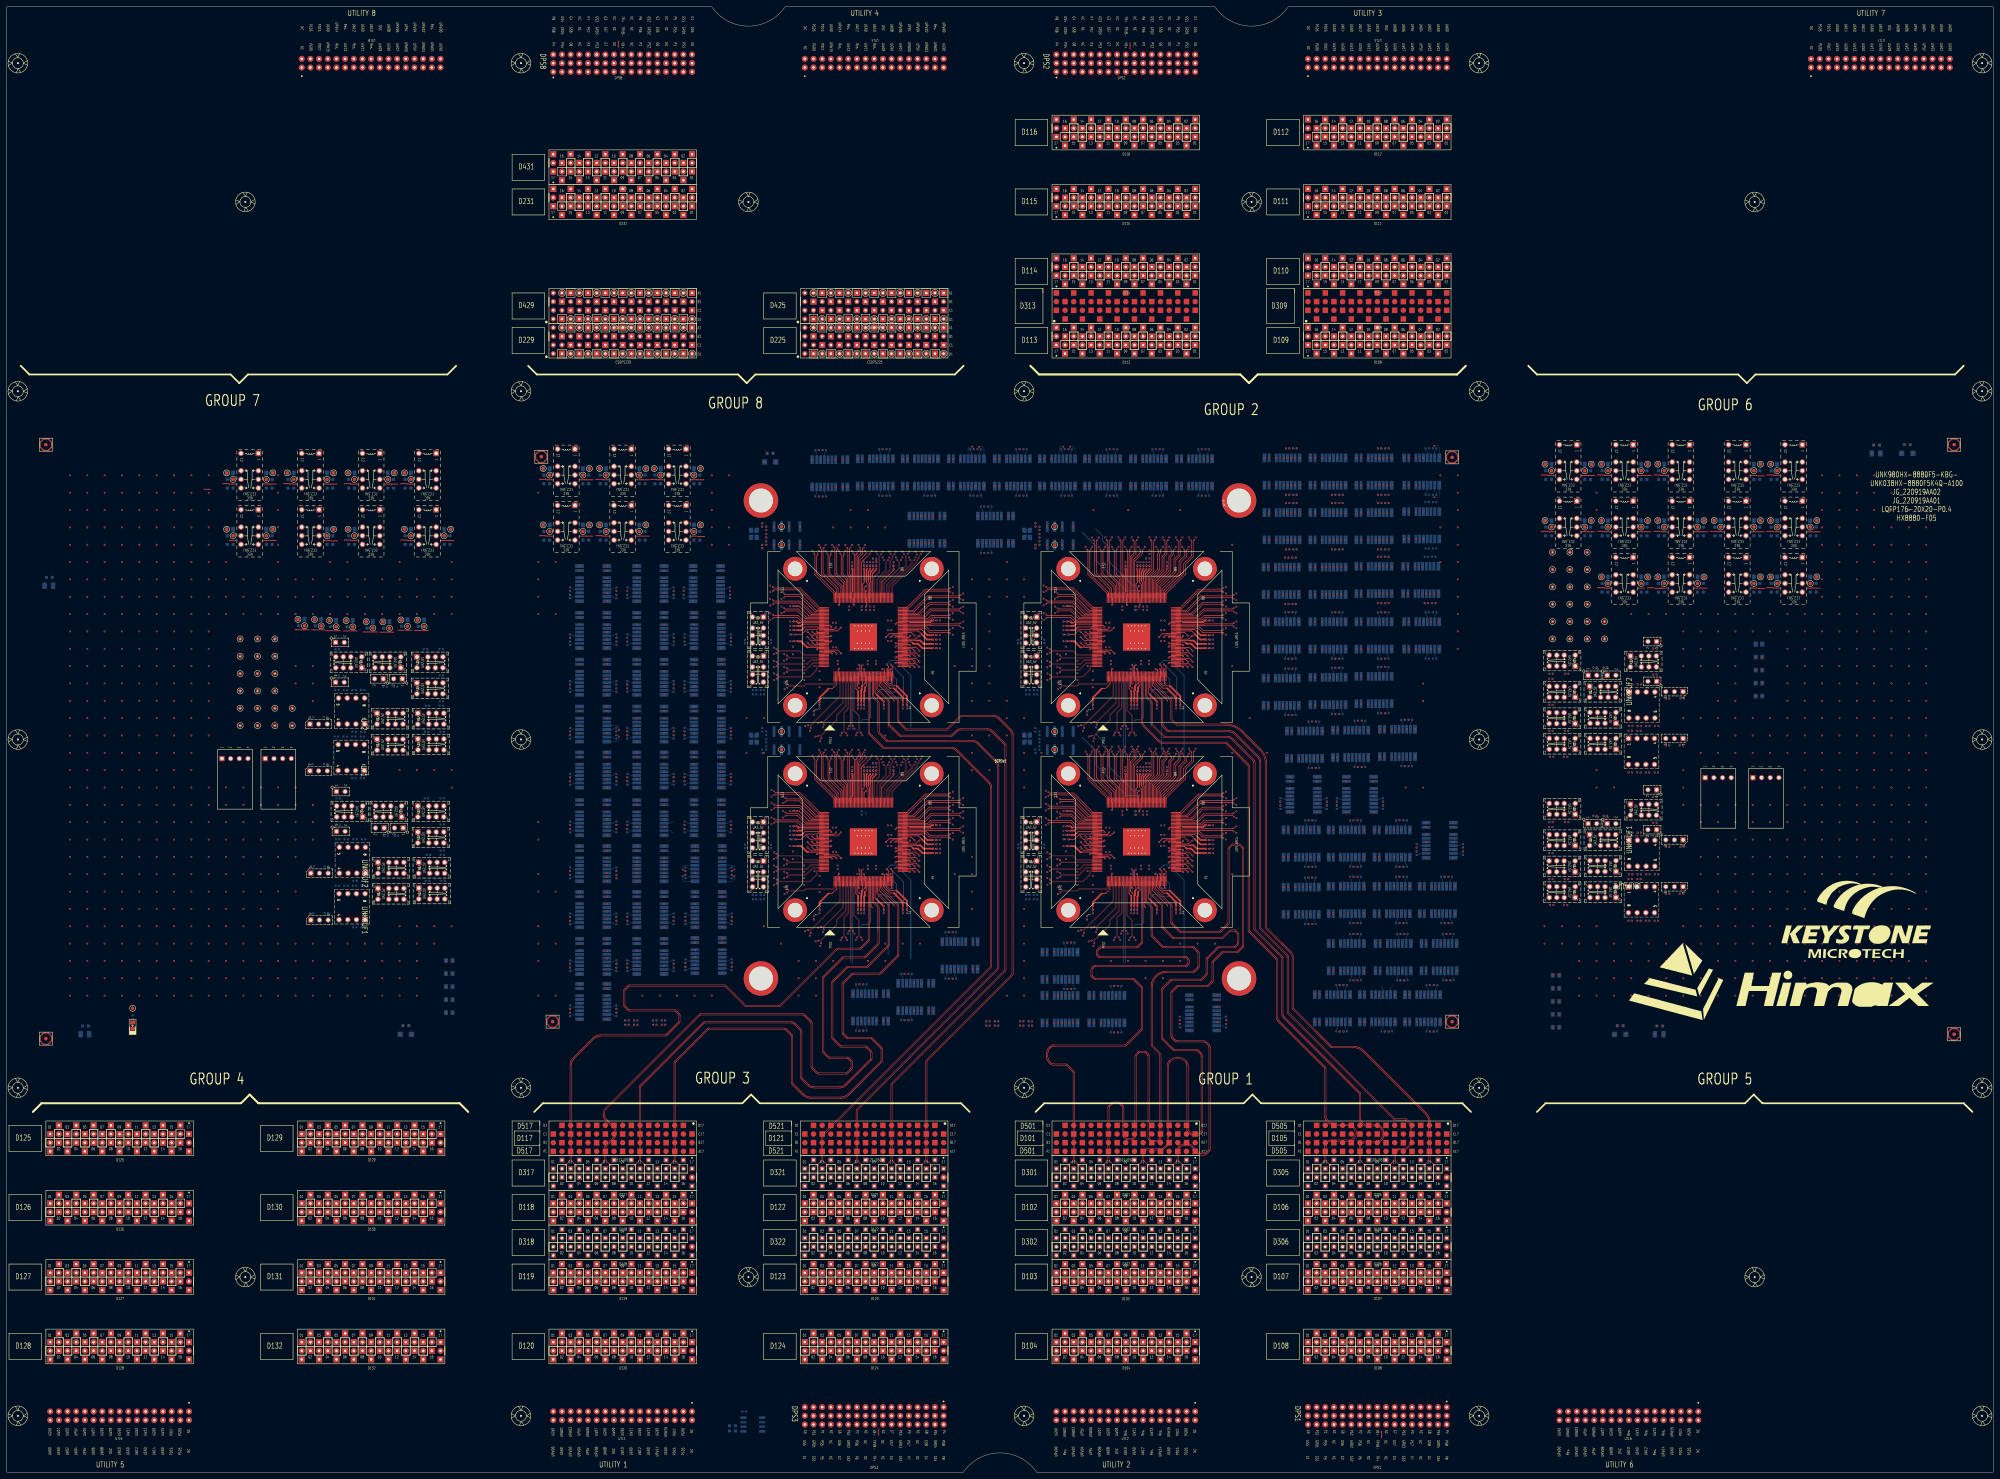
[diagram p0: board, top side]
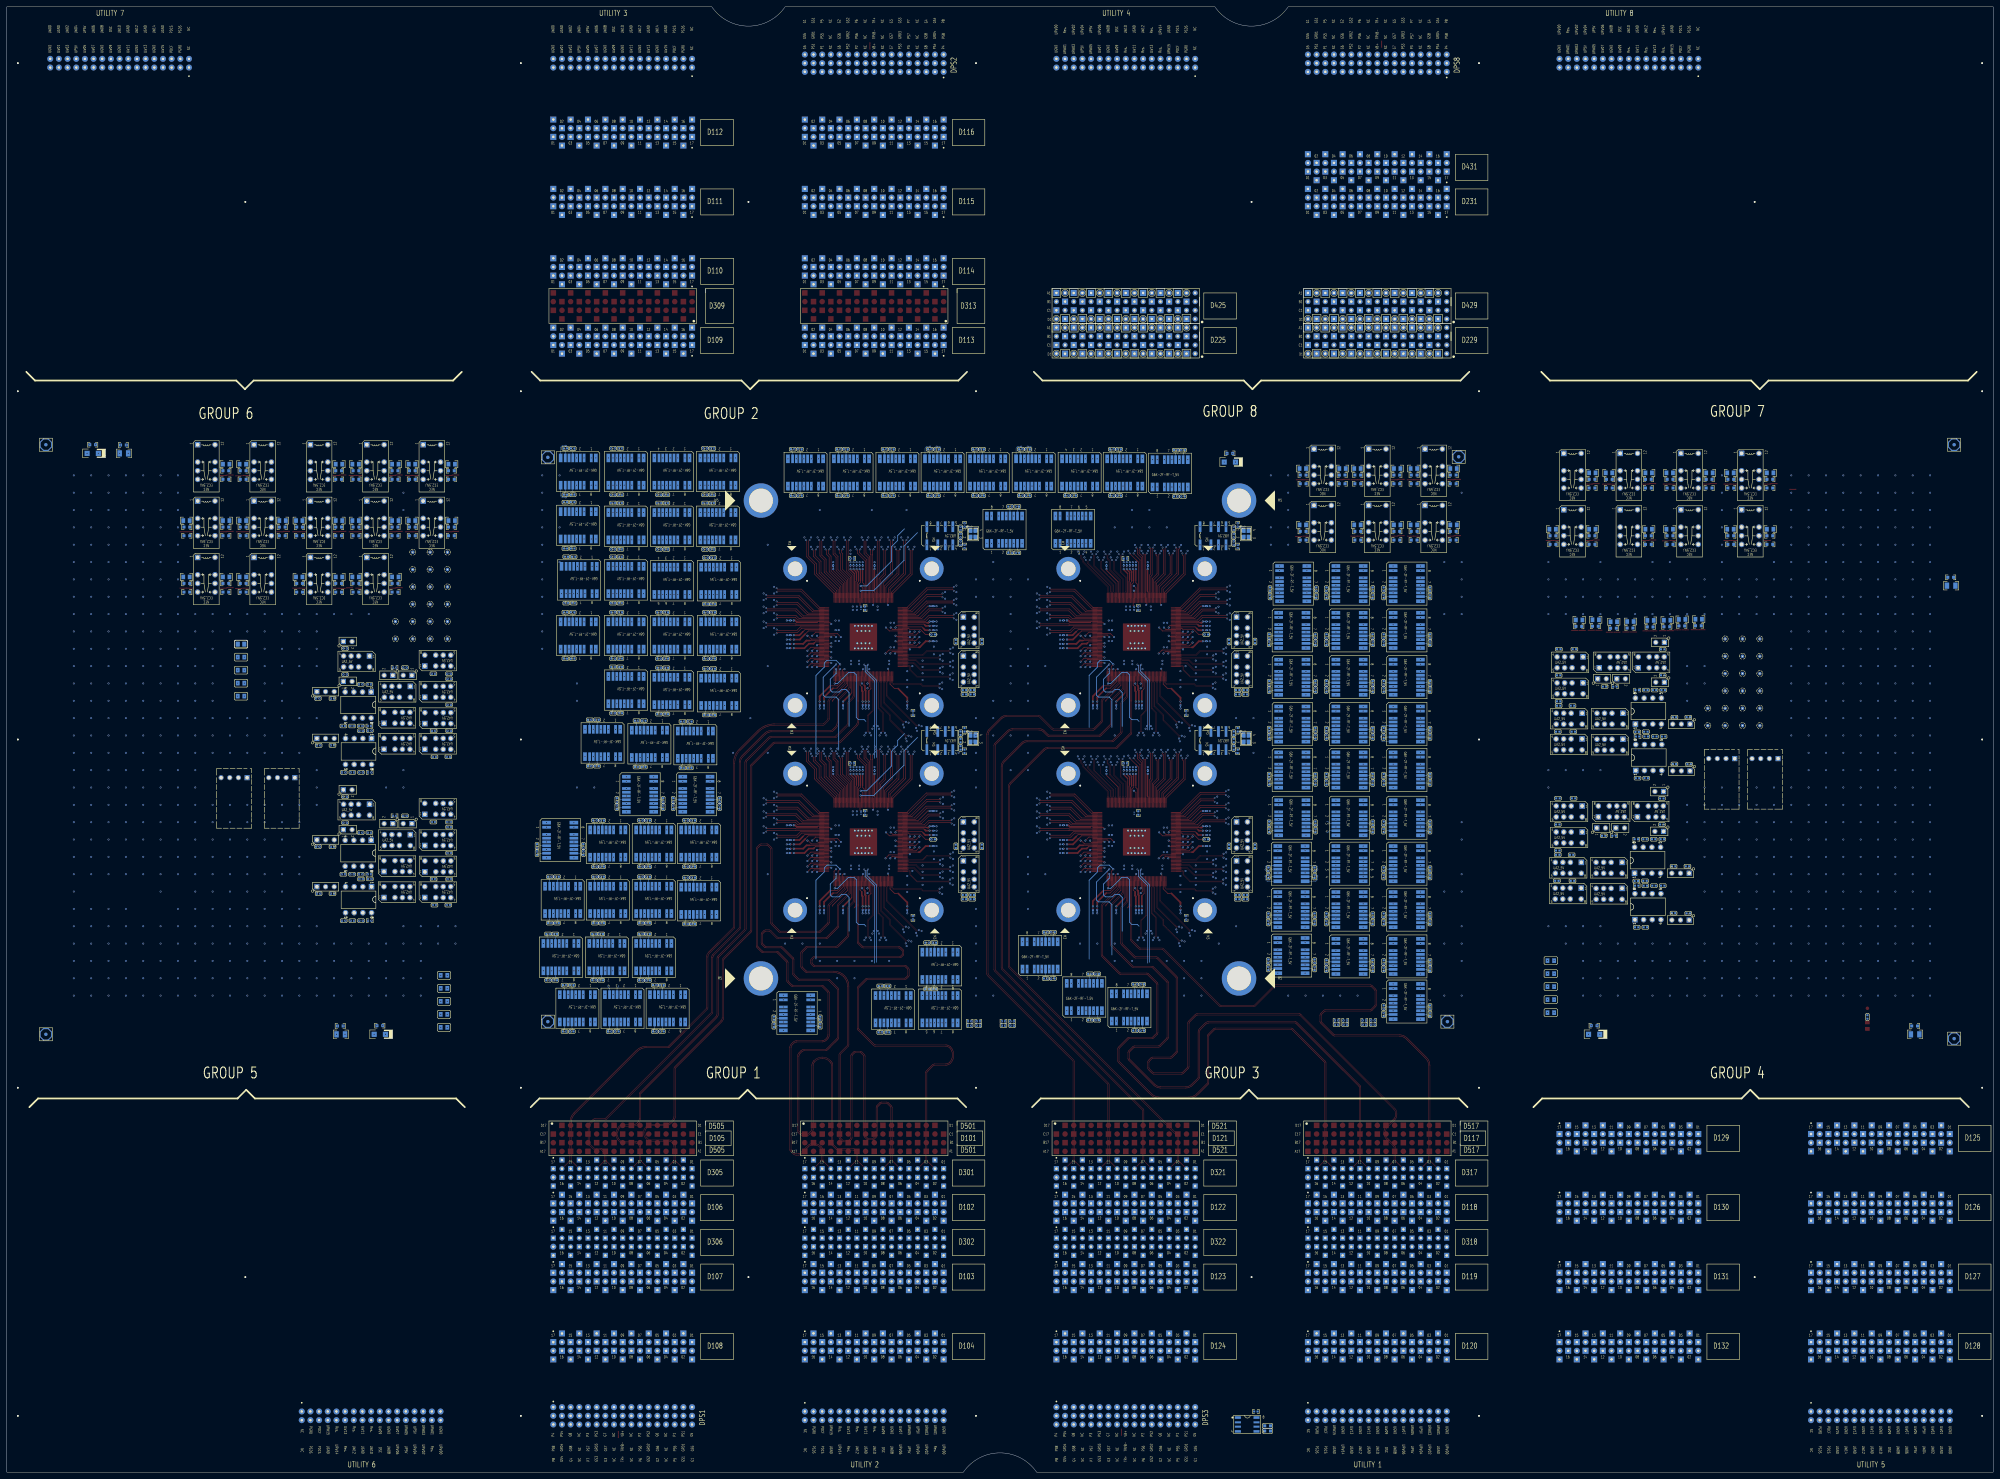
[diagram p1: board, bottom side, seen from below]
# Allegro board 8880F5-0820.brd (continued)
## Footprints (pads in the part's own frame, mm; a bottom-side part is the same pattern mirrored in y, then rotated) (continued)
R0402
  custom 0.15x0.15 smd: 1(-0.5,0) 2(0.5,0)
R0603
  rect 0.889x0.889 smd: 1(-0.85,0) 2(0.85,0)
RL_G6K2FRT_8P_5V_GR
  rect 0.813x2.54 smd: 1(-3.75,-4) 2(-0.55,-4) 3(1.65,-4) 4(3.85,-4) 5(3.85,4) 6(1.65,4) 7(-0.55,4) 8(-3.75,4) G2(-1.65,-4) G3(0.55,-4) G4(2.75,-4) G7(2.75,4) G8(0.55,4) G9(-1.65,4)
  rect 1.092x2.54 smd: G1(-5.1,-4) G5(5.2,-4) G6(5.2,4) G10(-5.1,4)
RL_NECEC2_10P_5V
  rect 1.626x1.626 hole 1.041: 1(6.35,2.54)
  round 1.626 hole 1.041: 3(1.27,2.54) 4(-1.27,2.54) 5(-3.81,2.54) 8(-3.81,-2.54) 9(-1.27,-2.54) 10(1.27,-2.54) 12(6.35,-2.54)
RL_NECUA2_5V_V3
  rect 1.626x1.626 hole 1.041: 1(3.6,1.6)
  round 1.626 hole 1.041: 2(0.4,1.6) 3(-1.8,1.6) 4(-4,1.6) 5(-4,-1.6) 6(-1.8,-1.6) 7(0.4,-1.6) 8(3.6,-1.6)
RL_NECUB2_5V
  rect 0.813x3.15 smd: 1(3.8,2.65) 2(0.6,2.65) 3(-1.6,2.65) 4(-3.8,2.65) 5(-3.8,-2.65) 6(-1.6,-2.65) 7(0.6,-2.65) 8(3.8,-2.65)
SK_LQFP176P_0P4MM_JG_HX8880
  round 0.508 hole 1.626 unplated: (-16.5,16.5) (-16.5,-16.5) (16.5,16.5) (16.5,-16.5)
  oval 3x0.28 smd: 1(-11.5,8.6) 2(-11.5,8.2) 3(-11.5,7.8) 4(-11.5,7.4) 5(-11.5,7) 6(-11.5,6.6) 7(-11.5,6.2) 8(-11.5,5.8) 9(-11.5,5.4) 10(-11.5,5) 11(-11.5,4.6) 12(-11.5,4.2) 13(-11.5,3.8) 14(-11.5,3.4) 15(-11.5,3) 16(-11.5,2.6) 17(-11.5,2.2) 18(-11.5,1.8) 19(-11.5,1.4) 20(-11.5,1) 21(-11.5,0.6) 22(-11.5,0.2) 23(-11.5,-0.2) 24(-11.5,-0.6) 25(-11.5,-1) 26(-11.5,-1.4) 27(-11.5,-1.8) 28(-11.5,-2.2) 29(-11.5,-2.6) 30(-11.5,-3) 31(-11.5,-3.4) 32(-11.5,-3.8) 33(-11.5,-4.2) 34(-11.5,-4.6) 35(-11.5,-5) 36(-11.5,-5.4) 37(-11.5,-5.8) 38(-11.5,-6.2) 39(-11.5,-6.6) 40(-11.5,-7) 41(-11.5,-7.4) 42(-11.5,-7.8) 43(-11.5,-8.2) 44(-11.5,-8.6) 89(11.5,-8.6) 90(11.5,-8.2) 91(11.5,-7.8) 92(11.5,-7.4) 93(11.5,-7) 94(11.5,-6.6) 95(11.5,-6.2) 96(11.5,-5.8) 97(11.5,-5.4) 98(11.5,-5) 99(11.5,-4.6) 100(11.5,-4.2) 101(11.5,-3.8) 102(11.5,-3.4) 103(11.5,-3) 104(11.5,-2.6) 105(11.5,-2.2) 106(11.5,-1.8) 107(11.5,-1.4) 108(11.5,-1) 109(11.5,-0.6) 110(11.5,-0.2) 111(11.5,0.2) 112(11.5,0.6) 113(11.5,1) 114(11.5,1.4) 115(11.5,1.8) 116(11.5,2.2) 117(11.5,2.6) 118(11.5,3) 119(11.5,3.4) 120(11.5,3.8) 121(11.5,4.2) 122(11.5,4.6) 123(11.5,5) 124(11.5,5.4) 125(11.5,5.8) 126(11.5,6.2) 127(11.5,6.6) 128(11.5,7) 129(11.5,7.4) 130(11.5,7.8) 131(11.5,8.2) 132(11.5,8.6)
  oval 0.28x3 smd: 45(-8.6,-11.5) 46(-8.2,-11.5) 47(-7.8,-11.5) 48(-7.4,-11.5) 49(-7,-11.5) 50(-6.6,-11.5) 51(-6.2,-11.5) 52(-5.8,-11.5) 53(-5.4,-11.5) 54(-5,-11.5) 55(-4.6,-11.5) 56(-4.2,-11.5) 57(-3.8,-11.5) 58(-3.4,-11.5) 59(-3,-11.5) 60(-2.6,-11.5) 61(-2.2,-11.5) 62(-1.8,-11.5) 63(-1.4,-11.5) 64(-1,-11.5) 65(-0.6,-11.5) 66(-0.2,-11.5) 67(0.2,-11.5) 68(0.6,-11.5) 69(1,-11.5) 70(1.4,-11.5) 71(1.8,-11.5) 72(2.2,-11.5) 73(2.6,-11.5) 74(3,-11.5) 75(3.4,-11.5) 76(3.8,-11.5) 77(4.2,-11.5) 78(4.6,-11.5) 79(5,-11.5) 80(5.4,-11.5) 81(5.8,-11.5) 82(6.2,-11.5) 83(6.6,-11.5) 84(7,-11.5) 85(7.4,-11.5) 86(7.8,-11.5) 87(8.2,-11.5) 88(8.6,-11.5) 133(8.6,11.5) 134(8.2,11.5) 135(7.8,11.5) 136(7.4,11.5) 137(7,11.5) 138(6.6,11.5) 139(6.2,11.5) 140(5.8,11.5) 141(5.4,11.5) 142(5,11.5) 143(4.6,11.5) 144(4.2,11.5) 145(3.8,11.5) 146(3.4,11.5) 147(3,11.5) 148(2.6,11.5) 149(2.2,11.5) 150(1.8,11.5) 151(1.4,11.5) 152(1,11.5) 153(0.6,11.5) 154(0.2,11.5) 155(-0.2,11.5) 156(-0.6,11.5) 157(-1,11.5) 158(-1.4,11.5) 159(-1.8,11.5) 160(-2.2,11.5) 161(-2.6,11.5) 162(-3,11.5) 163(-3.4,11.5) 164(-3.8,11.5) 165(-4.2,11.5) 166(-4.6,11.5) 167(-5,11.5) 168(-5.4,11.5) 169(-5.8,11.5) 170(-6.2,11.5) 171(-6.6,11.5) 172(-7,11.5) 173(-7.4,11.5) 174(-7.8,11.5) 175(-8.2,11.5) 176(-8.6,11.5)
  rect 8x8 smd: EP(0,0)
  round 0.61 hole 0.305: G1(-3.3,2.5) G2(-3.3,1.5) G3(-3.3,0.5) G4(-3.3,-0.5) G5(-3.3,-1.5) G6(-3.3,-2.5) G7(3.3,2.5) G8(3.3,1.5) G9(3.3,0.5) G10(3.3,-0.5) G11(3.3,-1.5) G12(3.3,-2.5) G13(-1.8,1.8) G14(-1.8,0.6) G15(-1.8,-0.6) G16(-1.8,-1.8) G17(1.8,1.8) G18(1.8,0.6) G19(1.8,-0.6) G20(1.8,-1.8)
  round 7 hole 4.293: NUT1(-20,20) NUT2(20,20) NUT3(-20,-20) NUT4(20,-20)
SO8_215X127MM
  rect 1.778x0.762 smd: 1(-2.731,2.032) 4(-2.731,-2.032) 5(2.731,-2.032) 8(2.731,2.032)
  rect 1.778x0.61 smd: 2(-2.731,0.635) 3(-2.731,-0.635) 6(2.731,-0.635) 7(2.731,0.635)
SOCKET_BASE_140X140_565100
  round 10.109 hole 7.01: NUT1(-70,70) NUT2(70,70) NUT3(70,-70) NUT4(-70,-70)
SOCKET_CODE
  round 0.051 smd: 1(0,0)
TP_040_T
  round 1.016 smd: 1(0,0)
TPL_040_014_TB
  round 1.016 hole 0.356: 1(0,0)
XTAL_2X2P5MM_4P
  rect 1.143x0.94 smd: 1(-0.825,-0.625) 2(0.825,-0.625) 3(0.825,0.625) 4(-0.825,0.625)
XTAL_3P2X2P5MM_4P_TXC_0201
  rect 1.4x1.2 smd: 1(-1.1,-0.85) 2(1.1,-0.85) 3(1.1,0.85) 4(-1.1,0.85)

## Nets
GND: BD29.1 BD30.1 BD31.1 BD32.1 BD33.1 BD34.1 BD35.1 BD36.1 BD37.1 BD38.1 BD39.1 BD40.1 BD41.1 BD42.1 BD43.1 BD44.1 C5.2 C6.2 C7.2 C8.2 C9.2 CA1.2 CA2.2 CA3.2 CA4.2 CA5.2 CA6.2 CA7.2 CA8.2 CA9.2 CA10.2 CA11.2 CA12.2 CA13.2 CA14.2 CA15.2 CA16.2 CA17.2 CA18.2 CA19.2 CA20.2 CA21.2 CA22.2 CA23.2 CA24.2 CA25.2 CA26.2 CA27.2 CA28.2 CA29.2 CA30.2 CA31.2 CA32.2 CA33.2 CA34.2 CA35.2 CA36.2 CA37.2 CA38.2 CA39.2 CA40.2 CC1.2 CC2.2 CC4.2 CC6.2 CC7.2 CC8.2 CC9.2 CC11.2 CC13.2 CC15.2 CC16.2 CC17.2 CC19.2 CC20.2 CC22.2 CC23.2 CC25.2 CC26.2 CC27.2 CC28.2 CC29.2 CC30.2 CC31.2 CC32.2 CC33.2 CC34.2 CC35.2 CC36.2 CC37.2 CC38.2 CC39.2 CC40.2 CC41.2 CC42.2 CD1.2 CD3.2 CD4.2 CD5.2 CD6.2 CD7.2 CD8.2 CD9.2 CD10.2 CD11.2 CD12.2 CD13.2 CD14.2 CD15.2 CD16.2 CD17.2 CD18.2 CD19.2 CD20.2 CD21.2 CD22.2 CD23.2 CD24.2 CD25.2 CSDPS225.B2 CSDPS225.B4 CSDPS225.B6 CSDPS225.B8 CSDPS225.B10 CSDPS225.B12 CSDPS225.B14 CSDPS225.B16 CSDPS225.C1 CSDPS225.C3 CSDPS225.C5 CSDPS225.C7 CSDPS225.C9 CSDPS225.C11 CSDPS225.C13 CSDPS225.C15 CSDPS229.B2 CSDPS229.B4 CSDPS229.B6 CSDPS229.B8 CSDPS229.B10 CSDPS229.B12 CSDPS229.B14 CSDPS229.B16 CSDPS229.C1 CSDPS229.C3 CSDPS229.C5 CSDPS229.C7 CSDPS229.C9 CSDPS229.C11 CSDPS229.C13 CSDPS229.C15 CSDPS425.B2 CSDPS425.B4 CSDPS425.B6 CSDPS425.B8 CSDPS425.B10 CSDPS425.B12 CSDPS425.B14 CSDPS425.B16 CSDPS425.C1 CSDPS425.C3 CSDPS425.C5 CSDPS425.C7 CSDPS425.C9 CSDPS425.C11 CSDPS425.C13 CSDPS425.C15 CSDPS429.B2 CSDPS429.B4 CSDPS429.B6 CSDPS429.B8 CSDPS429.B10 CSDPS429.B12 CSDPS429.B14 CSDPS429.B16 CSDPS429.C1 CSDPS429.C3 CSDPS429.C5 CSDPS429.C7 CSDPS429.C9 CSDPS429.C11 CSDPS429.C13 CSDPS429.C15 D102.A1 D102.A2 D102.A3 D102.A4 D102.A5 D102.A6 D102.A7 D102.A8 D102.A9 D102.A10 D102.A11 D102.A12 D102.A13 D102.A14 D102.A15 D102.A16 D102.B1 D102.B2 D102.B3 D102.B4 D102.B5 D102.B6 D102.B7 D102.B8 D102.B9 D102.B10 D102.B11 D102.B12 D102.B13 D102.B14 D102.B15 D102.B16 D103.A1 D103.A2 D103.A3 D103.A4 D103.A5 D103.A6 D103.A7 D103.A8 D103.A9 D103.A10 D103.A11 D103.A12 D103.A13 D103.A14 D103.A15 D103.A16 D103.B1 D103.B2 D103.B3 D103.B4 D103.B5 D103.B6 D103.B7 D103.B8 D103.B9 D103.B10 D103.B11 D103.B12 D103.B13 D103.B14 D103.B15 D103.B16 D104.A1 D104.A2 D104.A3 D104.A4 D104.A5 D104.A6 D104.A7 D104.A8 D104.A9 D104.A10 D104.A11 D104.A12 D104.A13 D104.A14 D104.A15 D104.A16 D104.B1 D104.B2 D104.B3 D104.B4 D104.B5 D104.B6 D104.B7 D104.B8 D104.B9 D104.B10 D104.B11 D104.B12 D104.B13 D104.B14 D104.B15 D104.B16 D106.A1 D106.A2 D106.A3 D106.A4 D106.A5 D106.A6 D106.A7 D106.A8 D106.A9 D106.A10 D106.A11 D106.A12 D106.A13 D106.A14 D106.A15 D106.A16 D106.B1 D106.B2 D106.B3 D106.B4 D106.B5 D106.B6 D106.B7 D106.B8 D106.B9 D106.B10 D106.B11 D106.B12 D106.B13 D106.B14 D106.B15 D106.B16 D107.A1 D107.A2 D107.A3 D107.A4 D107.A5 D107.A6 D107.A7 D107.A8 D107.A9 D107.A10 D107.A11 D107.A12 D107.A13 D107.A14 D107.A15 D107.A16 D107.B1 D107.B2 D107.B3 D107.B4 D107.B5 D107.B6 D107.B7 D107.B8 D107.B9 D107.B10 D107.B11 D107.B12 D107.B13 D107.B14 D107.B15 D107.B16 D108.A1 D108.A2 D108.A3 D108.A4 D108.A5 D108.A6 D108.A7 D108.A8 D108.A9 D108.A10 D108.A11 D108.A12 D108.A13 D108.A14 D108.A15 D108.A16 D108.B1 D108.B2 D108.B3 D108.B4 D108.B5 D108.B6 D108.B7 D108.B8 D108.B9 D108.B10 D108.B11 D108.B12 D108.B13 D108.B14 D108.B15 D108.B16 D109.A1 D109.A2 D109.A3 D109.A4 D109.A5 D109.A6 D109.A7 D109.A8 D109.A9 D109.A10 D109.A11 D109.A12 D109.A13 D109.A14 D109.A15 D109.A16 D109.B1 D109.B2 D109.B3 D109.B4 D109.B5 D109.B6 D109.B7 D109.B8 D109.B9 D109.B10 D109.B11 D109.B12 D109.B13 D109.B14 D109.B15 D109.B16 D110.A1 D110.A2 D110.A3 D110.A4 D110.A5 D110.A6 D110.A7 D110.A8 D110.A9 D110.A10 D110.A11 D110.A12 D110.A13 D110.A14 D110.A15 D110.A16 D110.B1 D110.B2 D110.B3 D110.B4 D110.B5 D110.B6 D110.B7 D110.B8 D110.B9 D110.B10 D110.B11 D110.B12 D110.B13 D110.B14 D110.B15 D110.B16 D111.A1 D111.A2 D111.A3 D111.A4 D111.A5 D111.A6 D111.A7 D111.A8 D111.A9 D111.A10 D111.A11 D111.A12 D111.A13 D111.A14 D111.A15 D111.A16 D111.B1 D111.B2 D111.B3 D111.B4 D111.B5 D111.B6 D111.B7 D111.B8 D111.B9 D111.B10 D111.B11 D111.B12 D111.B13 D111.B14 D111.B15 D111.B16 D112.A1 D112.A2 D112.A3 D112.A4 D112.A5 D112.A6 D112.A7 D112.A8 D112.A9 D112.A10 D112.A11 D112.A12 D112.A13 D112.A14 D112.A15 D112.A16 D112.B1 D112.B2 D112.B3 D112.B4 D112.B5 D112.B6 D112.B7 D112.B8 D112.B9 D112.B10 D112.B11 D112.B12 D112.B13 D112.B14 D112.B15 D112.B16 D113.A1 D113.A2 D113.A3 D113.A4 D113.A5 D113.A6 D113.A7 D113.A8 D113.A9 D113.A10 D113.A11 D113.A12 D113.A13 D113.A14 D113.A15 D113.A16 D113.B1 D113.B2 D113.B3 D113.B4 D113.B5 D113.B6 D113.B7 D113.B8 D113.B9 D113.B10 D113.B11 D113.B12 D113.B13 D113.B14 D113.B15 D113.B16 D114.A1 D114.A2 D114.A3 D114.A4 D114.A5 D114.A6 D114.A7 D114.A8 D114.A9 D114.A10 D114.A11 D114.A12 D114.A13 D114.A14 D114.A15 D114.A16 D114.B1 D114.B2 D114.B3 D114.B4 D114.B5 D114.B6 D114.B7 D114.B8 D114.B9 D114.B10 D114.B11 D114.B12 D114.B13 D114.B14 D114.B15 D114.B16 D115.A1 D115.A2 D115.A3 D115.A4 D115.A5 D115.A6 D115.A7 D115.A8 D115.A9 D115.A10 D115.A11 D115.A12 D115.A13 D115.A14 D115.A15 D115.A16 D115.B1 D115.B2 D115.B3 D115.B4 D115.B5 D115.B6 D115.B7 D115.B8 D115.B9 D115.B10 D115.B11 D115.B12 D115.B13 D115.B14 D115.B15 D115.B16 D116.A1 D116.A2 D116.A3 D116.A4 D116.A5 D116.A6 D116.A7 D116.A8 D116.A9 D116.A10 D116.A11 D116.A12 D116.A13 D116.A14 D116.A15 D116.A16 D116.B1 D116.B2 D116.B3 D116.B4 D116.B5 D116.B6 D116.B7 D116.B8 D116.B9 D116.B10 D116.B11 D116.B12 D116.B13 D116.B14 D116.B15 D116.B16 D118.A1 D118.A2 D118.A3 D118.A4 D118.A5 D118.A6 D118.A7 D118.A8 D118.A9 D118.A10 D118.A11 D118.A12 D118.A13 D118.A14 D118.A15 D118.A16 D118.B1 D118.B2 D118.B3 D118.B4 D118.B5 D118.B6 D118.B7 D118.B8 D118.B9 D118.B10 D118.B11 D118.B12 D118.B13 D118.B14 D118.B15 D118.B16 D119.A1 D119.A2 D119.A3 D119.A4 D119.A5 D119.A6 D119.A7 D119.A8 D119.A9 D119.A10 D119.A11 D119.A12 D119.A13 D119.A14 D119.A15 D119.A16 D119.B1 D119.B2 D119.B3 D119.B4 D119.B5 D119.B6 D119.B7 D119.B8 D119.B9 D119.B10 D119.B11 D119.B12 D119.B13 D119.B14 D119.B15 D119.B16 D120.A1 D120.A2 D120.A3 D120.A4 D120.A5 D120.A6 D120.A7 D120.A8 D120.A9 D120.A10 D120.A11 D120.A12 D120.A13 D120.A14 D120.A15 D120.A16 D120.B1 D120.B2 D120.B3 D120.B4 D120.B5 D120.B6 D120.B7 D120.B8 D120.B9 D120.B10 D120.B11 D120.B12 D120.B13 D120.B14 D120.B15 D120.B16 D122.A1 D122.A2 D122.A3 D122.A4 D122.A5 D122.A6 D122.A7 D122.A8 D122.A9 D122.A10 D122.A11 D122.A12 D122.A13 D122.A14 D122.A15 D122.A16 D122.B1 D122.B2 D122.B3 D122.B4 D122.B5 D122.B6 D122.B7 D122.B8 D122.B9 D122.B10 D122.B11 D122.B12 D122.B13 D122.B14 D122.B15 D122.B16 D123.A1 D123.A2 D123.A3 D123.A4 D123.A5 D123.A6 D123.A7 D123.A8 D123.A9 D123.A10 D123.A11 D123.A12 D123.A13 D123.A14 D123.A15 D123.A16 D123.B1 D123.B2 D123.B3 D123.B4 D123.B5 D123.B6 D123.B7 D123.B8 D123.B9 D123.B10 D123.B11 D123.B12 D123.B13 D123.B14 D123.B15 D123.B16 D124.A1 D124.A2 D124.A3 D124.A4 D124.A5 D124.A6 D124.A7 D124.A8 D124.A9 D124.A10 D124.A11 D124.A12 D124.A13 D124.A14 D124.A15 D124.A16 D124.B1 D124.B2 D124.B3 D124.B4 D124.B5 D124.B6 D124.B7 D124.B8 D124.B9 D124.B10 D124.B11 D124.B12 D124.B13 D124.B14 D124.B15 D124.B16 D125.A1 D125.A2 D125.A3 D125.A4 D125.A5 D125.A6 D125.A7 D125.A8 D125.A9 D125.A10 D125.A11 D125.A12 D125.A13 D125.A14 D125.A15 D125.A16 D125.B1 D125.B2 D125.B3 D125.B4 D125.B5 D125.B6 D125.B7 D125.B8 D125.B9 D125.B10 D125.B11 D125.B12 D125.B13 D125.B14 D125.B15 D125.B16 D126.A1 D126.A2 D126.A3 D126.A4 D126.A5 D126.A6 D126.A7 D126.A8 D126.A9 D126.A10 D126.A11 D126.A12 D126.A13 D126.A14 D126.A15 D126.A16 D126.B1 D126.B2 D126.B3 D126.B4 D126.B5 D126.B6 D126.B7 D126.B8 D126.B9 D126.B10 D126.B11 D126.B12 D126.B13 D126.B14 D126.B15 D126.B16 D127.A1 D127.A2 D127.A3 D127.A4 D127.A5 D127.A6 D127.A7 D127.A8 D127.A9 D127.A10 D127.A11 D127.A12 D127.A13 D127.A14 D127.A15 D127.A16 D127.B1 D127.B2 D127.B3 D127.B4 D127.B5 D127.B6 D127.B7 D127.B8 D127.B9 D127.B10 D127.B11 D127.B12 D127.B13 D127.B14 D127.B15 D127.B16 D128.A1 D128.A2 D128.A3 D128.A4 D128.A5 D128.A6 D128.A7 D128.A8 D128.A9 D128.A10 D128.A11 D128.A12 D128.A13 D128.A14 D128.A15 D128.A16 D128.B1 D128.B2 D128.B3 D128.B4 D128.B5 D128.B6 D128.B7 D128.B8 D128.B9 D128.B10 D128.B11 D128.B12 D128.B13 D128.B14 D128.B15 D128.B16 D129.A1 D129.A2 D129.A3 D129.A4 D129.A5 D129.A6 D129.A7 D129.A8 D129.A9 D129.A10 D129.A11 D129.A12 D129.A13 D129.A14 D129.A15 D129.A16 D129.B1 D129.B2 D129.B3 D129.B4 D129.B5 D129.B6 D129.B7 D129.B8 D129.B9 D129.B10 D129.B11 D129.B12 D129.B13 D129.B14 D129.B15 D129.B16 D130.A1 D130.A2 D130.A3 D130.A4 D130.A5 D130.A6 D130.A7 D130.A8 D130.A9 D130.A10 D130.A11 D130.A12 D130.A13 D130.A14 D130.A15 D130.A16 D130.B1 D130.B2 D130.B3 D130.B4 D130.B5 D130.B6 D130.B7 D130.B8 D130.B9 D130.B10 D130.B11 D130.B12 D130.B13 D130.B14 D130.B15 D130.B16 D131.A1 D131.A2 D131.A3 D131.A4 D131.A5 D131.A6 D131.A7 D131.A8 D131.A9 D131.A10 D131.A11 D131.A12 D131.A13 D131.A14 D131.A15 D131.A16 D131.B1 D131.B2 D131.B3 D131.B4 D131.B5 D131.B6 D131.B7 D131.B8 D131.B9 D131.B10 D131.B11 D131.B12 D131.B13 D131.B14 D131.B15 D131.B16 D132.A1 D132.A2 D132.A3 D132.A4 D132.A5 D132.A6 D132.A7 D132.A8 D132.A9 D132.A10 D132.A11 D132.A12 D132.A13 D132.A14 D132.A15 D132.A16 D132.B1 D132.B2 D132.B3 D132.B4 D132.B5 D132.B6 D132.B7 D132.B8 D132.B9 D132.B10 D132.B11 D132.B12 D132.B13 D132.B14 D132.B15 D132.B16 D231.A1 D231.A2 D231.A3 D231.A4 D231.A5 D231.A6 D231.A7 D231.A8 D231.A9 D231.A10 D231.A11 D231.A12 D231.A13 D231.A14 D231.A15 D231.A16 D231.A17 D231.B1 D231.B2 D231.B3 D231.B4 D231.B5 D231.B6 D231.B7 D231.B8 D231.B9 D231.B10 D231.B11 D231.B12 D231.B13 D231.B14 D231.B15 D231.B16 D231.B17 D301.A1 D301.A2 D301.A3 D301.A4 D301.A5 D301.A6 D301.A7 D301.A8 D301.A9 D301.A10 D301.A11 D301.A12 D301.A13 D301.A14 D301.A15 D301.A16 D301.B1 D301.B2 D301.B3 D301.B4 D301.B5 D301.B6 D301.B7 D301.B8 D301.B9 D301.B10 D301.B11 D301.B12 D301.B13 D301.B14 D301.B15 D301.B16 D302.A1 D302.A2 D302.A3 D302.A4 D302.A5 D302.A6 D302.A7 D302.A8 D302.A9 D302.A10 D302.A11 D302.A12 D302.A13 D302.A14 D302.A15 D302.A16 D302.B1 D302.B2 D302.B3 D302.B4 D302.B5 D302.B6 D302.B7 D302.B8 D302.B9 D302.B10 D302.B11 D302.B12 D302.B13 D302.B14 D302.B15 D302.B16 D305.A1 D305.A2 D305.A3 D305.A4 D305.A5 D305.A6 D305.A7 D305.A8 D305.A9 D305.A10 D305.A11 D305.A12 D305.A13 D305.A14 D305.A15 D305.A16 D305.B1 D305.B2 D305.B3 D305.B4 D305.B5 D305.B6 D305.B7 D305.B8 D305.B9 D305.B10 D305.B11 D305.B12 D305.B13 D305.B14 D305.B15 D305.B16 D306.A1 D306.A2 D306.A3 D306.A4 D306.A5 D306.A6 D306.A7 D306.A8 D306.A9 D306.A10 D306.A11 D306.A12 D306.A13 D306.A14 D306.A15 D306.A16 D306.B1 D306.B2 D306.B3 D306.B4 D306.B5 D306.B6 D306.B7 D306.B8 D306.B9 D306.B10 D306.B11 D306.B12 D306.B13 D306.B14 D306.B15 D306.B16 D317.A1 D317.A2 D317.A3 D317.A4 D317.A5 D317.A6 D317.A7 D317.A8 D317.A9 D317.A10 D317.A11 D317.A12 D317.A13 D317.A14 D317.A15 D317.A16 D317.B1 D317.B2 D317.B3 D317.B4 D317.B5 D317.B6 D317.B7 D317.B8 D317.B9 D317.B10 D317.B11 D317.B12 D317.B13 D317.B14 D317.B15 D317.B16 D318.A1 D318.A2 D318.A3 D318.A4 D318.A5 D318.A6 D318.A7 D318.A8 D318.A9 D318.A10 D318.A11 D318.A12 D318.A13 D318.A14 D318.A15 D318.A16 D318.B1 D318.B2 D318.B3 D318.B4 D318.B5 D318.B6 D318.B7 D318.B8 D318.B9 D318.B10 D318.B11 D318.B12 D318.B13 D318.B14 D318.B15 D318.B16 D321.A1 D321.A2 D321.A3 D321.A4 D321.A5 D321.A6 D321.A7 D321.A8 D321.A9 D321.A10 D321.A11 D321.A12 D321.A13 D321.A14 D321.A15 D321.A16 D321.B1 D321.B2 D321.B3 D321.B4 D321.B5 D321.B6 D321.B7 D321.B8 D321.B9 D321.B10 D321.B11 D321.B12 D321.B13 D321.B14 D321.B15 D321.B16 D322.A1 D322.A2 D322.A3 D322.A4 D322.A5 D322.A6 D322.A7 D322.A8 D322.A9 D322.A10 D322.A11 D322.A12 D322.A13 D322.A14 D322.A15 D322.A16 D322.B1 D322.B2 D322.B3 D322.B4 D322.B5 D322.B6 D322.B7 D322.B8 D322.B9 D322.B10 D322.B11 D322.B12 D322.B13 D322.B14 D322.B15 D322.B16 D431.A1 D431.A2 D431.A3 D431.A4 D431.A5 D431.A6 D431.A7 D431.A8 D431.A9 D431.A10 D431.A11 D431.A12 D431.A13 D431.A14 D431.A15 D431.A16 D431.A17 D431.B1 D431.B2 D431.B3 D431.B4 D431.B5 D431.B6 D431.B7 D431.B8 D431.B9 D431.B10 D431.B11 D431.B12 D431.B13 D431.B14 D431.B15 D431.B16 D431.B17 DPS1.A01 DPS1.A05 DPS1.A11 DPS1.A15 DPS1.C01 DPS1.C05 DPS1.C11 DPS1.C15 DPS2.A01 DPS2.A05 DPS2.A11 DPS2.A15 DPS2.C01 DPS2.C05 DPS2.C11 DPS2.C15 DPS3.A01 DPS3.A05 DPS3.A11 DPS3.A15 DPS3.C01 DPS3.C05 DPS3.C11 DPS3.C15 DPS8.A01 DPS8.A05 DPS8.A11 DPS8.A15 DPS8.C01 DPS8.C05 DPS8.C11 DPS8.C15 GND1.1(TP) GND2.1(TP) GND3.1(TP) GND4.1(TP) GND5.1(TP) GND6.1(TP) GND7.1(TP) GND8.1(TP) GND9.1(TP) GND10.1(TP) GND11.1(TP) GND12.1(TP) GND13.1(TP) GND14.1(TP) K1.G1 K1.G2 K1.G3 K1.G4 K1.G5 K1.G6 K1.G7 K1.G8 K1.G9 K1.G10 K2.G1 K2.G2 K2.G3 K2.G4 K2.G5 K2.G6 K2.G7 K2.G8 K2.G9 K2.G10 K3.G1 K3.G2 K3.G3 K3.G4 K3.G5 K3.G6 K3.G7 K3.G8 K3.G9 K3.G10 K4.G1 K4.G2 K4.G3 K4.G4 K4.G5 K4.G6 K4.G7 K4.G8 K4.G9 K4.G10 K5.G1 K5.G2 K5.G3 K5.G4 K5.G5 K5.G6 K5.G7 K5.G8 K5.G9 K5.G10 K6.G1 K6.G2 K6.G3 K6.G4 K6.G5 K6.G6 K6.G7 K6.G8 K6.G9 K6.G10 K7.G1 K7.G2 K7.G3 K7.G4 K7.G5 K7.G6 K7.G7 K7.G8 K7.G9 K7.G10 K8.G1 K8.G2 K8.G3 K8.G4 K8.G5 K8.G6 K8.G7 K8.G8 K8.G9 K8.G10 K11.G1 K11.G2 K11.G3 K11.G4 K11.G5 K11.G6 K11.G7 K11.G8 K11.G9 K11.G10 K16.G1 K16.G2 K16.G3 K16.G4 K16.G5 K16.G6 K16.G7 K16.G8 K16.G9 K16.G10 K17.G1 K17.G2 K17.G3 K17.G4 K17.G5 K17.G6 K17.G7 K17.G8 K17.G9 K17.G10 K21.G1 K21.G2 K21.G3 K21.G4 K21.G5 K21.G6 K21.G7 K21.G8 K21.G9 K21.G10 K22.G1 K22.G2 K22.G3 K22.G4 K22.G5 K22.G6 K22.G7 K22.G8 K22.G9 K22.G10 K23.G1 K23.G2 K23.G3 K23.G4 K23.G5 K23.G6 K23.G7 K23.G8 K23.G9 K23.G10 K24.G1 K24.G2 K24.G3 K24.G4 K24.G5 K24.G6 K24.G7 K24.G8 K24.G9 K24.G10 K25.G1 K25.G2 K25.G3 K25.G4 K25.G5 K25.G6 K25.G7 K25.G8 K25.G9 K25.G10 K26.G1 K26.G2 K26.G3 K26.G4 K26.G5 K26.G6 K26.G7 K26.G8 K26.G9 K26.G10 K27.G1 K27.G2 K27.G3 K27.G4 K27.G5 K27.G6 K27.G7 K27.G8 K27.G9 K27.G10 K29.G1 K29.G2 K29.G3 K29.G4 K29.G5 K29.G6 K29.G7 K29.G8 K29.G9 K29.G10 K30.G1 K30.G2 K30.G3 K30.G4 K30.G5 K30.G6 K30.G7 K30.G8 K30.G9 K30.G10 K43.G1 K43.G2 K43.G3 K43.G4 K43.G5 K43.G6 K43.G7 K43.G8 K43.G9 K43.G10 R2.1 R3.2 R86.2 R93.2 R117.2 R131.2 R132.2 S1_I2C.4 S2_I2C.4 S3_I2C.4 S4_I2C.4 SB1.1 SB2.1 SB3.1 SB8.1 SH2.1 SH4.1 SH6.1 SH8.1 SH9.1 SH11.1 SH13.1 SH15.1 SH17.1 SH19.1 SH21.1 SH24.1 SH26.1 SH28.1 SITE1.4(GND-1) SITE1.23(VSS-1) SITE1.28(AVSS-1) SITE1.34(AVSS-2) SITE1.38(GND-2) SITE1.62(VSS-2) SITE1.108(GND-3) SITE1.128(GND-4) SITE1.146(VSS11_C) SITE1.EP(EP(GND)) SITE1.G1 SITE1.G2 SITE1.G3 SITE1.G4 SITE1.G5 SITE1.G6 SITE1.G7 SITE1.G8 SITE1.G9 SITE1.G10 SITE1.G11 SITE1.G12 SITE1.G13 SITE1.G14 SITE1.G15 SITE1.G16 SITE1.G17 SITE1.G18 SITE1.G19 SITE1.G20 SITE2.4(GND-1) SITE2.23(VSS-1) SITE2.28(AVSS-1) SITE2.34(AVSS-2) SITE2.38(GND-2) SITE2.62(VSS-2) SITE2.108(GND-3) SITE2.128(GND-4) SITE2.146(VSS11_C) SITE2.EP(EP(GND)) SITE2.G1 SITE2.G2 SITE2.G3 SITE2.G4 SITE2.G5 SITE2.G6 SITE2.G7 SITE2.G8 SITE2.G9 SITE2.G10 SITE2.G11 SITE2.G12 SITE2.G13 SITE2.G14 SITE2.G15 SITE2.G16 SITE2.G17 SITE2.G18 SITE2.G19 SITE2.G20 SITE3.4(GND-1) SITE3.23(VSS-1) SITE3.28(AVSS-1) SITE3.34(AVSS-2) SITE3.38(GND-2) SITE3.62(VSS-2) SITE3.108(GND-3) SITE3.128(GND-4) SITE3.146(VSS11_C) SITE3.EP(EP(GND)) SITE3.G1 SITE3.G2 SITE3.G3 SITE3.G4 SITE3.G5 SITE3.G6 SITE3.G7 SITE3.G8 SITE3.G9 SITE3.G10 SITE3.G11 SITE3.G12 SITE3.G13 SITE3.G14 SITE3.G15 SITE3.G16 SITE3.G17 SITE3.G18 SITE3.G19 SITE3.G20 SITE4.4(GND-1) SITE4.23(VSS-1) SITE4.28(AVSS-1) SITE4.34(AVSS-2) SITE4.38(GND-2) SITE4.62(VSS-2) SITE4.108(GND-3) SITE4.128(GND-4) SITE4.146(VSS11_C) SITE4.EP(EP(GND)) SITE4.G1 SITE4.G2 SITE4.G3 SITE4.G4 SITE4.G5 SITE4.G6 SITE4.G7 SITE4.G8 SITE4.G9 SITE4.G10 SITE4.G11 SITE4.G12 SITE4.G13 SITE4.G14 SITE4.G15 SITE4.G16 SITE4.G17 SITE4.G18 SITE4.G19 SITE4.G20 U1.4(GND) U2.4(GND) UNK2C5.2 UNK2C6.2 UNK2C7.2 UNK2C8.2 UNK2C9.2 UNK2CA1.2 UNK2CA2.2 UNK2CA3.2 UNK2CA4.2 UNK2CA5.2 UNK2CA6.2 UNK2CA7.2 UNK2CA8.2 UNK2CA9.2 UNK2CA10.2 UNK2CA11.2 UNK2CA12.2 UNK2CA13.2 UNK2CA14.2 UNK2CA15.2 UNK2CA16.2 UNK2CA17.2 UNK2CA18.2 UNK2CA19.2 UNK2CA20.2 UNK2CA21.2 UNK2CA22.2 UNK2CA23.2 UNK2CA24.2 UNK2CA25.2 UNK2CA26.2 UNK2CA27.2 UNK2CA28.2 UNK2CA29.2 UNK2CA30.2 UNK2CA31.2 UNK2CA32.2 UNK2CA33.2 UNK2CA34.2 UNK2CA35.2 UNK2CA36.2 UNK2CA37.2 UNK2CA38.2 UNK2CA39.2 UNK2CA40.2 UNK2CC1.2 UNK2CC2.2 UNK2CC4.2 UNK2CC6.2 UNK2CC7.2 UNK2CC8.2 UNK2CC9.2 UNK2CC11.2 UNK2CC13.2 UNK2CC15.2 UNK2CC16.2 UNK2CC17.2 UNK2CC19.2 UNK2CC20.2 UNK2CC22.2 UNK2CC23.2 UNK2CC25.2 UNK2CC26.2 UNK2CC27.2 UNK2CC28.2 UNK2CC29.2 UNK2CC30.2 UNK2CC31.2 UNK2CC32.2 UNK2CC33.2 UNK2CC34.2 UNK2CC35.2 UNK2CC36.2 UNK2CC37.2 UNK2CC38.2 UNK2CC39.2 UNK2CC40.2 UNK2CC41.2 UNK2CC42.2 UNK2CD1.2 UNK2CD3.2 UNK2CD4.2 UNK2CD5.2 UNK2CD6.2 UNK2CD7.2 UNK2CD8.2 UNK2CD9.2 UNK2CD10.2 UNK2CD11.2 UNK2CD12.2 UNK2CD13.2 UNK2CD14.2 UNK2CD15.2 UNK2CD16.2 UNK2CD17.2 UNK2CD18.2 UNK2CD19.2 UNK2CD20.2 UNK2CD21.2 UNK2CD22.2 UNK2CD23.2 UNK2CD24.2 UNK2CD25.2 UNK2GND1.1 UNK2GND2.1 UNK2GND3.1 UNK2GND4.1 UNK2GND5.1 UNK2GND6.1 UNK2GND7.1 UNK2GND8.1 UNK2GND9.1 UNK2GND10.1 UNK2GND11.1 UNK2GND12.1 UNK2GND13.1 UNK2GND14.1 UNK2K1.G1 UNK2K1.G2 UNK2K1.G3 UNK2K1.G4 UNK2K1.G5 UNK2K1.G6 UNK2K1.G7 UNK2K1.G8 UNK2K1.G9 UNK2K1.G10 UNK2K2.G1 UNK2K2.G2 UNK2K2.G3 UNK2K2.G4 UNK2K2.G5 UNK2K2.G6 UNK2K2.G7 UNK2K2.G8 UNK2K2.G9 UNK2K2.G10 UNK2K3.G1 UNK2K3.G2 UNK2K3.G3 UNK2K3.G4 UNK2K3.G5 UNK2K3.G6 UNK2K3.G7 UNK2K3.G8 UNK2K3.G9 UNK2K3.G10 UNK2K4.G1 UNK2K4.G2 UNK2K4.G3 UNK2K4.G4 UNK2K4.G5 UNK2K4.G6 UNK2K4.G7 UNK2K4.G8 UNK2K4.G9 UNK2K4.G10 UNK2K5.G1 UNK2K5.G2 UNK2K5.G3 UNK2K5.G4 UNK2K5.G5 UNK2K5.G6 UNK2K5.G7 UNK2K5.G8 UNK2K5.G9 UNK2K5.G10 UNK2K6.G1 UNK2K6.G2 UNK2K6.G3 UNK2K6.G4 UNK2K6.G5 UNK2K6.G6 UNK2K6.G7 UNK2K6.G8 UNK2K6.G9 UNK2K6.G10 UNK2K7.G1 UNK2K7.G2 UNK2K7.G3 UNK2K7.G4 UNK2K7.G5 UNK2K7.G6 UNK2K7.G7 UNK2K7.G8 UNK2K7.G9 UNK2K7.G10 UNK2K8.G1 UNK2K8.G2 UNK2K8.G3 UNK2K8.G4 UNK2K8.G5 UNK2K8.G6 UNK2K8.G7 UNK2K8.G8 UNK2K8.G9 UNK2K8.G10 UNK2K11.G1 UNK2K11.G2 UNK2K11.G3 UNK2K11.G4 UNK2K11.G5 UNK2K11.G6 UNK2K11.G7 UNK2K11.G8 UNK2K11.G9 UNK2K11.G10 UNK2K16.G1 UNK2K16.G2 UNK2K16.G3 UNK2K16.G4 UNK2K16.G5 UNK2K16.G6 UNK2K16.G7 UNK2K16.G8 UNK2K16.G9 UNK2K16.G10 UNK2K17.G1 UNK2K17.G2 UNK2K17.G3 UNK2K17.G4 UNK2K17.G5 UNK2K17.G6 UNK2K17.G7 UNK2K17.G8 UNK2K17.G9 UNK2K17.G10 UNK2K21.G1 UNK2K21.G2 UNK2K21.G3 UNK2K21.G4 UNK2K21.G5 UNK2K21.G6 UNK2K21.G7 UNK2K21.G8 UNK2K21.G9 UNK2K21.G10 UNK2K22.G1 UNK2K22.G2 UNK2K22.G3 UNK2K22.G4 UNK2K22.G5 UNK2K22.G6 UNK2K22.G7 UNK2K22.G8 UNK2K22.G9 UNK2K22.G10 UNK2K23.G1 UNK2K23.G2 UNK2K23.G3 UNK2K23.G4 UNK2K23.G5 UNK2K23.G6 UNK2K23.G7 UNK2K23.G8 UNK2K23.G9 UNK2K23.G10 UNK2K24.G1 UNK2K24.G2 UNK2K24.G3 UNK2K24.G4 UNK2K24.G5 UNK2K24.G6 UNK2K24.G7 UNK2K24.G8 UNK2K24.G9 UNK2K24.G10 UNK2K25.G1 UNK2K25.G2 UNK2K25.G3 UNK2K25.G4 UNK2K25.G5 UNK2K25.G6 UNK2K25.G7 UNK2K25.G8 UNK2K25.G9 UNK2K25.G10 UNK2K26.G1 UNK2K26.G2 UNK2K26.G3 UNK2K26.G4 UNK2K26.G5 UNK2K26.G6 UNK2K26.G7 UNK2K26.G8 UNK2K26.G9 UNK2K26.G10 UNK2K27.G1 UNK2K27.G2 UNK2K27.G3 UNK2K27.G4 UNK2K27.G5 UNK2K27.G6 UNK2K27.G7 UNK2K27.G8 UNK2K27.G9 UNK2K27.G10 UNK2K29.G1 UNK2K29.G2 UNK2K29.G3 UNK2K29.G4 UNK2K29.G5 UNK2K29.G6 UNK2K29.G7 UNK2K29.G8 UNK2K29.G9 UNK2K29.G10 UNK2K30.G1 UNK2K30.G2 UNK2K30.G3 UNK2K30.G4 UNK2K30.G5 UNK2K30.G6 UNK2K30.G7 UNK2K30.G8 UNK2K30.G9 UNK2K30.G10 UNK2K43.G1 UNK2K43.G2 UNK2K43.G3 UNK2K43.G4 UNK2K43.G5 UNK2K43.G6 UNK2K43.G7 UNK2K43.G8 UNK2K43.G9 UNK2K43.G10 UNK2R2.1 UNK2R3.2 UNK2R86.2 UNK2R93.2 UNK2R117.2 UNK2R131.2 UNK2R132.2 UNK2SH2.1 UNK2SH4.1 UNK2SH6.1 UNK2SH8.1 UNK2SH9.1 UNK2SH11.1 UNK2SH13.1 UNK2SH15.1 UNK2SH17.1 UNK2SH19.1 UNK2SH21.1 UNK2SH24.1 UNK2SH26.1 UNK2SH28.1 UNK2U1.4 UNK2U2.4 UNK2Y1.2 UNK2Y1.4 UNK2Y2.2 UNK2Y2.4 UNK3C5.2 UNK3C6.2 UNK3C7.2 UNK3C8.2 UNK3C9.2 UNK3CA1.2 UNK3CA2.2 UNK3CA3.2 UNK3CA4.2 UNK3CA5.2 UNK3CA6.2 UNK3CA7.2 UNK3CA8.2 UNK3CA9.2 UNK3CA10.2 UNK3CA11.2 UNK3CA12.2 UNK3CA13.2 UNK3CA14.2 UNK3CA15.2 UNK3CA16.2 UNK3CA17.2 UNK3CA18.2 UNK3CA19.2 UNK3CA20.2 UNK3CA21.2 UNK3CA22.2 UNK3CA23.2 UNK3CA24.2 UNK3CA25.2 UNK3CA26.2 UNK3CA27.2 UNK3CA28.2 UNK3CA29.2 UNK3CA30.2 UNK3CA31.2 UNK3CA32.2 UNK3CA33.2 UNK3CA34.2 UNK3CA35.2 UNK3CA36.2 UNK3CA37.2 UNK3CA38.2 UNK3CA39.2 UNK3CA40.2 UNK3CC1.2 UNK3CC2.2 UNK3CC4.2 UNK3CC6.2 UNK3CC7.2 UNK3CC8.2 UNK3CC9.2 UNK3CC11.2 UNK3CC13.2 UNK3CC15.2 UNK3CC16.2 UNK3CC17.2 UNK3CC19.2 UNK3CC20.2 UNK3CC22.2 UNK3CC23.2 UNK3CC25.2 UNK3CC26.2 UNK3CC27.2 UNK3CC28.2 UNK3CC29.2 UNK3CC30.2 UNK3CC31.2 UNK3CC32.2 UNK3CC33.2 UNK3CC34.2 UNK3CC35.2 UNK3CC36.2 UNK3CC37.2 UNK3CC38.2 UNK3CC39.2 UNK3CC40.2 UNK3CC41.2 UNK3CC42.2 UNK3CD1.2 UNK3CD3.2 UNK3CD4.2 UNK3CD5.2 UNK3CD6.2 UNK3CD7.2 UNK3CD8.2 UNK3CD9.2 UNK3CD10.2 UNK3CD11.2 UNK3CD12.2 UNK3CD13.2 UNK3CD14.2 UNK3CD15.2 UNK3CD16.2 UNK3CD17.2 UNK3CD18.2 UNK3CD19.2 UNK3CD20.2 UNK3CD21.2 UNK3CD22.2 UNK3CD23.2 UNK3CD24.2 UNK3CD25.2 UNK3GND1.1 UNK3GND2.1 UNK3GND3.1 UNK3GND4.1 UNK3GND5.1 UNK3GND6.1 UNK3GND7.1 UNK3GND8.1 UNK3GND9.1 UNK3GND10.1 UNK3GND11.1 UNK3GND12.1 UNK3GND13.1 UNK3GND14.1 UNK3K1.G1 UNK3K1.G2 UNK3K1.G3 UNK3K1.G4 UNK3K1.G5 UNK3K1.G6 UNK3K1.G7 UNK3K1.G8 UNK3K1.G9 UNK3K1.G10 UNK3K2.G1 UNK3K2.G2 UNK3K2.G3 UNK3K2.G4 UNK3K2.G5 UNK3K2.G6 UNK3K2.G7 UNK3K2.G8 UNK3K2.G9 UNK3K2.G10 UNK3K3.G1 UNK3K3.G2 UNK3K3.G3 UNK3K3.G4 UNK3K3.G5 UNK3K3.G6 UNK3K3.G7 UNK3K3.G8 UNK3K3.G9 UNK3K3.G10 UNK3K4.G1 UNK3K4.G2 UNK3K4.G3 UNK3K4.G4 UNK3K4.G5 UNK3K4.G6 UNK3K4.G7 UNK3K4.G8 UNK3K4.G9 UNK3K4.G10 UNK3K5.G1 UNK3K5.G2 UNK3K5.G3 UNK3K5.G4 UNK3K5.G5 UNK3K5.G6 UNK3K5.G7 UNK3K5.G8 UNK3K5.G9 UNK3K5.G10 UNK3K6.G1 UNK3K6.G2 UNK3K6.G3 UNK3K6.G4 UNK3K6.G5 UNK3K6.G6 UNK3K6.G7 UNK3K6.G8 UNK3K6.G9 UNK3K6.G10 UNK3K7.G1 UNK3K7.G2 UNK3K7.G3 UNK3K7.G4 UNK3K7.G5 UNK3K7.G6 UNK3K7.G7 UNK3K7.G8 UNK3K7.G9 UNK3K7.G10 UNK3K8.G1 UNK3K8.G2 UNK3K8.G3 UNK3K8.G4 UNK3K8.G5 UNK3K8.G6 UNK3K8.G7 UNK3K8.G8 UNK3K8.G9 UNK3K8.G10 UNK3K11.G1 UNK3K11.G2 UNK3K11.G3 UNK3K11.G4 UNK3K11.G5 UNK3K11.G6 UNK3K11.G7 UNK3K11.G8 UNK3K11.G9 UNK3K11.G10 UNK3K16.G1 UNK3K16.G2 UNK3K16.G3 UNK3K16.G4 UNK3K16.G5 UNK3K16.G6 UNK3K16.G7 UNK3K16.G8 UNK3K16.G9 UNK3K16.G10 UNK3K17.G1 UNK3K17.G2 UNK3K17.G3 UNK3K17.G4 UNK3K17.G5 UNK3K17.G6 UNK3K17.G7 UNK3K17.G8 UNK3K17.G9 UNK3K17.G10 UNK3K21.G1 UNK3K21.G2 UNK3K21.G3 UNK3K21.G4 UNK3K21.G5 UNK3K21.G6 UNK3K21.G7 UNK3K21.G8 UNK3K21.G9 UNK3K21.G10 UNK3K22.G1 UNK3K22.G2 UNK3K22.G3 UNK3K22.G4 UNK3K22.G5 UNK3K22.G6 UNK3K22.G7 UNK3K22.G8 UNK3K22.G9 UNK3K22.G10 UNK3K23.G1 UNK3K23.G2 UNK3K23.G3 UNK3K23.G4 UNK3K23.G5 UNK3K23.G6 UNK3K23.G7 UNK3K23.G8 UNK3K23.G9 UNK3K23.G10 UNK3K24.G1 UNK3K24.G2 UNK3K24.G3 UNK3K24.G4 UNK3K24.G5 UNK3K24.G6 UNK3K24.G7 UNK3K24.G8 UNK3K24.G9 UNK3K24.G10 UNK3K25.G1 UNK3K25.G2 UNK3K25.G3 UNK3K25.G4 UNK3K25.G5 UNK3K25.G6 UNK3K25.G7 UNK3K25.G8 UNK3K25.G9 UNK3K25.G10 UNK3K26.G1 UNK3K26.G2 UNK3K26.G3 UNK3K26.G4 UNK3K26.G5 UNK3K26.G6 UNK3K26.G7 UNK3K26.G8 UNK3K26.G9 UNK3K26.G10 UNK3K27.G1 UNK3K27.G2 UNK3K27.G3 UNK3K27.G4 UNK3K27.G5 UNK3K27.G6 UNK3K27.G7 UNK3K27.G8 UNK3K27.G9 UNK3K27.G10 UNK3K29.G1 UNK3K29.G2 UNK3K29.G3 UNK3K29.G4 UNK3K29.G5 UNK3K29.G6 UNK3K29.G7 UNK3K29.G8 UNK3K29.G9 UNK3K29.G10 UNK3K30.G1 UNK3K30.G2 UNK3K30.G3 UNK3K30.G4 UNK3K30.G5 UNK3K30.G6 UNK3K30.G7 UNK3K30.G8 UNK3K30.G9 UNK3K30.G10 UNK3K43.G1 UNK3K43.G2 UNK3K43.G3 UNK3K43.G4 UNK3K43.G5 UNK3K43.G6 UNK3K43.G7 UNK3K43.G8 UNK3K43.G9 UNK3K43.G10 UNK3R2.1 UNK3R3.2 UNK3R86.2 UNK3R93.2 UNK3R117.2 UNK3R131.2 UNK3R132.2 UNK3SH2.1 UNK3SH4.1 UNK3SH6.1 UNK3SH8.1 UNK3SH9.1 UNK3SH11.1 UNK3SH13.1 UNK3SH15.1 UNK3SH17.1 UNK3SH19.1 UNK3SH21.1 UNK3SH24.1 UNK3SH26.1 UNK3SH28.1 UNK3U1.4 UNK3U2.4 UNK3Y1.2 UNK3Y1.4 UNK3Y2.2 UNK3Y2.4 UNK4C5.2 UNK4C6.2 UNK4C7.2 UNK4C8.2 UNK4C9.2 UNK4CA1.2 UNK4CA2.2 UNK4CA3.2 UNK4CA4.2 UNK4CA5.2 UNK4CA6.2 UNK4CA7.2 UNK4CA8.2 UNK4CA9.2 UNK4CA10.2 UNK4CA11.2 UNK4CA12.2 UNK4CA13.2 UNK4CA14.2 UNK4CA15.2 UNK4CA16.2 UNK4CA17.2 UNK4CA18.2 UNK4CA19.2 UNK4CA20.2 UNK4CA21.2 UNK4CA22.2 UNK4CA23.2 UNK4CA24.2 UNK4CA25.2 UNK4CA26.2 UNK4CA27.2 UNK4CA28.2 UNK4CA29.2 UNK4CA30.2 UNK4CA31.2 UNK4CA32.2 UNK4CA33.2 UNK4CA34.2 UNK4CA35.2 UNK4CA36.2 UNK4CA37.2 UNK4CA38.2 UNK4CA39.2 UNK4CA40.2 UNK4CC1.2 UNK4CC2.2 UNK4CC4.2 UNK4CC6.2 UNK4CC7.2 UNK4CC8.2 UNK4CC9.2 UNK4CC11.2 UNK4CC13.2 UNK4CC15.2 UNK4CC16.2 UNK4CC17.2 UNK4CC19.2 UNK4CC20.2 UNK4CC22.2 UNK4CC23.2 UNK4CC25.2 UNK4CC26.2 UNK4CC27.2 UNK4CC28.2 UNK4CC29.2 UNK4CC30.2 UNK4CC31.2 UNK4CC32.2 UNK4CC33.2 UNK4CC34.2 UNK4CC35.2 UNK4CC36.2 UNK4CC37.2 UNK4CC38.2 UNK4CC39.2 UNK4CC40.2 UNK4CC41.2 UNK4CC42.2 UNK4CD1.2 UNK4CD3.2 UNK4CD4.2 UNK4CD5.2 UNK4CD6.2 UNK4CD7.2 UNK4CD8.2 UNK4CD9.2 UNK4CD10.2 UNK4CD11.2 UNK4CD12.2 UNK4CD13.2 UNK4CD14.2 UNK4CD15.2 UNK4CD16.2 UNK4CD17.2 UNK4CD18.2 UNK4CD19.2 UNK4CD20.2 UNK4CD21.2 UNK4CD22.2 UNK4CD23.2 UNK4CD24.2 UNK4CD25.2 UNK4GND1.1 UNK4GND2.1 UNK4GND3.1 UNK4GND4.1 UNK4GND5.1 UNK4GND6.1 UNK4GND7.1 UNK4GND8.1 UNK4GND9.1 UNK4GND10.1 UNK4GND11.1 UNK4GND12.1 UNK4GND13.1 UNK4GND14.1 UNK4K1.G1 UNK4K1.G2 UNK4K1.G3 UNK4K1.G4 UNK4K1.G5 UNK4K1.G6 UNK4K1.G7 UNK4K1.G8 UNK4K1.G9 UNK4K1.G10 UNK4K2.G1 UNK4K2.G2 UNK4K2.G3 UNK4K2.G4 UNK4K2.G5 UNK4K2.G6 UNK4K2.G7 UNK4K2.G8 UNK4K2.G9 UNK4K2.G10 UNK4K3.G1 UNK4K3.G2 UNK4K3.G3 UNK4K3.G4 UNK4K3.G5 UNK4K3.G6 UNK4K3.G7 UNK4K3.G8 UNK4K3.G9 UNK4K3.G10 UNK4K4.G1 UNK4K4.G2 UNK4K4.G3 UNK4K4.G4 UNK4K4.G5 UNK4K4.G6 UNK4K4.G7 UNK4K4.G8 UNK4K4.G9 UNK4K4.G10 UNK4K5.G1 UNK4K5.G2 UNK4K5.G3 UNK4K5.G4 UNK4K5.G5 UNK4K5.G6 UNK4K5.G7 UNK4K5.G8 UNK4K5.G9 UNK4K5.G10 UNK4K6.G1 UNK4K6.G2 UNK4K6.G3 UNK4K6.G4 UNK4K6.G5 UNK4K6.G6 UNK4K6.G7 UNK4K6.G8 UNK4K6.G9 UNK4K6.G10 UNK4K7.G1 UNK4K7.G2 UNK4K7.G3 UNK4K7.G4 UNK4K7.G5 UNK4K7.G6 UNK4K7.G7 UNK4K7.G8 UNK4K7.G9 UNK4K7.G10 UNK4K8.G1 UNK4K8.G2 UNK4K8.G3 UNK4K8.G4 UNK4K8.G5 UNK4K8.G6 UNK4K8.G7 UNK4K8.G8 UNK4K8.G9 UNK4K8.G10 UNK4K11.G1 UNK4K11.G2 UNK4K11.G3 UNK4K11.G4 UNK4K11.G5 UNK4K11.G6 UNK4K11.G7 UNK4K11.G8 UNK4K11.G9 UNK4K11.G10 UNK4K16.G1 UNK4K16.G2 UNK4K16.G3 UNK4K16.G4 UNK4K16.G5 UNK4K16.G6 UNK4K16.G7 UNK4K16.G8 UNK4K16.G9 UNK4K16.G10 UNK4K17.G1 UNK4K17.G2 UNK4K17.G3 UNK4K17.G4 UNK4K17.G5 UNK4K17.G6 UNK4K17.G7 UNK4K17.G8 UNK4K17.G9 UNK4K17.G10 UNK4K21.G1 UNK4K21.G2 UNK4K21.G3 UNK4K21.G4 UNK4K21.G5 UNK4K21.G6 UNK4K21.G7 UNK4K21.G8 UNK4K21.G9 UNK4K21.G10 UNK4K22.G1 UNK4K22.G2 UNK4K22.G3 UNK4K22.G4 UNK4K22.G5 UNK4K22.G6 UNK4K22.G7 UNK4K22.G8 UNK4K22.G9 UNK4K22.G10 UNK4K23.G1 UNK4K23.G2 UNK4K23.G3 UNK4K23.G4 UNK4K23.G5 UNK4K23.G6 UNK4K23.G7 UNK4K23.G8 UNK4K23.G9 UNK4K23.G10 UNK4K24.G1 UNK4K24.G2 UNK4K24.G3 UNK4K24.G4 UNK4K24.G5 UNK4K24.G6 UNK4K24.G7 UNK4K24.G8 UNK4K24.G9 UNK4K24.G10 UNK4K25.G1 UNK4K25.G2 UNK4K25.G3 UNK4K25.G4 UNK4K25.G5 UNK4K25.G6 UNK4K25.G7 UNK4K25.G8 UNK4K25.G9 UNK4K25.G10 UNK4K26.G1 UNK4K26.G2 UNK4K26.G3 UNK4K26.G4 UNK4K26.G5 UNK4K26.G6 UNK4K26.G7 UNK4K26.G8 UNK4K26.G9 UNK4K26.G10 UNK4K27.G1 UNK4K27.G2 UNK4K27.G3 UNK4K27.G4 UNK4K27.G5 UNK4K27.G6 UNK4K27.G7 UNK4K27.G8 UNK4K27.G9 UNK4K27.G10 UNK4K29.G1 UNK4K29.G2 UNK4K29.G3 UNK4K29.G4 UNK4K29.G5 UNK4K29.G6 UNK4K29.G7 UNK4K29.G8 UNK4K29.G9 UNK4K29.G10 UNK4K30.G1 UNK4K30.G2 UNK4K30.G3 UNK4K30.G4 UNK4K30.G5 UNK4K30.G6 UNK4K30.G7 UNK4K30.G8 UNK4K30.G9 UNK4K30.G10 UNK4K43.G1 UNK4K43.G2 UNK4K43.G3 UNK4K43.G4 UNK4K43.G5 UNK4K43.G6 UNK4K43.G7 UNK4K43.G8 UNK4K43.G9 UNK4K43.G10 UNK4R2.1 UNK4R3.2 UNK4R86.2 UNK4R93.2 UNK4R117.2 UNK4R131.2 UNK4R132.2 UNK4SH2.1 UNK4SH4.1 UNK4SH6.1 UNK4SH8.1 UNK4SH9.1 UNK4SH11.1 UNK4SH13.1 UNK4SH15.1 UNK4SH17.1 UNK4SH19.1 UNK4SH21.1 UNK4SH24.1 UNK4SH26.1 UNK4SH28.1 UNK4U1.4 UNK4U2.4 UNK4Y1.2 UNK4Y1.4 UNK4Y2.2 UNK4Y2.4 Y1.2 Y1.4 Y2.2 Y2.4
CSDPS225GS1: CSDPS225.D2
CSDPS225GS2: CSDPS225.A1
CSDPS225GS3: CSDPS225.D4
CSDPS225GS4: CSDPS225.A3
CSDPS225GS5: CSDPS225.D6
CSDPS225GS6: CSDPS225.A5
CSDPS225GS7: CSDPS225.D8
CSDPS225GS8: CSDPS225.A7
CSDPS225GS9: CSDPS225.D10
CSDPS225GS10: CSDPS225.A9
CSDPS225GS11: CSDPS225.D12
CSDPS225GS12: CSDPS225.A11
CSDPS225GS13: CSDPS225.D14
CSDPS225GS14: CSDPS225.A13
CSDPS225GS15: CSDPS225.D16
CSDPS225GS16: CSDPS225.A15
CSDPS225P1: CSDPS225.B1
CSDPS225P2: CSDPS225.C2
CSDPS225P3: CSDPS225.B3
CSDPS225P4: CSDPS225.C4
CSDPS225P5: CSDPS225.B5
CSDPS225P6: CSDPS225.C6
CSDPS225P7: CSDPS225.B7
CSDPS225P8: CSDPS225.C8
CSDPS225P9: CSDPS225.B9
CSDPS225P10: CSDPS225.C10
CSDPS225P11: CSDPS225.B11
CSDPS225P12: CSDPS225.C12
CSDPS225P13: CSDPS225.B13
CSDPS225P14: CSDPS225.C14
CSDPS225P15: CSDPS225.B15
CSDPS225P16: CSDPS225.C16
CSDPS225PS1: CSDPS225.D1
CSDPS225PS2: CSDPS225.A2
CSDPS225PS3: CSDPS225.D3
CSDPS225PS4: CSDPS225.A4
CSDPS225PS5: CSDPS225.D5
CSDPS225PS6: CSDPS225.A6
CSDPS225PS7: CSDPS225.D7
CSDPS225PS8: CSDPS225.A8
CSDPS225PS9: CSDPS225.D9
CSDPS225PS10: CSDPS225.A10
CSDPS225PS11: CSDPS225.D11
CSDPS225PS12: CSDPS225.A12
CSDPS225PS13: CSDPS225.D13
CSDPS225PS14: CSDPS225.A14
CSDPS225PS15: CSDPS225.D15
CSDPS225PS16: CSDPS225.A16
CSDPS229GS1: CSDPS229.D2
CSDPS229GS2: CSDPS229.A1
CSDPS229GS3: CSDPS229.D4
CSDPS229GS4: CSDPS229.A3
CSDPS229GS5: CSDPS229.D6
CSDPS229GS6: CSDPS229.A5
CSDPS229GS7: CSDPS229.D8
CSDPS229GS8: CSDPS229.A7
CSDPS229GS9: CSDPS229.D10
CSDPS229GS10: CSDPS229.A9
CSDPS229GS11: CSDPS229.D12
CSDPS229GS12: CSDPS229.A11
CSDPS229GS13: CSDPS229.D14
CSDPS229GS14: CSDPS229.A13
CSDPS229GS15: CSDPS229.D16
CSDPS229GS16: CSDPS229.A15
CSDPS229P1: CSDPS229.B1
CSDPS229P2: CSDPS229.C2
CSDPS229P3: CSDPS229.B3
CSDPS229P4: CSDPS229.C4
CSDPS229P5: CSDPS229.B5
CSDPS229P6: CSDPS229.C6
CSDPS229P7: CSDPS229.B7
CSDPS229P8: CSDPS229.C8
CSDPS229P9: CSDPS229.B9
CSDPS229P10: CSDPS229.C10
CSDPS229P11: CSDPS229.B11
CSDPS229P12: CSDPS229.C12
CSDPS229P13: CSDPS229.B13
CSDPS229P14: CSDPS229.C14
CSDPS229P15: CSDPS229.B15
CSDPS229P16: CSDPS229.C16
CSDPS229PS1: CSDPS229.D1
CSDPS229PS2: CSDPS229.A2
CSDPS229PS3: CSDPS229.D3
CSDPS229PS4: CSDPS229.A4
CSDPS229PS5: CSDPS229.D5
CSDPS229PS6: CSDPS229.A6
CSDPS229PS7: CSDPS229.D7
CSDPS229PS8: CSDPS229.A8
CSDPS229PS9: CSDPS229.D9
CSDPS229PS10: CSDPS229.A10
CSDPS229PS11: CSDPS229.D11
CSDPS229PS12: CSDPS229.A12
CSDPS229PS13: CSDPS229.D13
CSDPS229PS14: CSDPS229.A14
CSDPS229PS15: CSDPS229.D15
CSDPS229PS16: CSDPS229.A16
CSDPS425GS1: CSDPS425.D2
CSDPS425GS2: CSDPS425.A1
CSDPS425GS3: CSDPS425.D4
CSDPS425GS4: CSDPS425.A3
CSDPS425GS5: CSDPS425.D6
CSDPS425GS6: CSDPS425.A5
CSDPS425GS7: CSDPS425.D8
CSDPS425GS8: CSDPS425.A7
CSDPS425GS9: CSDPS425.D10
CSDPS425GS10: CSDPS425.A9
CSDPS425GS11: CSDPS425.D12
CSDPS425GS12: CSDPS425.A11
CSDPS425GS13: CSDPS425.D14
CSDPS425GS14: CSDPS425.A13
CSDPS425GS15: CSDPS425.D16
CSDPS425GS16: CSDPS425.A15
CSDPS425P1: CSDPS425.B1
CSDPS425P2: CSDPS425.C2
CSDPS425P3: CSDPS425.B3
CSDPS425P4: CSDPS425.C4
CSDPS425P5: CSDPS425.B5
CSDPS425P6: CSDPS425.C6
CSDPS425P7: CSDPS425.B7
CSDPS425P8: CSDPS425.C8
CSDPS425P9: CSDPS425.B9
CSDPS425P10: CSDPS425.C10
CSDPS425P11: CSDPS425.B11
CSDPS425P12: CSDPS425.C12
CSDPS425P13: CSDPS425.B13
CSDPS425P14: CSDPS425.C14
CSDPS425P15: CSDPS425.B15
CSDPS425P16: CSDPS425.C16
CSDPS425PS1: CSDPS425.D1
CSDPS425PS2: CSDPS425.A2
CSDPS425PS3: CSDPS425.D3
CSDPS425PS4: CSDPS425.A4
CSDPS425PS5: CSDPS425.D5
CSDPS425PS6: CSDPS425.A6
CSDPS425PS7: CSDPS425.D7
CSDPS425PS8: CSDPS425.A8
CSDPS425PS9: CSDPS425.D9
CSDPS425PS10: CSDPS425.A10
CSDPS425PS11: CSDPS425.D11
CSDPS425PS12: CSDPS425.A12
CSDPS425PS13: CSDPS425.D13
CSDPS425PS14: CSDPS425.A14
CSDPS425PS15: CSDPS425.D15
CSDPS425PS16: CSDPS425.A16
CSDPS429GS1: CSDPS429.D2
CSDPS429GS2: CSDPS429.A1
CSDPS429GS3: CSDPS429.D4
CSDPS429GS4: CSDPS429.A3
CSDPS429GS5: CSDPS429.D6
CSDPS429GS6: CSDPS429.A5
CSDPS429GS7: CSDPS429.D8
CSDPS429GS8: CSDPS429.A7
CSDPS429GS9: CSDPS429.D10
CSDPS429GS10: CSDPS429.A9
CSDPS429GS11: CSDPS429.D12
CSDPS429GS12: CSDPS429.A11
CSDPS429GS13: CSDPS429.D14
CSDPS429GS14: CSDPS429.A13
CSDPS429GS15: CSDPS429.D16
CSDPS429GS16: CSDPS429.A15
CSDPS429P1: CSDPS429.B1
CSDPS429P2: CSDPS429.C2
CSDPS429P3: CSDPS429.B3
CSDPS429P4: CSDPS429.C4
CSDPS429P5: CSDPS429.B5
CSDPS429P6: CSDPS429.C6
CSDPS429P7: CSDPS429.B7
CSDPS429P8: CSDPS429.C8
CSDPS429P9: CSDPS429.B9
CSDPS429P10: CSDPS429.C10
CSDPS429P11: CSDPS429.B11
CSDPS429P12: CSDPS429.C12
CSDPS429P13: CSDPS429.B13
CSDPS429P14: CSDPS429.C14
CSDPS429P15: CSDPS429.B15
CSDPS429P16: CSDPS429.C16
CSDPS429PS1: CSDPS429.D1
CSDPS429PS2: CSDPS429.A2
CSDPS429PS3: CSDPS429.D3
CSDPS429PS4: CSDPS429.A4
CSDPS429PS5: CSDPS429.D5
CSDPS429PS6: CSDPS429.A6
CSDPS429PS7: CSDPS429.D7
CSDPS429PS8: CSDPS429.A8
CSDPS429PS9: CSDPS429.D9
CSDPS429PS10: CSDPS429.A10
CSDPS429PS11: CSDPS429.D11
CSDPS429PS12: CSDPS429.A12
CSDPS429PS13: CSDPS429.D13
CSDPS429PS14: CSDPS429.A14
CSDPS429PS15: CSDPS429.D15
CSDPS429PS16: CSDPS429.A16
D231_MCB1_CT2: D231.17
D231_MCB1_E+: D231.16
D231_MCB1_E-: D231.15
D231_MCB1_EE+: D231.08
D231_MCB1_EE-: D231.07
D231_MCB1_F+: D231.14
D231_MCB1_F-: D231.13
D231_MCB1_FF+: D231.06
D231_MCB1_FF-: D231.05
D231_MCB1_G+: D231.12
D231_MCB1_G-: D231.11
D231_MCB1_GG+: D231.04
D231_MCB1_GG-: D231.03
D231_MCB1_H+: D231.10
D231_MCB1_H-: D231.09
D231_MCB1_HH+: D231.02
D231_MCB1_HH-: D231.01
D431_MCB1_A+: D431.16
D431_MCB1_A-: D431.15
D431_MCB1_AA+: D431.08
D431_MCB1_AA-: D431.07
D431_MCB1_B+: D431.14
D431_MCB1_B-: D431.13
D431_MCB1_BB+: D431.06
D431_MCB1_BB-: D431.05
D431_MCB1_C+: D431.12
D431_MCB1_C-: D431.11
D431_MCB1_CC+: D431.04
D431_MCB1_CC-: D431.03
D431_MCB1_CT1: D431.17
D431_MCB1_D+: D431.10
D431_MCB1_D-: D431.09
D431_MCB1_DD+: D431.02
D431_MCB1_DD-: D431.01
D10201: D102.01
D10202: D102.02
D10203: D102.03
D10204: D102.04
D10205: D102.05
D10206: D102.06
D10207: D102.07
D10208: D102.08
D10209: D102.09
D10210: D102.10
D10211: D102.11
D10212: D102.12
D10213: D102.13
D10214: D102.14
D10215: D102.15
D10216: D102.16
D10301: D103.01
D10302: D103.02
D10303: D103.03
D10304: D103.04
D10305: D103.05
D10306: D103.06
D10307: D103.07
D10308: D103.08
D10309: D103.09
D10310: D103.10
D10311: D103.11
D10312: D103.12
D10313: D103.13
D10314: D103.14
D10315: D103.15
D10316: D103.16
D10401: D104.01
D10402: D104.02
D10403: D104.03
D10404: D104.04
D10405: D104.05
D10406: D104.06
D10407: D104.07
D10408: D104.08
D10409: D104.09 SITE4.172(OLV2P) UNK4R105.2
D10410: D104.10 SITE4.12(ELVCKP) UNK4R54.2
D10411: D104.11 SITE4.171(OLV2N) UNK4R104.1
D10412: D104.12 SITE4.11(ELVCKN) UNK4R53.1
D10413: D104.13 SITE4.8(ELV1P) UNK4R46.2
D10414: D104.14 SITE4.10(ELV2P) UNK4R52.2
D10415: D104.15 SITE4.7(ELV1N) UNK4R45.1
D10416: D104.16 SITE4.9(ELV2N) UNK4R51.1
D10601: D106.01
D10602: D106.02
D10603: D106.03
D10604: D106.04
D10605: D106.05
D10606: D106.06
D10607: D106.07
D10608: D106.08
D10609: D106.09
D10610: D106.10
D10611: D106.11
D10612: D106.12
D10613: D106.13
D10614: D106.14
D10615: D106.15
D10616: D106.16
D10701: D107.01
D10702: D107.02
D10703: D107.03
D10704: D107.04
D10705: D107.05
D10706: D107.06
D10707: D107.07
D10708: D107.08
D10709: D107.09
D10710: D107.10
D10711: D107.11
D10712: D107.12
D10713: D107.13
D10714: D107.14
D10715: D107.15
D10716: D107.16
D10801: D108.01 SITE4.5(ELV0N) UNK4R102.1
D10802: D108.02 SITE4.16(ELV4P) UNK4R50.2
D10803: D108.03 SITE4.6(ELV0P) UNK4R103.2
D10804: D108.04 SITE4.15(ELV4N) UNK4R49.1
D10805: D108.05 SITE4.175(OLV3N) UNK4R65.1
D10806: D108.06 SITE4.170(OLV1P) UNK4R58.2
D10807: D108.07 SITE4.176(OLV3P) UNK4R66.2
D10808: D108.08 SITE4.169(OLV1N) UNK4R57.1
D10809: D108.09 SITE4.2(OLV4P) UNK4R60.2
D10810: D108.10 SITE4.168(OLV0P) UNK4R56.2
D10811: D108.11 SITE4.1(OLV4N) UNK4R59.1
D10812: D108.12 SITE4.167(OLV0N) UNK4R55.1
D10813: D108.13 SITE4.174(OLVCKP) UNK4R62.2
D10814: D108.14 SITE4.14(ELV3P) UNK4R48.2
D10815: D108.15 SITE4.173(OLVCKN) UNK4R61.1
D10816: D108.16 SITE4.13(ELV3N) UNK4R47.1
D10901: D109.01 SITE2.176(OLV3P) UNK2R66.2
D10902: D109.02 SITE2.168(OLV0P) UNK2R56.2
D10903: D109.03 SITE2.175(OLV3N) UNK2R65.1
D10904: D109.04 SITE2.167(OLV0N) UNK2R55.1
D10905: D109.05 SITE2.174(OLVCKP) UNK2R62.2
D10906: D109.06 SITE2.170(OLV1P) UNK2R58.2
D10907: D109.07 SITE2.173(OLVCKN) UNK2R61.1
D10908: D109.08 SITE2.169(OLV1N) UNK2R57.1
D10909: D109.09 SITE2.14(ELV3P) UNK2R48.2
D10910: D109.10 SITE2.2(OLV4P) UNK2R60.2
D10911: D109.11 SITE2.13(ELV3N) UNK2R47.1
D10912: D109.12 SITE2.1(OLV4N) UNK2R59.1
D10913: D109.13 SITE2.10(ELV2P) UNK2R52.2
D10914: D109.14 SITE2.12(ELVCKP) UNK2R54.2
D10915: D109.15 SITE2.9(ELV2N) UNK2R51.1
D10916: D109.16 SITE2.11(ELVCKN) UNK2R53.1
D11001: D110.01
D11002: D110.02
D11003: D110.03
D11004: D110.04
D11005: D110.05
D11006: D110.06
D11007: D110.07
D11008: D110.08
D11009: D110.09
D11010: D110.10
D11011: D110.11
D11012: D110.12
D11013: D110.13
D11014: D110.14
D11015: D110.15
D11016: D110.16
D11101: D111.01
D11102: D111.02
D11103: D111.03
D11104: D111.04
D11105: D111.05
D11106: D111.06
D11107: D111.07
D11108: D111.08
D11109: D111.09
D11110: D111.10
D11111: D111.11
D11112: D111.12
D11113: D111.13
D11114: D111.14
D11115: D111.15
D11116: D111.16
D11201: D112.01
D11202: D112.02
D11203: D112.03
D11204: D112.04
D11205: D112.05
D11206: D112.06
D11207: D112.07
D11208: D112.08
D11209: D112.09
D11210: D112.10
D11211: D112.11
D11212: D112.12
D11213: D112.13
D11214: D112.14
D11215: D112.15
D11216: D112.16
D11301: D113.01 SITE2.172(OLV2P) UNK2R105.2
D11302: D113.02 SITE2.8(ELV1P) UNK2R46.2
D11303: D113.03 SITE2.171(OLV2N) UNK2R104.1
D11304: D113.04 SITE2.7(ELV1N) UNK2R45.1
D11305: D113.05 SITE2.16(ELV4P) UNK2R50.2
D11306: D113.06 SITE2.6(ELV0P) UNK2R103.2
D11307: D113.07 SITE2.15(ELV4N) UNK2R49.1
D11308: D113.08 SITE2.5(ELV0N) UNK2R102.1
D11309: D113.09
D11310: D113.10
D11311: D113.11
D11312: D113.12
D11313: D113.13
D11314: D113.14
D11315: D113.15
D11316: D113.16
D11401: D114.01
D11402: D114.02
D11403: D114.03
D11404: D114.04
D11405: D114.05
D11406: D114.06
D11407: D114.07
D11408: D114.08
D11409: D114.09
D11410: D114.10
D11411: D114.11
D11412: D114.12
D11413: D114.13
D11414: D114.14
D11415: D114.15
D11416: D114.16
D11501: D115.01
D11502: D115.02
D11503: D115.03
D11504: D115.04
D11505: D115.05
D11506: D115.06
D11507: D115.07
D11508: D115.08
D11509: D115.09
D11510: D115.10
D11511: D115.11
D11512: D115.12
D11513: D115.13
D11514: D115.14
D11515: D115.15
D11516: D115.16
D11601: D116.01
D11602: D116.02
D11603: D116.03
D11604: D116.04
D11605: D116.05
D11606: D116.06
D11607: D116.07
D11608: D116.08
D11609: D116.09
D11610: D116.10
D11611: D116.11
D11612: D116.12
D11613: D116.13
D11614: D116.14
D11615: D116.15
D11616: D116.16
D11801: D118.01
D11802: D118.02
D11803: D118.03
D11804: D118.04
D11805: D118.05
D11806: D118.06
D11807: D118.07
D11808: D118.08
D11809: D118.09
D11810: D118.10
D11811: D118.11
D11812: D118.12
D11813: D118.13
D11814: D118.14
D11815: D118.15
D11816: D118.16
D11901: D119.01
D11902: D119.02
D11903: D119.03
D11904: D119.04
D11905: D119.05
D11906: D119.06
D11907: D119.07
D11908: D119.08
D11909: D119.09
D11910: D119.10
D11911: D119.11
D11912: D119.12
D11913: D119.13
D11914: D119.14
D11915: D119.15
D11916: D119.16
D12001: D120.01
D12002: D120.02
D12003: D120.03
D12004: D120.04
D12005: D120.05
D12006: D120.06
D12007: D120.07
D12008: D120.08
D12009: D120.09
D12010: D120.10
D12011: D120.11
D12012: D120.12
D12013: D120.13
D12014: D120.14
D12015: D120.15
D12016: D120.16
D12201: D122.01
D12202: D122.02
D12203: D122.03
D12204: D122.04
D12205: D122.05
D12206: D122.06
D12207: D122.07
D12208: D122.08
D12209: D122.09
D12210: D122.10
D12211: D122.11
D12212: D122.12
D12213: D122.13
D12214: D122.14
D12215: D122.15
D12216: D122.16
D12301: D123.01
D12302: D123.02
D12303: D123.03
D12304: D123.04
D12305: D123.05
D12306: D123.06
D12307: D123.07
D12308: D123.08
D12309: D123.09
D12310: D123.10
D12311: D123.11
D12312: D123.12
D12313: D123.13
D12314: D123.14
D12315: D123.15
D12316: D123.16
D12401: D124.01
D12402: D124.02
D12403: D124.03
D12404: D124.04
D12405: D124.05
D12406: D124.06
D12407: D124.07
D12408: D124.08
D12409: D124.09
D12410: D124.10
D12411: D124.11
D12412: D124.12
D12413: D124.13
D12414: D124.14
D12415: D124.15
D12416: D124.16
D12501: D125.01 R58.2 SITE1.170(OLV1P)
D12502: D125.02 R103.2 SITE1.6(ELV0P)
D12503: D125.03 R57.1 SITE1.169(OLV1N)
D12504: D125.04 R102.1 SITE1.5(ELV0N)
D12505: D125.05 R56.2 SITE1.168(OLV0P)
D12506: D125.06 R46.2 SITE1.8(ELV1P)
D12507: D125.07 R55.1 SITE1.167(OLV0N)
D12508: D125.08 R45.1 SITE1.7(ELV1N)
D12509: D125.09 R60.2 SITE1.2(OLV4P)
D12510: D125.10 R62.2 SITE1.174(OLVCKP)
D12511: D125.11 R59.1 SITE1.1(OLV4N)
D12512: D125.12 R61.1 SITE1.173(OLVCKN)
D12513: D125.13 R105.2 SITE1.172(OLV2P)
D12514: D125.14 R66.2 SITE1.176(OLV3P)
D12515: D125.15 R104.1 SITE1.171(OLV2N)
D12516: D125.16 R65.1 SITE1.175(OLV3N)
D12601: D126.01
D12602: D126.02
D12603: D126.03
D12604: D126.04
D12605: D126.05
D12606: D126.06
D12607: D126.07
D12608: D126.08
D12609: D126.09 R50.2 SITE1.16(ELV4P)
D12610: D126.10 R48.2 SITE1.14(ELV3P)
D12611: D126.11 R49.1 SITE1.15(ELV4N)
D12612: D126.12 R47.1 SITE1.13(ELV3N)
D12613: D126.13 R52.2 SITE1.10(ELV2P)
D12614: D126.14 R54.2 SITE1.12(ELVCKP)
D12615: D126.15 R51.1 SITE1.9(ELV2N)
D12616: D126.16 R53.1 SITE1.11(ELVCKN)
D12701: D127.01
D12702: D127.02
D12703: D127.03
D12704: D127.04
D12705: D127.05
D12706: D127.06
D12707: D127.07
D12708: D127.08
D12709: D127.09
D12710: D127.10
D12711: D127.11
D12712: D127.12
D12713: D127.13
D12714: D127.14
D12715: D127.15
D12716: D127.16
D12801: D128.01
D12802: D128.02
D12803: D128.03
D12804: D128.04
D12805: D128.05
D12806: D128.06
D12807: D128.07
D12808: D128.08
D12809: D128.09
D12810: D128.10
D12811: D128.11
D12812: D128.12
D12813: D128.13
D12814: D128.14
D12815: D128.15
D12816: D128.16
D12901: D129.01 SITE3.175(OLV3N) UNK3R65.1
D12902: D129.02 SITE3.170(OLV1P) UNK3R58.2
D12903: D129.03 SITE3.176(OLV3P) UNK3R66.2
D12904: D129.04 SITE3.169(OLV1N) UNK3R57.1
D12905: D129.05 SITE3.172(OLV2P) UNK3R105.2
D12906: D129.06 SITE3.174(OLVCKP) UNK3R62.2
D12907: D129.07 SITE3.171(OLV2N) UNK3R104.1
D12908: D129.08 SITE3.173(OLVCKN) UNK3R61.1
D12909: D129.09 SITE3.12(ELVCKP) UNK3R54.2
D12910: D129.10 SITE3.2(OLV4P) UNK3R60.2
D12911: D129.11 SITE3.11(ELVCKN) UNK3R53.1
D12912: D129.12 SITE3.1(OLV4N) UNK3R59.1
D12913: D129.13 SITE3.8(ELV1P) UNK3R46.2
D12914: D129.14 SITE3.168(OLV0P) UNK3R56.2
D12915: D129.15 SITE3.7(ELV1N) UNK3R45.1
D12916: D129.16 SITE3.167(OLV0N) UNK3R55.1
D13001: D130.01
D13002: D130.02
D13003: D130.03
D13004: D130.04
D13005: D130.05
D13006: D130.06
D13007: D130.07
D13008: D130.08
D13009: D130.09 SITE3.16(ELV4P) UNK3R50.2
D13010: D130.10 SITE3.10(ELV2P) UNK3R52.2
D13011: D130.11 SITE3.15(ELV4N) UNK3R49.1
D13012: D130.12 SITE3.9(ELV2N) UNK3R51.1
D13013: D130.13 SITE3.14(ELV3P) UNK3R48.2
D13014: D130.14 SITE3.6(ELV0P) UNK3R103.2
D13015: D130.15 SITE3.13(ELV3N) UNK3R47.1
D13016: D130.16 SITE3.5(ELV0N) UNK3R102.1
D13101: D131.01
D13102: D131.02
D13103: D131.03
D13104: D131.04
D13105: D131.05
D13106: D131.06
D13107: D131.07
D13108: D131.08
D13109: D131.09
D13110: D131.10
D13111: D131.11
D13112: D131.12
D13113: D131.13
D13114: D131.14
D13115: D131.15
D13116: D131.16
D13201: D132.01
D13202: D132.02
D13203: D132.03
D13204: D132.04
D13205: D132.05
D13206: D132.06
D13207: D132.07
D13208: D132.08
D13209: D132.09
D13210: D132.10
D13211: D132.11
D13212: D132.12
D13213: D132.13
D13214: D132.14
D13215: D132.15
D13216: D132.16
D30101: D301.01
D30102: D301.02 SITE4.26(RXD0P)
D30103: D301.03
D30104: D301.04 SITE4.27(RXD0N)
D30105: D301.05
D30106: D301.06 SITE4.29(RXD1P)
D30107: D301.07
D30108: D301.08 SITE4.30(RXD1N)
D30109: D301.09
D30110: D301.10 SITE4.32(RXD2P)
D30111: D301.11
D30112: D301.12 SITE4.33(RXD2N)
D30113: D301.13
D30114: D301.14 SITE4.35(RXD3P)
D30115: D301.15
D30116: D301.16 SITE4.36(RXD3N)
D30201: D302.01
D30202: D302.02
D30203: D302.03
D30204: D302.04
D30205: D302.05
D30206: D302.06
D30207: D302.07
D30208: D302.08
D30209: D302.09
D30210: D302.10
D30211: D302.11
D30212: D302.12
D30213: D302.13
D30214: D302.14
D30215: D302.15
D30216: D302.16
D30501: D305.01
D30502: D305.02 SITE2.26(RXD0P)
D30503: D305.03
D30504: D305.04 SITE2.27(RXD0N)
D30505: D305.05
D30506: D305.06 SITE2.29(RXD1P)
D30507: D305.07
D30508: D305.08 SITE2.30(RXD1N)
D30509: D305.09
D30510: D305.10 SITE2.32(RXD2P)
D30511: D305.11
D30512: D305.12 SITE2.33(RXD2N)
D30513: D305.13
D30514: D305.14 SITE2.35(RXD3P)
D30515: D305.15
D30516: D305.16 SITE2.36(RXD3N)
D30601: D306.01
D30602: D306.02
D30603: D306.03
D30604: D306.04
D30605: D306.05
D30606: D306.06
D30607: D306.07
D30608: D306.08
D30609: D306.09
D30610: D306.10
D30611: D306.11
D30612: D306.12
D30613: D306.13
D30614: D306.14
D30615: D306.15
D30616: D306.16
D31701: D317.01
D31702: D317.02 SITE3.26(RXD0P)
D31703: D317.03
D31704: D317.04 SITE3.27(RXD0N)
D31705: D317.05
D31706: D317.06 SITE3.29(RXD1P)
D31707: D317.07
D31708: D317.08 SITE3.30(RXD1N)
D31709: D317.09
D31710: D317.10 SITE3.32(RXD2P)
D31711: D317.11
D31712: D317.12 SITE3.33(RXD2N)
D31713: D317.13
D31714: D317.14 SITE3.35(RXD3P)
D31715: D317.15
D31716: D317.16 SITE3.36(RXD3N)
D31801: D318.01
D31802: D318.02
D31803: D318.03
D31804: D318.04
D31805: D318.05
D31806: D318.06
D31807: D318.07
D31808: D318.08
D31809: D318.09
D31810: D318.10
D31811: D318.11
D31812: D318.12
D31813: D318.13
D31814: D318.14
D31815: D318.15
D31816: D318.16
D32101: D321.01
D32102: D321.02 SITE1.26(RXD0P)
D32103: D321.03
D32104: D321.04 SITE1.27(RXD0N)
D32105: D321.05
D32106: D321.06 SITE1.29(RXD1P)
D32107: D321.07
D32108: D321.08 SITE1.30(RXD1N)
D32109: D321.09
D32110: D321.10 SITE1.32(RXD2P)
D32111: D321.11
D32112: D321.12 SITE1.33(RXD2N)
D32113: D321.13
D32114: D321.14 SITE1.35(RXD3P)
D32115: D321.15
D32116: D321.16 SITE1.36(RXD3N)
D32201: D322.01
D32202: D322.02
D32203: D322.03
D32204: D322.04
D32205: D322.05
D32206: D322.06
D32207: D322.07
D32208: D322.08
D32209: D322.09
D32210: D322.10
D32211: D322.11
D32212: D322.12
D32213: D322.13
D32214: D322.14
D32215: D322.15
D32216: D322.16
MSDPS1_1F: DPS1.C03
MSDPS1_1GRD: DPS1.B02
MSDPS1_1GS: DPS1.A02
MSDPS1_1S: DPS1.C02
MSDPS1_2F: DPS1.C07
MSDPS1_2GRD: DPS1.B06
MSDPS1_2GS: DPS1.A06
MSDPS1_2S: DPS1.C06
MSDPS1_3F: DPS1.C13
MSDPS1_3GRD: DPS1.B12
MSDPS1_3GS: DPS1.A12
MSDPS1_3S: DPS1.C12
MSDPS1_4F: DPS1.C17
MSDPS1_4GRD: DPS1.B16
MSDPS1_4GS: DPS1.A16
MSDPS1_4S: DPS1.C16
MSDPS1_5F: DPS1.A03
MSDPS1_5GS: DPS1.B01
MSDPS1_5S: DPS1.B03
MSDPS1_6F: DPS1.A07
MSDPS1_6GS: DPS1.B05
MSDPS1_6S: DPS1.B07
MSDPS1_7F: DPS1.A13
MSDPS1_7GS: DPS1.B11
MSDPS1_7S: DPS1.B13
MSDPS1_8F: DPS1.A17
MSDPS1_8GS: DPS1.B15
MSDPS1_8S: DPS1.B17
MSDPS1_TR+: DPS1.A09
MSDPS1_TRVB-: DPS1.B09 SB1.2
MSDPS1_VB+: DPS1.C09
MSDPS2_1F: DPS2.C03
MSDPS2_1GRD: DPS2.B02
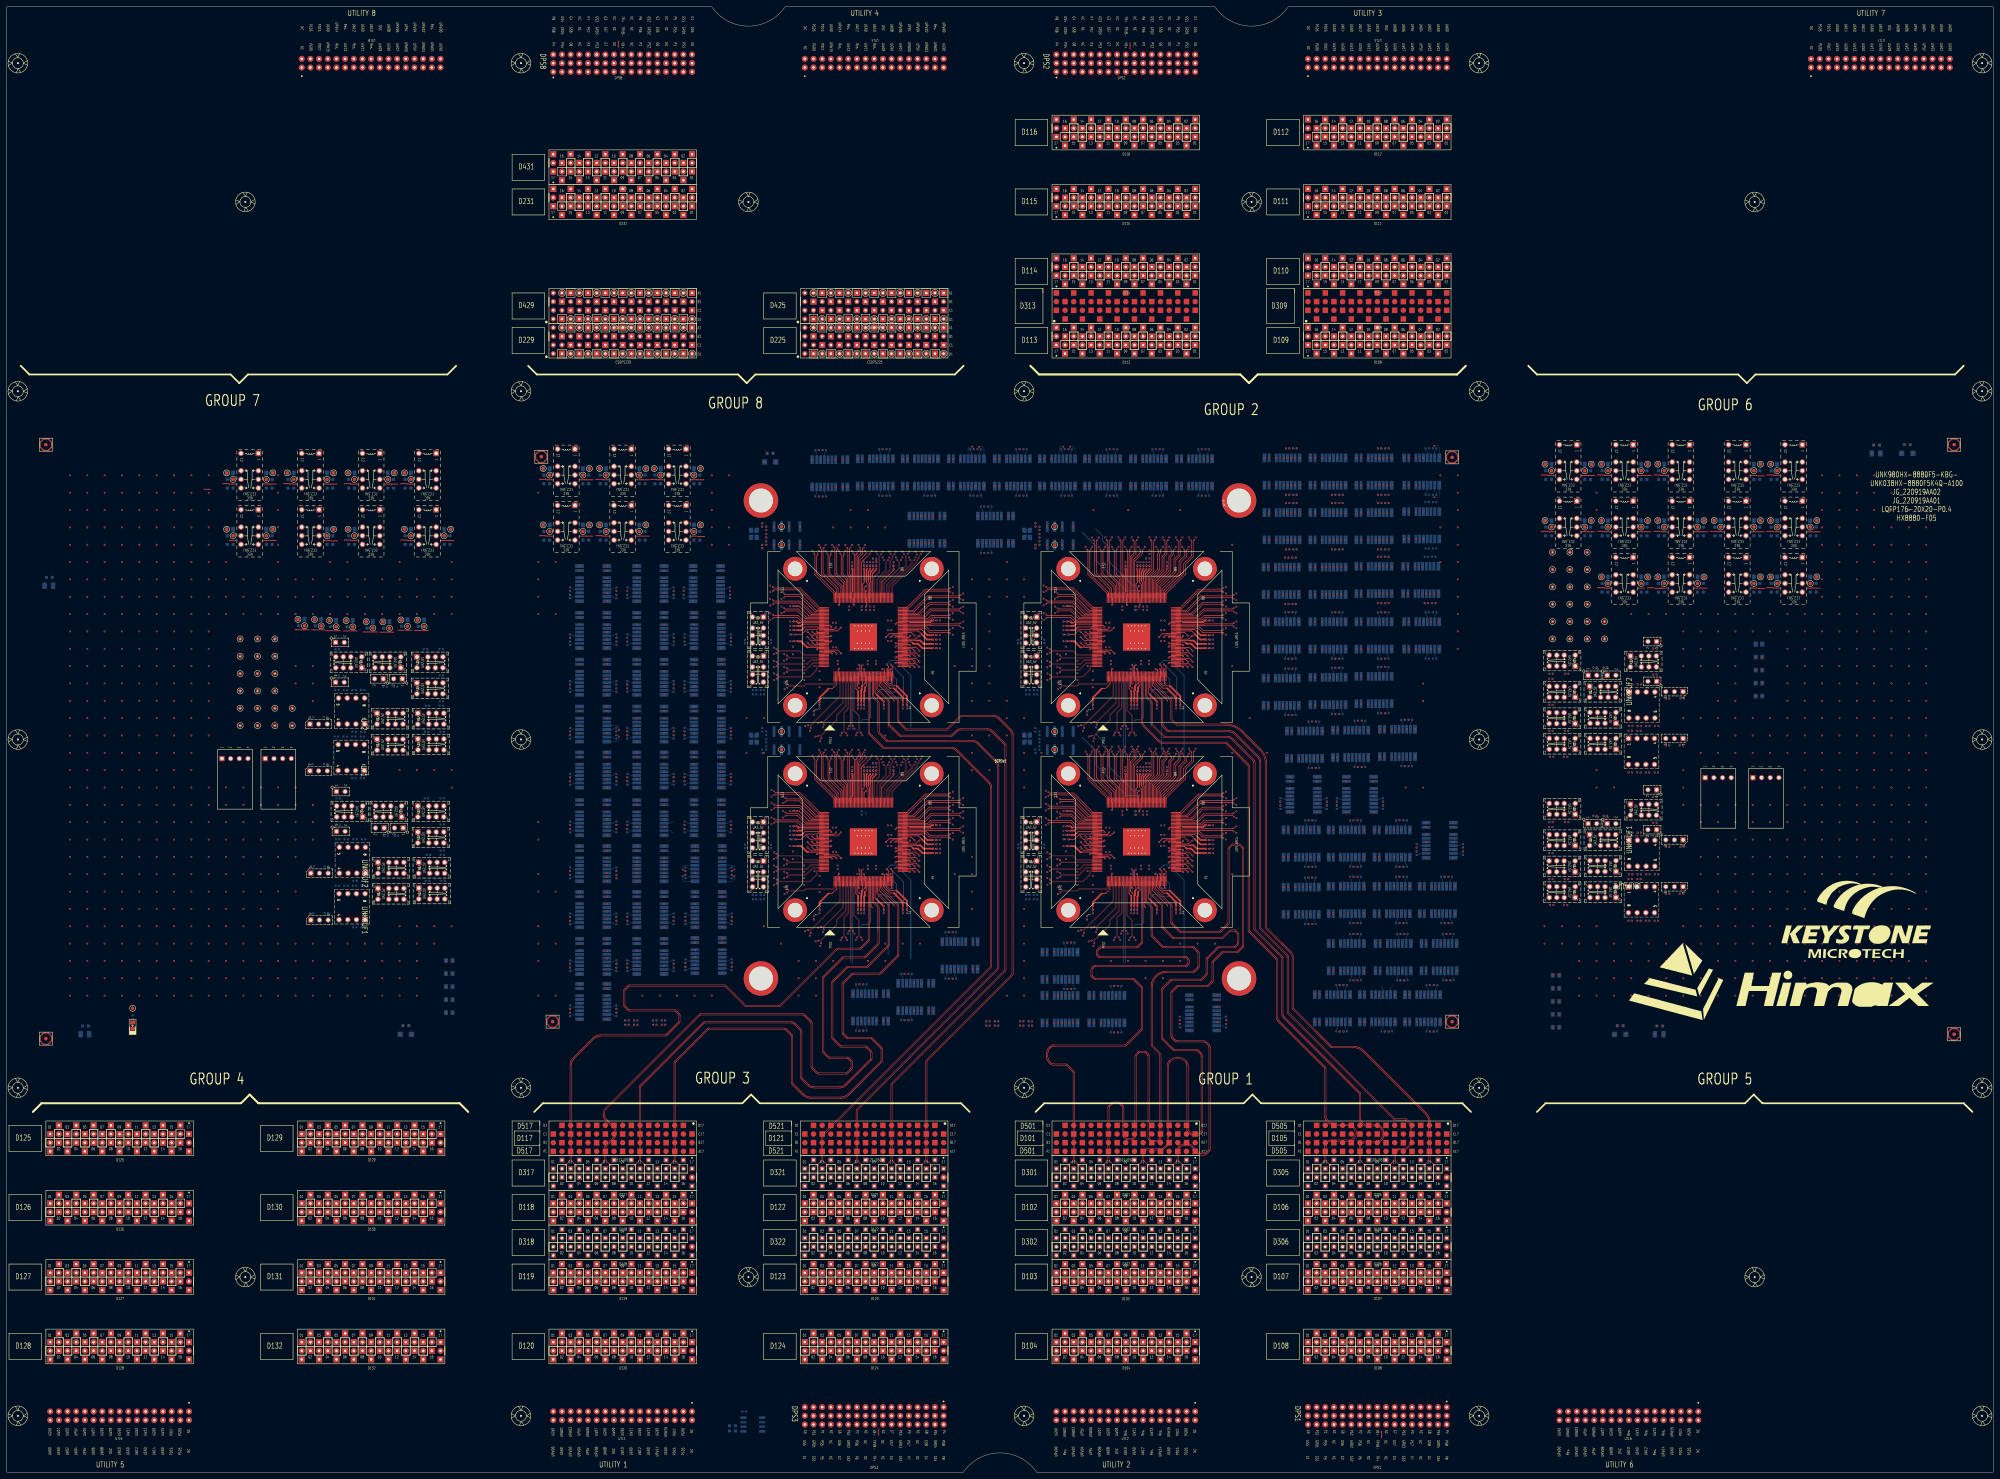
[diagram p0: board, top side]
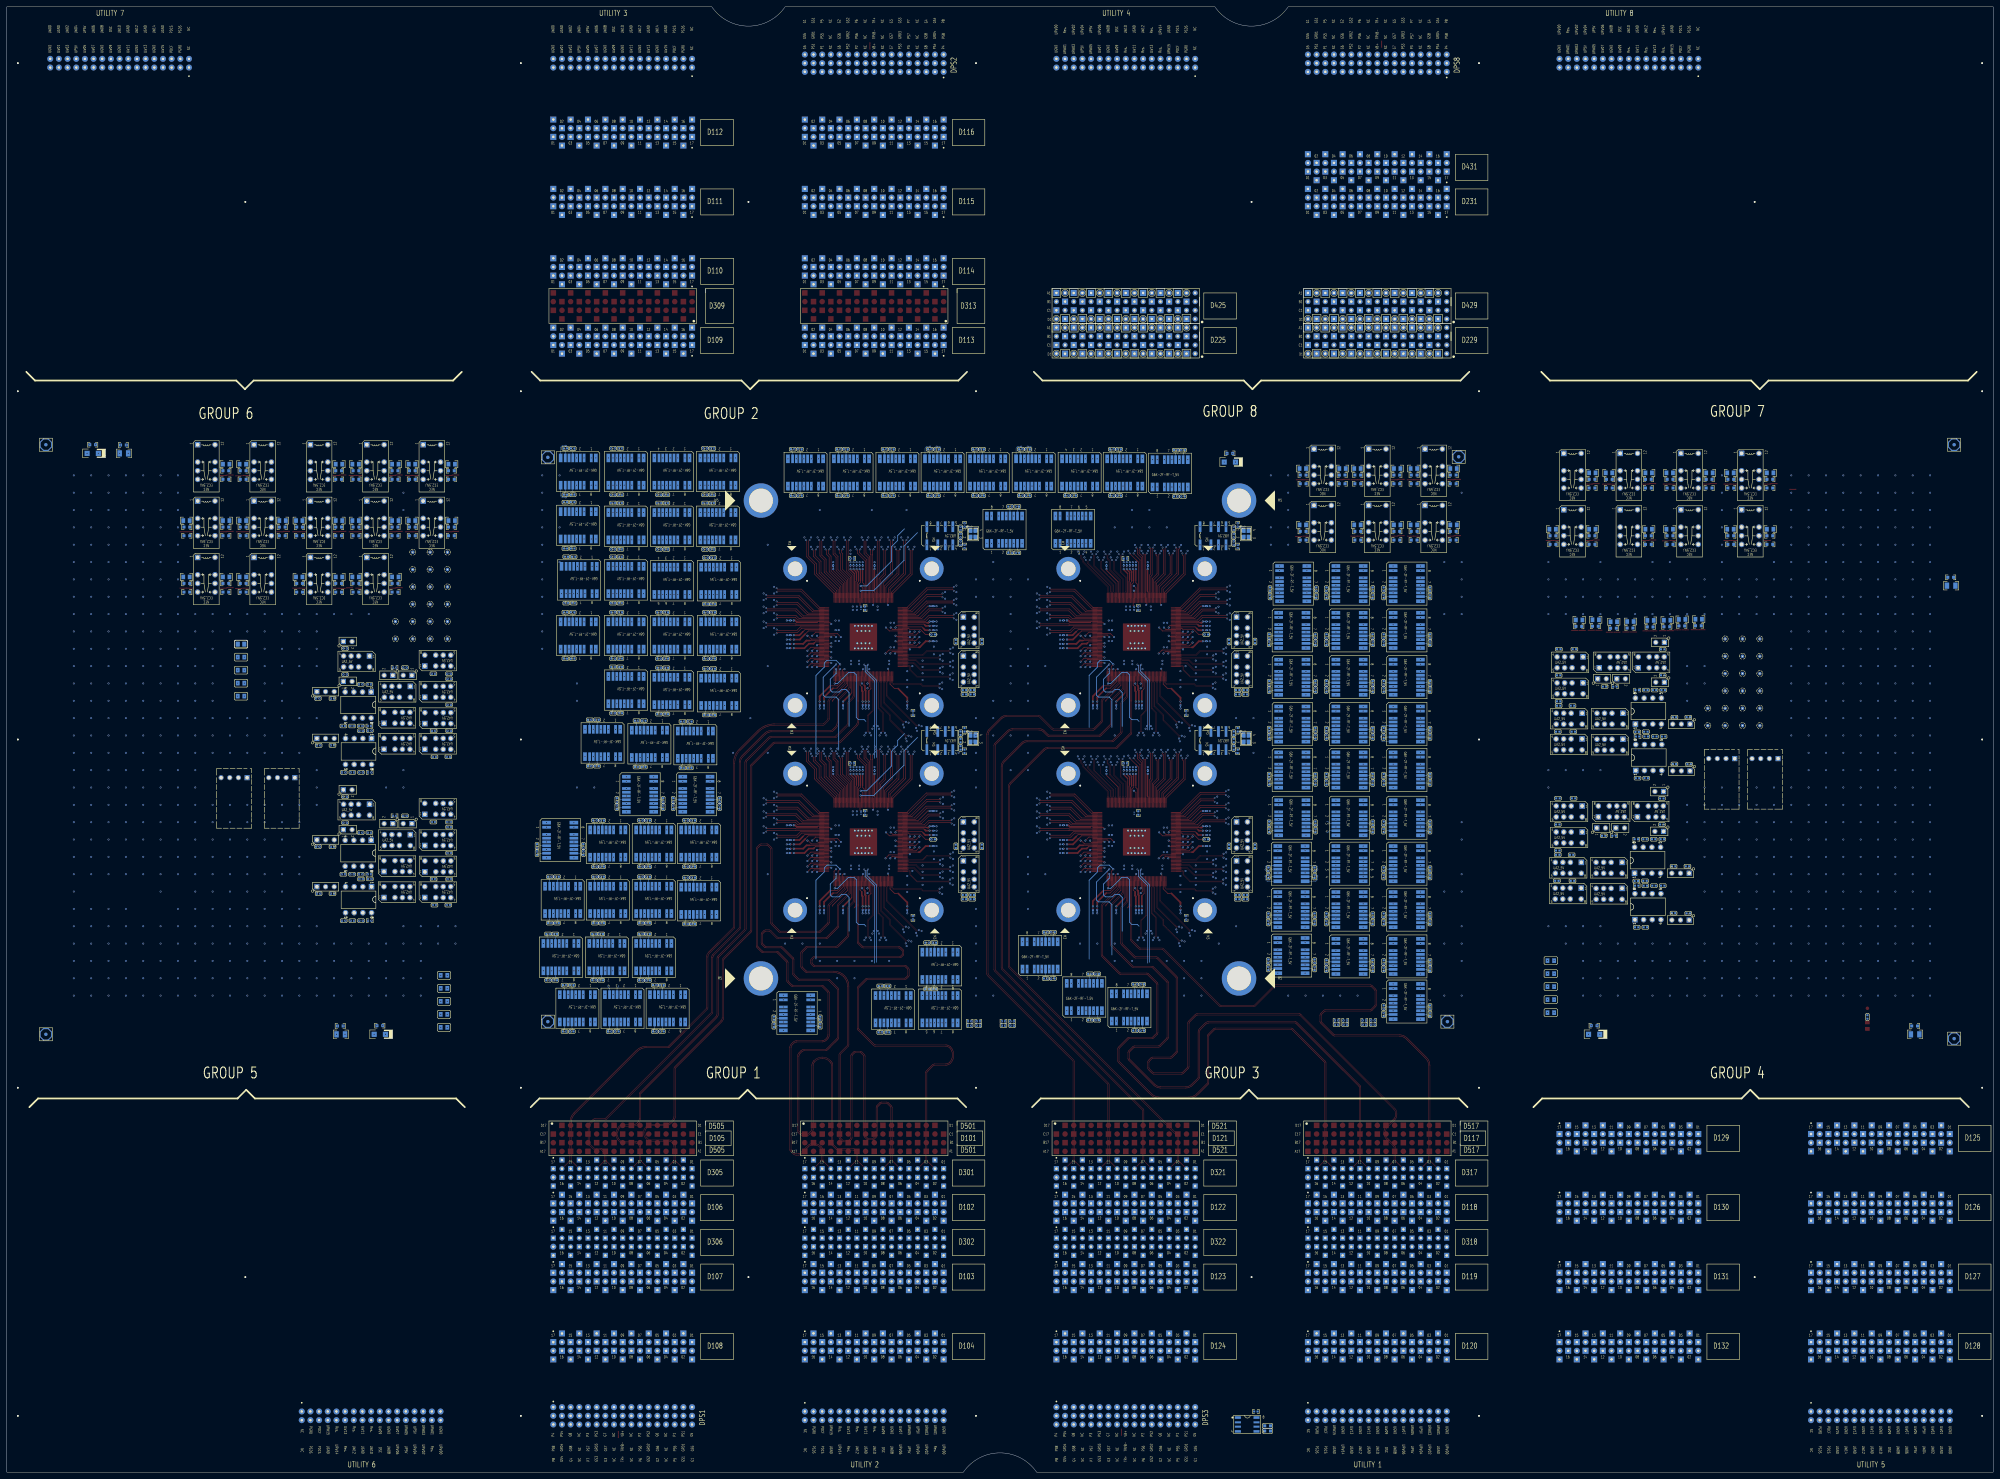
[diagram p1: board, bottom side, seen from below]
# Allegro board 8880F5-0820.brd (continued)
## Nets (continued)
MSDPS2_1GS: DPS2.A02
MSDPS2_1S: DPS2.C02
MSDPS2_2F: DPS2.C07
MSDPS2_2GRD: DPS2.B06
MSDPS2_2GS: DPS2.A06
MSDPS2_2S: DPS2.C06
MSDPS2_3F: DPS2.C13
MSDPS2_3GRD: DPS2.B12
MSDPS2_3GS: DPS2.A12
MSDPS2_3S: DPS2.C12
MSDPS2_4F: DPS2.C17
MSDPS2_4GRD: DPS2.B16
MSDPS2_4GS: DPS2.A16
MSDPS2_4S: DPS2.C16
MSDPS2_5F: DPS2.A03
MSDPS2_5GS: DPS2.B01
MSDPS2_5S: DPS2.B03
MSDPS2_6F: DPS2.A07
MSDPS2_6GS: DPS2.B05
MSDPS2_6S: DPS2.B07
MSDPS2_7F: DPS2.A13
MSDPS2_7GS: DPS2.B11
MSDPS2_7S: DPS2.B13
MSDPS2_8F: DPS2.A17
MSDPS2_8GS: DPS2.B15
MSDPS2_8S: DPS2.B17
MSDPS2_TR+: DPS2.A09
MSDPS2_TRVB-: DPS2.B09 SB2.2
MSDPS2_VB+: DPS2.C09
MSDPS3_1F: DPS3.C03
MSDPS3_1GRD: DPS3.B02
MSDPS3_1GS: DPS3.A02
MSDPS3_1S: DPS3.C02
MSDPS3_2F: DPS3.C07
MSDPS3_2GRD: DPS3.B06
MSDPS3_2GS: DPS3.A06
MSDPS3_2S: DPS3.C06
MSDPS3_3F: DPS3.C13
MSDPS3_3GRD: DPS3.B12
MSDPS3_3GS: DPS3.A12
MSDPS3_3S: DPS3.C12
MSDPS3_4F: DPS3.C17
MSDPS3_4GRD: DPS3.B16
MSDPS3_4GS: DPS3.A16
MSDPS3_4S: DPS3.C16
MSDPS3_5F: DPS3.A03
MSDPS3_5GS: DPS3.B01
MSDPS3_5S: DPS3.B03
MSDPS3_6F: DPS3.A07
MSDPS3_6GS: DPS3.B05
MSDPS3_6S: DPS3.B07
MSDPS3_7F: DPS3.A13
MSDPS3_7GS: DPS3.B11
MSDPS3_7S: DPS3.B13
MSDPS3_8F: DPS3.A17
MSDPS3_8GS: DPS3.B15
MSDPS3_8S: DPS3.B17
MSDPS3_TR+: DPS3.A09
MSDPS3_TRVB-: DPS3.B09 SB3.2
MSDPS3_VB+: DPS3.C09
MSDPS8_1F: DPS8.C03
MSDPS8_1GRD: DPS8.B02
MSDPS8_1GS: DPS8.A02
MSDPS8_1S: DPS8.C02
MSDPS8_2F: DPS8.C07
MSDPS8_2GRD: DPS8.B06
MSDPS8_2GS: DPS8.A06
MSDPS8_2S: DPS8.C06
MSDPS8_3F: DPS8.C13
MSDPS8_3GRD: DPS8.B12
MSDPS8_3GS: DPS8.A12
MSDPS8_3S: DPS8.C12
MSDPS8_4F: DPS8.C17
MSDPS8_4GRD: DPS8.B16
MSDPS8_4GS: DPS8.A16
MSDPS8_4S: DPS8.C16
MSDPS8_5F: DPS8.A03
MSDPS8_5GS: DPS8.B01
MSDPS8_5S: DPS8.B03
MSDPS8_6F: DPS8.A07
MSDPS8_6GS: DPS8.B05
MSDPS8_6S: DPS8.B07
MSDPS8_7F: DPS8.A13
MSDPS8_7GS: DPS8.B11
MSDPS8_7S: DPS8.B13
MSDPS8_8F: DPS8.A17
MSDPS8_8GS: DPS8.B15
MSDPS8_8S: DPS8.B17
MSDPS8_TR+: DPS8.A09
MSDPS8_TRVB-: DPS8.B09 SB8.2
MSDPS8_VB+: DPS8.C09
S1_1AUX+: K9.4 R129.1
S1_1AUX-: K9.5 R130.1
S1_1SPI_CSN: K15.5 K19.6
S1_1SPI_SCK: K15.4 K19.3
S1_1SPI_SDI: K14.5 K20.6
S1_1SPI_SDO: K14.4 K20.3
S1_1TX_100DCH001+: K43.6 R7.1
S1_1TX_100DCH001-: K43.3 R8.2
S1_1TX_100DCH002+: R9.1 SITE1.75(AML1P)
S1_1TX_100DCH002-: R10.2 SITE1.76(AML1N)
S1_1TX_100DCH003+: R11.1 SITE1.79(AML2P)
S1_1TX_100DCH003-: R12.2 SITE1.80(AML2N)
S1_1TX_100DCH004+: R13.1 SITE1.81(AMLCKP)
S1_1TX_100DCH004-: R14.2 SITE1.82(AMLCKN)
S1_1TX_100DCH005+: R15.1 SITE1.83(AML3P)
S1_1TX_100DCH005-: R16.2 SITE1.84(AML3N)
S1_1TX_100DCH006+: R17.1 SITE1.85(AML4P)
S1_1TX_100DCH006-: R18.2 SITE1.86(AML4N)
S1_1TX_100DCH007+: R19.1 SITE1.87(AML5P)
S1_1TX_100DCH007-: R20.2 SITE1.88(AML5N)
S1_2AUX+: C3.1 R1.2 R3.1 R129.2
S1_2AUX-: C4.1 R2.2 R4.2 R130.2
S1_2TX_100DCH001+: R21.1 SITE1.89(BML0P)
S1_2TX_100DCH001-: R22.2 SITE1.90(BML0N)
S1_2TX_100DCH002+: R23.1 SITE1.91(BML1P)
S1_2TX_100DCH002-: R24.2 SITE1.92(BML1N)
S1_2TX_100DCH003+: R25.1 SITE1.93(BML2P)
S1_2TX_100DCH003-: R26.2 SITE1.94(BML2N)
S1_2TX_100DCH004+: R27.1 SITE1.95(BMLCKP)
S1_2TX_100DCH004-: R28.2 SITE1.96(BMLCKN)
S1_2TX_100DCH005+: R29.1 SITE1.98(BML3P)
S1_2TX_100DCH005-: R30.2 SITE1.99(BML3N)
S1_2TX_100DCH006+: R31.1 SITE1.100(BML4P)
S1_2TX_100DCH006-: R32.2 SITE1.101(BML4N)
S1_2TX_100DCH007+: R33.1 SITE1.102(BML5P)
S1_2TX_100DCH007-: R34.2 SITE1.103(BML5N)
S1_3TX_100DCH002+: R37.1 SITE1.114(CML1P)
S1_3TX_100DCH002-: R38.2 SITE1.115(CML1N)
S1_3TX_100DCH003+: R39.1 SITE1.116(CML2P)
S1_3TX_100DCH003-: R40.2 SITE1.117(CML2N)
S1_3TX_100DCH004+: R41.1 SITE1.120(CMLCKP)
S1_3TX_100DCH004-: R42.2 SITE1.121(CMLCKN)
S1_3TX_100DCH005+: R67.1 SITE1.122(CML3P)
S1_3TX_100DCH005-: R68.2 SITE1.123(CML3N)
S1_3TX_100DCH006+: R69.1 SITE1.124(CML4P)
S1_3TX_100DCH006-: R70.2 SITE1.125(CML4N)
S1_3TX_100DCH007+: R71.1 SITE1.126(CML5P)
S1_3TX_100DCH007-: R72.2 SITE1.127(CML5N)
S1_4TX_100DCH001+: R73.1 SITE1.129(DML0P)
S1_4TX_100DCH001-: R74.2 SITE1.130(DML0N)
S1_4TX_100DCH002+: R75.1 SITE1.131(DML1P)
S1_4TX_100DCH002-: R76.2 SITE1.132(DML1N)
S1_4TX_100DCH003+: R77.1 SITE1.133(DML2P)
S1_4TX_100DCH003-: R78.2 SITE1.134(DML2N)
S1_4TX_100DCH004+: R79.1 SITE1.135(DMLCKP)
S1_4TX_100DCH004-: R80.2 SITE1.136(DMLCKN)
S1_4TX_100DCH005+: R43.1 SITE1.137(DML3P)
S1_4TX_100DCH005-: R44.2 SITE1.138(DML3N)
S1_4TX_100DCH006+: R63.1 SITE1.140(DML4P)
S1_4TX_100DCH006-: R64.2 SITE1.141(DML4N)
S1_4TX_100DCH007+: R100.1 SITE1.142(DML5P)
S1_4TX_100DCH007-: R101.2 SITE1.143(DML5N)
S1_AUX_100DCH001+: K9.2
S1_AUX_100DCH001-: K9.7
S1_AUX_100DCH002+: C3.2
S1_AUX_100DCH002-: C4.2
S1_AUXCH+: K9.3 K12.3 SITE1.21(AUXCHP)
S1_AUXCH-: K9.6 K12.6 SITE1.20(AUXCHN)
S1_AVDD11_RX: CA9.1 CA10.1 CC13.1 CD9.1 K37.9 SH10.1 SITE1.31(AVDD11_RX) TP_AVDD11_RX.1(TP)
S1_AVDD11_XTAL: CA32.1 CA33.1 CC26.1 CD16.1 K31.4 SH23.1 SITE1.105(AVDD11_XTAL) TP_AVDD11_XTAL.1(TP)
S1_AVDD18_RX: CA7.1 CA8.1 CC11.1 CD8.1 K37.4 SH7.1 SITE1.25(AVDD18_RX) TP_AVDD18_RX.1(TP)
S1_DCH041: SITE1.159(STV2)
S1_DCH042: SITE1.160(STV1)
S1_DCH043: SITE1.161(POL)
S1_DCH044: SITE1.163(TP1)
S1_DCH045: SITE1.164(DC_EN)
S1_DCH046: SITE1.165(H2POL)
S1_DCH047: SITE1.166(SQINV)
S1_DCH048: K18.7
S1_DCH049: K18.2
S1_DPS_F_001: CA19.1 CA20.1 R1.1 R4.1 SH20.1 TP_AUXVCC.1(TP)
S1_DPS_F_002: CA1.1 CA2.1 CC1.1 CC2.1 CD1.1 K34.4 SH1.1 SITE1.3(VDDA_33_LV) TP_VDDA_33_LV.1(TP)
S1_DPS_F_003: CA3.1 CA4.1 CC4.1 CC30.1 CC31.1 CC32.1 CC33.1 CC34.1 CC35.1 CC42.1 CD3.1 CD17.1 CD18.1 CD19.1 CD20.1 CD21.1 CD22.1 K34.9 R85.1 SH3.1 SITE1.17(VDD_IO_33-1) SITE1.37(VDD_IO_33-2) SITE1.63(VDD_IO_33-3) SITE1.71(VDD_IO_33-4) SITE1.107(VDD_IO_33-5) SITE1.145(VDD_IO_33-6) SITE1.162(VDD_IO_33-7) TP_VDD_IO_33.1(TP)
S1_DPS_F_006: CA17.1 CA18.1 CC25.1 CC40.1 CD15.1 K42.4 SH18.1 SITE1.72(VDD_TXREG_33_B) TP_VDD_TXREG_33_B.1(TP)
S1_DPS_F_007: CA11.1 CA12.1 CC15.1 CC16.1 CC27.1 CC28.1 CD10.1 CD11.1 K39.4 SH12.1 SITE1.78(VDDTXPST_11_B-1) SITE1.97(VDDTXPST_11_B-2) TP_VDDTXPST_11_B.1(TP)
S1_DPS_F_009: CA13.1 CA14.1 CC19.1 CC20.1 CD13.1 K40.4 SH14.1 SITE1.106(PLL_M_VDD33) TP_PLL_M_VDD33.1(TP)
S1_DPS_F_010: CA15.1 CA16.1 CC22.1 CC23.1 CD14.1 K40.9 SH16.1 SITE1.111(PLL_TX_VDD33) TP_PLL_TX_VDD33.1(TP)
S1_DPS_F_011: CA35.1 CA36.1 CC17.1 CC29.1 CC37.1 CC38.1 CD12.1 CD24.1 K39.9 SH25.1 SITE1.119(VDDTXPST_11_T-1) SITE1.139(VDDTXPST_11_T-2) TP_VDDTXPST_11_T.1(TP)
S1_DPS_F_012: CA38.1 CA39.1 CC39.1 CC41.1 CD25.1 K42.9 SH27.1 SITE1.144(VDD_TXREG_33_T) TP_VDD_TXREG_33_T.1(TP)
S1_DPS_F_013: C8.1 C9.1 CA30.1 CA31.1 R82.2 R83.1 R84.1 R87.2 R88.2 R89.2 R90.2 R91.2 R92.2 R94.2 R95.2 R96.2 R97.2 R98.2 R99.2 R119.1 R120.1 SH22.1 TP_VCC3V3.1(TP) U1.8(VCC) U2.8(VCC)
S1_DPS_FS_001: SH20.2
S1_DPS_FS_002: SH1.2
S1_DPS_FS_003: SH3.2
S1_DPS_FS_004: SH7.2
S1_DPS_FS_005: SH10.2
S1_DPS_FS_006: SH18.2
S1_DPS_FS_007: SH12.2
S1_DPS_FS_008: SH23.2
S1_DPS_FS_009: SH14.2
S1_DPS_FS_010: SH16.2
S1_DPS_FS_011: SH25.2
S1_DPS_FS_012: SH27.2
S1_DPS_FS_013: SH22.2
S1_DPS_GS_001: SH19.2
S1_DPS_GS_002: SH2.2
S1_DPS_GS_003: SH4.2
S1_DPS_GS_004: SH8.2
S1_DPS_GS_005: SH9.2
S1_DPS_GS_006: SH17.2
S1_DPS_GS_007: SH11.2
S1_DPS_GS_008: SH24.2
S1_DPS_GS_009: SH13.2
S1_DPS_GS_010: SH15.2
S1_DPS_GS_011: SH26.2
S1_DPS_GS_012: SH28.2
S1_DPS_GS_013: SH21.2
S1_ISP00+: K43.7 SITE1.73(AML0P)
S1_ISP00-: K43.2 SITE1.74(AML0N)
S1_ISP14+: K43.5 SITE1.112(CML0P)
S1_ISP14-: K43.4 SITE1.113(CML0N)
S1_ISP_1LOCK: K33.3 R118.2
S1_M_DPS_F_001: CA5.1 CA6.1 CC6.1 CC7.1 CC8.1 CC9.1 CC36.1 CD4.1 CD5.1 CD6.1 CD7.1 CD23.1 K36.4 K36.9 SH5.1 SITE1.22(VDDC_11-1) SITE1.39(VDDC_11-2) SITE1.64(VDDC_11-3) SITE1.104(VDDC_11-4) SITE1.147(VDDC_11-5) TP_VDDC_11.1(TP)
S1_M_DPS_FS_001: SH5.2
S1_M_DPS_GS_001: SH6.2
S1_PS9G_DCH001: SITE1.18(TEST)
S1_PS9G_DCH002: K10.3 S1_RST_N.1 SITE1.19(RESET_N)
S1_PS9G_DCH003: SITE1.24(HPD)
S1_PS9G_DCH004: SITE1.40(AGEN)
S1_PS9G_DCH005: SITE1.45(STV_IN)
S1_PS9G_DCH006: SITE1.46(EIO1)
S1_PS9G_DCH007: SITE1.47(EIO2)
S1_PS9G_DCH009: SITE1.49(PWMI)
S1_PS9G_DCH010: J4.2 K28.3 S1_I2C.1 SITE1.50(I2C_SCL)
S1_PS9G_DCH011: J5.2 K28.6 S1_I2C.2 SITE1.51(I2C_SDA)
S1_PS9G_DCH014: SITE1.54(LED_SPI_SIN_A)
S1_PS9G_DCH015: SITE1.55(LED_SPI_SCLK_A)
S1_PS9G_DCH022: SITE1.65(LED_SPI_SO_A)
S1_PS9G_DCH023: SITE1.66(LED_SPI_SO_B)
S1_PS9G_DCH027: SITE1.70(OSD_SPI_SDO)
S1_PS9G_DCH028: SITE1.77(NC_VDDTX_11_B)
S1_PS9G_DCH029: SITE1.118(NC_VDDTX_11_T)
S1_PS9G_DCH030: R118.1 SITE1.148(ISP_LOCK)
S1_PS9G_DCH035: SITE1.153(CLK6)
S1_PS9G_DCH036: SITE1.154(CLK5)
S1_PS9G_DCH037: SITE1.155(CLK4)
S1_PS9G_DCH038: SITE1.156(CLK3)
S1_PS9G_DCH039: SITE1.157(CLK2)
S1_PS9G_DCH040: SITE1.158(CLK1)
S1_RLY_001: K1.8(V-) K2.8(V-)
S1_RLY_003: K3.8(V-) K4.8(V-)
S1_RLY_005: K5.8(V-) K6.8(V-)
S1_RLY_007: K7.8(V-)
S1_RLY_008: K8.8(V-) K11.8(V-)
S1_RLY_009: K9.8(V-)
S1_RLY_010: K10.8(V-)
S1_RLY_012: K12.8(V-)
S1_RLY_013: K13.8(V-)
S1_RLY_014: K14.8(V-)
S1_RLY_015: K15.8(V-)
S1_RLY_016: K16.8(V-) K17.8(V-)
S1_RLY_018: K18.8(V-)
S1_RLY_019: K19.8(V-)
S1_RLY_020: K20.8(V-)
S1_RLY_021: K21.8(V-) K29.8(V-)
S1_RLY_022: K22.8(V-) K24.8(V-)
S1_RLY_023: K23.8(V-)
S1_RLY_025: K25.8(V-) K27.8(V-)
S1_RLY_026: K26.8(V-)
S1_RLY_028: K28.8(V-)
S1_RLY_030: K30.8(V-)
S1_RLY_031: K31.12(V-)
S1_RLY_033: K33.8(V-)
S1_RLY_034: K34.12(V-)
S1_RLY_036: K36.12(V-)
S1_RLY_037: K37.12(V-)
S1_RLY_039: K39.12(V-)
S1_RLY_040: K40.12(V-)
S1_RLY_042: K42.12(V-)
S1_RLY_043: K43.8(V-)
S1_SCAN_DCH008: SITE1.48(FAIL_FLAG_O)
S1_SCAN_DCH012: SITE1.52(LED_SPI_BLANK_A)
S1_SCAN_DCH013: SITE1.53(LED_SPI_GSCLK_A)
S1_SCAN_DCH016: SITE1.56(LED_SPI_XLAT_A)
S1_SCAN_DCH017: SITE1.57(LED_SPI_BLANK_B)
S1_SCAN_DCH018: SITE1.58(LED_SPI_GSCLK_B)
S1_SCAN_DCH019: SITE1.59(LED_SPI_SIN_B)
S1_SCAN_DCH020: SITE1.60(LED_SPI_SCLK_B)
S1_SCAN_DCH021: SITE1.61(LED_SPI_XLAT_B)
S1_SCAN_DCH024: K13.3 SITE1.67(OSD_SPI_SCK_I2CCLK)
S1_SCAN_DCH025: K13.6 SITE1.68(OSD_SPI_SDI_I2CDAT)
S1_SCAN_DCH026: SITE1.69(OSD_SPI_CSN)
S1_SCAN_DCH031: SITE1.149(OE2)
S1_SCAN_DCH032: SITE1.150(OE1)
S1_SCAN_DCH033: SITE1.151(CLK8)
S1_SCAN_DCH034: SITE1.152(CLK7)
S1_SCAN_DCH050: K15.2
S1_SCAN_DCH051: K15.7
S1_SCAN_DCH052: K14.2
S1_SCAN_DCH053: K14.7
S1_SPI_1_CSN: K19.7 R87.1 U1.1(CS#)
S1_SPI_1_SCK: K19.2 R91.1 U1.6(SCLK)
S1_SPI_1_SDI: K20.7 R127.1
S1_SPI_1_SDO: K20.2 R125.1
S1_SPI_2_CSN: K19.5 R94.1 U2.1(CS#)
S1_SPI_2_SCK: K19.4 R98.1 U2.6(SCLK)
S1_SPI_2_SDI: K20.5 R128.1
S1_SPI_2_SDO: K20.4 R126.1
S1_SPI_11_SDI: R88.1 R127.2 U1.2(SO)
S1_SPI_11_SDO: R92.1 R125.2 U1.5(SI)
S1_SPI_22_SDI: R95.1 R128.2 U2.2(SO)
S1_SPI_22_SDO: R99.1 R126.2 U2.5(SI)
S1_SPI_CSN: K15.6 SITE1.43(SPI_CSN)
S1_SPI_SCK: K15.3 SITE1.42(SPI_SCK)
S1_SPI_SDI: K14.6 SITE1.44(SPI_SDI)
S1_SPI_SDO: K14.3 SITE1.41(SPI_SDO)
S1_XTAL_IN: K18.3 SITE1.109(XTAL_IN) TP_XTAL_IN.1(TP)
S1_XTAL_OUT: K18.6 SITE1.110(XTAL_OUT) TP_XTAL_OUT.1(TP)
S2_1AUX+: UNK2K9.4 UNK2R129.1
S2_1AUX-: UNK2K9.5 UNK2R130.1
S2_1SPI_CSN: UNK2K15.5 UNK2K19.6
S2_1SPI_SCK: UNK2K15.4 UNK2K19.3
S2_1SPI_SDI: UNK2K14.5 UNK2K20.6
S2_1SPI_SDO: UNK2K14.4 UNK2K20.3
S2_1TX_100DCH001+: UNK2K43.6 UNK2R7.1
S2_1TX_100DCH001-: UNK2K43.3 UNK2R8.2
S2_1TX_100DCH002+: SITE2.75(AML1P) UNK2R9.1
S2_1TX_100DCH002-: SITE2.76(AML1N) UNK2R10.2
S2_1TX_100DCH003+: SITE2.79(AML2P) UNK2R11.1
S2_1TX_100DCH003-: SITE2.80(AML2N) UNK2R12.2
S2_1TX_100DCH004+: SITE2.81(AMLCKP) UNK2R13.1
S2_1TX_100DCH004-: SITE2.82(AMLCKN) UNK2R14.2
S2_1TX_100DCH005+: SITE2.83(AML3P) UNK2R15.1
S2_1TX_100DCH005-: SITE2.84(AML3N) UNK2R16.2
S2_1TX_100DCH006+: SITE2.85(AML4P) UNK2R17.1
S2_1TX_100DCH006-: SITE2.86(AML4N) UNK2R18.2
S2_1TX_100DCH007+: SITE2.87(AML5P) UNK2R19.1
S2_1TX_100DCH007-: SITE2.88(AML5N) UNK2R20.2
S2_2AUX+: UNK2C3.1 UNK2R1.2 UNK2R3.1 UNK2R129.2
S2_2AUX-: UNK2C4.1 UNK2R2.2 UNK2R4.2 UNK2R130.2
S2_2TX_100DCH001+: SITE2.89(BML0P) UNK2R21.1
S2_2TX_100DCH001-: SITE2.90(BML0N) UNK2R22.2
S2_2TX_100DCH002+: SITE2.91(BML1P) UNK2R23.1
S2_2TX_100DCH002-: SITE2.92(BML1N) UNK2R24.2
S2_2TX_100DCH003+: SITE2.93(BML2P) UNK2R25.1
S2_2TX_100DCH003-: SITE2.94(BML2N) UNK2R26.2
S2_2TX_100DCH004+: SITE2.95(BMLCKP) UNK2R27.1
S2_2TX_100DCH004-: SITE2.96(BMLCKN) UNK2R28.2
S2_2TX_100DCH005+: SITE2.98(BML3P) UNK2R29.1
S2_2TX_100DCH005-: SITE2.99(BML3N) UNK2R30.2
S2_2TX_100DCH006+: SITE2.100(BML4P) UNK2R31.1
S2_2TX_100DCH006-: SITE2.101(BML4N) UNK2R32.2
S2_2TX_100DCH007+: SITE2.102(BML5P) UNK2R33.1
S2_2TX_100DCH007-: SITE2.103(BML5N) UNK2R34.2
S2_3TX_100DCH002+: SITE2.114(CML1P) UNK2R37.1
S2_3TX_100DCH002-: SITE2.115(CML1N) UNK2R38.2
S2_3TX_100DCH003+: SITE2.116(CML2P) UNK2R39.1
S2_3TX_100DCH003-: SITE2.117(CML2N) UNK2R40.2
S2_3TX_100DCH004+: SITE2.120(CMLCKP) UNK2R41.1
S2_3TX_100DCH004-: SITE2.121(CMLCKN) UNK2R42.2
S2_3TX_100DCH005+: SITE2.122(CML3P) UNK2R67.1
S2_3TX_100DCH005-: SITE2.123(CML3N) UNK2R68.2
S2_3TX_100DCH006+: SITE2.124(CML4P) UNK2R69.1
S2_3TX_100DCH006-: SITE2.125(CML4N) UNK2R70.2
S2_3TX_100DCH007+: SITE2.126(CML5P) UNK2R71.1
S2_3TX_100DCH007-: SITE2.127(CML5N) UNK2R72.2
S2_4TX_100DCH001+: SITE2.129(DML0P) UNK2R73.1
S2_4TX_100DCH001-: SITE2.130(DML0N) UNK2R74.2
S2_4TX_100DCH002+: SITE2.131(DML1P) UNK2R75.1
S2_4TX_100DCH002-: SITE2.132(DML1N) UNK2R76.2
S2_4TX_100DCH003+: SITE2.133(DML2P) UNK2R77.1
S2_4TX_100DCH003-: SITE2.134(DML2N) UNK2R78.2
S2_4TX_100DCH004+: SITE2.135(DMLCKP) UNK2R79.1
S2_4TX_100DCH004-: SITE2.136(DMLCKN) UNK2R80.2
S2_4TX_100DCH005+: SITE2.137(DML3P) UNK2R43.1
S2_4TX_100DCH005-: SITE2.138(DML3N) UNK2R44.2
S2_4TX_100DCH006+: SITE2.140(DML4P) UNK2R63.1
S2_4TX_100DCH006-: SITE2.141(DML4N) UNK2R64.2
S2_4TX_100DCH007+: SITE2.142(DML5P) UNK2R100.1
S2_4TX_100DCH007-: SITE2.143(DML5N) UNK2R101.2
S2_AUX_100DCH001+: UNK2K9.2
S2_AUX_100DCH001-: UNK2K9.7
S2_AUX_100DCH002+: UNK2C3.2
S2_AUX_100DCH002-: UNK2C4.2
S2_AUXCH+: SITE2.21(AUXCHP) UNK2K9.3 UNK2K12.3
S2_AUXCH-: SITE2.20(AUXCHN) UNK2K9.6 UNK2K12.6
S2_AVDD11_RX: SITE2.31(AVDD11_RX) UNK2CA9.1 UNK2CA10.1 UNK2CC13.1 UNK2CD9.1 UNK2K37.9 UNK2SH10.1 UNK2TP_AVDD11_RX.1
S2_AVDD11_XTAL: SITE2.105(AVDD11_XTAL) UNK2CA32.1 UNK2CA33.1 UNK2CC26.1 UNK2CD16.1 UNK2K31.4 UNK2SH23.1 UNK2TP_AVDD11_XTAL.1
S2_AVDD18_RX: SITE2.25(AVDD18_RX) UNK2CA7.1 UNK2CA8.1 UNK2CC11.1 UNK2CD8.1 UNK2K37.4 UNK2SH7.1 UNK2TP_AVDD18_RX.1
S2_DCH041: SITE2.159(STV2)
S2_DCH042: SITE2.160(STV1)
S2_DCH043: SITE2.161(POL)
S2_DCH044: SITE2.163(TP1)
S2_DCH045: SITE2.164(DC_EN)
S2_DCH046: SITE2.165(H2POL)
S2_DCH047: SITE2.166(SQINV)
S2_DCH048: UNK2K18.7
S2_DCH049: UNK2K18.2
S2_DPS_F_001: UNK2CA19.1 UNK2CA20.1 UNK2R1.1 UNK2R4.1 UNK2SH20.1 UNK2TP_AUXVCC.1
S2_DPS_F_002: SITE2.3(VDDA_33_LV) UNK2CA1.1 UNK2CA2.1 UNK2CC1.1 UNK2CC2.1 UNK2CD1.1 UNK2K34.4 UNK2SH1.1 UNK2TP_VDDA_33_LV.1
S2_DPS_F_003: SITE2.17(VDD_IO_33-1) SITE2.37(VDD_IO_33-2) SITE2.63(VDD_IO_33-3) SITE2.71(VDD_IO_33-4) SITE2.107(VDD_IO_33-5) SITE2.145(VDD_IO_33-6) SITE2.162(VDD_IO_33-7) UNK2CA3.1 UNK2CA4.1 UNK2CC4.1 UNK2CC30.1 UNK2CC31.1 UNK2CC32.1 UNK2CC33.1 UNK2CC34.1 UNK2CC35.1 UNK2CC42.1 UNK2CD3.1 UNK2CD17.1 UNK2CD18.1 UNK2CD19.1 UNK2CD20.1 UNK2CD21.1 UNK2CD22.1 UNK2K34.9 UNK2R85.1 UNK2SH3.1 UNK2TP_VDD_IO_33.1
S2_DPS_F_006: SITE2.72(VDD_TXREG_33_B) UNK2CA17.1 UNK2CA18.1 UNK2CC25.1 UNK2CC40.1 UNK2CD15.1 UNK2K42.4 UNK2SH18.1 UNK2TP_VDD_TXREG_33_B.1
S2_DPS_F_007: SITE2.78(VDDTXPST_11_B-1) SITE2.97(VDDTXPST_11_B-2) UNK2CA11.1 UNK2CA12.1 UNK2CC15.1 UNK2CC16.1 UNK2CC27.1 UNK2CC28.1 UNK2CD10.1 UNK2CD11.1 UNK2K39.4 UNK2SH12.1 UNK2TP_VDDTXPST_11_B.1
S2_DPS_F_009: SITE2.106(PLL_M_VDD33) UNK2CA13.1 UNK2CA14.1 UNK2CC19.1 UNK2CC20.1 UNK2CD13.1 UNK2K40.4 UNK2SH14.1 UNK2TP_PLL_M_VDD33.1
S2_DPS_F_010: SITE2.111(PLL_TX_VDD33) UNK2CA15.1 UNK2CA16.1 UNK2CC22.1 UNK2CC23.1 UNK2CD14.1 UNK2K40.9 UNK2SH16.1 UNK2TP_PLL_TX_VDD33.1
S2_DPS_F_011: SITE2.119(VDDTXPST_11_T-1) SITE2.139(VDDTXPST_11_T-2) UNK2CA35.1 UNK2CA36.1 UNK2CC17.1 UNK2CC29.1 UNK2CC37.1 UNK2CC38.1 UNK2CD12.1 UNK2CD24.1 UNK2K39.9 UNK2SH25.1 UNK2TP_VDDTXPST_11_T.1
S2_DPS_F_012: SITE2.144(VDD_TXREG_33_T) UNK2CA38.1 UNK2CA39.1 UNK2CC39.1 UNK2CC41.1 UNK2CD25.1 UNK2K42.9 UNK2SH27.1 UNK2TP_VDD_TXREG_33_T.1
S2_DPS_F_013: UNK2C8.1 UNK2C9.1 UNK2CA30.1 UNK2CA31.1 UNK2R82.2 UNK2R83.1 UNK2R84.1 UNK2R87.2 UNK2R88.2 UNK2R89.2 UNK2R90.2 UNK2R91.2 UNK2R92.2 UNK2R94.2 UNK2R95.2 UNK2R96.2 UNK2R97.2 UNK2R98.2 UNK2R99.2 UNK2R119.1 UNK2R120.1 UNK2SH22.1 UNK2TP_VCC3V3.1 UNK2U1.8 UNK2U2.8
S2_DPS_FS_001: UNK2SH20.2
S2_DPS_FS_002: UNK2SH1.2
S2_DPS_FS_003: UNK2SH3.2
S2_DPS_FS_004: UNK2SH7.2
S2_DPS_FS_005: UNK2SH10.2
S2_DPS_FS_006: UNK2SH18.2
S2_DPS_FS_007: UNK2SH12.2
S2_DPS_FS_008: UNK2SH23.2
S2_DPS_FS_009: UNK2SH14.2
S2_DPS_FS_010: UNK2SH16.2
S2_DPS_FS_011: UNK2SH25.2
S2_DPS_FS_012: UNK2SH27.2
S2_DPS_FS_013: UNK2SH22.2
S2_DPS_GS_001: UNK2SH19.2
S2_DPS_GS_002: UNK2SH2.2
S2_DPS_GS_003: UNK2SH4.2
S2_DPS_GS_004: UNK2SH8.2
S2_DPS_GS_005: UNK2SH9.2
S2_DPS_GS_006: UNK2SH17.2
S2_DPS_GS_007: UNK2SH11.2
S2_DPS_GS_008: UNK2SH24.2
S2_DPS_GS_009: UNK2SH13.2
S2_DPS_GS_010: UNK2SH15.2
S2_DPS_GS_011: UNK2SH26.2
S2_DPS_GS_012: UNK2SH28.2
S2_DPS_GS_013: UNK2SH21.2
S2_ISP00+: SITE2.73(AML0P) UNK2K43.7
S2_ISP00-: SITE2.74(AML0N) UNK2K43.2
S2_ISP14+: SITE2.112(CML0P) UNK2K43.5
S2_ISP14-: SITE2.113(CML0N) UNK2K43.4
S2_ISP_1LOCK: UNK2K33.3 UNK2R118.2
S2_M_DPS_F_001: SITE2.22(VDDC_11-1) SITE2.39(VDDC_11-2) SITE2.64(VDDC_11-3) SITE2.104(VDDC_11-4) SITE2.147(VDDC_11-5) UNK2CA5.1 UNK2CA6.1 UNK2CC6.1 UNK2CC7.1 UNK2CC8.1 UNK2CC9.1 UNK2CC36.1 UNK2CD4.1 UNK2CD5.1 UNK2CD6.1 UNK2CD7.1 UNK2CD23.1 UNK2K36.4 UNK2K36.9 UNK2SH5.1 UNK2TP_VDDC_11.1
S2_M_DPS_FS_001: UNK2SH5.2
S2_M_DPS_GS_001: UNK2SH6.2
S2_PS9G_DCH001: SITE2.18(TEST)
S2_PS9G_DCH002: S2_RST_N.1 SITE2.19(RESET_N) UNK2K10.3
S2_PS9G_DCH003: SITE2.24(HPD)
S2_PS9G_DCH004: SITE2.40(AGEN)
S2_PS9G_DCH005: SITE2.45(STV_IN)
S2_PS9G_DCH006: SITE2.46(EIO1)
S2_PS9G_DCH007: SITE2.47(EIO2)
S2_PS9G_DCH009: SITE2.49(PWMI)
S2_PS9G_DCH010: S2_I2C.1 SITE2.50(I2C_SCL) UNK2J4.2 UNK2K28.3
S2_PS9G_DCH011: S2_I2C.2 SITE2.51(I2C_SDA) UNK2J5.2 UNK2K28.6
S2_PS9G_DCH014: SITE2.54(LED_SPI_SIN_A)
S2_PS9G_DCH015: SITE2.55(LED_SPI_SCLK_A)
S2_PS9G_DCH022: SITE2.65(LED_SPI_SO_A)
S2_PS9G_DCH023: SITE2.66(LED_SPI_SO_B)
S2_PS9G_DCH027: SITE2.70(OSD_SPI_SDO)
S2_PS9G_DCH028: SITE2.77(NC_VDDTX_11_B)
S2_PS9G_DCH029: SITE2.118(NC_VDDTX_11_T)
S2_PS9G_DCH030: SITE2.148(ISP_LOCK) UNK2R118.1
S2_PS9G_DCH035: SITE2.153(CLK6)
S2_PS9G_DCH036: SITE2.154(CLK5)
S2_PS9G_DCH037: SITE2.155(CLK4)
S2_PS9G_DCH038: SITE2.156(CLK3)
S2_PS9G_DCH039: SITE2.157(CLK2)
S2_PS9G_DCH040: SITE2.158(CLK1)
S2_RLY_001: UNK2K1.8 UNK2K2.8
S2_RLY_003: UNK2K3.8 UNK2K4.8
S2_RLY_005: UNK2K5.8 UNK2K6.8
S2_RLY_007: UNK2K7.8
S2_RLY_008: UNK2K8.8 UNK2K11.8
S2_RLY_009: UNK2K9.8
S2_RLY_010: UNK2K10.8
S2_RLY_012: UNK2K12.8
S2_RLY_013: UNK2K13.8
S2_RLY_014: UNK2K14.8
S2_RLY_015: UNK2K15.8
S2_RLY_016: UNK2K16.8 UNK2K17.8
S2_RLY_018: UNK2K18.8
S2_RLY_019: UNK2K19.8
S2_RLY_020: UNK2K20.8
S2_RLY_021: UNK2K21.8 UNK2K29.8
S2_RLY_022: UNK2K22.8 UNK2K24.8
S2_RLY_023: UNK2K23.8
S2_RLY_025: UNK2K25.8 UNK2K27.8
S2_RLY_026: UNK2K26.8
S2_RLY_028: UNK2K28.8
S2_RLY_030: UNK2K30.8
S2_RLY_031: UNK2K31.12
S2_RLY_033: UNK2K33.8
S2_RLY_034: UNK2K34.12
S2_RLY_036: UNK2K36.12
S2_RLY_037: UNK2K37.12
S2_RLY_039: UNK2K39.12
S2_RLY_040: UNK2K40.12
S2_RLY_042: UNK2K42.12
S2_RLY_043: UNK2K43.8
S2_SCAN_DCH008: SITE2.48(FAIL_FLAG_O)
S2_SCAN_DCH012: SITE2.52(LED_SPI_BLANK_A)
S2_SCAN_DCH013: SITE2.53(LED_SPI_GSCLK_A)
S2_SCAN_DCH016: SITE2.56(LED_SPI_XLAT_A)
S2_SCAN_DCH017: SITE2.57(LED_SPI_BLANK_B)
S2_SCAN_DCH018: SITE2.58(LED_SPI_GSCLK_B)
S2_SCAN_DCH019: SITE2.59(LED_SPI_SIN_B)
S2_SCAN_DCH020: SITE2.60(LED_SPI_SCLK_B)
S2_SCAN_DCH021: SITE2.61(LED_SPI_XLAT_B)
S2_SCAN_DCH024: SITE2.67(OSD_SPI_SCK_I2CCLK) UNK2K13.3
S2_SCAN_DCH025: SITE2.68(OSD_SPI_SDI_I2CDAT) UNK2K13.6
S2_SCAN_DCH026: SITE2.69(OSD_SPI_CSN)
S2_SCAN_DCH031: SITE2.149(OE2)
S2_SCAN_DCH032: SITE2.150(OE1)
S2_SCAN_DCH033: SITE2.151(CLK8)
S2_SCAN_DCH034: SITE2.152(CLK7)
S2_SCAN_DCH050: UNK2K15.2
S2_SCAN_DCH051: UNK2K15.7
S2_SCAN_DCH052: UNK2K14.2
S2_SCAN_DCH053: UNK2K14.7
S2_SPI_1_CSN: UNK2K19.7 UNK2R87.1 UNK2U1.1
S2_SPI_1_SCK: UNK2K19.2 UNK2R91.1 UNK2U1.6
S2_SPI_1_SDI: UNK2K20.7 UNK2R127.1
S2_SPI_1_SDO: UNK2K20.2 UNK2R125.1
S2_SPI_2_CSN: UNK2K19.5 UNK2R94.1 UNK2U2.1
S2_SPI_2_SCK: UNK2K19.4 UNK2R98.1 UNK2U2.6
S2_SPI_2_SDI: UNK2K20.5 UNK2R128.1
S2_SPI_2_SDO: UNK2K20.4 UNK2R126.1
S2_SPI_11_SDI: UNK2R88.1 UNK2R127.2 UNK2U1.2
S2_SPI_11_SDO: UNK2R92.1 UNK2R125.2 UNK2U1.5
S2_SPI_22_SDI: UNK2R95.1 UNK2R128.2 UNK2U2.2
S2_SPI_22_SDO: UNK2R99.1 UNK2R126.2 UNK2U2.5
S2_SPI_CSN: SITE2.43(SPI_CSN) UNK2K15.6
S2_SPI_SCK: SITE2.42(SPI_SCK) UNK2K15.3
S2_SPI_SDI: SITE2.44(SPI_SDI) UNK2K14.6
S2_SPI_SDO: SITE2.41(SPI_SDO) UNK2K14.3
S2_XTAL_IN: SITE2.109(XTAL_IN) UNK2K18.3 UNK2TP_XTAL_IN.1
S2_XTAL_OUT: SITE2.110(XTAL_OUT) UNK2K18.6 UNK2TP_XTAL_OUT.1
S3_1AUX+: UNK3K9.4 UNK3R129.1
S3_1AUX-: UNK3K9.5 UNK3R130.1
S3_1SPI_CSN: UNK3K15.5 UNK3K19.6
S3_1SPI_SCK: UNK3K15.4 UNK3K19.3
S3_1SPI_SDI: UNK3K14.5 UNK3K20.6
S3_1SPI_SDO: UNK3K14.4 UNK3K20.3
S3_1TX_100DCH001+: UNK3K43.6 UNK3R7.1
S3_1TX_100DCH001-: UNK3K43.3 UNK3R8.2
S3_1TX_100DCH002+: SITE3.75(AML1P) UNK3R9.1
S3_1TX_100DCH002-: SITE3.76(AML1N) UNK3R10.2
S3_1TX_100DCH003+: SITE3.79(AML2P) UNK3R11.1
S3_1TX_100DCH003-: SITE3.80(AML2N) UNK3R12.2
S3_1TX_100DCH004+: SITE3.81(AMLCKP) UNK3R13.1
S3_1TX_100DCH004-: SITE3.82(AMLCKN) UNK3R14.2
S3_1TX_100DCH005+: SITE3.83(AML3P) UNK3R15.1
S3_1TX_100DCH005-: SITE3.84(AML3N) UNK3R16.2
S3_1TX_100DCH006+: SITE3.85(AML4P) UNK3R17.1
S3_1TX_100DCH006-: SITE3.86(AML4N) UNK3R18.2
S3_1TX_100DCH007+: SITE3.87(AML5P) UNK3R19.1
S3_1TX_100DCH007-: SITE3.88(AML5N) UNK3R20.2
S3_2AUX+: UNK3C3.1 UNK3R1.2 UNK3R3.1 UNK3R129.2
S3_2AUX-: UNK3C4.1 UNK3R2.2 UNK3R4.2 UNK3R130.2
S3_2TX_100DCH001+: SITE3.89(BML0P) UNK3R21.1
S3_2TX_100DCH001-: SITE3.90(BML0N) UNK3R22.2
S3_2TX_100DCH002+: SITE3.91(BML1P) UNK3R23.1
S3_2TX_100DCH002-: SITE3.92(BML1N) UNK3R24.2
S3_2TX_100DCH003+: SITE3.93(BML2P) UNK3R25.1
S3_2TX_100DCH003-: SITE3.94(BML2N) UNK3R26.2
S3_2TX_100DCH004+: SITE3.95(BMLCKP) UNK3R27.1
S3_2TX_100DCH004-: SITE3.96(BMLCKN) UNK3R28.2
S3_2TX_100DCH005+: SITE3.98(BML3P) UNK3R29.1
S3_2TX_100DCH005-: SITE3.99(BML3N) UNK3R30.2
S3_2TX_100DCH006+: SITE3.100(BML4P) UNK3R31.1
S3_2TX_100DCH006-: SITE3.101(BML4N) UNK3R32.2
S3_2TX_100DCH007+: SITE3.102(BML5P) UNK3R33.1
S3_2TX_100DCH007-: SITE3.103(BML5N) UNK3R34.2
S3_3TX_100DCH002+: SITE3.114(CML1P) UNK3R37.1
S3_3TX_100DCH002-: SITE3.115(CML1N) UNK3R38.2
S3_3TX_100DCH003+: SITE3.116(CML2P) UNK3R39.1
S3_3TX_100DCH003-: SITE3.117(CML2N) UNK3R40.2
S3_3TX_100DCH004+: SITE3.120(CMLCKP) UNK3R41.1
S3_3TX_100DCH004-: SITE3.121(CMLCKN) UNK3R42.2
S3_3TX_100DCH005+: SITE3.122(CML3P) UNK3R67.1
S3_3TX_100DCH005-: SITE3.123(CML3N) UNK3R68.2
S3_3TX_100DCH006+: SITE3.124(CML4P) UNK3R69.1
S3_3TX_100DCH006-: SITE3.125(CML4N) UNK3R70.2
S3_3TX_100DCH007+: SITE3.126(CML5P) UNK3R71.1
S3_3TX_100DCH007-: SITE3.127(CML5N) UNK3R72.2
S3_4TX_100DCH001+: SITE3.129(DML0P) UNK3R73.1
S3_4TX_100DCH001-: SITE3.130(DML0N) UNK3R74.2
S3_4TX_100DCH002+: SITE3.131(DML1P) UNK3R75.1
S3_4TX_100DCH002-: SITE3.132(DML1N) UNK3R76.2
S3_4TX_100DCH003+: SITE3.133(DML2P) UNK3R77.1
S3_4TX_100DCH003-: SITE3.134(DML2N) UNK3R78.2
S3_4TX_100DCH004+: SITE3.135(DMLCKP) UNK3R79.1
S3_4TX_100DCH004-: SITE3.136(DMLCKN) UNK3R80.2
S3_4TX_100DCH005+: SITE3.137(DML3P) UNK3R43.1
S3_4TX_100DCH005-: SITE3.138(DML3N) UNK3R44.2
S3_4TX_100DCH006+: SITE3.140(DML4P) UNK3R63.1
S3_4TX_100DCH006-: SITE3.141(DML4N) UNK3R64.2
S3_4TX_100DCH007+: SITE3.142(DML5P) UNK3R100.1
S3_4TX_100DCH007-: SITE3.143(DML5N) UNK3R101.2
S3_AUX_100DCH001+: UNK3K9.2
S3_AUX_100DCH001-: UNK3K9.7
S3_AUX_100DCH002+: UNK3C3.2
S3_AUX_100DCH002-: UNK3C4.2
S3_AUXCH+: SITE3.21(AUXCHP) UNK3K9.3 UNK3K12.3
S3_AUXCH-: SITE3.20(AUXCHN) UNK3K9.6 UNK3K12.6
S3_AVDD11_RX: SITE3.31(AVDD11_RX) UNK3CA9.1 UNK3CA10.1 UNK3CC13.1 UNK3CD9.1 UNK3K37.9 UNK3SH10.1 UNK3TP_AVDD11_RX.1
S3_AVDD11_XTAL: SITE3.105(AVDD11_XTAL) UNK3CA32.1 UNK3CA33.1 UNK3CC26.1 UNK3CD16.1 UNK3K31.4 UNK3SH23.1 UNK3TP_AVDD11_XTAL.1
S3_AVDD18_RX: SITE3.25(AVDD18_RX) UNK3CA7.1 UNK3CA8.1 UNK3CC11.1 UNK3CD8.1 UNK3K37.4 UNK3SH7.1 UNK3TP_AVDD18_RX.1
S3_DCH041: SITE3.159(STV2)
S3_DCH042: SITE3.160(STV1)
S3_DCH043: SITE3.161(POL)
S3_DCH044: SITE3.163(TP1)
S3_DCH045: SITE3.164(DC_EN)
S3_DCH046: SITE3.165(H2POL)
S3_DCH047: SITE3.166(SQINV)
S3_DCH048: UNK3K18.7
S3_DCH049: UNK3K18.2
S3_DPS_F_001: UNK3CA19.1 UNK3CA20.1 UNK3R1.1 UNK3R4.1 UNK3SH20.1 UNK3TP_AUXVCC.1
S3_DPS_F_002: SITE3.3(VDDA_33_LV) UNK3CA1.1 UNK3CA2.1 UNK3CC1.1 UNK3CC2.1 UNK3CD1.1 UNK3K34.4 UNK3SH1.1 UNK3TP_VDDA_33_LV.1
S3_DPS_F_003: SITE3.17(VDD_IO_33-1) SITE3.37(VDD_IO_33-2) SITE3.63(VDD_IO_33-3) SITE3.71(VDD_IO_33-4) SITE3.107(VDD_IO_33-5) SITE3.145(VDD_IO_33-6) SITE3.162(VDD_IO_33-7) UNK3CA3.1 UNK3CA4.1 UNK3CC4.1 UNK3CC30.1 UNK3CC31.1 UNK3CC32.1 UNK3CC33.1 UNK3CC34.1 UNK3CC35.1 UNK3CC42.1 UNK3CD3.1 UNK3CD17.1 UNK3CD18.1 UNK3CD19.1 UNK3CD20.1 UNK3CD21.1 UNK3CD22.1 UNK3K34.9 UNK3R85.1 UNK3SH3.1 UNK3TP_VDD_IO_33.1
S3_DPS_F_006: SITE3.72(VDD_TXREG_33_B) UNK3CA17.1 UNK3CA18.1 UNK3CC25.1 UNK3CC40.1 UNK3CD15.1 UNK3K42.4 UNK3SH18.1 UNK3TP_VDD_TXREG_33_B.1
S3_DPS_F_007: SITE3.78(VDDTXPST_11_B-1) SITE3.97(VDDTXPST_11_B-2) UNK3CA11.1 UNK3CA12.1 UNK3CC15.1 UNK3CC16.1 UNK3CC27.1 UNK3CC28.1 UNK3CD10.1 UNK3CD11.1 UNK3K39.4 UNK3SH12.1 UNK3TP_VDDTXPST_11_B.1
S3_DPS_F_009: SITE3.106(PLL_M_VDD33) UNK3CA13.1 UNK3CA14.1 UNK3CC19.1 UNK3CC20.1 UNK3CD13.1 UNK3K40.4 UNK3SH14.1 UNK3TP_PLL_M_VDD33.1
S3_DPS_F_010: SITE3.111(PLL_TX_VDD33) UNK3CA15.1 UNK3CA16.1 UNK3CC22.1 UNK3CC23.1 UNK3CD14.1 UNK3K40.9 UNK3SH16.1 UNK3TP_PLL_TX_VDD33.1
S3_DPS_F_011: SITE3.119(VDDTXPST_11_T-1) SITE3.139(VDDTXPST_11_T-2) UNK3CA35.1 UNK3CA36.1 UNK3CC17.1 UNK3CC29.1 UNK3CC37.1 UNK3CC38.1 UNK3CD12.1 UNK3CD24.1 UNK3K39.9 UNK3SH25.1 UNK3TP_VDDTXPST_11_T.1
S3_DPS_F_012: SITE3.144(VDD_TXREG_33_T) UNK3CA38.1 UNK3CA39.1 UNK3CC39.1 UNK3CC41.1 UNK3CD25.1 UNK3K42.9 UNK3SH27.1 UNK3TP_VDD_TXREG_33_T.1
S3_DPS_F_013: UNK3C8.1 UNK3C9.1 UNK3CA30.1 UNK3CA31.1 UNK3R82.2 UNK3R83.1 UNK3R84.1 UNK3R87.2 UNK3R88.2 UNK3R89.2 UNK3R90.2 UNK3R91.2 UNK3R92.2 UNK3R94.2 UNK3R95.2 UNK3R96.2 UNK3R97.2 UNK3R98.2 UNK3R99.2 UNK3R119.1 UNK3R120.1 UNK3SH22.1 UNK3TP_VCC3V3.1 UNK3U1.8 UNK3U2.8
S3_DPS_FS_001: UNK3SH20.2
S3_DPS_FS_002: UNK3SH1.2
S3_DPS_FS_003: UNK3SH3.2
S3_DPS_FS_004: UNK3SH7.2
S3_DPS_FS_005: UNK3SH10.2
S3_DPS_FS_006: UNK3SH18.2
S3_DPS_FS_007: UNK3SH12.2
S3_DPS_FS_008: UNK3SH23.2
S3_DPS_FS_009: UNK3SH14.2
S3_DPS_FS_010: UNK3SH16.2
S3_DPS_FS_011: UNK3SH25.2
S3_DPS_FS_012: UNK3SH27.2
S3_DPS_FS_013: UNK3SH22.2
S3_DPS_GS_001: UNK3SH19.2
S3_DPS_GS_002: UNK3SH2.2
S3_DPS_GS_003: UNK3SH4.2
S3_DPS_GS_004: UNK3SH8.2
S3_DPS_GS_005: UNK3SH9.2
S3_DPS_GS_006: UNK3SH17.2
S3_DPS_GS_007: UNK3SH11.2
S3_DPS_GS_008: UNK3SH24.2
S3_DPS_GS_009: UNK3SH13.2
S3_DPS_GS_010: UNK3SH15.2
S3_DPS_GS_011: UNK3SH26.2
S3_DPS_GS_012: UNK3SH28.2
S3_DPS_GS_013: UNK3SH21.2
S3_ISP00+: SITE3.73(AML0P) UNK3K43.7
S3_ISP00-: SITE3.74(AML0N) UNK3K43.2
S3_ISP14+: SITE3.112(CML0P) UNK3K43.5
S3_ISP14-: SITE3.113(CML0N) UNK3K43.4
S3_ISP_1LOCK: UNK3K33.3 UNK3R118.2
S3_M_DPS_F_001: SITE3.22(VDDC_11-1) SITE3.39(VDDC_11-2) SITE3.64(VDDC_11-3) SITE3.104(VDDC_11-4) SITE3.147(VDDC_11-5) UNK3CA5.1 UNK3CA6.1 UNK3CC6.1 UNK3CC7.1 UNK3CC8.1 UNK3CC9.1 UNK3CC36.1 UNK3CD4.1 UNK3CD5.1 UNK3CD6.1 UNK3CD7.1 UNK3CD23.1 UNK3K36.4 UNK3K36.9 UNK3SH5.1 UNK3TP_VDDC_11.1
S3_M_DPS_FS_001: UNK3SH5.2
S3_M_DPS_GS_001: UNK3SH6.2
S3_PS9G_DCH001: SITE3.18(TEST)
S3_PS9G_DCH002: S3_RST_N.1 SITE3.19(RESET_N) UNK3K10.3
S3_PS9G_DCH003: SITE3.24(HPD)
S3_PS9G_DCH004: SITE3.40(AGEN)
S3_PS9G_DCH005: SITE3.45(STV_IN)
S3_PS9G_DCH006: SITE3.46(EIO1)
S3_PS9G_DCH007: SITE3.47(EIO2)
S3_PS9G_DCH009: SITE3.49(PWMI)
S3_PS9G_DCH010: S3_I2C.1 SITE3.50(I2C_SCL) UNK3J4.2 UNK3K28.3
S3_PS9G_DCH011: S3_I2C.2 SITE3.51(I2C_SDA) UNK3J5.2 UNK3K28.6
S3_PS9G_DCH014: SITE3.54(LED_SPI_SIN_A)
S3_PS9G_DCH015: SITE3.55(LED_SPI_SCLK_A)
S3_PS9G_DCH022: SITE3.65(LED_SPI_SO_A)
S3_PS9G_DCH023: SITE3.66(LED_SPI_SO_B)
S3_PS9G_DCH027: SITE3.70(OSD_SPI_SDO)
S3_PS9G_DCH028: SITE3.77(NC_VDDTX_11_B)
S3_PS9G_DCH029: SITE3.118(NC_VDDTX_11_T)
S3_PS9G_DCH030: SITE3.148(ISP_LOCK) UNK3R118.1
S3_PS9G_DCH035: SITE3.153(CLK6)
S3_PS9G_DCH036: SITE3.154(CLK5)
S3_PS9G_DCH037: SITE3.155(CLK4)
S3_PS9G_DCH038: SITE3.156(CLK3)
S3_PS9G_DCH039: SITE3.157(CLK2)
S3_PS9G_DCH040: SITE3.158(CLK1)
S3_RLY_001: UNK3K1.8 UNK3K2.8
S3_RLY_003: UNK3K3.8 UNK3K4.8
S3_RLY_005: UNK3K5.8 UNK3K6.8
S3_RLY_007: UNK3K7.8
S3_RLY_008: UNK3K8.8 UNK3K11.8
S3_RLY_009: UNK3K9.8
S3_RLY_010: UNK3K10.8
S3_RLY_012: UNK3K12.8
S3_RLY_013: UNK3K13.8
S3_RLY_014: UNK3K14.8
S3_RLY_015: UNK3K15.8
S3_RLY_016: UNK3K16.8 UNK3K17.8
S3_RLY_018: UNK3K18.8
S3_RLY_019: UNK3K19.8
S3_RLY_020: UNK3K20.8
S3_RLY_021: UNK3K21.8 UNK3K29.8
S3_RLY_022: UNK3K22.8 UNK3K24.8
S3_RLY_023: UNK3K23.8
S3_RLY_025: UNK3K25.8 UNK3K27.8
S3_RLY_026: UNK3K26.8
S3_RLY_028: UNK3K28.8
S3_RLY_030: UNK3K30.8
S3_RLY_031: UNK3K31.12
S3_RLY_033: UNK3K33.8
S3_RLY_034: UNK3K34.12
S3_RLY_036: UNK3K36.12
S3_RLY_037: UNK3K37.12
S3_RLY_039: UNK3K39.12
S3_RLY_040: UNK3K40.12
S3_RLY_042: UNK3K42.12
S3_RLY_043: UNK3K43.8
S3_SCAN_DCH008: SITE3.48(FAIL_FLAG_O)
S3_SCAN_DCH012: SITE3.52(LED_SPI_BLANK_A)
S3_SCAN_DCH013: SITE3.53(LED_SPI_GSCLK_A)
S3_SCAN_DCH016: SITE3.56(LED_SPI_XLAT_A)
S3_SCAN_DCH017: SITE3.57(LED_SPI_BLANK_B)
S3_SCAN_DCH018: SITE3.58(LED_SPI_GSCLK_B)
S3_SCAN_DCH019: SITE3.59(LED_SPI_SIN_B)
S3_SCAN_DCH020: SITE3.60(LED_SPI_SCLK_B)
S3_SCAN_DCH021: SITE3.61(LED_SPI_XLAT_B)
S3_SCAN_DCH024: SITE3.67(OSD_SPI_SCK_I2CCLK) UNK3K13.3
S3_SCAN_DCH025: SITE3.68(OSD_SPI_SDI_I2CDAT) UNK3K13.6
S3_SCAN_DCH026: SITE3.69(OSD_SPI_CSN)
S3_SCAN_DCH031: SITE3.149(OE2)
S3_SCAN_DCH032: SITE3.150(OE1)
S3_SCAN_DCH033: SITE3.151(CLK8)
S3_SCAN_DCH034: SITE3.152(CLK7)
S3_SCAN_DCH050: UNK3K15.2
S3_SCAN_DCH051: UNK3K15.7
S3_SCAN_DCH052: UNK3K14.2
S3_SCAN_DCH053: UNK3K14.7
S3_SPI_1_CSN: UNK3K19.7 UNK3R87.1 UNK3U1.1
S3_SPI_1_SCK: UNK3K19.2 UNK3R91.1 UNK3U1.6
S3_SPI_1_SDI: UNK3K20.7 UNK3R127.1
S3_SPI_1_SDO: UNK3K20.2 UNK3R125.1
S3_SPI_2_CSN: UNK3K19.5 UNK3R94.1 UNK3U2.1
S3_SPI_2_SCK: UNK3K19.4 UNK3R98.1 UNK3U2.6
S3_SPI_2_SDI: UNK3K20.5 UNK3R128.1
S3_SPI_2_SDO: UNK3K20.4 UNK3R126.1
S3_SPI_11_SDI: UNK3R88.1 UNK3R127.2 UNK3U1.2
S3_SPI_11_SDO: UNK3R92.1 UNK3R125.2 UNK3U1.5
S3_SPI_22_SDI: UNK3R95.1 UNK3R128.2 UNK3U2.2
S3_SPI_22_SDO: UNK3R99.1 UNK3R126.2 UNK3U2.5
S3_SPI_CSN: SITE3.43(SPI_CSN) UNK3K15.6
S3_SPI_SCK: SITE3.42(SPI_SCK) UNK3K15.3
S3_SPI_SDI: SITE3.44(SPI_SDI) UNK3K14.6
S3_SPI_SDO: SITE3.41(SPI_SDO) UNK3K14.3
S3_XTAL_IN: SITE3.109(XTAL_IN) UNK3K18.3 UNK3TP_XTAL_IN.1
S3_XTAL_OUT: SITE3.110(XTAL_OUT) UNK3K18.6 UNK3TP_XTAL_OUT.1
S4_1AUX+: UNK4K9.4 UNK4R129.1
S4_1AUX-: UNK4K9.5 UNK4R130.1
S4_1SPI_CSN: UNK4K15.5 UNK4K19.6
S4_1SPI_SCK: UNK4K15.4 UNK4K19.3
S4_1SPI_SDI: UNK4K14.5 UNK4K20.6
S4_1SPI_SDO: UNK4K14.4 UNK4K20.3
S4_1TX_100DCH001+: UNK4K43.6 UNK4R7.1
S4_1TX_100DCH001-: UNK4K43.3 UNK4R8.2
S4_1TX_100DCH002+: SITE4.75(AML1P) UNK4R9.1
S4_1TX_100DCH002-: SITE4.76(AML1N) UNK4R10.2
S4_1TX_100DCH003+: SITE4.79(AML2P) UNK4R11.1
S4_1TX_100DCH003-: SITE4.80(AML2N) UNK4R12.2
S4_1TX_100DCH004+: SITE4.81(AMLCKP) UNK4R13.1
S4_1TX_100DCH004-: SITE4.82(AMLCKN) UNK4R14.2
S4_1TX_100DCH005+: SITE4.83(AML3P) UNK4R15.1
S4_1TX_100DCH005-: SITE4.84(AML3N) UNK4R16.2
S4_1TX_100DCH006+: SITE4.85(AML4P) UNK4R17.1
S4_1TX_100DCH006-: SITE4.86(AML4N) UNK4R18.2
S4_1TX_100DCH007+: SITE4.87(AML5P) UNK4R19.1
S4_1TX_100DCH007-: SITE4.88(AML5N) UNK4R20.2
S4_2AUX+: UNK4C3.1 UNK4R1.2 UNK4R3.1 UNK4R129.2
S4_2AUX-: UNK4C4.1 UNK4R2.2 UNK4R4.2 UNK4R130.2
S4_2TX_100DCH001+: SITE4.89(BML0P) UNK4R21.1
S4_2TX_100DCH001-: SITE4.90(BML0N) UNK4R22.2
S4_2TX_100DCH002+: SITE4.91(BML1P) UNK4R23.1
S4_2TX_100DCH002-: SITE4.92(BML1N) UNK4R24.2
S4_2TX_100DCH003+: SITE4.93(BML2P) UNK4R25.1
S4_2TX_100DCH003-: SITE4.94(BML2N) UNK4R26.2
S4_2TX_100DCH004+: SITE4.95(BMLCKP) UNK4R27.1
S4_2TX_100DCH004-: SITE4.96(BMLCKN) UNK4R28.2
S4_2TX_100DCH005+: SITE4.98(BML3P) UNK4R29.1
S4_2TX_100DCH005-: SITE4.99(BML3N) UNK4R30.2
S4_2TX_100DCH006+: SITE4.100(BML4P) UNK4R31.1
S4_2TX_100DCH006-: SITE4.101(BML4N) UNK4R32.2
S4_2TX_100DCH007+: SITE4.102(BML5P) UNK4R33.1
S4_2TX_100DCH007-: SITE4.103(BML5N) UNK4R34.2
S4_3TX_100DCH002+: SITE4.114(CML1P) UNK4R37.1
S4_3TX_100DCH002-: SITE4.115(CML1N) UNK4R38.2
S4_3TX_100DCH003+: SITE4.116(CML2P) UNK4R39.1
S4_3TX_100DCH003-: SITE4.117(CML2N) UNK4R40.2
S4_3TX_100DCH004+: SITE4.120(CMLCKP) UNK4R41.1
S4_3TX_100DCH004-: SITE4.121(CMLCKN) UNK4R42.2
S4_3TX_100DCH005+: SITE4.122(CML3P) UNK4R67.1
S4_3TX_100DCH005-: SITE4.123(CML3N) UNK4R68.2
S4_3TX_100DCH006+: SITE4.124(CML4P) UNK4R69.1
S4_3TX_100DCH006-: SITE4.125(CML4N) UNK4R70.2
S4_3TX_100DCH007+: SITE4.126(CML5P) UNK4R71.1
S4_3TX_100DCH007-: SITE4.127(CML5N) UNK4R72.2
S4_4TX_100DCH001+: SITE4.129(DML0P) UNK4R73.1
S4_4TX_100DCH001-: SITE4.130(DML0N) UNK4R74.2
S4_4TX_100DCH002+: SITE4.131(DML1P) UNK4R75.1
S4_4TX_100DCH002-: SITE4.132(DML1N) UNK4R76.2
S4_4TX_100DCH003+: SITE4.133(DML2P) UNK4R77.1
S4_4TX_100DCH003-: SITE4.134(DML2N) UNK4R78.2
S4_4TX_100DCH004+: SITE4.135(DMLCKP) UNK4R79.1
S4_4TX_100DCH004-: SITE4.136(DMLCKN) UNK4R80.2
S4_4TX_100DCH005+: SITE4.137(DML3P) UNK4R43.1
S4_4TX_100DCH005-: SITE4.138(DML3N) UNK4R44.2
S4_4TX_100DCH006+: SITE4.140(DML4P) UNK4R63.1
S4_4TX_100DCH006-: SITE4.141(DML4N) UNK4R64.2
S4_4TX_100DCH007+: SITE4.142(DML5P) UNK4R100.1
S4_4TX_100DCH007-: SITE4.143(DML5N) UNK4R101.2
S4_AUX_100DCH001+: UNK4K9.2
S4_AUX_100DCH001-: UNK4K9.7
S4_AUX_100DCH002+: UNK4C3.2
S4_AUX_100DCH002-: UNK4C4.2
S4_AUXCH+: SITE4.21(AUXCHP) UNK4K9.3 UNK4K12.3
S4_AUXCH-: SITE4.20(AUXCHN) UNK4K9.6 UNK4K12.6
S4_AVDD11_RX: SITE4.31(AVDD11_RX) UNK4CA9.1 UNK4CA10.1 UNK4CC13.1 UNK4CD9.1 UNK4K37.9 UNK4SH10.1 UNK4TP_AVDD11_RX.1
S4_AVDD11_XTAL: SITE4.105(AVDD11_XTAL) UNK4CA32.1 UNK4CA33.1 UNK4CC26.1 UNK4CD16.1 UNK4K31.4 UNK4SH23.1 UNK4TP_AVDD11_XTAL.1
S4_AVDD18_RX: SITE4.25(AVDD18_RX) UNK4CA7.1 UNK4CA8.1 UNK4CC11.1 UNK4CD8.1 UNK4K37.4 UNK4SH7.1 UNK4TP_AVDD18_RX.1
S4_DCH041: SITE4.159(STV2)
S4_DCH042: SITE4.160(STV1)
S4_DCH043: SITE4.161(POL)
S4_DCH044: SITE4.163(TP1)
S4_DCH045: SITE4.164(DC_EN)
S4_DCH046: SITE4.165(H2POL)
S4_DCH047: SITE4.166(SQINV)
S4_DCH048: UNK4K18.7
S4_DCH049: UNK4K18.2
S4_DPS_F_001: UNK4CA19.1 UNK4CA20.1 UNK4R1.1 UNK4R4.1 UNK4SH20.1 UNK4TP_AUXVCC.1
S4_DPS_F_002: SITE4.3(VDDA_33_LV) UNK4CA1.1 UNK4CA2.1 UNK4CC1.1 UNK4CC2.1 UNK4CD1.1 UNK4K34.4 UNK4SH1.1 UNK4TP_VDDA_33_LV.1
S4_DPS_F_003: SITE4.17(VDD_IO_33-1) SITE4.37(VDD_IO_33-2) SITE4.63(VDD_IO_33-3) SITE4.71(VDD_IO_33-4) SITE4.107(VDD_IO_33-5) SITE4.145(VDD_IO_33-6) SITE4.162(VDD_IO_33-7) UNK4CA3.1 UNK4CA4.1 UNK4CC4.1 UNK4CC30.1 UNK4CC31.1 UNK4CC32.1 UNK4CC33.1 UNK4CC34.1 UNK4CC35.1 UNK4CC42.1 UNK4CD3.1 UNK4CD17.1 UNK4CD18.1 UNK4CD19.1 UNK4CD20.1 UNK4CD21.1 UNK4CD22.1 UNK4K34.9 UNK4R85.1 UNK4SH3.1 UNK4TP_VDD_IO_33.1
S4_DPS_F_006: SITE4.72(VDD_TXREG_33_B) UNK4CA17.1 UNK4CA18.1 UNK4CC25.1 UNK4CC40.1 UNK4CD15.1 UNK4K42.4 UNK4SH18.1 UNK4TP_VDD_TXREG_33_B.1
S4_DPS_F_007: SITE4.78(VDDTXPST_11_B-1) SITE4.97(VDDTXPST_11_B-2) UNK4CA11.1 UNK4CA12.1 UNK4CC15.1 UNK4CC16.1 UNK4CC27.1 UNK4CC28.1 UNK4CD10.1 UNK4CD11.1 UNK4K39.4 UNK4SH12.1 UNK4TP_VDDTXPST_11_B.1
S4_DPS_F_009: SITE4.106(PLL_M_VDD33) UNK4CA13.1 UNK4CA14.1 UNK4CC19.1 UNK4CC20.1 UNK4CD13.1 UNK4K40.4 UNK4SH14.1 UNK4TP_PLL_M_VDD33.1
S4_DPS_F_010: SITE4.111(PLL_TX_VDD33) UNK4CA15.1 UNK4CA16.1 UNK4CC22.1 UNK4CC23.1 UNK4CD14.1 UNK4K40.9 UNK4SH16.1 UNK4TP_PLL_TX_VDD33.1
S4_DPS_F_011: SITE4.119(VDDTXPST_11_T-1) SITE4.139(VDDTXPST_11_T-2) UNK4CA35.1 UNK4CA36.1 UNK4CC17.1 UNK4CC29.1 UNK4CC37.1 UNK4CC38.1 UNK4CD12.1 UNK4CD24.1 UNK4K39.9 UNK4SH25.1 UNK4TP_VDDTXPST_11_T.1
S4_DPS_F_012: SITE4.144(VDD_TXREG_33_T) UNK4CA38.1 UNK4CA39.1 UNK4CC39.1 UNK4CC41.1 UNK4CD25.1 UNK4K42.9 UNK4SH27.1 UNK4TP_VDD_TXREG_33_T.1
S4_DPS_F_013: UNK4C8.1 UNK4C9.1 UNK4CA30.1 UNK4CA31.1 UNK4R82.2 UNK4R83.1 UNK4R84.1 UNK4R87.2 UNK4R88.2 UNK4R89.2 UNK4R90.2 UNK4R91.2 UNK4R92.2 UNK4R94.2 UNK4R95.2 UNK4R96.2 UNK4R97.2 UNK4R98.2 UNK4R99.2 UNK4R119.1 UNK4R120.1 UNK4SH22.1 UNK4TP_VCC3V3.1 UNK4U1.8 UNK4U2.8
S4_DPS_FS_001: UNK4SH20.2
S4_DPS_FS_002: UNK4SH1.2
S4_DPS_FS_003: UNK4SH3.2
S4_DPS_FS_004: UNK4SH7.2
S4_DPS_FS_005: UNK4SH10.2
S4_DPS_FS_006: UNK4SH18.2
S4_DPS_FS_007: UNK4SH12.2
S4_DPS_FS_008: UNK4SH23.2
S4_DPS_FS_009: UNK4SH14.2
S4_DPS_FS_010: UNK4SH16.2
S4_DPS_FS_011: UNK4SH25.2
S4_DPS_FS_012: UNK4SH27.2
S4_DPS_FS_013: UNK4SH22.2
S4_DPS_GS_001: UNK4SH19.2
S4_DPS_GS_002: UNK4SH2.2
S4_DPS_GS_003: UNK4SH4.2
S4_DPS_GS_004: UNK4SH8.2
S4_DPS_GS_005: UNK4SH9.2
S4_DPS_GS_006: UNK4SH17.2
S4_DPS_GS_007: UNK4SH11.2
S4_DPS_GS_008: UNK4SH24.2
S4_DPS_GS_009: UNK4SH13.2
S4_DPS_GS_010: UNK4SH15.2
S4_DPS_GS_011: UNK4SH26.2
S4_DPS_GS_012: UNK4SH28.2
S4_DPS_GS_013: UNK4SH21.2
S4_ISP00+: SITE4.73(AML0P) UNK4K43.7
S4_ISP00-: SITE4.74(AML0N) UNK4K43.2
S4_ISP14+: SITE4.112(CML0P) UNK4K43.5
S4_ISP14-: SITE4.113(CML0N) UNK4K43.4
S4_ISP_1LOCK: UNK4K33.3 UNK4R118.2
S4_M_DPS_F_001: SITE4.22(VDDC_11-1) SITE4.39(VDDC_11-2) SITE4.64(VDDC_11-3) SITE4.104(VDDC_11-4) SITE4.147(VDDC_11-5) UNK4CA5.1 UNK4CA6.1 UNK4CC6.1 UNK4CC7.1 UNK4CC8.1 UNK4CC9.1 UNK4CC36.1 UNK4CD4.1 UNK4CD5.1 UNK4CD6.1 UNK4CD7.1 UNK4CD23.1 UNK4K36.4 UNK4K36.9 UNK4SH5.1 UNK4TP_VDDC_11.1
S4_M_DPS_FS_001: UNK4SH5.2
S4_M_DPS_GS_001: UNK4SH6.2
S4_PS9G_DCH001: SITE4.18(TEST)
S4_PS9G_DCH002: S4_RST_N.1 SITE4.19(RESET_N) UNK4K10.3
S4_PS9G_DCH003: SITE4.24(HPD)
S4_PS9G_DCH004: SITE4.40(AGEN)
S4_PS9G_DCH005: SITE4.45(STV_IN)
S4_PS9G_DCH006: SITE4.46(EIO1)
S4_PS9G_DCH007: SITE4.47(EIO2)
S4_PS9G_DCH009: SITE4.49(PWMI)
S4_PS9G_DCH010: S4_I2C.1 SITE4.50(I2C_SCL) UNK4J4.2 UNK4K28.3
S4_PS9G_DCH011: S4_I2C.2 SITE4.51(I2C_SDA) UNK4J5.2 UNK4K28.6
S4_PS9G_DCH014: SITE4.54(LED_SPI_SIN_A)
S4_PS9G_DCH015: SITE4.55(LED_SPI_SCLK_A)
S4_PS9G_DCH022: SITE4.65(LED_SPI_SO_A)
S4_PS9G_DCH023: SITE4.66(LED_SPI_SO_B)
S4_PS9G_DCH027: SITE4.70(OSD_SPI_SDO)
S4_PS9G_DCH028: SITE4.77(NC_VDDTX_11_B)
S4_PS9G_DCH029: SITE4.118(NC_VDDTX_11_T)
S4_PS9G_DCH030: SITE4.148(ISP_LOCK) UNK4R118.1
S4_PS9G_DCH035: SITE4.153(CLK6)
S4_PS9G_DCH036: SITE4.154(CLK5)
S4_PS9G_DCH037: SITE4.155(CLK4)
S4_PS9G_DCH038: SITE4.156(CLK3)
S4_PS9G_DCH039: SITE4.157(CLK2)
S4_PS9G_DCH040: SITE4.158(CLK1)
S4_RLY_001: UNK4K1.8 UNK4K2.8
S4_RLY_003: UNK4K3.8 UNK4K4.8
S4_RLY_005: UNK4K5.8 UNK4K6.8
S4_RLY_007: UNK4K7.8
S4_RLY_008: UNK4K8.8 UNK4K11.8
S4_RLY_009: UNK4K9.8
S4_RLY_010: UNK4K10.8
S4_RLY_012: UNK4K12.8
S4_RLY_013: UNK4K13.8
S4_RLY_014: UNK4K14.8
S4_RLY_015: UNK4K15.8
S4_RLY_016: UNK4K16.8 UNK4K17.8
S4_RLY_018: UNK4K18.8
S4_RLY_019: UNK4K19.8
S4_RLY_020: UNK4K20.8
S4_RLY_021: UNK4K21.8 UNK4K29.8
S4_RLY_022: UNK4K22.8 UNK4K24.8
S4_RLY_023: UNK4K23.8
S4_RLY_025: UNK4K25.8 UNK4K27.8
S4_RLY_026: UNK4K26.8
S4_RLY_028: UNK4K28.8
S4_RLY_030: UNK4K30.8
S4_RLY_031: UNK4K31.12
S4_RLY_033: UNK4K33.8
S4_RLY_034: UNK4K34.12
S4_RLY_036: UNK4K36.12
S4_RLY_037: UNK4K37.12
S4_RLY_039: UNK4K39.12
S4_RLY_040: UNK4K40.12
S4_RLY_042: UNK4K42.12
S4_RLY_043: UNK4K43.8
S4_SCAN_DCH008: SITE4.48(FAIL_FLAG_O)
S4_SCAN_DCH012: SITE4.52(LED_SPI_BLANK_A)
S4_SCAN_DCH013: SITE4.53(LED_SPI_GSCLK_A)
S4_SCAN_DCH016: SITE4.56(LED_SPI_XLAT_A)
S4_SCAN_DCH017: SITE4.57(LED_SPI_BLANK_B)
S4_SCAN_DCH018: SITE4.58(LED_SPI_GSCLK_B)
S4_SCAN_DCH019: SITE4.59(LED_SPI_SIN_B)
S4_SCAN_DCH020: SITE4.60(LED_SPI_SCLK_B)
S4_SCAN_DCH021: SITE4.61(LED_SPI_XLAT_B)
S4_SCAN_DCH024: SITE4.67(OSD_SPI_SCK_I2CCLK) UNK4K13.3
S4_SCAN_DCH025: SITE4.68(OSD_SPI_SDI_I2CDAT) UNK4K13.6
S4_SCAN_DCH026: SITE4.69(OSD_SPI_CSN)
S4_SCAN_DCH031: SITE4.149(OE2)
S4_SCAN_DCH032: SITE4.150(OE1)
S4_SCAN_DCH033: SITE4.151(CLK8)
S4_SCAN_DCH034: SITE4.152(CLK7)
S4_SCAN_DCH050: UNK4K15.2
S4_SCAN_DCH051: UNK4K15.7
S4_SCAN_DCH052: UNK4K14.2
S4_SCAN_DCH053: UNK4K14.7
S4_SPI_1_CSN: UNK4K19.7 UNK4R87.1 UNK4U1.1
S4_SPI_1_SCK: UNK4K19.2 UNK4R91.1 UNK4U1.6
S4_SPI_1_SDI: UNK4K20.7 UNK4R127.1
S4_SPI_1_SDO: UNK4K20.2 UNK4R125.1
S4_SPI_2_CSN: UNK4K19.5 UNK4R94.1 UNK4U2.1
S4_SPI_2_SCK: UNK4K19.4 UNK4R98.1 UNK4U2.6
S4_SPI_2_SDI: UNK4K20.5 UNK4R128.1
S4_SPI_2_SDO: UNK4K20.4 UNK4R126.1
S4_SPI_11_SDI: UNK4R88.1 UNK4R127.2 UNK4U1.2
S4_SPI_11_SDO: UNK4R92.1 UNK4R125.2 UNK4U1.5
S4_SPI_22_SDI: UNK4R95.1 UNK4R128.2 UNK4U2.2
S4_SPI_22_SDO: UNK4R99.1 UNK4R126.2 UNK4U2.5
S4_SPI_CSN: SITE4.43(SPI_CSN) UNK4K15.6
S4_SPI_SCK: SITE4.42(SPI_SCK) UNK4K15.3
S4_SPI_SDI: SITE4.44(SPI_SDI) UNK4K14.6
S4_SPI_SDO: SITE4.41(SPI_SDO) UNK4K14.3
S4_XTAL_IN: SITE4.109(XTAL_IN) UNK4K18.3 UNK4TP_XTAL_IN.1
S4_XTAL_OUT: SITE4.110(XTAL_OUT) UNK4K18.6 UNK4TP_XTAL_OUT.1
UDBGND: BD29.2 BD30.2 BD31.2 BD32.2 BD33.2 BD34.2 BD35.2 BD36.2 BD37.2 BD38.2 BD39.2 BD40.2 BD41.2 BD42.2 BD43.2 BD44.2 CB1.2 CB2.2 CB3.2 CB4.2 CB5.2 CB6.2 CB7.2 CB8.2 CB9.2 CB10.2 CB11.2 CB12.2 CB13.2 CB14.2 CB15.2 CB16.2 CB19.1 LD902.2(B) UB1.1(NC) UB1.2(A1/NC) UB1.3(A2) UB1.4(GND) UB1.7(WP) UTL1.A02 UTL1.A08 UTL1.A10 UTL1.A12 UTL1.A14 UTL1.B01 UTL1.B07 UTL1.B09 UTL1.B11 UTL1.B13 UTL2.A02 UTL2.A08 UTL2.A10 UTL2.A12 UTL2.A14 UTL2.B01 UTL2.B07 UTL2.B09 UTL2.B11 UTL2.B13 UTL3.A02 UTL3.A08 UTL3.A10 UTL3.A12 UTL3.A14 UTL3.B01 UTL3.B07 UTL3.B09 UTL3.B11 UTL3.B13 UTL4.A02 UTL4.A08 UTL4.A10 UTL4.A12 UTL4.A14 UTL4.B01 UTL4.B07 UTL4.B09 UTL4.B11 UTL4.B13 UTL5.A02 UTL5.A08 UTL5.A10 UTL5.A12 UTL5.A14 UTL5.B01 UTL5.B07 UTL5.B09 UTL5.B11 UTL5.B13 UTL6.A02 UTL6.A08 UTL6.A10 UTL6.A12 UTL6.A14 UTL6.B01 UTL6.B07 UTL6.B09 UTL6.B11 UTL6.B13 UTL7.A02 UTL7.A08 UTL7.A10 UTL7.A12 UTL7.A14 UTL7.B01 UTL7.B07 UTL7.B09 UTL7.B11 UTL7.B13 UTL8.A02 UTL8.A08 UTL8.A10 UTL8.A12 UTL8.A14 UTL8.B01 UTL8.B07 UTL8.B09 UTL8.B11 UTL8.B13
UT1_PDCF: UTL1.B15
UT1_PDCS: UTL1.A15
UT1_PGDS: UTL1.A16
UT1_PGRD: UTL1.B16
UT1_UP5V: BR902.1 CB1.1 CB2.1 CB3.1 CB4.1 CB5.1 CB6.1 CB7.1 CB8.1 CB9.1 CB10.1 CB11.1 CB12.1 CB13.1 CB14.1 CB15.1 CB16.1 CB19.2 K1.1(V+) K2.1(V+) K3.1(V+) K4.1(V+) K5.1(V+) K6.1(V+) K7.1(V+) K8.1(V+) K9.1(V+) K10.1(V+) K11.1(V+) K12.1(V+) K13.1(V+) K14.1(V+) K15.1(V+) K16.1(V+) K17.1(V+) K18.1(V+) K19.1(V+) K20.1(V+) K21.1(V+) K22.1(V+) K23.1(V+) K24.1(V+) K25.1(V+) K26.1(V+) K27.1(V+) K28.1(V+) K29.1(V+) K30.1(V+) K31.1(V+) K33.1(V+) K34.1(V+) K36.1(V+) K37.1(V+) K39.1(V+) K40.1(V+) K42.1(V+) K43.1(V+) RB1.1 RB2.1 UB1.8(VCC) UNK2K1.1 UNK2K2.1 UNK2K3.1 UNK2K4.1 UNK2K5.1 UNK2K6.1 UNK2K7.1 UNK2K8.1 UNK2K9.1 UNK2K10.1 UNK2K11.1 UNK2K12.1 UNK2K13.1 UNK2K14.1 UNK2K15.1 UNK2K16.1 UNK2K17.1 UNK2K18.1 UNK2K19.1 UNK2K20.1 UNK2K21.1 UNK2K22.1 UNK2K23.1 UNK2K24.1 UNK2K25.1 UNK2K26.1 UNK2K27.1 UNK2K28.1 UNK2K29.1 UNK2K30.1 UNK2K31.1 UNK2K33.1 UNK2K34.1 UNK2K36.1 UNK2K37.1 UNK2K39.1 UNK2K40.1 UNK2K42.1 UNK2K43.1 UNK3K1.1 UNK3K2.1 UNK3K3.1 UNK3K4.1 UNK3K5.1 UNK3K6.1 UNK3K7.1 UNK3K8.1 UNK3K9.1 UNK3K10.1 UNK3K11.1 UNK3K12.1 UNK3K13.1 UNK3K14.1 UNK3K15.1 UNK3K16.1 UNK3K17.1 UNK3K18.1 UNK3K19.1 UNK3K20.1 UNK3K21.1 UNK3K22.1 UNK3K23.1 UNK3K24.1 UNK3K25.1 UNK3K26.1 UNK3K27.1 UNK3K28.1 UNK3K29.1 UNK3K30.1 UNK3K31.1 UNK3K33.1 UNK3K34.1 UNK3K36.1 UNK3K37.1 UNK3K39.1 UNK3K40.1 UNK3K42.1 UNK3K43.1 UNK4K1.1 UNK4K2.1 UNK4K3.1 UNK4K4.1 UNK4K5.1 UNK4K6.1 UNK4K7.1 UNK4K8.1 UNK4K9.1 UNK4K10.1 UNK4K11.1 UNK4K12.1 UNK4K13.1 UNK4K14.1 UNK4K15.1 UNK4K16.1 UNK4K17.1 UNK4K18.1 UNK4K19.1 UNK4K20.1 UNK4K21.1 UNK4K22.1 UNK4K23.1 UNK4K24.1 UNK4K25.1 UNK4K26.1 UNK4K27.1 UNK4K28.1 UNK4K29.1 UNK4K30.1 UNK4K31.1 UNK4K33.1 UNK4K34.1 UNK4K36.1 UNK4K37.1 UNK4K39.1 UNK4K40.1 UNK4K42.1 UNK4K43.1 UT_UP5V.1(TP) UTL1.A05 UTL1.B04 UTL2.A05 UTL2.B04 UTL3.A05 UTL3.B04 UTL4.A05 UTL4.B04 UTL5.A05 UTL5.B04 UTL6.A05 UTL6.B04 UTL7.A05 UTL7.B04 UTL8.A05 UTL8.B04
UT1_URW00: UTL1.A01
UT1_URW01: UTL1.B02
UT1_URW02: UTL1.A03
UT1_URW03: UTL1.B03
UT1_URW04: UTL1.A04
UT1_URW05: UTL1.B05
UT1_URW06: UTL1.A06
UT1_UW07: UTL1.B06
UT1_UW08: UTL1.A07
UT1_UW09: UTL1.B08
UT1_UW10: UTL1.A09
UT1_UW11: UTL1.B10
UT1_UW12: UTL1.A11
UT1_UW13: UTL1.B12
UT1_UW14: RB1.2 UB1.6(SCL) UTL1.A13
UT1_UW15: RB2.2 UB1.5(SDA) UTL1.B14
UT2_PDCF: UTL2.B15
UT2_PDCS: UTL2.A15
UT2_PGDS: UTL2.A16
UT2_PGRD: UTL2.B16
UT2_URW00: UTL2.A01
UT2_URW01: UTL2.B02
UT2_URW02: UTL2.A03
UT2_URW03: UTL2.B03
UT2_URW04: UTL2.A04
UT2_URW05: UTL2.B05
UT2_URW06: UTL2.A06
UT2_UW07: UTL2.B06
UT2_UW08: UTL2.A07
UT2_UW09: UTL2.B08
UT2_UW10: UTL2.A09
UT2_UW11: UTL2.B10
UT2_UW12: UTL2.A11
UT2_UW13: UTL2.B12
UT2_UW14: UTL2.A13
UT2_UW15: UTL2.B14
UT3_PDCF: UTL3.B15
UT3_PDCS: UTL3.A15
UT3_PGDS: UTL3.A16
UT3_PGRD: UTL3.B16
UT3_URW00: UTL3.A01
UT3_URW01: UTL3.B02
UT3_URW02: UTL3.A03
UT3_URW03: UTL3.B03
UT3_URW04: UTL3.A04
UT3_URW05: UTL3.B05
UT3_URW06: UTL3.A06
UT3_UW07: UTL3.B06
UT3_UW08: UTL3.A07
UT3_UW09: UTL3.B08
UT3_UW10: UTL3.A09
UT3_UW11: UTL3.B10
UT3_UW12: UTL3.A11
UT3_UW13: UTL3.B12
UT3_UW14: UTL3.A13
UT3_UW15: UTL3.B14
UT4_PDCF: UTL4.B15
UT4_PDCS: UTL4.A15
UT4_PGDS: UTL4.A16
UT4_PGRD: UTL4.B16
UT4_URW00: UTL4.A01
UT4_URW01: UTL4.B02
UT4_URW02: UTL4.A03
UT4_URW03: UTL4.B03
UT4_URW04: UTL4.A04
UT4_URW05: UTL4.B05
UT4_URW06: UTL4.A06
UT4_UW07: UTL4.B06
UT4_UW08: UTL4.A07
UT4_UW09: UTL4.B08
UT4_UW10: UTL4.A09
UT4_UW11: UTL4.B10
UT4_UW12: UTL4.A11
UT4_UW13: UTL4.B12
UT4_UW14: UTL4.A13
UT4_UW15: UTL4.B14
UT5_PDCF: UTL5.B15
UT5_PDCS: UTL5.A15
UT5_PGDS: UTL5.A16
UT5_PGRD: UTL5.B16
UT5_UW00: UTL5.A01
UT5_UW01: UTL5.B02
UT5_UW02: UTL5.A03
UT5_UW03: UTL5.B03
UT5_UW04: UTL5.A04
UT5_UW05: UTL5.B05
UT5_UW06: UTL5.A06
UT5_UW07: UTL5.B06
UT5_UW08: UTL5.A07
UT5_UW09: UTL5.B08
UT5_UW10: UTL5.A09
UT5_UW11: UTL5.B10
UT5_UW12: UTL5.A11
UT5_UW13: UTL5.B12
UT5_UW14: UTL5.A13
UT5_UW15: UTL5.B14
UT6_PDCF: UTL6.B15
UT6_PDCS: UTL6.A15
UT6_PGDS: UTL6.A16
UT6_PGRD: UTL6.B16
UT6_UW00: UTL6.A01
UT6_UW01: UTL6.B02
UT6_UW02: UTL6.A03
UT6_UW03: UTL6.B03
UT6_UW04: UTL6.A04
UT6_UW05: UTL6.B05
UT6_UW06: UTL6.A06
UT6_UW07: UTL6.B06
UT6_UW08: UTL6.A07
UT6_UW09: UTL6.B08
UT6_UW10: UTL6.A09
UT6_UW11: UTL6.B10
UT6_UW12: UTL6.A11
UT6_UW13: UTL6.B12
UT6_UW14: UTL6.A13
UT6_UW15: UTL6.B14
UT7_PDCF: UTL7.B15
UT7_PDCS: UTL7.A15
UT7_PGDS: UTL7.A16
UT7_PGRD: UTL7.B16
UT7_UW00: UTL7.A01
UT7_UW01: UTL7.B02
UT7_UW02: UTL7.A03
UT7_UW03: UTL7.B03
UT7_UW04: UTL7.A04
UT7_UW05: UTL7.B05
UT7_UW06: UTL7.A06
UT7_UW07: UTL7.B06
UT7_UW08: UTL7.A07
UT7_UW09: UTL7.B08
UT7_UW10: UTL7.A09
UT7_UW11: UTL7.B10
UT7_UW12: UTL7.A11
UT7_UW13: UTL7.B12
UT7_UW14: UTL7.A13
UT7_UW15: UTL7.B14
UT8_PDCF: UTL8.B15
UT8_PDCS: UTL8.A15
UT8_PGDS: UTL8.A16
UT8_PGRD: UTL8.B16
UT8_UW00: UTL8.A01
UT8_UW01: UTL8.B02
UT8_UW02: UTL8.A03
UT8_UW03: UTL8.B03
UT8_UW04: UTL8.A04
UT8_UW05: UTL8.B05
UT8_UW06: UTL8.A06
UT8_UW07: UTL8.B06
UT8_UW08: UTL8.A07
UT8_UW09: UTL8.B08
UT8_UW10: UTL8.A09
UT8_UW11: UTL8.B10
UT8_UW12: UTL8.A11
UT8_UW13: UTL8.B12
UT8_UW14: UTL8.A13
UT8_UW15: UTL8.B14
N16868442: BR902.2 LD902.1(A)
N24574244: J2.1 R89.1
N24574268: J3.1 R96.1
N24574272: J3.3 R93.1
N24574311: R90.1 U1.7(HOLD#)
N24574358: J2.2 U1.3(WP#)
N24574376: R97.1 U2.7(HOLD#)
N24574426: J3.2 U2.3(WP#)
N24574578: J2.3 R86.1
N24787993: CA21.1 K34.5
N24789529: CA23.1 K36.5 K36.8
N24789779: CA24.1 K37.5
N25330426: CA29.1 K42.5
N25334489: CA26.1 K39.5
N25337760: CA34.1 K31.5
N25339188: CA27.1 K40.5
N25462044: CA37.1 K39.8
N25462912: CA40.1 K42.8
N25463486: CA28.1 K40.8
N25464528: CA25.1 K37.8
N25465136: CA22.1 K34.8
N26125600: K25.3 R55.2
N26125602: K25.4 R56.1
N26125604: K25.6 R57.2
N26125606: K25.5 R58.1
N26125622: K26.3 R59.2
N26125624: K26.4 R60.1
N26125626: K26.6 R61.2
N26125628: K26.5 R62.1
N26125644: K27.5 R66.1
N26125646: K27.6 R65.2
N26125685: K22.6 R45.2
N26125687: K22.5 R46.1
N26125689: K23.3 R47.2
N26125691: K23.4 R48.1
N26125693: K23.6 R49.2
N26125695: K23.5 R50.1
N26125711: K24.3 R51.2
N26125713: K24.4 R52.1
N26125715: K24.6 R53.2
N26125717: K24.5 R54.1
N26125746: K22.3 R102.2
N26125748: K22.4 R103.1
N26125750: K27.3 R104.2
N26125752: K27.4 R105.1
N26138300: J1.2 K10.4 R85.2 S1_RST_N.2
N26138322: C7.1 J1.1
N26323523: K17.3 R71.2
N26323525: K17.4 R72.1
N26323527: K17.5 R74.1
N26323529: K17.6 R73.2
N26323531: K21.3 R75.2
N26323533: K21.4 R76.1
N26323535: K21.5 R78.1
N26323537: K21.6 R77.2
N26323539: K29.3 R79.2
N26323541: K29.4 R80.1
N26323543: K29.6 R43.2
N26323545: K29.5 R44.1
N26323547: K30.3 R63.2
N26323549: K30.4 R64.1
N26323551: K30.5 R101.1
N26323553: K30.6 R100.2
N26325241: K16.3 R67.2
N26325243: K16.4 R68.1
N26325245: K16.5 R70.1
N26325247: K16.6 R69.2
N26326910: K6.5 R30.1
N26326941: K6.3 R27.2
N26326943: K6.4 R28.1
N26326945: K6.6 R29.2
N26326947: K7.5 R34.1
N26326959: K7.3 R31.2
N26326961: K7.4 R32.1
N26326963: K7.6 R33.2
N26327095: K11.3 R39.2
N26327097: K11.4 R40.1
N26327099: K8.5 R38.1
N26327103: K8.6 R37.2
N26327105: K11.6 R41.2
N26327107: K11.5 R42.1
N26328546: K5.5 R26.1
N26328550: K5.3 R23.2
N26328552: K5.4 R24.1
N26328554: K5.6 R25.2
N26330264: K3.5 R18.1
N26330266: K3.6 R17.2
N26330268: K3.4 R16.1
N26330270: K3.3 R15.2
N26330276: K1.5 R10.1
N26330278: K1.6 R9.2
N26330280: K1.4 R8.1
N26330282: K1.3 R7.2
N26330286: K2.3 R11.2
N26330288: K2.4 R12.1
N26330290: K4.5 R22.1
N26330294: K4.3 R19.2
N26330296: K4.4 R20.1
N26330298: K4.6 R21.2
N26330300: K2.5 R14.1
N26330302: K2.6 R13.2
N26336800: K12.4 R131.1
N26336804: K12.5 R132.1
N26336814: K33.2 R82.1
N26336816: K33.4 R117.1
N26336828: K18.4 R5.1 R6.2
N26336832: K18.5 R6.1 R133.1
N26336834: C5.1 R133.2 Y1.1 Y2.1
N26336836: C6.1 R5.2 Y1.3 Y2.3
N26336892: K13.5 R120.2
N26336894: K13.4 R119.2
N26337539: J5.1 K28.5 R84.2
N26337547: J4.1 K28.4 R83.2
N26486525: UNK2K25.3 UNK2R55.2
N26486526: UNK2K25.4 UNK2R56.1
N26486527: UNK2K25.6 UNK2R57.2
N26486528: UNK2K25.5 UNK2R58.1
N26486530: UNK2K26.3 UNK2R59.2
N26486531: UNK2K26.4 UNK2R60.1
N26486532: UNK2K26.6 UNK2R61.2
N26486533: UNK2K26.5 UNK2R62.1
N26486535: UNK2K27.5 UNK2R66.1
N26486536: UNK2K27.6 UNK2R65.2
N26486543: UNK2K22.6 UNK2R45.2
N26486544: UNK2K22.5 UNK2R46.1
N26486545: UNK2K23.3 UNK2R47.2
N26486546: UNK2K23.4 UNK2R48.1
N26486547: UNK2K23.6 UNK2R49.2
N26486548: UNK2K23.5 UNK2R50.1
N26486550: UNK2K24.3 UNK2R51.2
N26486551: UNK2K24.4 UNK2R52.1
N26486552: UNK2K24.6 UNK2R53.2
N26486553: UNK2K24.5 UNK2R54.1
N26486568: UNK2K22.3 UNK2R102.2
N26486569: UNK2K22.4 UNK2R103.1
N26486570: UNK2K27.3 UNK2R104.2
N26486571: UNK2K27.4 UNK2R105.1
N26486686: S2_RST_N.2 UNK2J1.2 UNK2K10.4 UNK2R85.2
N26486691: UNK2C7.1 UNK2J1.1
N26486726: UNK2K17.3 UNK2R71.2
N26486727: UNK2K17.4 UNK2R72.1
N26486728: UNK2K17.5 UNK2R74.1
N26486729: UNK2K17.6 UNK2R73.2
N26486730: UNK2K21.3 UNK2R75.2
N26486731: UNK2K21.4 UNK2R76.1
N26486732: UNK2K21.5 UNK2R78.1
N26486733: UNK2K21.6 UNK2R77.2
N26486734: UNK2K29.3 UNK2R79.2
N26486735: UNK2K29.4 UNK2R80.1
N26486736: UNK2K29.6 UNK2R43.2
N26486737: UNK2K29.5 UNK2R44.1
N26486738: UNK2K30.3 UNK2R63.2
N26486739: UNK2K30.4 UNK2R64.1
N26486740: UNK2K30.5 UNK2R101.1
N26486741: UNK2K30.6 UNK2R100.2
N26486822: UNK2K16.3 UNK2R67.2
N26486823: UNK2K16.4 UNK2R68.1
N26486824: UNK2K16.5 UNK2R70.1
N26486825: UNK2K16.6 UNK2R69.2
N26486847: UNK2K6.5 UNK2R30.1
N26486849: UNK2K6.3 UNK2R27.2
N26486850: UNK2K6.4 UNK2R28.1
N26486851: UNK2K6.6 UNK2R29.2
N26486852: UNK2K7.5 UNK2R34.1
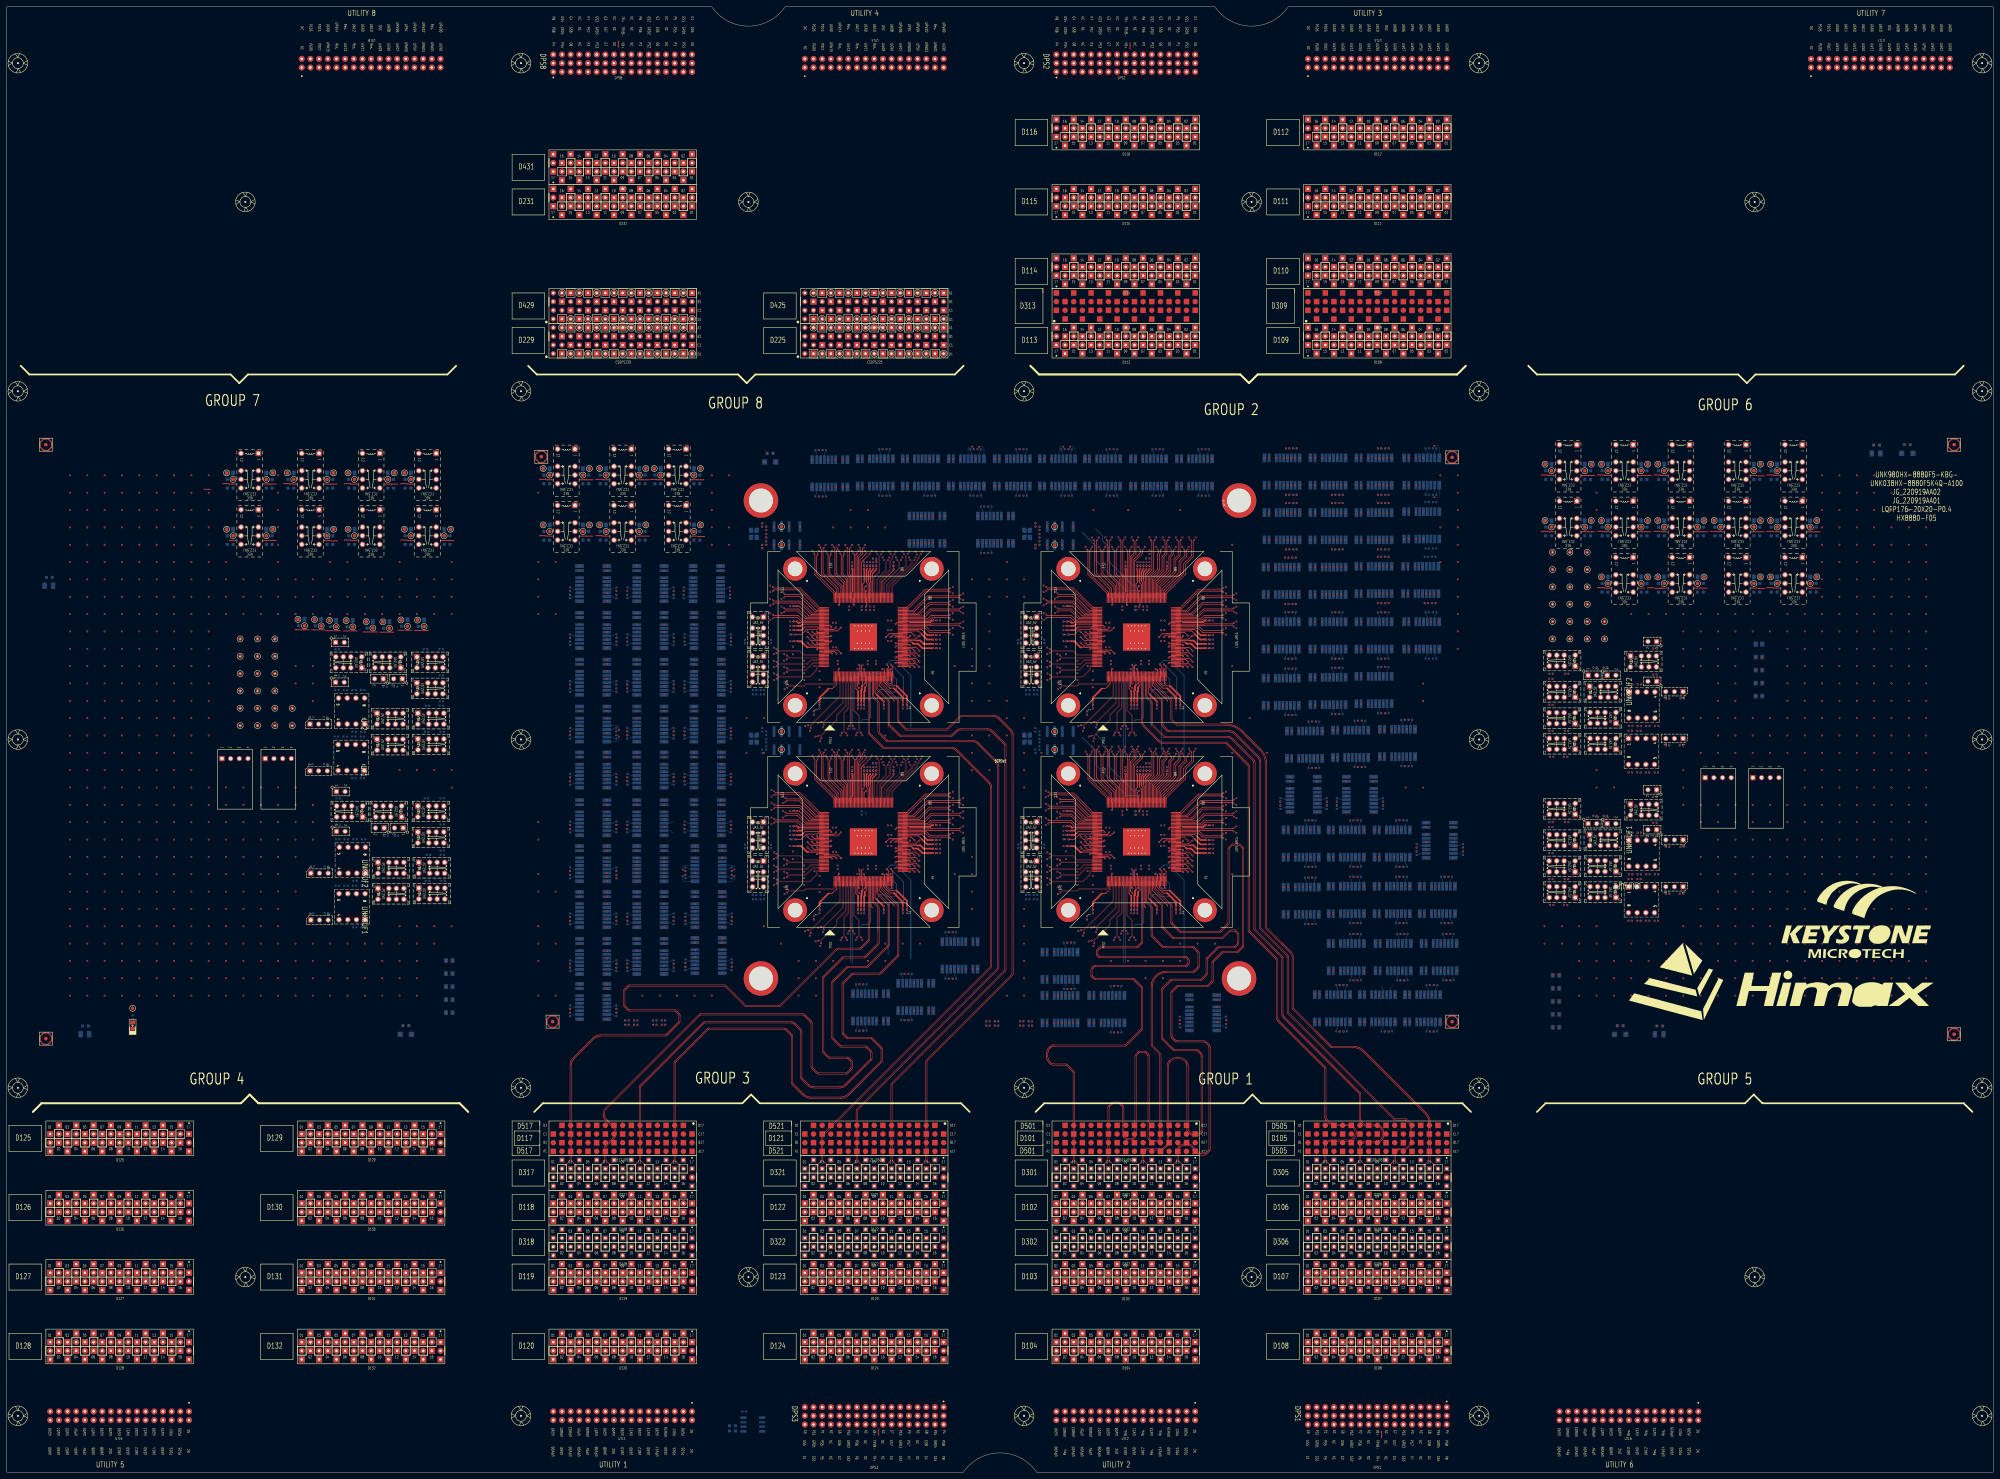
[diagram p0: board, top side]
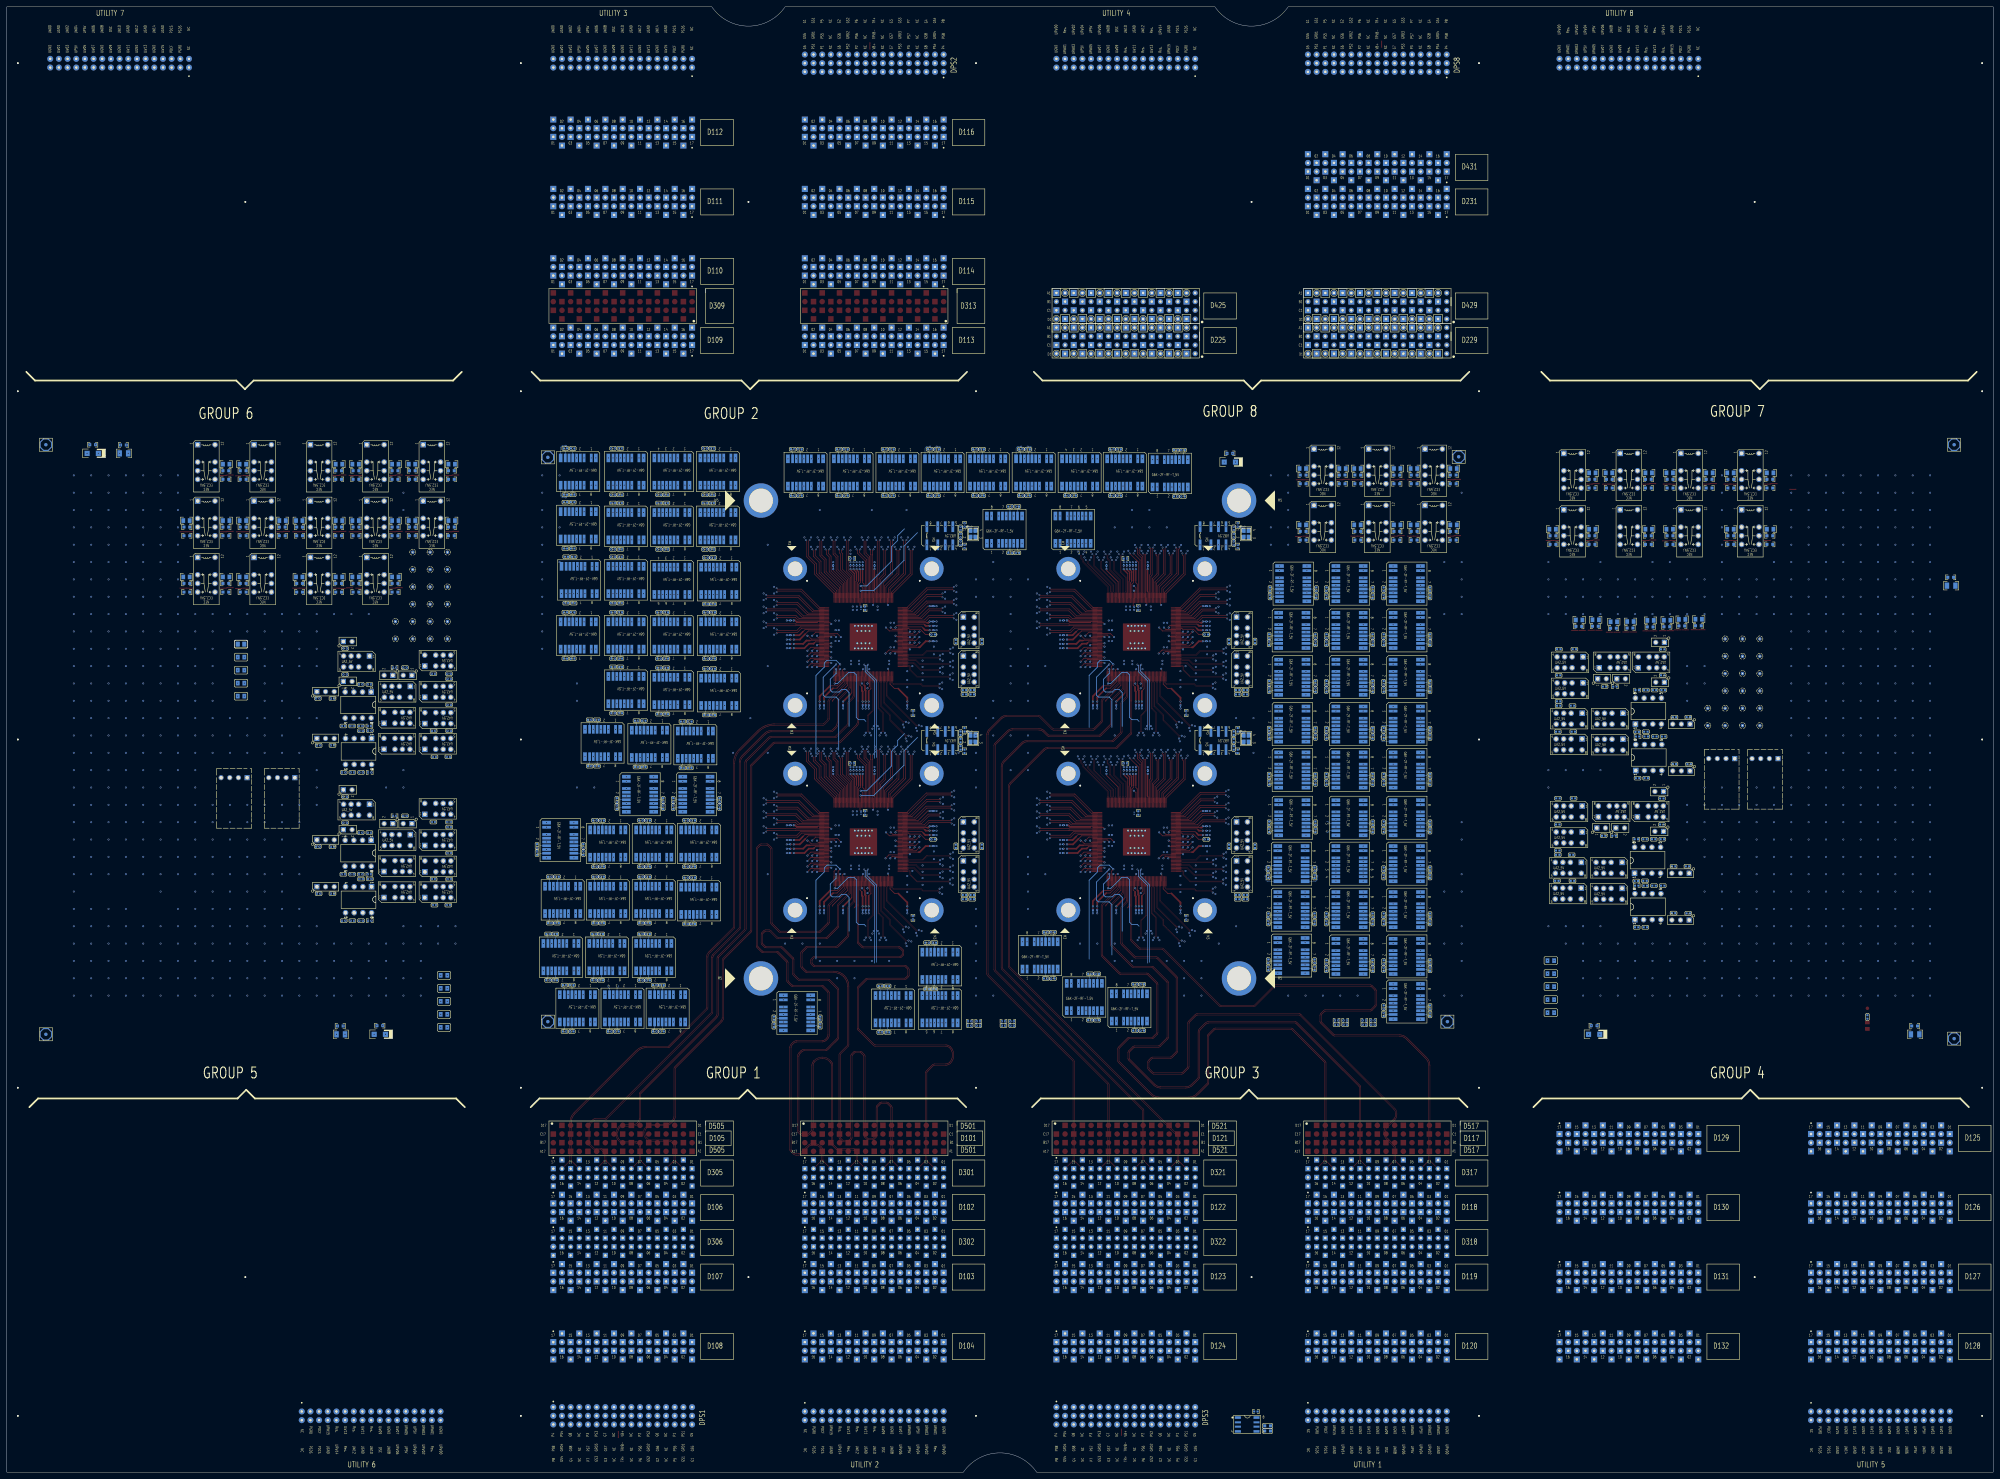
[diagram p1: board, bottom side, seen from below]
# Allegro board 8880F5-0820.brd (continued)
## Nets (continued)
N26486854: UNK2K7.3 UNK2R31.2
N26486855: UNK2K7.4 UNK2R32.1
N26486856: UNK2K7.6 UNK2R33.2
N26486898: UNK2K11.3 UNK2R39.2
N26486899: UNK2K11.4 UNK2R40.1
N26486900: UNK2K8.5 UNK2R38.1
N26486902: UNK2K8.6 UNK2R37.2
N26486903: UNK2K11.6 UNK2R41.2
N26486904: UNK2K11.5 UNK2R42.1
N26486946: UNK2K5.5 UNK2R26.1
N26486948: UNK2K5.3 UNK2R23.2
N26486949: UNK2K5.4 UNK2R24.1
N26486950: UNK2K5.6 UNK2R25.2
N26486971: UNK2K3.5 UNK2R18.1
N26486972: UNK2K3.6 UNK2R17.2
N26486973: UNK2K3.4 UNK2R16.1
N26486974: UNK2K3.3 UNK2R15.2
N26486977: UNK2K1.5 UNK2R10.1
N26486978: UNK2K1.6 UNK2R9.2
N26486979: UNK2K1.4 UNK2R8.1
N26486980: UNK2K1.3 UNK2R7.2
N26486982: UNK2K2.3 UNK2R11.2
N26486983: UNK2K2.4 UNK2R12.1
N26486984: UNK2K4.5 UNK2R22.1
N26486986: UNK2K4.3 UNK2R19.2
N26486987: UNK2K4.4 UNK2R20.1
N26486988: UNK2K4.6 UNK2R21.2
N26486989: UNK2K2.5 UNK2R14.1
N26486990: UNK2K2.6 UNK2R13.2
N26487176: UNK2K12.4 UNK2R131.1
N26487178: UNK2K12.5 UNK2R132.1
N26487182: UNK2K33.2 UNK2R82.1
N26487183: UNK2K33.4 UNK2R117.1
N26487190: UNK2K18.4 UNK2R5.1 UNK2R6.2
N26487192: UNK2K18.5 UNK2R6.1 UNK2R133.1
N26487193: UNK2C5.1 UNK2R133.2 UNK2Y1.1 UNK2Y2.1
N26487194: UNK2C6.1 UNK2R5.2 UNK2Y1.3 UNK2Y2.3
N26487223: UNK2K13.5 UNK2R120.2
N26487224: UNK2K13.4 UNK2R119.2
N26487285: UNK2J5.1 UNK2K28.5 UNK2R84.2
N26487289: UNK2J4.1 UNK2K28.4 UNK2R83.2
N26491412: UNK2J2.1 UNK2R89.1
N26491416: UNK2J3.1 UNK2R96.1
N26491418: UNK2J3.3 UNK2R93.1
N26491425: UNK2R90.1 UNK2U1.7
N26491450: UNK2J2.2 UNK2U1.3
N26491459: UNK2R97.1 UNK2U2.7
N26491486: UNK2J3.2 UNK2U2.3
N26491497: UNK2J2.3 UNK2R86.1
N26492255: UNK2CA21.1 UNK2K34.5
N26492261: UNK2CA23.1 UNK2K36.5 UNK2K36.8
N26492266: UNK2CA24.1 UNK2K37.5
N26492386: UNK2CA29.1 UNK2K42.5
N26492392: UNK2CA26.1 UNK2K39.5
N26492464: UNK2CA34.1 UNK2K31.5
N26492470: UNK2CA27.1 UNK2K40.5
N26492603: UNK2CA37.1 UNK2K39.8
N26492609: UNK2CA40.1 UNK2K42.8
N26492613: UNK2CA28.1 UNK2K40.8
N26492615: UNK2CA25.1 UNK2K37.8
N26492621: UNK2CA22.1 UNK2K34.8
N26495382: UNK3K25.3 UNK3R55.2
N26495383: UNK3K25.4 UNK3R56.1
N26495384: UNK3K25.6 UNK3R57.2
N26495385: UNK3K25.5 UNK3R58.1
N26495387: UNK3K26.3 UNK3R59.2
N26495388: UNK3K26.4 UNK3R60.1
N26495389: UNK3K26.6 UNK3R61.2
N26495390: UNK3K26.5 UNK3R62.1
N26495392: UNK3K27.5 UNK3R66.1
N26495393: UNK3K27.6 UNK3R65.2
N26495400: UNK3K22.6 UNK3R45.2
N26495401: UNK3K22.5 UNK3R46.1
N26495402: UNK3K23.3 UNK3R47.2
N26495403: UNK3K23.4 UNK3R48.1
N26495404: UNK3K23.6 UNK3R49.2
N26495405: UNK3K23.5 UNK3R50.1
N26495407: UNK3K24.3 UNK3R51.2
N26495408: UNK3K24.4 UNK3R52.1
N26495409: UNK3K24.6 UNK3R53.2
N26495410: UNK3K24.5 UNK3R54.1
N26495425: UNK3K22.3 UNK3R102.2
N26495426: UNK3K22.4 UNK3R103.1
N26495427: UNK3K27.3 UNK3R104.2
N26495428: UNK3K27.4 UNK3R105.1
N26495543: S3_RST_N.2 UNK3J1.2 UNK3K10.4 UNK3R85.2
N26495548: UNK3C7.1 UNK3J1.1
N26495583: UNK3K17.3 UNK3R71.2
N26495584: UNK3K17.4 UNK3R72.1
N26495585: UNK3K17.5 UNK3R74.1
N26495586: UNK3K17.6 UNK3R73.2
N26495587: UNK3K21.3 UNK3R75.2
N26495588: UNK3K21.4 UNK3R76.1
N26495589: UNK3K21.5 UNK3R78.1
N26495590: UNK3K21.6 UNK3R77.2
N26495591: UNK3K29.3 UNK3R79.2
N26495592: UNK3K29.4 UNK3R80.1
N26495593: UNK3K29.6 UNK3R43.2
N26495594: UNK3K29.5 UNK3R44.1
N26495595: UNK3K30.3 UNK3R63.2
N26495596: UNK3K30.4 UNK3R64.1
N26495597: UNK3K30.5 UNK3R101.1
N26495598: UNK3K30.6 UNK3R100.2
N26495679: UNK3K16.3 UNK3R67.2
N26495680: UNK3K16.4 UNK3R68.1
N26495681: UNK3K16.5 UNK3R70.1
N26495682: UNK3K16.6 UNK3R69.2
N26495704: UNK3K6.5 UNK3R30.1
N26495706: UNK3K6.3 UNK3R27.2
N26495707: UNK3K6.4 UNK3R28.1
N26495708: UNK3K6.6 UNK3R29.2
N26495709: UNK3K7.5 UNK3R34.1
N26495711: UNK3K7.3 UNK3R31.2
N26495712: UNK3K7.4 UNK3R32.1
N26495713: UNK3K7.6 UNK3R33.2
N26495755: UNK3K11.3 UNK3R39.2
N26495756: UNK3K11.4 UNK3R40.1
N26495757: UNK3K8.5 UNK3R38.1
N26495759: UNK3K8.6 UNK3R37.2
N26495760: UNK3K11.6 UNK3R41.2
N26495761: UNK3K11.5 UNK3R42.1
N26495803: UNK3K5.5 UNK3R26.1
N26495805: UNK3K5.3 UNK3R23.2
N26495806: UNK3K5.4 UNK3R24.1
N26495807: UNK3K5.6 UNK3R25.2
N26495828: UNK3K3.5 UNK3R18.1
N26495829: UNK3K3.6 UNK3R17.2
N26495830: UNK3K3.4 UNK3R16.1
N26495831: UNK3K3.3 UNK3R15.2
N26495834: UNK3K1.5 UNK3R10.1
N26495835: UNK3K1.6 UNK3R9.2
N26495836: UNK3K1.4 UNK3R8.1
N26495837: UNK3K1.3 UNK3R7.2
N26495839: UNK3K2.3 UNK3R11.2
N26495840: UNK3K2.4 UNK3R12.1
N26495841: UNK3K4.5 UNK3R22.1
N26495843: UNK3K4.3 UNK3R19.2
N26495844: UNK3K4.4 UNK3R20.1
N26495845: UNK3K4.6 UNK3R21.2
N26495846: UNK3K2.5 UNK3R14.1
N26495847: UNK3K2.6 UNK3R13.2
N26496033: UNK3K12.4 UNK3R131.1
N26496035: UNK3K12.5 UNK3R132.1
N26496039: UNK3K33.2 UNK3R82.1
N26496040: UNK3K33.4 UNK3R117.1
N26496047: UNK3K18.4 UNK3R5.1 UNK3R6.2
N26496049: UNK3K18.5 UNK3R6.1 UNK3R133.1
N26496050: UNK3C5.1 UNK3R133.2 UNK3Y1.1 UNK3Y2.1
N26496051: UNK3C6.1 UNK3R5.2 UNK3Y1.3 UNK3Y2.3
N26496080: UNK3K13.5 UNK3R120.2
N26496081: UNK3K13.4 UNK3R119.2
N26496142: UNK3J5.1 UNK3K28.5 UNK3R84.2
N26496146: UNK3J4.1 UNK3K28.4 UNK3R83.2
N26500269: UNK3J2.1 UNK3R89.1
N26500273: UNK3J3.1 UNK3R96.1
N26500275: UNK3J3.3 UNK3R93.1
N26500282: UNK3R90.1 UNK3U1.7
N26500307: UNK3J2.2 UNK3U1.3
N26500316: UNK3R97.1 UNK3U2.7
N26500343: UNK3J3.2 UNK3U2.3
N26500354: UNK3J2.3 UNK3R86.1
N26501112: UNK3CA21.1 UNK3K34.5
N26501118: UNK3CA23.1 UNK3K36.5 UNK3K36.8
N26501123: UNK3CA24.1 UNK3K37.5
N26501243: UNK3CA29.1 UNK3K42.5
N26501249: UNK3CA26.1 UNK3K39.5
N26501321: UNK3CA34.1 UNK3K31.5
N26501327: UNK3CA27.1 UNK3K40.5
N26501460: UNK3CA37.1 UNK3K39.8
N26501466: UNK3CA40.1 UNK3K42.8
N26501470: UNK3CA28.1 UNK3K40.8
N26501472: UNK3CA25.1 UNK3K37.8
N26501478: UNK3CA22.1 UNK3K34.8
N26504239: UNK4K25.3 UNK4R55.2
N26504240: UNK4K25.4 UNK4R56.1
N26504241: UNK4K25.6 UNK4R57.2
N26504242: UNK4K25.5 UNK4R58.1
N26504244: UNK4K26.3 UNK4R59.2
N26504245: UNK4K26.4 UNK4R60.1
N26504246: UNK4K26.6 UNK4R61.2
N26504247: UNK4K26.5 UNK4R62.1
N26504249: UNK4K27.5 UNK4R66.1
N26504250: UNK4K27.6 UNK4R65.2
N26504257: UNK4K22.6 UNK4R45.2
N26504258: UNK4K22.5 UNK4R46.1
N26504259: UNK4K23.3 UNK4R47.2
N26504260: UNK4K23.4 UNK4R48.1
N26504261: UNK4K23.6 UNK4R49.2
N26504262: UNK4K23.5 UNK4R50.1
N26504264: UNK4K24.3 UNK4R51.2
N26504265: UNK4K24.4 UNK4R52.1
N26504266: UNK4K24.6 UNK4R53.2
N26504267: UNK4K24.5 UNK4R54.1
N26504282: UNK4K22.3 UNK4R102.2
N26504283: UNK4K22.4 UNK4R103.1
N26504284: UNK4K27.3 UNK4R104.2
N26504285: UNK4K27.4 UNK4R105.1
N26504400: S4_RST_N.2 UNK4J1.2 UNK4K10.4 UNK4R85.2
N26504405: UNK4C7.1 UNK4J1.1
N26504440: UNK4K17.3 UNK4R71.2
N26504441: UNK4K17.4 UNK4R72.1
N26504442: UNK4K17.5 UNK4R74.1
N26504443: UNK4K17.6 UNK4R73.2
N26504444: UNK4K21.3 UNK4R75.2
N26504445: UNK4K21.4 UNK4R76.1
N26504446: UNK4K21.5 UNK4R78.1
N26504447: UNK4K21.6 UNK4R77.2
N26504448: UNK4K29.3 UNK4R79.2
N26504449: UNK4K29.4 UNK4R80.1
N26504450: UNK4K29.6 UNK4R43.2
N26504451: UNK4K29.5 UNK4R44.1
N26504452: UNK4K30.3 UNK4R63.2
N26504453: UNK4K30.4 UNK4R64.1
N26504454: UNK4K30.5 UNK4R101.1
N26504455: UNK4K30.6 UNK4R100.2
N26504536: UNK4K16.3 UNK4R67.2
N26504537: UNK4K16.4 UNK4R68.1
N26504538: UNK4K16.5 UNK4R70.1
N26504539: UNK4K16.6 UNK4R69.2
N26504561: UNK4K6.5 UNK4R30.1
N26504563: UNK4K6.3 UNK4R27.2
N26504564: UNK4K6.4 UNK4R28.1
N26504565: UNK4K6.6 UNK4R29.2
N26504566: UNK4K7.5 UNK4R34.1
N26504568: UNK4K7.3 UNK4R31.2
N26504569: UNK4K7.4 UNK4R32.1
N26504570: UNK4K7.6 UNK4R33.2
N26504612: UNK4K11.3 UNK4R39.2
N26504613: UNK4K11.4 UNK4R40.1
N26504614: UNK4K8.5 UNK4R38.1
N26504616: UNK4K8.6 UNK4R37.2
N26504617: UNK4K11.6 UNK4R41.2
N26504618: UNK4K11.5 UNK4R42.1
N26504660: UNK4K5.5 UNK4R26.1
N26504662: UNK4K5.3 UNK4R23.2
N26504663: UNK4K5.4 UNK4R24.1
N26504664: UNK4K5.6 UNK4R25.2
N26504685: UNK4K3.5 UNK4R18.1
N26504686: UNK4K3.6 UNK4R17.2
N26504687: UNK4K3.4 UNK4R16.1
N26504688: UNK4K3.3 UNK4R15.2
N26504691: UNK4K1.5 UNK4R10.1
N26504692: UNK4K1.6 UNK4R9.2
N26504693: UNK4K1.4 UNK4R8.1
N26504694: UNK4K1.3 UNK4R7.2
N26504696: UNK4K2.3 UNK4R11.2
N26504697: UNK4K2.4 UNK4R12.1
N26504698: UNK4K4.5 UNK4R22.1
N26504700: UNK4K4.3 UNK4R19.2
N26504701: UNK4K4.4 UNK4R20.1
N26504702: UNK4K4.6 UNK4R21.2
N26504703: UNK4K2.5 UNK4R14.1
N26504704: UNK4K2.6 UNK4R13.2
N26504890: UNK4K12.4 UNK4R131.1
N26504892: UNK4K12.5 UNK4R132.1
N26504896: UNK4K33.2 UNK4R82.1
N26504897: UNK4K33.4 UNK4R117.1
N26504904: UNK4K18.4 UNK4R5.1 UNK4R6.2
N26504906: UNK4K18.5 UNK4R6.1 UNK4R133.1
N26504907: UNK4C5.1 UNK4R133.2 UNK4Y1.1 UNK4Y2.1
N26504908: UNK4C6.1 UNK4R5.2 UNK4Y1.3 UNK4Y2.3
N26504937: UNK4K13.5 UNK4R120.2
N26504938: UNK4K13.4 UNK4R119.2
N26504999: UNK4J5.1 UNK4K28.5 UNK4R84.2
N26505003: UNK4J4.1 UNK4K28.4 UNK4R83.2
N26509126: UNK4J2.1 UNK4R89.1
N26509130: UNK4J3.1 UNK4R96.1
N26509132: UNK4J3.3 UNK4R93.1
N26509139: UNK4R90.1 UNK4U1.7
N26509164: UNK4J2.2 UNK4U1.3
N26509173: UNK4R97.1 UNK4U2.7
N26509200: UNK4J3.2 UNK4U2.3
N26509211: UNK4J2.3 UNK4R86.1
N26509969: UNK4CA21.1 UNK4K34.5
N26509975: UNK4CA23.1 UNK4K36.5 UNK4K36.8
N26509980: UNK4CA24.1 UNK4K37.5
N26510100: UNK4CA29.1 UNK4K42.5
N26510106: UNK4CA26.1 UNK4K39.5
N26510178: UNK4CA34.1 UNK4K31.5
N26510184: UNK4CA27.1 UNK4K40.5
N26510317: UNK4CA37.1 UNK4K39.8
N26510323: UNK4CA40.1 UNK4K42.8
N26510327: UNK4CA28.1 UNK4K40.8
N26510329: UNK4CA25.1 UNK4K37.8
N26510335: UNK4CA22.1 UNK4K34.8

Pads without a net: CSDPS225 A17 B17 C17 D17; CSDPS229 A17 B17 C17 D17; CSDPS425 A17 B17 C17 D17; CSDPS429 A17 B17 C17 D17; D101/D501 A1 A2 A3 A4 A5 A6 A7 A8 A9 A10 A11 A12 A13 A14 A15 A16 A17 B1 B2 B3 B4 B5 B6 B7 B8 B9 B10 B11 B12 B13 B14 B15 B16 B17 C1 C2 C3 C4 C5 C6 C7 C8 C9 C10 C11 C12 C13 C14 C15 C16 C17 D2 D3 D4 D5 D6 D7 D8 D9 D10 D11 D12 D13 D14 D15 D16; D102 17 A17 B17; D103 17 A17 B17; D104 17 A17 B17; D105/D505 A1 A2 A3 A4 A5 A6 A7 A8 A9 A10 A11 A12 A13 A14 A15 A16 A17 B1 B2 B3 B4 B5 B6 B7 B8 B9 B10 B11 B12 B13 B14 B15 B16 B17 C1 C2 C3 C4 C5 C6 C7 C8 C9 C10 C11 C12 C13 C14 C15 C16 C17 D2 D3 D4 D5 D6 D7 D8 D9 D10 D11 D12 D13 D14 D15 D16; D106 17 A17 B17; D107 17 A17 B17; D108 17 A17 B17; D109 17 A17 B17; D110 17 A17 B17; D111 17 A17 B17; D112 17 A17 B17; D113 17 A17 B17; D114 17 A17 B17; D115 17 A17 B17; D116 17 A17 B17; D117/D517 A1 A2 A3 A4 A5 A6 A7 A8 A9 A10 A11 A12 A13 A14 A15 A16 A17 B1 B2 B3 B4 B5 B6 B7 B8 B9 B10 B11 B12 B13 B14 B15 B16 B17 C1 C2 C3 C4 C5 C6 C7 C8 C9 C10 C11 C12 C13 C14 C15 C16 C17 D2 D3 D4 D5 D6 D7 D8 D9 D10 D11 D12 D13 D14 D15 D16; D118 17 A17 B17; D119 17 A17 B17; D120 17 A17 B17; D121/D521 A1 A2 A3 A4 A5 A6 A7 A8 A9 A10 A11 A12 A13 A14 A15 A16 A17 B1 B2 B3 B4 B5 B6 B7 B8 B9 B10 B11 B12 B13 B14 B15 B16 B17 C1 C2 C3 C4 C5 C6 C7 C8 C9 C10 C11 C12 C13 C14 C15 C16 C17 D2 D3 D4 D5 D6 D7 D8 D9 D10 D11 D12 D13 D14 D15 D16; D122 17 A17 B17; D123 17 A17 B17; D124 17 A17 B17; D125 17 A17 B17; D126 17 A17 B17; D127 17 A17 B17; D128 17 A17 B17; D129 17 A17 B17; D130 17 A17 B17; D131 17 A17 B17; D132 17 A17 B17; D301 17 A17 B17; D302 17 A17 B17; D305 17 A17 B17; D306 17 A17 B17; D309 A1 A3 A5 A7 A9 A11 A13 A15 A17 B1 B2 B3 B4 B5 B6 B7 B8 B9 B10 B11 B12 B13 B14 B15 B16 B17 C1 C2 C3 C4 C5 C6 C7 C8 C9 C10 C11 C12 C13 C14 C15 C16 C17 D2 D4 D6 D8 D10 D12 D14 D16; D313 A1 A3 A5 A7 A9 A11 A13 A15 A17 B1 B2 B3 B4 B5 B6 B7 B8 B9 B10 B11 B12 B13 B14 B15 B16 B17 C1 C2 C3 C4 C5 C6 C7 C8 C9 C10 C11 C12 C13 C14 C15 C16 C17 D2 D4 D6 D8 D10 D12 D14 D16; D317 17 A17 B17; D318 17 A17 B17; D321 17 A17 B17; D322 17 A17 B17; DPS1 A04 A08 A10 A14 B04 B08 B10 B14 C04 C08 C10 C14; DPS2 A04 A08 A10 A14 B04 B08 B10 B14 C04 C08 C10 C14; DPS3 A04 A08 A10 A14 B04 B08 B10 B14 C04 C08 C10 C14; DPS8 A04 A08 A10 A14 B04 B08 B10 B14 C04 C08 C10 C14; FD1 1; FD2 1; FD3 1; FD4 1; FD5 1; FD6 1; FD7 1; FD8 1; FD9 1; FD10 1; FD11 1; FD12 1; FD13 1; FD14 1; FD15 1; FD16 1; HX8880-F05 1; JG_220919AA01 1; JG_220919AA02 1; K1 2 7; K2 2 7; K3 2 7; K4 2 7; K5 2 7; K6 2 7; K7 2 7; K8 2 3 4 7; K10 2 5 6 7; K11 2 7; K12 2 7; K13 2 7; K16 2 7; K17 2 7; K21 2 7; K22 2 7; K23 2 7; K24 2 7; K25 2 7; K26 2 7; K27 2 7; K28 2 7; K29 2 7; K30 2 7; K31 3 8 9 10; K33 5 6 7; K34 3 10; K36 3 10; K37 3 10; K39 3 10; K40 3 10; K42 3 10; LOGO1 1; LOGO2 1; LQFP176-20X20-P0.4 1; S1_I2C 3; S2_I2C 3; S3_I2C 3; S4_I2C 3; SITE1 NUT1 NUT2 NUT3 NUT4; SITE2 NUT1 NUT2 NUT3 NUT4; SITE3 NUT1 NUT2 NUT3 NUT4; SITE4 NUT1 NUT2 NUT3 NUT4; SKB NUT1 NUT2 NUT3 NUT4; TPL1 1; TPL2 1; TPL3 1; TPL4 1; TPL5 1; TPL6 1; TPL7 1; TPL8 1; TPL9 1; TPL10 1; TPL11 1; TPL12 1; TPL13 1; TPL14 1; TPL15 1; TPL16 1; TPL17 1; TPL18 1; TPL19 1; TPL20 1; TPL21 1; TPL22 1; TPL23 1; TPL24 1; TPL25 1; TPL26 1; TPL27 1; TPL28 1; TPL29 1; TPL30 1; TPL31 1; TPL32 1; TPL33 1; TPL34 1; TPL35 1; TPL36 1; TPL37 1; TPL38 1; TPL39 1; TPL40 1; UF1 1; UF2 1; UNK2K1 2 7; UNK2K2 2 7; UNK2K3 2 7; UNK2K4 2 7; UNK2K5 2 7; UNK2K6 2 7; UNK2K7 2 7; UNK2K8 2 3 4 7; UNK2K10 2 5 6 7; UNK2K11 2 7; UNK2K12 2 7; UNK2K13 2 7; UNK2K16 2 7; UNK2K17 2 7; UNK2K21 2 7; UNK2K22 2 7; UNK2K23 2 7; UNK2K24 2 7; UNK2K25 2 7; UNK2K26 2 7; UNK2K27 2 7; UNK2K28 2 7; UNK2K29 2 7; UNK2K30 2 7; UNK2K31 3 8 9 10; UNK2K33 5 6 7; UNK2K34 3 10; UNK2K36 3 10; UNK2K37 3 10; UNK2K39 3 10; UNK2K40 3 10; UNK2K42 3 10; UNK2UF1 1; UNK2UF2 1; UNK3K1 2 7; UNK3K2 2 7; UNK3K3 2 7; UNK3K4 2 7; UNK3K5 2 7; UNK3K6 2 7; UNK3K7 2 7; UNK3K8 2 3 4 7; UNK3K10 2 5 6 7; UNK3K11 2 7; UNK3K12 2 7; UNK3K13 2 7; UNK3K16 2 7; UNK3K17 2 7; UNK3K21 2 7; UNK3K22 2 7; UNK3K23 2 7; UNK3K24 2 7; UNK3K25 2 7; UNK3K26 2 7; UNK3K27 2 7; UNK3K28 2 7; UNK3K29 2 7; UNK3K30 2 7; UNK3K31 3 8 9 10; UNK3K33 5 6 7; UNK3K34 3 10; UNK3K36 3 10; UNK3K37 3 10; UNK3K39 3 10; UNK3K40 3 10; UNK3K42 3 10; UNK3UF1 1; UNK3UF2 1; UNK4K1 2 7; UNK4K2 2 7; UNK4K3 2 7; UNK4K4 2 7; UNK4K5 2 7; UNK4K6 2 7; UNK4K7 2 7; UNK4K8 2 3 4 7; UNK4K10 2 5 6 7; UNK4K11 2 7; UNK4K12 2 7; UNK4K13 2 7; UNK4K16 2 7; UNK4K17 2 7; UNK4K21 2 7; UNK4K22 2 7; UNK4K23 2 7; UNK4K24 2 7; UNK4K25 2 7; UNK4K26 2 7; UNK4K27 2 7; UNK4K28 2 7; UNK4K29 2 7; UNK4K30 2 7; UNK4K31 3 8 9 10; UNK4K33 5 6 7; UNK4K34 3 10; UNK4K36 3 10; UNK4K37 3 10; UNK4K39 3 10; UNK4K40 3 10; UNK4K42 3 10; UNK4UF1 1; UNK4UF2 1; UNK038HX-8880F5K4Q-A100 1; UNK980HX-8880F5-KBG- 1; UTL1 A17 B17; UTL2 A17 B17; UTL3 A17 B17; UTL4 A17 B17; UTL5 A17 B17; UTL6 A17 B17; UTL7 A17 B17; UTL8 A17 B17

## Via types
v1: diameter 0.559, hole 0.305, TOP to BOTTOM, 3617 vias
v2: diameter 0.508, hole 0.305, TOP to BOTTOM, 303 vias

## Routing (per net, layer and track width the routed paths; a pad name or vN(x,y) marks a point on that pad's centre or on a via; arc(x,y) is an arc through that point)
GND: length 241.8
  TOP w0.231: SITE1.146 241.07,248.03 241.43,247.67 v1(241.43,247.43) ; v1(331.54,193.59) 331.83,193.88 SITE4.108 ; v1(336.36,235.23) 336.63,235.23 arc(336.91,235.11) 337.03,234.83 SITE2.38 ; SITE4.62 v1(340.23,182.83) ; v1(243.63,235.36) 243.63,235.23 243.51,235.11 arc(243.45,235.02) 243.43,234.91 SITE1.4 ; v1(323.63,254.03) 323.83,254.23 SITE2.128 ; v1(323.63,175.36) 323.63,175.23 323.51,175.11 arc(323.45,175.02) 323.43,174.91 SITE4.4 ; 259.86,225.81 259.86,225.95 arc(259.85,226.04) 259.8,226.12 255.43,230.48 SITE1.34 ; SITE4.34 335.43,170.48 339.8,166.12 arc(339.85,166.04) 339.86,165.95 339.86,165.81 ; v1(250.96,175.23) 251.03,175.16 SITE3.23 ; SITE4.146 321.07,188.03 321.43,187.67 v1(321.43,187.43) ; v1(323.63,194.03) 323.83,194.23 SITE4.128 ; SITE1.128 243.83,254.23 v1(243.63,254.03) ; v1(241.43,187.43) 241.43,187.67 241.07,188.03 SITE3.146 ; 253.56,165.29 253.28,165.57 arc(253.09,165.84) 253.03,166.17 SITE3.28 ; v1(250.96,235.23) 251.03,235.16 SITE1.23 ; v1(256.36,175.23) 256.63,175.23 arc(256.91,175.11) 257.03,174.83 SITE3.38 ; 339.86,225.81 339.86,225.95 arc(339.85,226.04) 339.8,226.12 335.43,230.48 SITE2.34 ; v1(256.36,235.23) 256.63,235.23 arc(256.91,235.11) 257.03,234.83 SITE1.38 ; SITE2.4 323.43,234.91 arc(323.45,235.02) 323.51,235.11 323.63,235.23 v1(323.63,235.36) ; SITE2.62 v1(340.23,242.83) ; SITE4.23 331.03,175.16 v1(330.96,175.23) ; SITE4.38 337.03,174.83 arc(336.91,175.11) 336.63,175.23 v1(336.36,175.23) ; SITE4.28 333.03,166.17 arc(333.09,165.84) 333.28,165.57 333.56,165.29 ; SITE2.28 333.03,231.52 ; v1(331.54,253.59) 331.83,253.88 SITE2.108 ; SITE1.108 251.83,253.88 v1(251.54,253.59) ; SITE2.23 331.03,235.16 v1(330.96,235.23) ; v1(243.63,175.36) 243.63,175.23 243.51,175.11 arc(243.45,175.02) 243.43,174.91 SITE3.4 ; v1(321.43,247.43) 321.43,247.67 321.07,248.03 SITE2.146 ; SITE3.34 255.43,170.48 259.8,166.12 arc(259.85,166.04) 259.86,165.95 259.86,165.81 ; SITE1.62 v1(260.23,242.83) ; SITE3.62 v1(260.23,182.83) ; SITE1.28 253.03,231.52
  TOP w0.381: UNK3CD21.2 v1(262.36,164.73) ; v1(352.24,189.5) UNK4CD10.2 ; v1(352.24,243.91) UNK2CD20.2 ; v1(249.28,164.73) UNK3CD22.2 ; v1(272.24,245.18) CD15.2 ; v1(250.17,224.73) CD23.2 ; v1(352.24,181.37) UNK4CD3.2 ; UNK4CD5.2 v1(343.63,164.73) ; v1(331.06,224.73) UNK2CD8.2 ; v1(310.42,253.69) UNK2CD12.2 ; v1(352.24,185.18) UNK4CD15.2 ; v1(310.42,246.66) UNK2CD6.2 ; v1(339.65,205.56) UNK4CD11.2 ; v1(333.72,265.56) UNK2CD16.2 ; v1(251.94,265.56) CD18.2 ; v1(254.61,205.56) UNK3CD4.2 ; v1(310.42,193.69) UNK4CD12.2 ; v1(331.05,205.56) UNK4CD14.2 ; v1(336.77,164.73) UNK4CD9.2 ; v1(352.24,245.18) UNK2CD15.2 ; v1(256.77,224.73) CD9.2 ; v1(230.42,247.93) CD17.2 ; UNK4CD21.2 v1(342.36,164.73) ; v1(251.05,205.56) UNK3CD14.2 ; v1(272.24,185.18) UNK3CD15.2 ; v1(352.24,183.91) UNK4CD20.2 ; v1(331.94,265.56) UNK2CD18.2 ; v1(251.05,265.56) CD14.2 ; v1(330.17,224.73) UNK2CD23.2 ; v1(333.72,205.56) UNK4CD16.2 ; v1(310.42,243.41) UNK2CD19.2 ; v1(352.24,249.5) UNK2CD10.2 ; v1(230.42,246.66) CD6.2 ; v1(327.57,265.56) UNK2CD24.2 ; v1(317.98,224.73) UNK2CD1.2 ; v1(352.24,241.37) UNK2CD3.2 ; v1(230.42,186.66) UNK3CD6.2 ; v1(259.65,265.56) CD11.2 ; v1(272.24,243.91) CD20.2 ; v1(230.42,253.69) CD12.2 ; v1(310.42,249.2) UNK2CD25.2 ; v1(272.24,182.64) UNK3CD7.2 ; v1(230.42,243.41) CD19.2 ; v1(272.24,249.5) CD10.2 ; v1(256.77,164.73) UNK3CD9.2 ; v1(331.94,205.56) UNK4CD18.2 ; v1(230.42,189.2) UNK3CD25.2 ; v1(272.24,189.5) UNK3CD10.2 ; v1(330.17,164.73) UNK4CD23.2 ; v1(336.77,224.73) UNK2CD9.2 ; v1(332.83,265.56) UNK2CD13.2 ; v1(249.28,224.73) CD22.2 ; v1(250.17,164.73) UNK3CD23.2 ; v1(251.06,224.73) CD8.2 ; v1(310.42,187.93) UNK4CD17.2 ; v1(352.24,182.64) UNK4CD7.2 ; v1(272.24,181.37) UNK3CD3.2 ; v1(310.42,189.2) UNK4CD25.2 ; v1(237.98,164.73) UNK3CD1.2 ; v1(331.06,164.73) UNK4CD8.2 ; v1(334.61,205.56) UNK4CD4.2 ; v1(252.83,205.56) UNK3CD13.2 ; CD21.2 v1(262.36,224.73) ; v1(251.94,205.56) UNK3CD18.2 ; v1(329.28,224.73) UNK2CD22.2 ; v1(272.24,183.91) UNK3CD20.2 ; v1(272.24,241.37) CD3.2 ; v1(230.42,183.41) UNK3CD19.2 ; v1(339.65,265.56) UNK2CD11.2 ; v1(310.42,247.93) UNK2CD17.2 ; v1(251.06,164.73) UNK3CD8.2 ; v1(327.57,205.56) UNK4CD24.2 ; v1(329.28,164.73) UNK4CD22.2 ; v1(331.05,265.56) UNK2CD14.2 ; v1(253.72,265.56) CD16.2 ; v1(310.42,183.41) UNK4CD19.2 ; UNK2CD5.2 v1(343.63,224.73) ; v1(247.57,205.56) UNK3CD24.2 ; v1(334.61,265.56) UNK2CD4.2 ; v1(230.42,193.69) UNK3CD12.2 ; v1(237.98,224.73) CD1.2 ; UNK3CD5.2 v1(263.63,164.73) ; v1(230.42,249.2) CD25.2 ; UNK2CD21.2 v1(342.36,224.73) ; v1(259.65,205.56) UNK3CD11.2 ; v1(272.24,242.64) CD7.2 ; v1(253.72,205.56) UNK3CD16.2 ; v1(352.24,242.64) UNK2CD7.2 ; CD5.2 v1(263.63,224.73) ; v1(247.57,265.56) CD24.2 ; v1(310.42,186.66) UNK4CD6.2 ; v1(254.61,265.56) CD4.2 ; v1(252.83,265.56) CD13.2 ; v1(230.42,187.93) UNK3CD17.2 ; v1(317.98,164.73) UNK4CD1.2 ; v1(332.83,205.56) UNK4CD13.2
  BOTTOM w0.119: K1.G5 178.7,214 arc(179.09,214.17) 179.25,214.56 v1(179.25,215.49) ; UNK3K27.G5 212.48,173.11 arc(212.87,173.27) 213.04,173.67 v1(213.04,174.59) ; v1(311.31,300.41) 312.24,300.41 arc(312.63,300.25) 312.79,299.85 K4.G5 ; v1(417.99,285.57) 418.92,285.57 arc(419.31,285.73) 419.47,286.12 UNK2K1.G6 ; v1(197.94,176.52) 197.94,177.36 arc(198.05,177.64) 198.33,177.76 UNK3K27.G8 ; K4.G3 308.14,300.02 arc(308.26,300.3) 308.54,300.41 v1(309.38,300.41) ; CC20.2 v1(254.61,267.15) ; UNK3K27.G6 198.49,173.11 arc(198.1,173.27) 197.94,173.67 v1(197.94,174.59) ; CC40.2 v1(257.99,246.67) ; v1(284.64,300.41) 285.57,300.41 arc(285.96,300.25) 286.12,299.85 K21.G5 ; v1(417.99,300.67) 418.92,300.67 arc(419.31,300.5) 419.47,300.11 UNK2K1.G5 ; K21.G3 281.47,300.02 arc(281.59,300.3) 281.87,300.41 v1(282.71,300.41) ; K1.G3 178.86,218.65 arc(179.14,218.54) 179.25,218.26 v1(179.25,217.42) ; v1(213.04,176.52) 213.04,177.36 arc(212.92,177.64) 212.64,177.76 UNK3K27.G3
  BOTTOM w0.381: CC27.2 v1(272.24,249.5) CD10.2 ; UNK2CC41.2 v1(310.42,249.2) UNK2CD25.2 ; CC41.2 v1(230.42,249.2) CD25.2 ; CC30.2 v1(230.42,243.41) CD19.2 ; v1(249.28,224.73) CC31.2 ; v1(230.42,186.66) UNK3CC7.2 ; v1(310.42,247.93) UNK2CC4.2 ; UNK2CC8.2 v1(343.63,224.73) ; v1(251.06,164.73) UNK3CC11.2 ; v1(333.72,205.56) UNK4CC26.2 ; v1(336.77,164.73) UNK4CC13.2 ; v1(256.77,224.73) CC13.2 ; v1(330.17,224.73) UNK2CC6.2 ; v1(352.24,181.37) UNK4CC35.2 ; v1(331.05,265.56) UNK2CC22.2 ; UNK4CD25.2 v1(310.42,189.2) UNK4CC41.2 ; v1(252.83,205.56) UNK3CC19.2 ; v1(331.94,205.56) UNK4CC34.2 ; CD12.2 v1(230.42,253.69) CC17.2 ; v1(250.17,164.73) UNK3CC6.2 ; UNK3CC38.2 v1(247.57,205.56) UNK3CD24.2 ; v1(334.61,265.56) UNK2CC9.2 ; UNK2CC28.2 v1(339.65,265.56) UNK2CD11.2 ; UNK4CC28.2 v1(339.65,205.56) UNK4CD11.2 ; v1(253.72,205.56) UNK3CC26.2 ; v1(310.42,187.93) UNK4CC4.2 ; UNK2CC32.2 v1(342.36,224.73) ; v1(331.06,224.73) UNK2CC11.2 ; v1(336.77,224.73) UNK2CC13.2 ; CC8.2 v1(263.63,224.73) ; UNK3CC32.2 v1(262.36,164.73) ; UNK3CD11.2 v1(259.65,205.56) UNK3CC28.2 ; UNK4CD10.2 v1(352.24,189.5) UNK4CC27.2 ; v1(251.05,205.56) UNK3CC22.2 ; UNK3CD15.2 v1(272.24,185.18) UNK3CC25.2 ; v1(272.24,181.37) UNK3CC35.2 ; v1(253.72,265.56) CC26.2 ; UNK4CC25.2 v1(352.24,185.18) UNK4CD15.2 ; v1(272.24,243.91) CC33.2 ; UNK4CC38.2 v1(327.57,205.56) UNK4CD24.2 ; v1(256.77,164.73) UNK3CC13.2 ; UNK2CC25.2 v1(352.24,245.18) UNK2CD15.2 ; CD11.2 v1(259.65,265.56) CC28.2 ; v1(252.83,265.56) CC19.2 ; v1(251.94,265.56) CC34.2 ; v1(329.28,164.73) UNK4CC31.2 ; UNK3CD10.2 v1(272.24,189.5) UNK3CC27.2 ; v1(254.61,265.56) CC9.2 ; v1(317.98,164.73) UNK4CC1.2 ; v1(331.05,205.56) UNK4CC22.2 ; v1(331.94,265.56) UNK2CC34.2 ; UNK2CC30.2 v1(310.42,243.41) UNK2CD19.2 ; v1(272.24,183.91) UNK3CC33.2 ; UNK4CC8.2 v1(343.63,164.73) ; UNK2CD24.2 v1(327.57,265.56) UNK2CC38.2 ; UNK4CD12.2 v1(310.42,193.69) UNK4CC17.2 ; v1(352.24,242.64) UNK2CC36.2 ; v1(254.61,205.56) UNK3CC9.2 ; v1(272.24,241.37) CC35.2 ; UNK3CD25.2 v1(230.42,189.2) UNK3CC41.2 ; v1(352.24,241.37) UNK2CC35.2 ; v1(237.98,224.73) CC1.2 ; v1(237.98,164.73) UNK3CC1.2 ; v1(329.28,224.73) UNK2CC31.2 ; UNK2CD12.2 v1(310.42,253.69) UNK2CC17.2 ; v1(331.06,164.73) UNK4CC11.2 ; UNK4CC32.2 v1(342.36,164.73) ; v1(332.83,205.56) UNK4CC19.2 ; v1(230.42,247.93) CC4.2 ; CC25.2 v1(272.24,245.18) CD15.2 ; v1(251.05,265.56) CC22.2 ; v1(251.06,224.73) CC11.2 ; v1(272.24,242.64) CC36.2 ; UNK4CD19.2 v1(310.42,183.41) UNK4CC30.2 ; v1(249.28,164.73) UNK3CC31.2 ; v1(333.72,265.56) UNK2CC26.2 ; v1(352.24,243.91) UNK2CC33.2 ; v1(352.24,183.91) UNK4CC33.2 ; v1(334.61,205.56) UNK4CC9.2 ; v1(272.24,182.64) UNK3CC36.2 ; v1(330.17,164.73) UNK4CC6.2 ; UNK3CD19.2 v1(230.42,183.41) UNK3CC30.2 ; v1(332.83,265.56) UNK2CC19.2 ; v1(310.42,246.66) UNK2CC7.2 ; v1(230.42,187.93) UNK3CC4.2 ; CD24.2 v1(247.57,265.56) CC38.2 ; v1(317.98,224.73) UNK2CC1.2 ; v1(251.94,205.56) UNK3CC34.2 ; UNK3CC17.2 v1(230.42,193.69) UNK3CD12.2 ; UNK2CC27.2 v1(352.24,249.5) UNK2CD10.2 ; UNK3CC8.2 v1(263.63,164.73) ; v1(250.17,224.73) CC6.2 ; v1(352.24,182.64) UNK4CC36.2 ; v1(230.42,246.66) CC7.2 ; CC32.2 v1(262.36,224.73) ; v1(310.42,186.66) UNK4CC7.2
  vias: v1(18.48,292.01) v1(18.48,286.93) v1(18.48,281.85) v1(18.48,276.77) v1(18.48,271.69) v1(18.48,266.61) v1(18.48,261.53) v1(18.48,256.45) v1(18.48,251.37) v1(18.48,246.29) v1(18.48,241.21) v1(18.48,236.13) v1(18.48,231.05) v1(18.48,225.97) v1(18.48,220.89) v1(18.48,215.81) v1(18.48,210.73) v1(18.48,205.65) v1(18.48,200.57) v1(18.48,195.49) v1(18.48,190.41) v1(18.48,185.33) v1(18.48,180.25) v1(18.48,175.17) v1(18.48,170.09) v1(18.48,165.01) v1(18.48,159.93) v1(18.48,154.85) v1(18.48,149.77) v1(18.48,144.69) v1(18.48,139.61) v1(23.56,292.01) v1(23.56,286.93) v1(23.56,281.85) v1(23.56,276.77) v1(23.56,271.69) v1(23.56,266.61) v1(23.56,261.53) v1(23.56,256.45) v1(23.56,251.37) v1(23.56,246.29) v1(23.56,241.21) v1(23.56,236.13) v1(23.56,231.05) v1(23.56,225.97) v1(23.56,220.89) v1(23.56,215.81) v1(23.56,210.73) v1(23.56,205.65) v1(23.56,200.57) v1(23.56,195.49) v1(23.56,190.41) v1(23.56,185.33) v1(23.56,180.25) v1(23.56,175.17) v1(23.56,170.09) v1(23.56,165.01) v1(23.56,159.93) v1(23.56,154.85) v1(23.56,149.77) v1(23.56,144.69) v1(23.56,139.61) v1(28.64,292.01) v1(28.64,286.93) v1(28.64,281.85) v1(28.64,276.77) v1(28.64,271.69) v1(28.64,266.61) v1(28.64,261.53) v1(28.64,256.45) v1(28.64,251.37) v1(28.64,246.29) v1(28.64,241.21) v1(28.64,236.13) v1(28.64,231.05) v1(28.64,225.97) v1(28.64,220.89) v1(28.64,215.81) v1(28.64,210.73) v1(28.64,205.65) v1(28.64,200.57) v1(28.64,195.49) v1(28.64,190.41) v1(28.64,185.33) v1(28.64,180.25) v1(28.64,175.17) v1(28.64,170.09) v1(28.64,165.01) v1(28.64,159.93) v1(28.64,154.85) v1(28.64,149.77) v1(28.64,144.69) v1(28.64,139.61) v1(33.72,292.01) v1(33.72,286.93) v1(33.72,281.85) v1(33.72,276.77) v1(33.72,271.69) v1(33.72,266.61) v1(33.72,261.53) v1(33.72,256.45) v1(33.72,251.37) v1(33.72,246.29) v1(33.72,241.21) v1(33.72,236.13) v1(33.72,231.05) v1(33.72,225.97) v1(33.72,220.89) v1(33.72,215.81) v1(33.72,210.73) v1(33.72,205.65) v1(33.72,200.57) v1(33.72,195.49) v1(33.72,190.41) v1(33.72,185.33) v1(33.72,180.25) v1(33.72,175.17) v1(33.72,170.09) v1(33.72,165.01) v1(33.72,159.93) v1(33.72,154.85) v1(33.72,149.77) v1(33.72,144.69) v1(33.72,139.61) v1(38.8,292.01) v1(38.8,286.93) v1(38.8,281.85) v1(38.8,276.77) v1(38.8,271.69) v1(38.8,266.61) v1(38.8,261.53) v1(38.8,256.45) v1(38.8,251.37) v1(38.8,246.29) v1(38.8,241.21) v1(38.8,236.13) v1(38.8,231.05) v1(38.8,225.97) v1(38.8,220.89) v1(38.8,215.81) v1(38.8,210.73) v1(38.8,205.65) v1(38.8,200.57) v1(38.8,195.49) v1(38.8,190.41) v1(38.8,185.33) v1(38.8,180.25) v1(38.8,175.17) v1(38.8,170.09) v1(38.8,165.01) v1(38.8,159.93) v1(38.8,154.85) v1(38.8,149.77) v1(38.8,144.69) v1(38.8,139.61) v1(43.88,292.01) v1(43.88,286.93) v1(43.88,281.85) v1(43.88,276.77) v1(43.88,271.69) v1(43.88,266.61) v1(43.88,261.53) v1(43.88,256.45) v1(43.88,251.37) v1(43.88,246.29) v1(43.88,241.21) v1(43.88,236.13) v1(43.88,231.05) v1(43.88,225.97) v1(43.88,220.89) v1(43.88,215.81) v1(43.88,210.73) v1(43.88,205.65) v1(43.88,200.57) v1(43.88,195.49) v1(43.88,190.41) v1(43.88,185.33) v1(43.88,180.25) v1(43.88,175.17) v1(43.88,170.09) v1(43.88,165.01) v1(43.88,159.93) v1(43.88,154.85) v1(43.88,149.77) v1(43.88,144.69) v1(43.88,139.61) v1(48.96,292.01) v1(48.96,286.93) v1(48.96,281.85) v1(48.96,276.77) v1(48.96,271.69) v1(48.96,266.61) v1(48.96,261.53) v1(48.96,256.45) v1(48.96,251.37) v1(48.96,246.29) v1(48.96,241.21) v1(48.96,236.13) v1(48.96,231.05) v1(48.96,225.97) v1(48.96,220.89) v1(48.96,215.81) v1(48.96,210.73) v1(48.96,205.65) v1(48.96,200.57) v1(48.96,195.49) v1(48.96,190.41) v1(48.96,185.33) v1(48.96,180.25) v1(48.96,175.17) v1(48.96,170.09) v1(48.96,165.01) v1(48.96,159.93) v1(48.96,154.85) v1(48.96,149.77) v1(48.96,144.69) v1(48.96,139.61) v1(54.04,292.01) v1(54.04,286.93) v1(54.04,281.85) v1(54.04,276.77) v1(54.04,271.69) v1(54.04,266.61) v1(54.04,261.53) v1(54.04,256.45) v1(54.04,251.37) v1(54.04,246.29) v1(54.04,241.21) v1(54.04,236.13) v1(54.04,231.05) v1(54.04,225.97) v1(54.04,220.89) v1(54.04,215.81) v1(54.04,210.73) v1(54.04,205.65) v1(54.04,200.57) v1(54.04,195.49) v1(54.04,190.41) v1(54.04,185.33) v1(54.04,180.25) v1(54.04,175.17) v1(54.04,170.09) v1(54.04,165.01) v1(54.04,159.93) v1(54.04,154.85) v1(54.04,149.77) v1(54.04,144.69) v1(54.04,139.61) v1(59.12,292.01) v1(59.12,286.93) v1(59.12,281.85) v1(59.12,276.77) v1(59.12,271.69) v1(59.12,266.61) v1(59.12,261.53) v1(59.12,256.45) v1(59.12,251.37) v1(59.12,246.29) v1(59.12,241.21) v1(59.12,236.13) v1(59.12,231.05) v1(59.12,225.97) v1(59.12,220.89) v1(59.12,215.81) v1(59.12,200.57) v1(59.12,195.49) v1(59.12,190.41) v1(59.12,185.33) v1(59.12,180.25) v1(59.12,175.17) v1(59.12,170.09) v1(59.12,165.01) v1(59.12,159.93) v1(59.12,154.85) v1(59.12,149.77) v1(59.12,144.69) v1(59.12,139.61) v1(64.2,266.61) v1(64.2,261.53) v1(64.2,256.45) v1(64.2,251.37) v1(64.2,200.57) v1(64.2,195.49) v1(64.2,190.41) v1(64.2,185.33) v1(64.2,180.25) v1(64.2,175.17) v1(64.2,170.09) v1(64.2,165.01) v1(64.2,159.93) v1(64.2,154.85) v1(64.2,149.77) v1(64.2,144.69) v1(64.2,139.61) v1(69.28,261.53) v1(69.28,256.45) v1(69.28,251.37) v1(69.28,200.57) v1(69.28,195.49) v1(69.28,190.41) v1(69.28,185.33) v1(69.28,180.25) v1(69.28,175.17) v1(69.28,170.09) v1(69.28,165.01) v1(69.28,159.93) v1(69.28,154.85) v1(69.28,149.77) v1(69.28,144.69) v1(69.28,139.61) v1(74.36,261.53) v1(74.36,256.45) v1(74.36,251.37) v1(74.36,200.57) v1(74.36,195.49) v1(74.36,190.41) v1(74.36,185.33) v1(74.36,180.25) v1(74.36,175.17) v1(74.36,170.09) v1(74.36,165.01) v1(74.36,159.93) v1(74.36,154.85) v1(74.36,149.77) v1(74.36,144.69) v1(74.36,139.61) v1(79.44,292.01) v1(79.44,286.93) v1(79.44,281.85) v1(79.44,276.77) v1(79.44,271.69) v1(79.44,266.61) v1(79.44,261.53) v1(79.44,256.45) v1(79.44,251.37) v1(79.44,200.57) v1(79.44,195.49) v1(79.44,190.41) v1(79.44,185.33) v1(79.44,180.25) v1(79.44,175.17) v1(79.44,170.09) v1(79.44,165.01) v1(79.44,159.93) v1(79.44,154.85) v1(79.44,149.77) v1(79.44,144.69) v1(79.44,139.61) v1(84.52,261.53) v1(84.52,256.45) v1(84.52,251.37) v1(84.52,236.13) v1(84.52,231.05) v1(84.52,200.57) v1(84.52,195.49) v1(84.52,190.41) v1(84.52,185.33) v1(84.52,180.25) v1(84.52,170.09) v1(84.52,154.85) v1(84.52,149.77) v1(84.52,144.69) v1(84.52,139.61) v1(89.6,261.53) v1(89.6,256.45) v1(89.6,251.37) v1(89.6,236.13) v1(89.6,231.05) v1(89.6,225.97) v1(89.6,195.49) v1(89.6,190.41) v1(89.6,185.33) v1(89.6,154.85) v1(89.6,149.77) v1(89.6,144.69) v1(89.6,139.61) v1(94.68,266.61) v1(94.68,261.53) v1(94.68,256.45) v1(94.68,251.37) v1(94.68,154.85) v1(94.68,149.77) v1(94.68,144.69) v1(94.68,139.61) v1(99.76,266.61) v1(99.76,261.53) v1(99.76,256.45) v1(99.76,251.37) v1(99.76,154.85) v1(99.76,149.77) v1(99.76,144.69) v1(99.76,139.61) v1(104.84,261.53) v1(104.84,256.45) v1(104.84,251.37) v1(104.84,154.85) v1(104.84,149.77) v1(104.84,144.69) v1(104.84,139.61) v1(109.92,261.53) v1(109.92,256.45) v1(109.92,251.37) v1(109.92,154.85) v1(109.92,149.77) v1(109.92,144.69) v1(109.92,139.61) v1(115,266.61) v1(115,261.53) v1(115,256.45) v1(115,251.37) v1(115,205.65) v1(115,159.93) v1(115,154.85) v1(115,149.77) v1(115,144.69) v1(115,139.61) v1(120.08,261.53) v1(120.08,256.45) v1(120.08,251.37) v1(120.08,205.65) v1(120.08,159.93) v1(120.08,154.85) v1(120.08,149.77) v1(120.08,144.69) v1(120.08,139.61) v1(125.16,261.53) v1(125.16,256.45) v1(125.16,251.37) v1(125.16,205.65) v1(125.16,159.93) v1(125.16,154.85) v1(128.57,142.24) v1(130.24,266.61) v1(130.24,261.53) v1(130.24,256.45) v1(130.24,251.37) v1(130.24,205.65) v1(130.24,200.57) v1(130.24,159.93) v1(130.51,149.86) v1(130.51,146.05) v1(130.51,138.43) v1(130.51,134.62) v1(155.64,286.93) v1(155.64,266.61) v1(155.64,261.53) v1(155.64,256.45) v1(155.64,251.37) v1(155.64,190.41) v1(155.64,185.33) v1(155.64,175.17) v1(155.64,170.09) v1(155.64,159.93) v1(155.64,154.85) v1(155.64,149.77) v1(155.64,139.61) v1(160.72,266.61) v1(160.72,251.37) v1(160.72,170.09) v1(160.72,154.85) v1(160.72,139.61) v1(167.7,265.45) v1(167.7,262) v1(167.7,259.8) v1(167.7,257.6) v1(167.7,255.15) v1(167.7,251.73) v1(167.7,248.28) v1(167.7,246.08) v1(167.7,243.88) v1(167.7,241.43) v1(167.7,238.02) v1(167.7,234.57) v1(167.7,232.37) v1(167.7,230.17) v1(167.7,227.72) v1(167.7,224.3) v1(167.7,220.85) v1(167.7,218.65) v1(167.7,216.45) v1(167.7,214) v1(167.7,210.84) v1(167.7,207.39) v1(167.7,205.19) v1(167.7,202.99) v1(167.7,200.54) v1(167.7,196.87) v1(167.7,193.42) v1(167.7,191.22) v1(167.7,189.02) v1(167.7,186.57) v1(167.7,183.41) v1(167.7,179.96) v1(167.7,177.76) v1(167.7,175.56) v1(167.7,173.11) v1(167.7,169.95) v1(167.7,166.5) v1(167.7,164.3) v1(167.7,162.1) v1(167.7,159.65) v1(167.7,156.23) v1(167.7,152.78) v1(167.7,150.58) v1(167.7,148.38) v1(167.7,145.93) v1(167.7,143.02) v1(167.7,139.57) v1(167.7,137.37) v1(167.7,135.17) v1(167.7,132.72) v1(175.7,265.45) v1(175.7,262) v1(175.7,259.8) v1(175.7,257.6) v1(175.7,255.15) v1(175.7,251.73) v1(175.7,248.28) v1(175.7,246.08) v1(175.7,243.88) v1(175.7,241.43) v1(175.7,238.02) v1(175.7,234.57) v1(175.7,232.37) v1(175.7,230.17) v1(175.7,227.72) v1(175.7,224.3) v1(175.7,220.85) v1(175.7,216.45) v1(175.7,210.84) v1(175.7,207.39) v1(175.7,205.19) v1(175.7,202.99) v1(175.7,200.54) v1(175.7,196.87) v1(175.7,193.42) v1(175.7,191.22) v1(175.7,189.02) v1(175.7,186.57) v1(175.7,183.41) v1(175.7,179.96) v1(175.7,177.76) v1(175.7,175.56) v1(175.7,173.11) v1(175.7,169.95) v1(175.7,166.5) v1(175.7,164.3) v1(175.7,162.1) v1(175.7,159.65) v1(175.7,156.23) v1(175.7,152.78) v1(175.7,150.58) v1(175.7,148.38) v1(175.7,145.93) v1(175.7,143.02) v1(175.7,139.57) v1(175.7,137.37) v1(175.7,135.17) v1(175.7,132.72) v1(183.65,131.06) v1(184.47,265.45) v1(184.47,262) v1(184.47,259.8) v1(184.47,257.6) v1(184.47,255.15) v1(184.47,251.73) v1(184.47,248.28) v1(184.47,246.08) v1(184.47,243.88) v1(184.47,241.43) v1(184.47,238.02) v1(184.47,234.57) v1(184.47,232.37) v1(184.47,230.17) v1(184.47,227.72) v1(184.47,224.3) v1(184.47,220.85) v1(184.47,218.65) v1(184.47,216.45) v1(184.47,214) v1(184.47,210.84) v1(184.47,207.39) v1(184.47,205.19) v1(184.47,202.99) v1(184.47,200.54) v1(184.47,196.87) v1(184.47,193.42) v1(184.47,191.22) v1(184.47,189.02) v1(184.47,186.57) v1(184.47,183.41) v1(184.47,179.96) v1(184.47,177.76) v1(184.47,175.56) v1(184.47,173.11) v1(184.47,169.95) v1(184.47,166.5) v1(184.47,164.3) v1(184.47,162.1) v1(184.47,159.65) v1(184.47,156.23) v1(184.47,152.78) v1(184.47,150.58) v1(184.47,148.38) v1(184.47,145.93) v1(186.12,139.61) v1(191.2,139.61) v1(191.78,131.06) v1(192.47,265.45) v1(192.47,262) v1(192.47,259.8) v1(192.47,257.6) v1(192.47,255.15) v1(192.47,251.73) v1(192.47,248.28) v1(192.47,246.08) v1(192.47,243.88) v1(192.47,241.43) v1(192.47,238.02) v1(192.47,234.57) v1(192.47,232.37) v1(192.47,230.17) v1(192.47,227.72) v1(192.47,224.3) v1(192.47,220.85) v1(192.47,218.65) v1(192.47,216.45) v1(192.47,214) v1(192.47,210.84) v1(192.47,207.39) v1(192.47,205.19) v1(192.47,202.99) v1(192.47,200.54) v1(192.47,196.87) v1(192.47,193.42) v1(192.47,191.22) v1(192.47,189.02) v1(192.47,186.57) v1(192.47,183.41) v1(192.47,179.96) v1(192.47,177.76) v1(192.47,175.56) v1(192.47,173.11) v1(192.47,169.95) v1(192.47,166.5) v1(192.47,164.3) v1(192.47,162.1) v1(192.47,159.65) v1(192.47,156.23) v1(192.47,152.78) v1(192.47,150.58) v1(192.47,148.38) v1(192.47,145.93) v1(196.28,139.61) v1(200.98,265.45) v1(200.98,262) v1(200.98,259.8) v1(200.98,257.6) v1(200.98,255.15) v1(201.23,251.73) v1(201.23,248.28) v1(201.23,246.08) v1(201.23,243.88) v1(201.23,241.43) v1(201.23,238.02) v1(201.23,234.57) v1(201.23,232.37) v1(201.23,230.17) v1(201.23,227.72) v1(201.23,224.3) v1(201.23,220.85) v1(201.23,218.65) v1(201.23,216.45) v1(201.23,214) v1(201.23,210.84) v1(201.23,207.39) v1(201.23,205.19) v1(201.23,202.99) v1(201.23,200.54) v1(201.23,196.87) v1(201.23,193.42) v1(201.23,191.22) v1(201.23,189.02) v1(201.23,186.57) v1(201.36,139.61) v1(201.49,183.41) v1(201.49,179.96) v1(201.49,175.56) v1(201.49,169.95) v1(201.49,166.5) v1(201.49,164.3) v1(201.49,162.1) v1(201.49,159.65) v1(201.49,156.48) v1(201.49,153.03) v1(201.49,150.83) v1(201.49,148.63) v1(201.49,146.18) v1(206.44,292.01) v1(206.44,286.93) v1(206.44,281.85) v1(206.44,276.77) v1(206.44,271.69) v1(206.44,139.61) v1(208.98,265.45) v1(208.98,262) v1(208.98,259.8) v1(208.98,257.6) v1(208.98,255.15) v1(209.23,251.73) v1(209.23,248.28) v1(209.23,246.08) v1(209.23,243.88) v1(209.23,241.43) v1(209.23,238.02) v1(209.23,234.57) v1(209.23,232.37) v1(209.23,230.17) v1(209.23,227.72) v1(209.23,224.3) v1(209.23,220.85) v1(209.23,218.65) v1(209.23,216.45) v1(209.23,214) v1(209.23,210.84) v1(209.23,207.39) v1(209.23,205.19) v1(209.23,202.99) v1(209.23,200.54) v1(209.23,196.87) v1(209.23,193.42) v1(209.23,191.22) v1(209.23,189.02) v1(209.23,186.57) v1(209.49,183.41) v1(209.49,179.96) v1(209.49,175.56) v1(209.49,169.95) v1(209.49,166.5) v1(209.49,164.3) v1(209.49,162.1) v1(209.49,159.65) v1(209.49,156.48) v1(209.49,153.03) v1(209.49,150.83) v1(209.49,148.63) v1(209.49,146.18) v1(211.52,292.01) v1(211.52,276.77) v1(211.52,271.69) v1(216.6,220.89) v1(216.6,210.73) v1(221.21,277.98) v1(221.21,270.66) v1(221.68,220.89) v1(221.68,210.73) v1(221.68,159.93) v1(226.76,154.85) v1(231.84,149.77) v1(231.84,144.69) v1(231.84,139.61) v1(235.85,296.61) v1(235.85,288.61) v1(236.32,221.9) v1(236.32,161.9) v1(236.92,149.77) v1(236.92,144.69) v1(236.92,139.61) v1(238.3,296.61) v1(238.3,288.61) v1(240.5,296.61) v1(240.5,288.61) v1(242,276.77) v1(242,149.77) v1(242.7,296.61) v1(242.7,288.61) v1(246.15,296.61) v1(246.15,288.61) v1(247.08,281.85) v1(247.08,276.77) v1(247.78,140.14) v1(247.78,132.14) v1(249.15,296.86) v1(249.15,288.86) v1(250.23,140.14) v1(250.23,132.14) v1(250.34,252.59) v1(252.16,281.85) v1(252.16,276.77) v1(252.16,149.77) v1(252.43,140.14) v1(252.43,132.14) v1(252.6,296.86) v1(252.6,288.86) v1(254.61,207.66) v1(254.63,140.14) v1(254.63,132.14) v1(254.8,296.86) v1(254.8,288.86) v1(257,296.86) v1(257,288.86) v1(257.24,276.77) v1(257.24,215.81) v1(257.24,154.85) v1(257.24,149.77) v1(257.99,186.67) v1(258.08,140.14) v1(258.08,132.14) v1(259.45,296.86) v1(259.45,288.86) v1(260.99,143.19) v1(260.99,135.19) v1(262.36,296.86) v1(262.36,288.86) v1(262.32,154.85) v1(263.44,143.19) v1(263.44,135.19) v1(264.29,280.1) v1(264.29,272.1) v1(265.64,143.19) v1(265.64,135.19) v1(265.81,296.86) v1(265.81,288.86) v1(266.74,280.1) v1(266.74,272.1) v1(267.4,154.85) v1(267.84,143.19) v1(267.84,135.19) v1(268.01,296.86) v1(268.01,288.86) v1(268.94,280.1) v1(268.94,272.1) v1(270.21,296.86) v1(270.21,288.86) v1(271.14,280.1) v1(271.14,272.1) v1(271.29,143.19) v1(271.29,135.19) v1(272.66,296.86) v1(272.66,288.86) v1(273.95,155.38) v1(273.95,147.38) v1(274.59,280.1) v1(274.59,272.1) v1(275.82,296.86) v1(275.82,288.86) v1(276.4,155.38) v1(276.4,147.38) v1(277.56,236.13) v1(277.56,175.17) v1(278.6,155.38) v1(278.6,147.38) v1(279.27,296.86) v1(279.27,288.86) v1(280.8,155.38) v1(280.8,147.38) v1(281.47,288.86) v1(282.64,261.53) v1(282.64,241.21) v1(282.64,236.13) v1(282.64,231.05) v1(282.64,225.97) v1(282.64,215.81) v1(282.64,210.73) v1(282.64,205.65) v1(282.64,180.25) v1(282.64,175.17) v1(282.64,170.09) v1(282.64,165.01) v1(283.67,296.86) v1(283.67,288.86) v1(284.25,155.38) v1(284.25,147.38) v1(284.36,280.1) v1(284.36,272.1) v1(286.12,288.86) v1(286.81,280.1) v1(286.81,272.1) v1(287.72,261.53) v1(287.72,256.45) v1(287.72,251.37) v1(287.72,246.29) v1(287.72,241.21) v1(287.72,236.13) v1(287.72,231.05) v1(287.72,225.97) v1(287.72,215.81) v1(287.72,205.65) v1(289.01,280.1) v1(289.01,272.1) v1(289.29,296.86) v1(289.29,288.86) v1(289.31,130.81) v1(291.21,280.1) v1(291.21,272.1) v1(292.74,296.86) v1(292.74,288.86) v1(292.8,266.61) v1(292.8,261.53) v1(292.8,256.45) v1(292.8,225.97) v1(292.8,220.89) v1(292.8,215.81) v1(292.8,139.61) v1(294.66,280.1) v1(294.66,272.1) v1(294.94,296.86) v1(294.94,288.86) v1(297.14,296.86) v1(297.14,288.86) v1(297.88,261.53) v1(297.88,256.45) v1(297.88,220.89) v1(297.88,215.81) v1(297.88,210.73) v1(297.88,205.65) v1(297.88,200.57) v1(297.88,165.01) v1(297.88,159.93) v1(297.88,154.85) v1(297.88,149.77) v1(297.88,144.69) v1(297.88,139.61) v1(299.22,130.81) v1(299.59,296.86) v1(299.59,288.86) v1(301.21,277.98) v1(301.21,270.66) v1(302.49,296.86) v1(302.49,288.86) v1(302.96,210.73) v1(303.26,152.34) v1(303.26,144.34) v1(303.26,139.64) v1(303.26,131.64) v1(305.94,296.86) v1(305.94,288.86) v1(306.71,152.34) v1(306.71,144.34) v1(306.71,139.64) v1(306.71,131.64) v1(308.14,288.86) v1(308.91,152.34) v1(308.91,144.34) v1(308.91,139.64) v1(308.91,131.64) v1(310.34,296.86) v1(310.34,288.86) v1(311.11,152.34) v1(311.11,144.34) v1(311.11,139.64) v1(311.11,131.64) v1(312.79,288.86) v1(313.56,152.34) v1(313.56,144.34) v1(313.56,139.64) v1(313.56,131.64) v1(315.7,296.86) v1(315.7,288.86) v1(316.32,221.9) v1(316.32,161.9) v1(316.97,139.64) v1(316.97,131.64) v1(318.2,281.85) v1(319.15,296.86) v1(319.15,288.86) v1(320.42,139.64) v1(320.42,131.64) v1(321.35,296.86) v1(321.35,288.86) v1(322.62,139.64) v1(322.62,131.64) v1(323.28,149.77) v1(323.55,296.86) v1(323.55,288.86) v1(324.82,139.64) v1(324.82,131.64) v1(326,296.86) v1(326,288.86) v1(327.27,139.64) v1(327.27,131.64) v1(328.36,281.85) v1(328.36,149.77) v1(329.16,296.86) v1(329.16,288.86) v1(330.63,252.59) v1(330.63,192.59) v1(332.61,296.86) v1(332.61,288.86) v1(333.44,149.77) v1(333.44,144.69) v1(334.61,267.66) v1(334.61,207.66) v1(334.81,296.86) v1(334.81,288.86) v1(337.01,296.86) v1(337.01,288.86) v1(337.99,246.67) v1(337.99,186.67) v1(338.52,149.77) v1(338.52,144.69) v1(339.46,296.86) v1(339.46,288.86) v1(342.63,296.86) v1(342.63,288.86) v1(343.6,281.85) v1(343.6,154.85) v1(343.6,149.77) v1(346.08,296.86) v1(346.08,288.86) v1(346.27,139.72) v1(346.27,136.27) v1(346.27,134.07) v1(346.27,131.87) v1(346.27,129.42) v1(348.28,296.86) v1(348.28,288.86) v1(348.68,154.85) v1(350.48,296.86) v1(350.48,288.86) v1(352.93,296.86) v1(352.93,288.86) v1(353.76,154.85) v1(354.27,139.72) v1(354.27,136.27) v1(354.27,134.07) v1(354.27,131.87) v1(354.27,129.42) v1(358.84,271.69) v1(358.84,236.13) v1(358.84,210.73) v1(358.84,175.17) v1(363.92,220.89) v1(368.03,265.11) v1(368.03,257.11) v1(368.03,249.11) v1(368.03,241.11) v1(368.03,232.6) v1(368.03,224.6) v1(368.28,297.12) v1(368.28,289.12) v1(368.28,281.11) v1(368.28,273.11) v1(369,210.73) v1(371.48,265.11) v1(371.48,257.11) v1(371.48,249.11) v1(371.48,241.11) v1(371.48,232.6) v1(371.48,224.6) v1(371.73,297.12) v1(371.73,289.12) v1(371.73,281.11) v1(371.73,273.11) v1(373.68,265.11) v1(373.68,257.11) v1(373.68,249.11) v1(373.68,241.11) v1(373.68,232.6) v1(373.68,224.6) v1(373.87,188.15) v1(373.87,180.15) v1(373.87,171.39) v1(373.87,163.39) v1(373.93,297.12) v1(373.93,289.12) v1(373.93,281.11) v1(373.93,273.11) v1(374.88,217.11) v1(374.88,209.11) v1(375.73,203.73) v1(375.73,200.28) v1(375.73,198.08) v1(375.73,195.88) v1(375.73,193.43) v1(375.88,265.11) v1(375.88,257.11) v1(375.88,249.11) v1(375.88,241.11) v1(375.88,232.6) v1(375.88,224.6) v1(376.13,297.12) v1(376.13,289.12) v1(376.13,281.11) v1(376.13,273.11) v1(377.32,188.15) v1(377.32,180.15) v1(377.32,171.39) v1(377.32,163.39) v1(378.33,265.11) v1(378.33,257.11) v1(378.33,249.11) v1(378.33,241.11) v1(378.33,232.6) v1(378.33,224.6) v1(378.33,217.11) v1(378.33,209.11) v1(378.58,297.12) v1(378.58,289.12) v1(378.58,281.11) v1(378.58,273.11) v1(379.52,188.15) v1(379.52,180.15) v1(379.52,171.39) v1(379.52,163.39) v1(380.53,217.11) v1(380.53,209.11) v1(381.74,297.12) v1(381.74,289.12) v1(381.74,281.11) v1(381.74,273.11) v1(381.74,265.11) v1(381.74,257.11) v1(381.74,249.11) v1(381.74,241.11) v1(381.74,232.85) v1(381.74,224.85) v1(381.72,188.15) v1(381.72,180.15) v1(381.72,171.39) v1(381.72,163.39) v1(382.73,217.11) v1(382.73,209.11) v1(383.01,139.89) v1(383.01,131.89) v1(383.73,203.73) v1(383.73,200.28) v1(383.73,198.08) v1(383.73,195.88) v1(383.73,193.43) v1(384.17,188.15) v1(384.17,180.15) v1(384.17,171.39) v1(384.17,163.39) v1(385.19,297.12) v1(385.19,289.12) v1(385.19,281.11) v1(385.19,273.11) v1(385.19,265.11) v1(385.19,257.11) v1(385.19,249.11) v1(385.19,241.11) v1(385.19,232.85) v1(385.19,224.85) v1(385.18,217.11) v1(385.18,209.11) v1(386.46,139.89) v1(386.46,131.89) v1(387.08,188.15) v1(387.08,180.15) v1(387.08,171.64) v1(387.08,163.64) v1(387.08,154.88) v1(387.08,146.88) v1(387.39,297.12) v1(387.39,289.12) v1(387.39,281.11) v1(387.39,273.11) v1(387.39,265.11) v1(387.39,257.11) v1(387.39,249.11) v1(387.39,241.11) v1(387.39,232.85) v1(387.39,224.85) v1(388.35,217.36) v1(388.35,209.36) v1(388.66,139.89) v1(388.66,131.89) v1(389.59,297.12) v1(389.59,289.12) v1(389.59,281.11) v1(389.59,273.11) v1(389.59,265.11) v1(389.59,257.11) v1(389.59,249.11) v1(389.59,241.11) v1(389.59,232.85) v1(389.59,224.85) v1(390.53,188.15) v1(390.53,180.15) v1(390.53,171.64) v1(390.53,163.64) v1(390.53,154.88) v1(390.53,146.88) v1(390.86,139.89) v1(390.86,131.89) v1(391.8,217.36) v1(391.8,209.36) v1(392.04,297.12) v1(392.04,289.12) v1(392.04,281.11) v1(392.04,273.11) v1(392.04,265.11) v1(392.04,257.11) v1(392.04,249.11) v1(392.04,241.11) v1(392.04,232.85) v1(392.04,224.85) v1(392.24,203.73) v1(392.24,200.28) v1(392.24,198.08) v1(392.24,195.88) v1(392.24,193.43) v1(392.73,188.15) v1(392.73,180.15) v1(392.73,171.64) v1(392.73,163.64) v1(392.73,154.88) v1(392.73,146.88) v1(393.31,139.89) v1(393.31,131.89) v1(394,217.36) v1(394,209.36) v1(394.93,188.15) v1(394.93,180.15) v1(394.93,171.64) v1(394.93,163.64) v1(394.93,154.88) v1(394.93,146.88) v1(395.2,297.12) v1(395.2,289.12) v1(395.2,281.11) v1(395.2,273.11) v1(395.2,265.37) v1(395.2,257.37) v1(395.2,249.11) v1(395.2,241.11) v1(395.2,233.11) v1(395.2,225.11) v1(396.2,217.36) v1(396.2,209.36) v1(396.22,139.89) v1(396.22,131.89) v1(397.38,188.15) v1(397.38,180.15) v1(397.38,171.64) v1(397.38,163.64) v1(397.38,154.88) v1(397.38,146.88) v1(398.65,297.12) v1(398.65,289.12) v1(398.65,281.11) v1(398.65,273.11) v1(398.65,265.37) v1(398.65,257.37) v1(398.65,249.11) v1(398.65,241.11) v1(398.65,233.11) v1(398.65,225.11) v1(398.65,217.36) v1(398.65,209.36) v1(399.67,139.89) v1(399.67,131.89) v1(400.24,203.73) v1(400.24,200.28) v1(400.24,198.08) v1(400.24,195.88) v1(400.24,193.43) v1(400.54,188.15) v1(400.54,180.15) v1(400.54,171.64) v1(400.54,163.64) v1(400.85,297.12) v1(400.85,289.12) v1(400.85,281.11) v1(400.85,273.11) v1(400.85,265.37) v1(400.85,257.37) v1(400.85,249.11) v1(400.85,241.11) v1(400.85,233.11) v1(400.85,225.11) v1(400.79,154.88) v1(400.79,146.88) v1(401.87,139.89) v1(401.87,131.89) v1(402.06,217.61) v1(402.06,209.61) v1(403.05,297.12) v1(403.05,289.12) v1(403.05,281.11) v1(403.05,273.11) v1(403.05,265.37) v1(403.05,257.37) v1(403.05,249.11) v1(403.05,241.11) v1(403.05,233.11) v1(403.05,225.11) v1(403.99,188.15) v1(403.99,180.15) v1(403.99,171.64) v1(403.99,163.64) v1(404.07,139.89) v1(404.07,131.89) v1(404.24,154.88) v1(404.24,146.88) v1(405.5,297.12) v1(405.5,289.12) v1(405.5,281.11) v1(405.5,273.11) v1(405.5,265.37) v1(405.5,257.37) v1(405.5,249.11) v1(405.5,241.11) v1(405.5,233.11) v1(405.5,225.11) v1(405.51,217.61) v1(405.51,209.61) v1(406.19,188.15) v1(406.19,180.15) v1(406.19,171.64) v1(406.19,163.64) v1(406.44,154.88) v1(406.44,146.88) v1(406.52,139.89) v1(406.52,131.89) v1(407.71,217.61) v1(407.71,209.61) v1(408.39,188.15) v1(408.39,180.15) v1(408.39,171.64) v1(408.39,163.64) v1(408.64,154.88) v1(408.64,146.88) v1(408.92,265.37) v1(408.92,257.37) v1(409.17,297.12) v1(409.17,289.12) v1(409.17,281.37) v1(409.17,273.37) v1(409.17,249.11) v1(409.17,241.11) v1(409.43,139.89) v1(409.43,131.89) v1(409.64,200.57) v1(409.91,217.61) v1(409.91,209.61) v1(410.84,188.15) v1(410.84,180.15) v1(410.84,171.64) v1(410.84,163.64) v1(411.09,154.88) v1(411.09,146.88) v1(412.37,265.37) v1(412.37,257.37) v1(412.36,217.61) v1(412.36,209.61) v1(412.62,297.12) v1(412.62,289.12) v1(412.62,281.37) v1(412.62,273.37) v1(412.62,249.11) v1(412.62,241.11) v1(412.88,139.89) v1(412.88,131.89) v1(413.75,171.64) v1(413.75,163.64) v1(414.25,154.88) v1(414.25,146.88) v1(414.57,265.37) v1(414.57,257.37) v1(414.72,231.05) v1(414.72,225.97) v1(414.72,200.57) v1(414.82,297.12) v1(414.82,289.12) v1(414.82,281.37) v1(414.82,273.37) v1(414.82,249.11) v1(414.82,241.11) v1(415.08,139.89) v1(415.08,131.89) v1(415.61,190.27) v1(415.61,186.82) v1(415.61,184.62) v1(415.61,182.42) v1(415.61,179.97) v1(416.77,257.37) v1(417.02,249.11) v1(417.02,241.11) v1(417.2,171.64) v1(417.2,163.64) v1(417.28,139.89) v1(417.28,131.89) v1(417.7,154.88) v1(417.7,146.88) v1(419.22,257.37) v1(419.47,249.11) v1(419.47,241.11) v1(419.4,171.64) v1(419.4,163.64) v1(419.73,139.89) v1(419.73,131.89) v1(419.8,292.01) v1(419.8,276.77) v1(419.8,266.61) v1(419.9,154.88) v1(419.9,146.88) v1(421.6,171.64) v1(421.6,163.64) v1(422.1,154.88) v1(422.1,146.88) v1(423.61,190.27) v1(423.61,186.82) v1(423.61,184.62) v1(423.61,182.42) v1(423.61,179.97) v1(424.05,171.64) v1(424.05,163.64) v1(424.55,154.88) v1(424.55,146.88) v1(424.88,292.01) v1(424.88,286.93) v1(424.88,281.85) v1(424.88,276.77) v1(424.88,271.69) v1(424.88,266.61) v1(424.88,261.53) v1(424.88,256.45) v1(424.88,251.37) v1(424.88,246.29) v1(424.88,241.21) v1(450.28,159.93) v1(450.28,154.85) v1(452.68,233.88) v1(452.68,190.45) v1(452.68,145.54) v1(452.68,141.73) v1(454.61,137.92) v1(454.61,134.11) v1(454.61,130.3) v1(455.36,159.93) v1(455.36,154.85) v1(460.44,159.93) v1(460.44,154.85) v1(460.44,149.77) v1(460.44,144.69) v1(460.44,139.61) v1(465.52,286.93) v1(465.52,281.85) v1(465.52,205.65) v1(465.52,200.57) v1(465.52,159.93) v1(465.52,154.85) v1(465.52,149.77) v1(465.52,144.69) v1(465.52,139.61) v1(467.62,235.71) v1(467.62,192.28) v1(470.6,200.57) v1(470.6,154.85) v1(470.6,149.77) v1(470.6,144.69) v1(470.6,139.61) v1(475.68,251.37) v1(475.68,154.85) v1(475.68,149.77) v1(475.68,144.69) v1(475.68,139.61) v1(475.89,204.98) v1(475.89,161.55) v1(475.99,218.59) v1(475.99,175.15) v1(480.76,251.37) v1(480.76,154.85) v1(480.76,149.77) v1(480.76,144.69) v1(480.76,139.61) v1(485.84,251.37) v1(485.84,154.85) v1(485.84,149.77) v1(485.84,144.69) v1(485.84,139.61) v1(486.8,226.62) v1(486.8,212.91) v1(486.8,183.19) v1(486.8,169.47) v1(490.92,251.37) v1(490.92,246.29) v1(490.92,241.21) v1(490.92,236.13) v1(490.92,220.89) v1(490.92,205.65) v1(490.92,200.57) v1(490.92,195.49) v1(490.92,159.93) v1(490.92,154.85) v1(490.92,149.77) v1(490.92,144.69) v1(490.92,139.61) v1(496,251.37) v1(496,246.29) v1(496,241.21) v1(496,236.13) v1(496,220.89) v1(496,210.73) v1(496,195.49) v1(496,190.41) v1(496,180.25) v1(496,175.17) v1(496,165.01) v1(496,159.93) v1(496,154.85) v1(496,149.77) v1(496,144.69) v1(496,139.61) v1(501.08,251.37) v1(501.08,246.29) v1(501.08,241.21) v1(501.08,236.13) v1(501.08,231.05) v1(501.08,225.97) v1(501.08,220.89) v1(501.08,215.81) v1(501.08,210.73) v1(501.08,195.49) v1(501.08,190.41) v1(501.08,185.33) v1(501.08,180.25) v1(501.08,175.17) v1(501.08,170.09) v1(501.08,165.01) v1(501.08,159.93) v1(501.08,154.85) v1(501.08,149.77) v1(501.08,144.69) v1(501.08,139.61) v1(506.16,251.37) v1(506.16,246.29) v1(506.16,241.21) v1(506.16,236.13) v1(506.16,231.05) v1(506.16,225.97) v1(506.16,220.89) v1(506.16,215.81) v1(506.16,210.73) v1(506.16,195.49) v1(506.16,190.41) v1(506.16,185.33) v1(506.16,180.25) v1(506.16,175.17) v1(506.16,170.09) v1(506.16,165.01) v1(506.16,159.93) v1(506.16,154.85) v1(506.16,149.77) v1(506.16,144.69) v1(506.16,139.61) v1(511.24,251.37) v1(511.24,246.29) v1(511.24,220.89) v1(511.24,215.81) v1(511.24,210.73) v1(511.24,195.49) v1(511.24,190.41) v1(511.24,185.33) v1(511.24,180.25) v1(511.24,175.17) v1(511.24,170.09) v1(511.24,165.01) v1(511.24,159.93) v1(511.24,154.85) v1(511.24,149.77) v1(511.24,144.69) v1(511.24,139.61) v1(514.05,238.76) v1(514.05,234.95) v1(514.05,231.14) v1(514.05,227.33) v1(516.32,251.37) v1(516.32,246.29) v1(516.32,220.89) v1(516.32,215.81) v1(516.32,210.73) v1(516.32,195.49) v1(516.32,190.41) v1(516.32,185.33) v1(516.32,180.25) v1(516.32,175.17) v1(516.32,170.09) v1(516.32,165.01) v1(516.32,159.93) v1(516.32,154.85) v1(516.32,149.77) v1(516.32,144.69) v1(516.32,139.61) v1(521.4,251.37) v1(521.4,246.29) v1(521.4,241.21) v1(521.4,236.13) v1(521.4,231.05) v1(521.4,225.97) v1(521.4,220.89) v1(521.4,215.81) v1(521.4,210.73) v1(521.4,195.49) v1(521.4,190.41) v1(521.4,185.33) v1(521.4,180.25) v1(521.4,175.17) v1(521.4,170.09) v1(521.4,165.01) v1(521.4,159.93) v1(521.4,154.85) v1(521.4,149.77) v1(521.4,144.69) v1(521.4,139.61) v1(526.48,251.37) v1(526.48,246.29) v1(526.48,241.21) v1(526.48,236.13) v1(526.48,231.05) v1(526.48,225.97) v1(526.48,220.89) v1(526.48,215.81) v1(526.48,210.73) v1(526.48,205.65) v1(526.48,200.57) v1(526.48,195.49) v1(526.48,190.41) v1(526.48,185.33) v1(526.48,180.25) v1(526.48,175.17) v1(526.48,170.09) v1(526.48,165.01) v1(526.48,159.93) v1(526.48,154.85) v1(526.48,149.77) v1(526.48,144.69) v1(526.48,139.61) v1(531.56,292.01) v1(531.56,286.93) v1(531.56,281.85) v1(531.56,276.77) v1(531.56,271.69) v1(531.56,266.61) v1(531.56,261.53) v1(531.56,256.45) v1(531.56,251.37) v1(531.56,246.29) v1(531.56,241.21) v1(531.56,236.13) v1(531.56,231.05) v1(531.56,225.97) v1(531.56,220.89) v1(531.56,215.81) v1(531.56,210.73) v1(531.56,205.65) v1(531.56,200.57) v1(531.56,195.49) v1(531.56,190.41) v1(531.56,185.33) v1(531.56,180.25) v1(531.56,175.17) v1(531.56,165.01) v1(531.56,159.93) v1(531.56,154.85) v1(531.56,149.77) v1(531.56,144.69) v1(531.56,139.61) v1(536.64,292.01) v1(536.64,286.93) v1(536.64,281.85) v1(536.64,276.77) v1(536.64,271.69) v1(536.64,266.61) v1(536.64,261.53) v1(536.64,256.45) v1(536.64,251.37) v1(536.64,246.29) v1(536.64,241.21) v1(536.64,236.13) v1(536.64,231.05) v1(536.64,225.97) v1(536.64,220.89) v1(536.64,215.81) v1(536.64,210.73) v1(536.64,205.65) v1(536.64,200.57) v1(536.64,195.49) v1(536.64,190.41) v1(536.64,185.33) v1(536.64,180.25) v1(536.64,175.17) v1(536.64,170.09) v1(536.64,159.93) v1(536.64,154.85) v1(536.64,149.77) v1(536.64,144.69) v1(536.64,139.61) v1(541.72,292.01) v1(541.72,286.93) v1(541.72,281.85) v1(541.72,276.77) v1(541.72,271.69) v1(541.72,266.61) v1(541.72,261.53) v1(541.72,256.45) v1(541.72,251.37) v1(541.72,246.29) v1(541.72,241.21) v1(541.72,236.13) v1(541.72,231.05) v1(541.72,225.97) v1(541.72,220.89) v1(541.72,215.81) v1(541.72,210.73) v1(541.72,205.65) v1(541.72,200.57) v1(541.72,195.49) v1(541.72,190.41) v1(541.72,185.33) v1(541.72,180.25) v1(541.72,175.17) v1(541.72,159.93) v1(541.72,154.85) v1(541.72,149.77) v1(541.72,144.69) v1(541.72,139.61) v1(546.8,292.01) v1(546.8,286.93) v1(546.8,281.85) v1(546.8,276.77) v1(546.8,271.69) v1(546.8,266.61) v1(546.8,261.53) v1(546.8,256.45) v1(546.8,251.37) v1(546.8,246.29) v1(546.8,241.21) v1(546.8,236.13) v1(546.8,231.05) v1(546.8,225.97) v1(546.8,220.89) v1(546.8,215.81) v1(546.8,210.73) v1(546.8,205.65) v1(546.8,200.57) v1(546.8,195.49) v1(546.8,190.41) v1(546.8,185.33) v1(546.8,180.25) v1(546.8,175.17) v1(546.8,165.01) v1(546.8,159.93) v1(546.8,154.85) v1(546.8,149.77) v1(546.8,144.69) v1(546.8,139.61) v1(551.88,292.01) v1(551.88,286.93) v1(551.88,281.85) v1(551.88,276.77) v1(551.88,271.69) v1(551.88,266.61) v1(551.88,261.53) v1(551.88,256.45) v1(551.88,251.37) v1(551.88,246.29) v1(551.88,241.21) v1(551.88,236.13) v1(551.88,231.05) v1(551.88,225.97) v1(551.88,220.89) v1(551.88,215.81) v1(551.88,210.73) v1(551.88,205.65) v1(551.88,200.57) v1(551.88,195.49) v1(551.88,190.41) v1(551.88,185.33) v1(551.88,180.25) v1(551.88,175.17) v1(551.88,165.01) v1(551.88,159.93) v1(551.88,154.85) v1(551.88,149.77) v1(551.88,144.69) v1(551.88,139.61) v1(556.96,292.01) v1(556.96,286.93) v1(556.96,281.85) v1(556.96,276.77) v1(556.96,271.69) v1(556.96,266.61) v1(556.96,261.53) v1(556.96,256.45) v1(556.96,251.37) v1(556.96,246.29) v1(556.96,241.21) v1(556.96,236.13) v1(556.96,231.05) v1(556.96,225.97) v1(556.96,220.89) v1(556.96,215.81) v1(556.96,210.73) v1(556.96,205.65) v1(556.96,200.57) v1(556.96,195.49) v1(556.96,190.41) v1(556.96,185.33) v1(556.96,180.25) v1(556.96,175.17) v1(556.96,165.01) v1(556.96,159.93) v1(556.96,154.85) v1(556.96,149.77) v1(556.96,144.69) v1(556.96,139.61) v1(562.04,292.01) v1(562.04,286.93) v1(562.04,281.85) v1(562.04,276.77) v1(562.04,271.69) v1(562.04,266.61) v1(562.04,261.53) v1(562.04,256.45) v1(562.04,251.37) v1(562.04,246.29) v1(562.04,241.21) v1(562.04,236.13) v1(562.04,231.05) v1(562.04,225.97) v1(562.04,220.89) v1(562.04,215.81) v1(562.04,210.73) v1(562.04,205.65) v1(562.04,200.57) v1(562.04,195.49) v1(562.04,190.41) v1(562.04,185.33) v1(562.04,180.25) v1(562.04,175.17) v1(562.04,170.09) v1(562.04,165.01) v1(562.04,159.93) v1(562.04,154.85) v1(562.04,149.77) v1(562.04,144.69) v1(562.04,139.61)
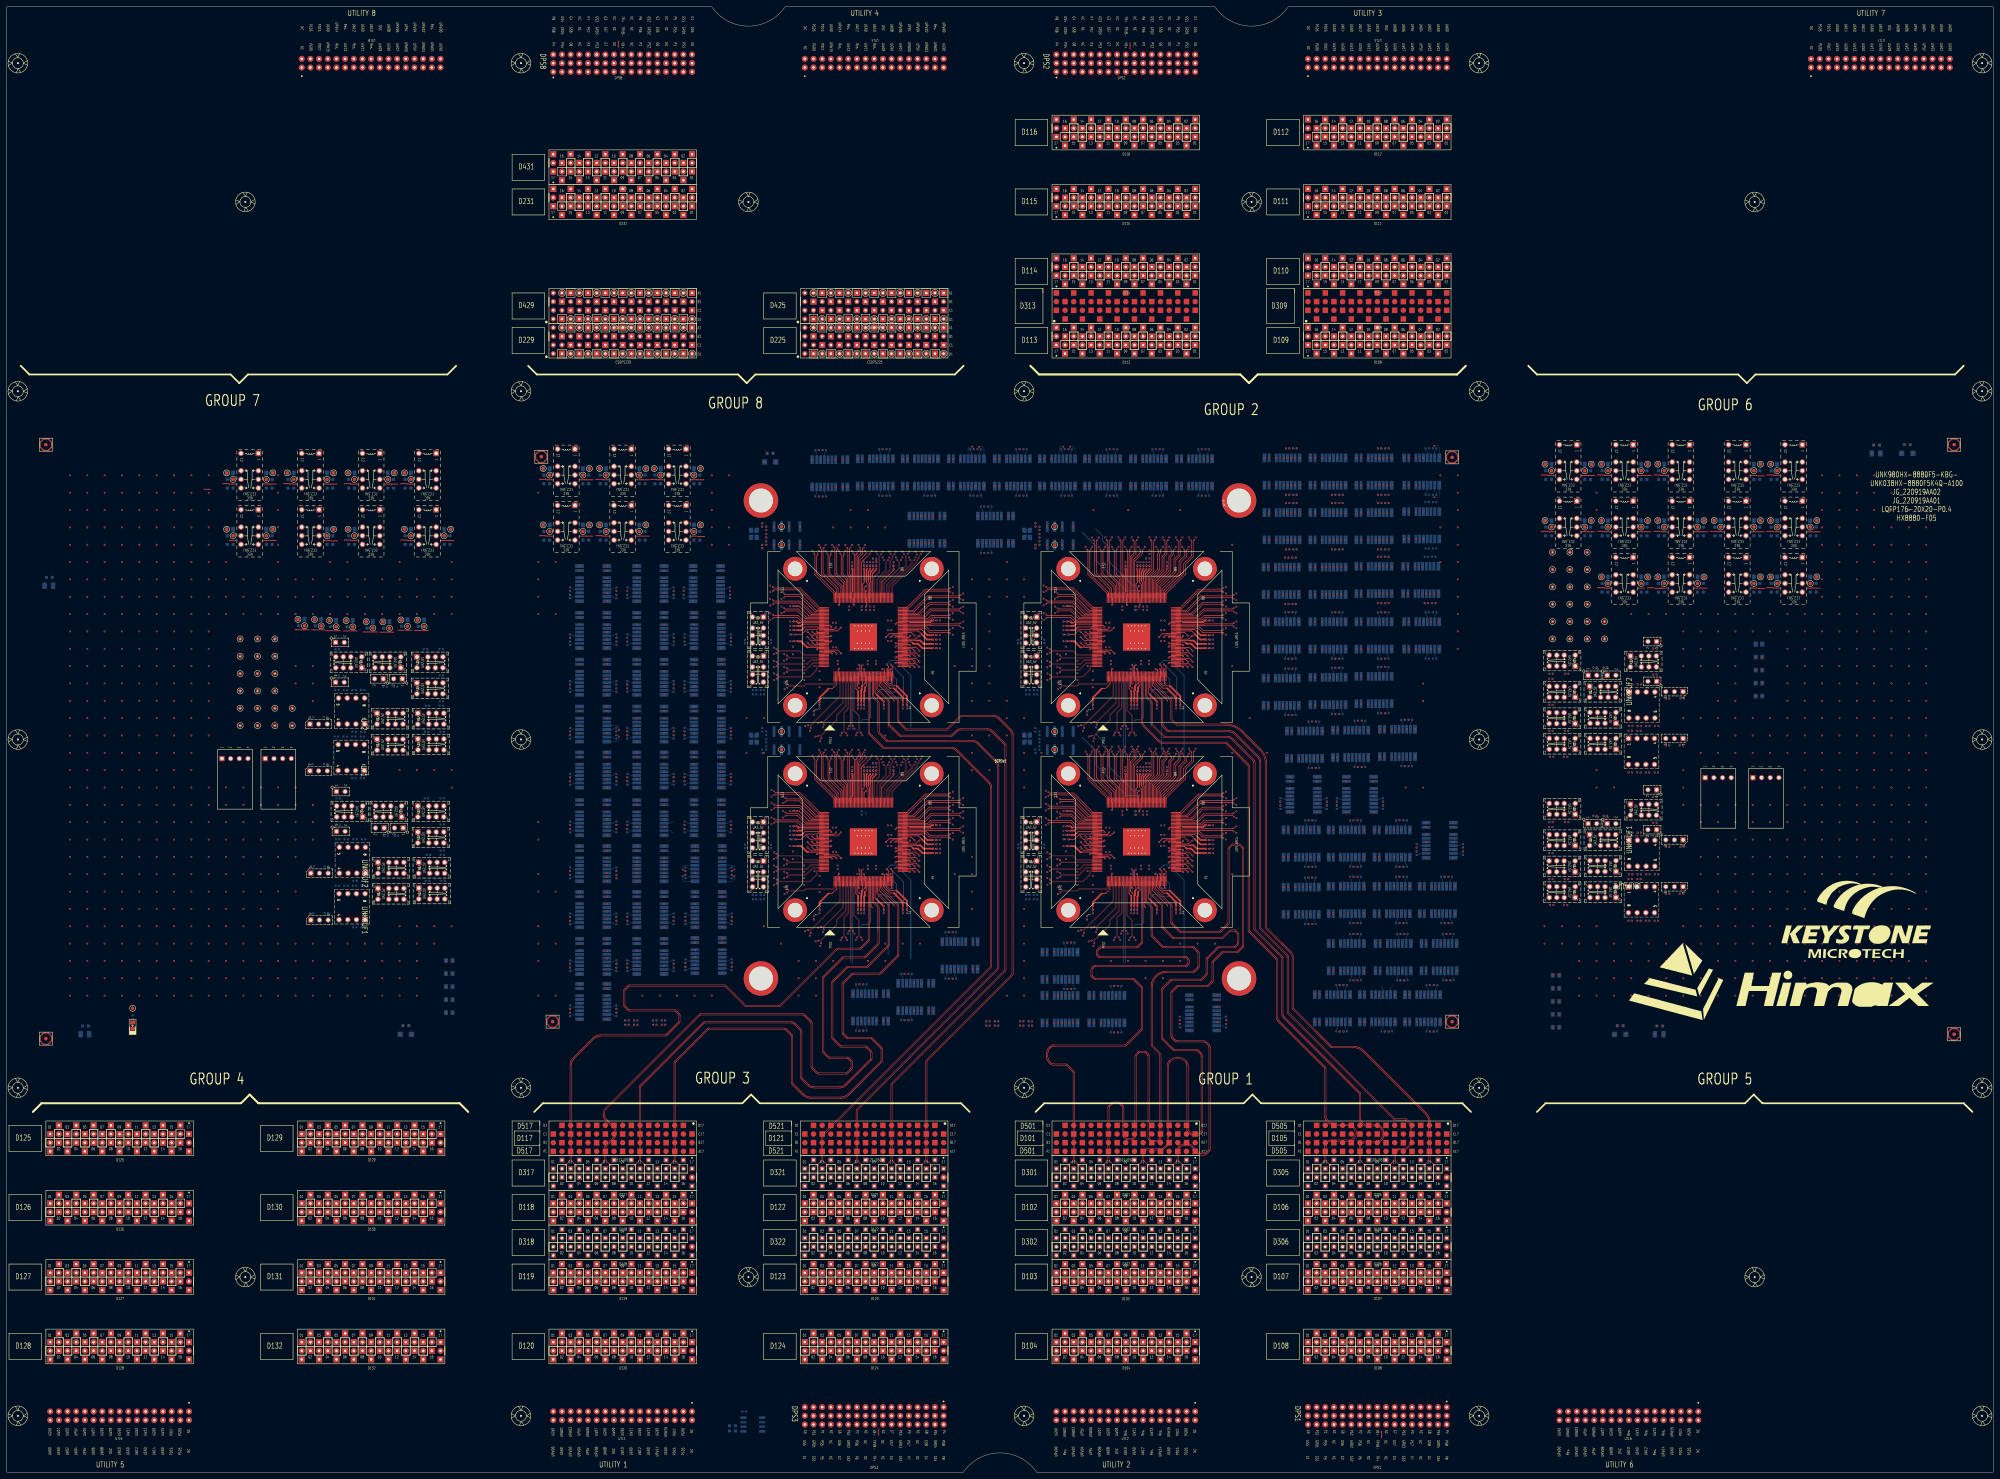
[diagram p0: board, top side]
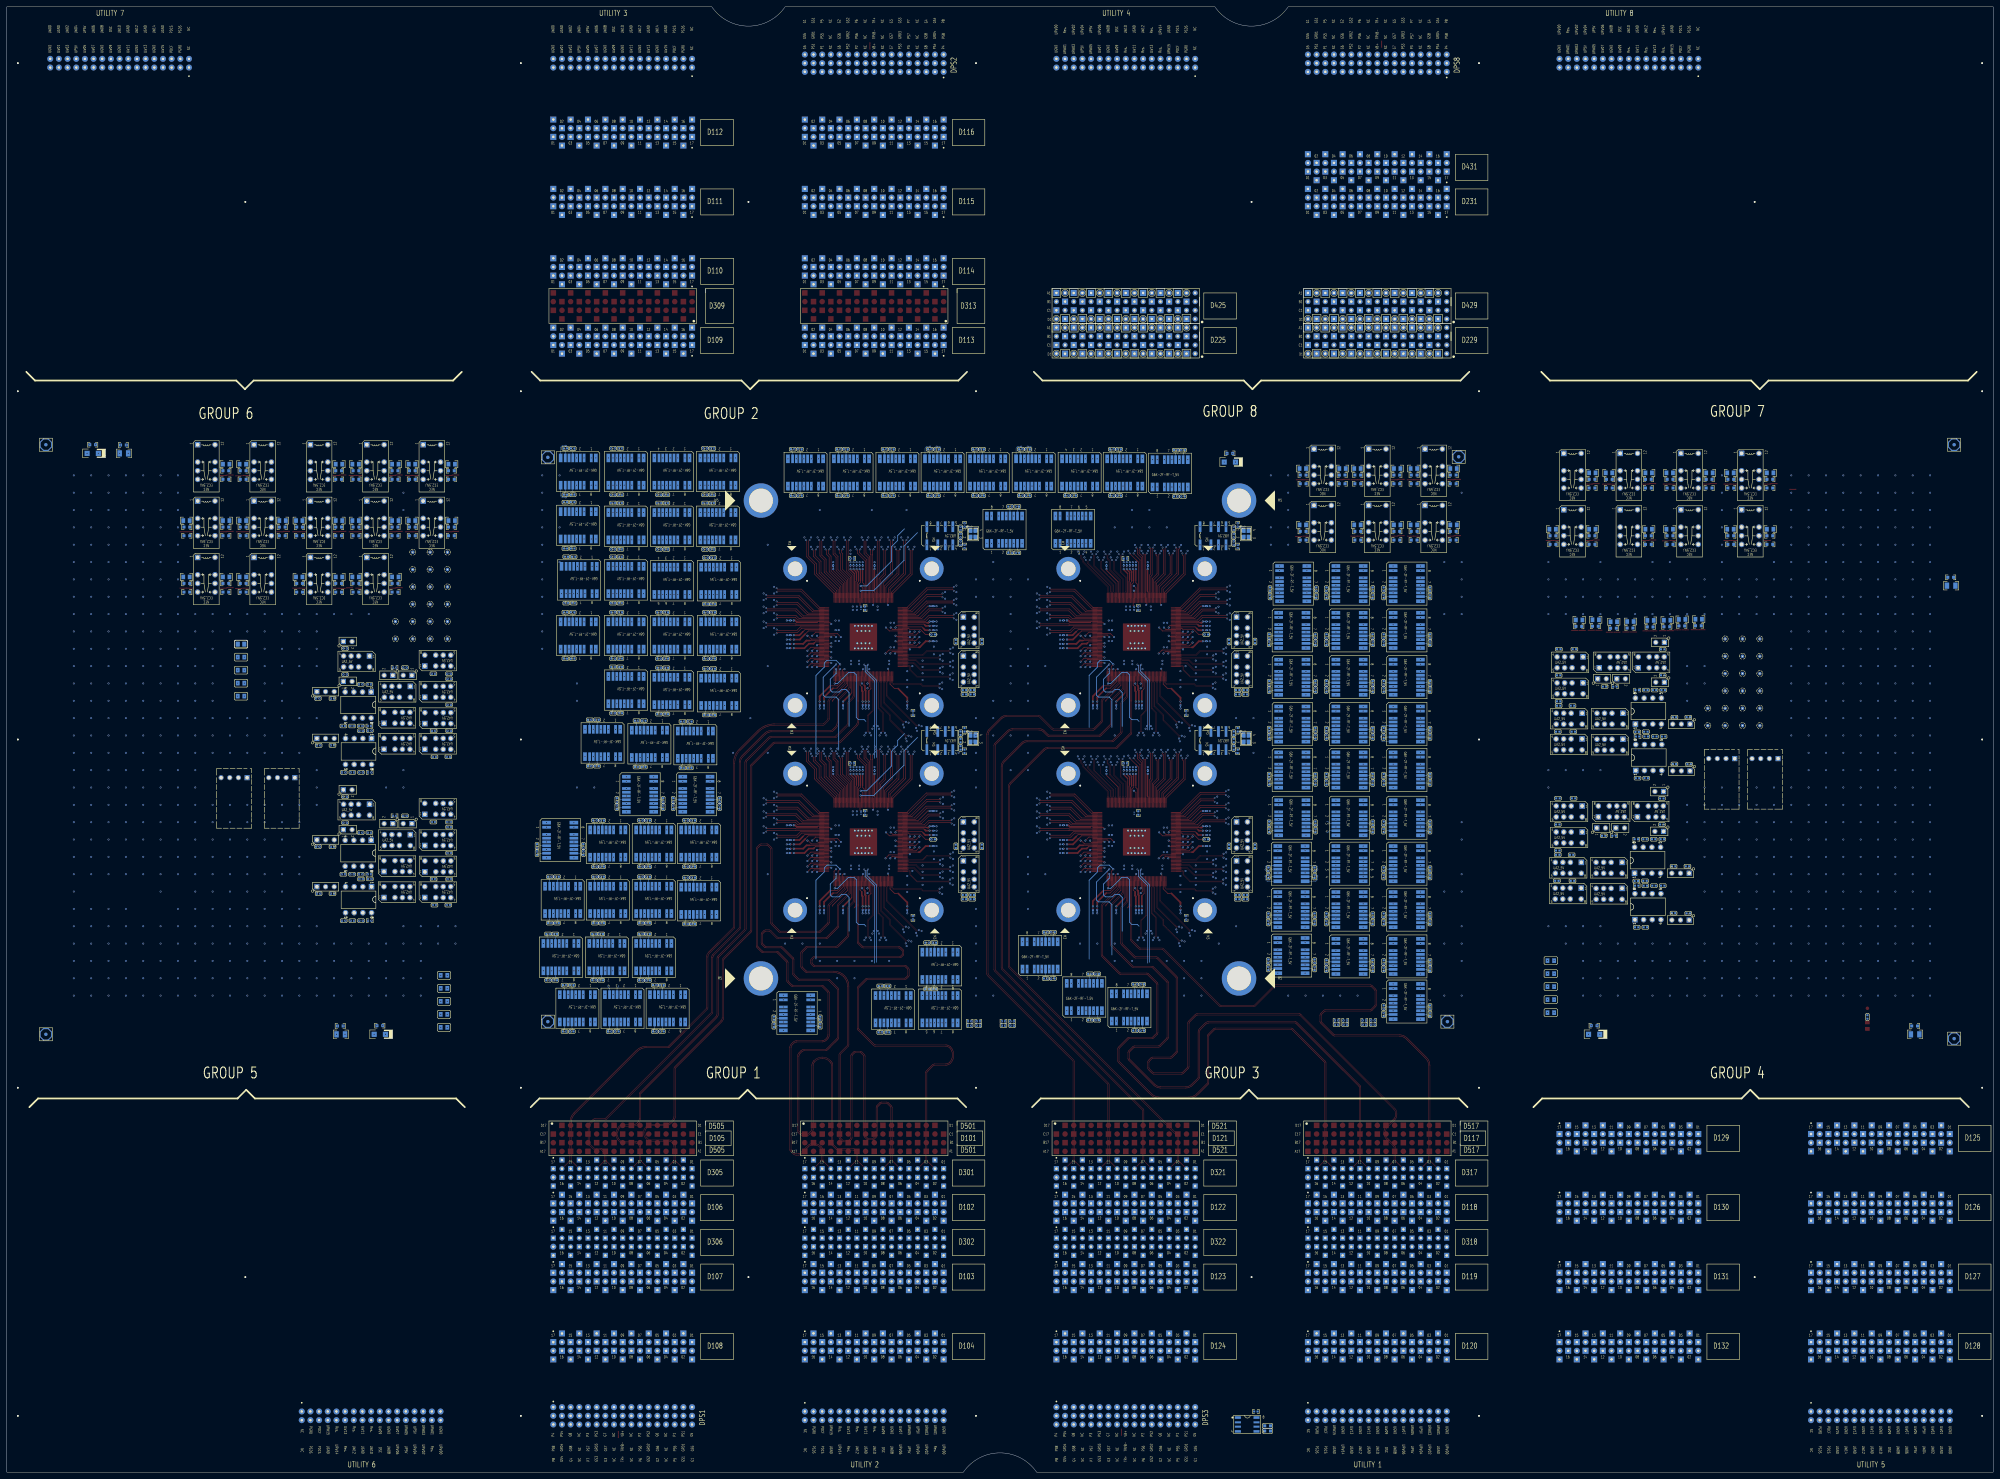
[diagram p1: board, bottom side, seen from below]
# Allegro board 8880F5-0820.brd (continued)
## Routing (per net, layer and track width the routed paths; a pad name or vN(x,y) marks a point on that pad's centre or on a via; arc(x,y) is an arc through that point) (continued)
D10409: length 413.5
  TOP w0.086: SITE4.172 317.68,177.63 317.6,177.71 315.46,177.71 314.38,176.63 305.85,176.63 v1(305.39,176.18)
  L03_SIGNAL w0.071: v1(382.29,174.18) 381.82,173.71 381.82,172.79 381.31,172.28 378.13,172.28 377.03,173.38 356.25,173.38 355.47,174.17 323.36,174.17 320.87,176.65 305.87,176.65 v1(305.39,176.18)
  L05_SIGNAL w0.071: v1(382.29,174.18) 381.82,173.71 381.82,172.37 378.79,169.34 378.79,132.16 359.98,113.36 359.98,16.23 352.84,9.08 284.12,9.08 280.97,12.23 280.97,20.3 283.52,22.85 324.32,22.85 329.61,28.14 329.61,33.61 D104.09
D10410: length 457
  TOP w0.086: v1(325.68,156.6) 325.23,157.05 325.23,162.4 326.55,163.72 326.55,171.4 326.63,171.48 SITE4.12
  L03_SIGNAL w0.071: v1(343.47,131.3) 343.94,131.77 344.83,131.77 347.55,129.06 347.55,124.53 351.45,120.62 367.29,120.62 368.44,119.47 368.44,118.16 367.68,117.4 323.11,117.4 322.1,116.38 322.1,115.2 323.46,113.84 416.29,113.84 417.44,112.69 417.44,110.93 416.36,109.85 322.29,109.85 317.73,114.41 317.73,147.84 325.21,155.32 325.21,156.12 v1(325.68,156.6)
  L05_SIGNAL w0.071: D104.10 331.67,39.57 332.45,39.57 333.66,40.79 333.66,44.94 334.43,45.7 343.17,45.7 350.14,52.68 350.14,126.9 345.27,131.77 343.94,131.77 v1(343.47,131.3)
D10411: length 413.5
  TOP w0.086: v1(305.39,177.32) 305.85,176.87 314.29,176.87 315.37,177.95 317.6,177.95 317.68,178.03 SITE4.171
  L03_SIGNAL w0.071: v1(381.15,174.18) 381.62,173.71 381.62,172.87 381.23,172.48 378.22,172.48 377.11,173.58 356.34,173.58 355.55,174.37 323.44,174.37 320.96,176.85 305.87,176.85 v1(305.39,177.32)
  L05_SIGNAL w0.071: v1(381.15,174.18) 381.62,173.71 381.62,172.46 378.59,169.42 378.59,132.24 359.79,113.44 359.79,16.31 352.75,9.28 284.2,9.28 281.17,12.31 281.17,20.22 283.6,22.65 324.41,22.65 329.81,28.05 329.81,33.59 330.31,34.09 331.27,34.09 D104.11
D10412: length 457
  TOP w0.086: v1(324.54,156.6) 324.99,157.05 324.99,162.5 326.31,163.82 326.31,171.4 326.23,171.48 SITE4.11
  L03_SIGNAL w0.071: v1(343.47,132.44) 343.94,131.97 344.91,131.97 347.74,129.14 347.74,124.61 351.54,120.82 367.37,120.82 368.64,119.55 368.64,118.08 367.76,117.2 323.2,117.2 322.3,116.3 322.3,115.28 323.54,114.04 416.38,114.04 417.64,112.77 417.64,110.84 416.45,109.65 322.21,109.65 317.53,114.33 317.53,147.92 325.01,155.41 325.01,156.12 v1(324.54,156.6)
  L05_SIGNAL w0.071: D104.12 333.86,39.52 333.86,39.62 333.86,44.86 334.51,45.5 343.25,45.5 350.34,52.6 350.34,126.98 345.35,131.97 343.94,131.97 v1(343.47,132.44)
D10413: length 457
  TOP w0.086: v1(319.21,158.99) 319.21,159.63 324.95,165.37 324.95,171.4 325.03,171.48 SITE4.8
  L03_SIGNAL w0.071: v1(319.21,158.99) 319.21,159.66 320.01,160.46 320.01,165.28 315.47,169.81 309.28,169.81 304.98,165.51 304.98,161.97 302.17,159.17 285.39,159.17 279.63,164.93 279.63,177.92 278.16,179.39 278.16,206.01 280.96,208.82 298.5,208.82 300.01,210.32 300.01,212.13 298.61,213.52 286.19,213.52 285.42,214.29 285.42,216.28 286.35,217.21 298.7,217.21 304.17,211.73 304.17,204.22 309.02,199.37 315.34,199.37 318.54,202.56 341.26,202.56 345.22,198.6 351.54,198.6 353.76,200.81 360.85,200.81 365.88,195.78 372.46,195.78 v1(372.94,195.31)
  L05_SIGNAL w0.071: v1(372.94,195.31) 372.46,195.78 371.41,195.78 370.92,195.29 370.92,128.97 355.8,113.85 355.8,37.64 346.95,28.79 342.09,28.79 340.18,30.69 340.18,33.2 D104.13
D10414: length 457
  TOP w0.086: v1(318.42,154.92) 318.42,155.56 323.1,160.24 323.1,161.66 325.75,164.32 325.75,171.4 325.83,171.48 SITE4.10
  L03_SIGNAL w0.071: v1(357.06,131.3) 357.53,131.77 358.67,131.77 373.02,117.42 417.75,117.42 421.75,113.41 421.75,111.17 418.1,107.51 324.55,107.51 322.8,105.76 322.8,103.23 324.55,101.47 365.85,101.47 366.68,100.64 366.68,99.32 365.74,98.38 322.16,98.38 315.28,105.27 315.28,152.45 317.75,154.92 v1(318.42,154.92)
  L05_SIGNAL w0.071: D104.14 341.92,39.66 343.07,39.66 343.54,40.13 343.54,41.33 352.39,50.18 352.39,119.85 360,127.46 360,130.7 358.93,131.77 357.53,131.77 v1(357.06,131.3)
D10415: length 457
  TOP w0.086: v1(318.4,159.8) 319.04,159.8 324.71,165.47 324.71,171.4 324.63,171.48 SITE4.7
  L03_SIGNAL w0.071: v1(318.4,159.8) 319.07,159.8 319.81,160.54 319.81,165.19 315.39,169.62 309.36,169.62 305.18,165.43 305.18,161.89 302.26,158.97 285.31,158.97 279.43,164.84 279.43,177.84 277.96,179.31 277.96,206.09 280.88,209.01 298.42,209.01 299.81,210.4 299.81,212.04 298.53,213.32 286.11,213.32 285.22,214.21 285.22,216.36 286.26,217.41 298.78,217.41 304.37,211.81 304.37,204.3 309.11,199.57 315.26,199.57 318.45,202.76 341.34,202.76 345.31,198.8 351.46,198.8 353.67,201.01 360.93,201.01 365.96,195.98 372.46,195.98 v1(372.94,196.45)
  L05_SIGNAL w0.071: v1(372.94,196.45) 372.46,195.98 371.32,195.98 370.72,195.37 370.72,129.05 355.6,113.93 355.6,37.72 346.87,28.99 342.17,28.99 340.38,30.78 340.38,33.52 341.33,34.47 341.81,34.47 D104.15
D10416: length 457
  TOP w0.086: v1(317.61,155.73) 318.25,155.73 322.86,160.34 322.86,161.76 325.51,164.41 325.51,171.4 325.43,171.48 SITE4.9
  L03_SIGNAL w0.071: v1(357.06,132.44) 357.53,131.97 358.75,131.97 373.1,117.61 417.83,117.61 421.95,113.5 421.95,111.08 418.18,107.31 324.63,107.31 322.99,105.68 322.99,103.31 324.64,101.67 365.93,101.67 366.88,100.72 366.88,99.24 365.83,98.19 322.08,98.19 315.08,105.19 315.08,152.53 317.61,155.06 v1(317.61,155.73)
  L05_SIGNAL w0.071: v1(357.06,132.44) 357.53,131.97 359.01,131.97 360.2,130.78 360.2,127.37 352.59,119.77 352.59,50.1 343.74,41.25 343.74,39.9 343.74,39.8 D104.16
D10801: length 457
  TOP w0.086: SITE4.5 323.83,171.48 323.91,171.4 323.91,167.47 315.24,158.8 v1(314.6,158.8)
  L03_SIGNAL w0.071: v1(314.6,158.8) 315.27,158.8 315.63,159.16 315.63,159.74 315.21,160.16 313.47,160.16 309.83,156.51 283.85,156.51 275.45,164.9 275.45,207.53 280.02,212.1 282.14,212.1 283.58,213.54 283.58,215.95 282.87,216.66 268.91,216.66 268.22,217.35 268.22,218.33 268.98,219.09 299.02,219.09 306.01,212.1 310.22,212.1 313.94,208.38 346.21,208.38 347.65,209.82 362.15,209.82 374.51,197.46 383.29,197.46 384.77,195.98 386.05,195.98 v1(386.52,196.45)
  L05_SIGNAL w0.071: v1(386.52,196.45) 387,195.98 387.43,195.98 388.06,195.35 388.06,190.1 385.9,187.94 385.9,112.07 373.28,99.45 373.28,32.53 376.14,29.67 382.76,29.67 383.66,30.57 383.66,33.26 382.97,33.94 382.62,33.94 D108.01
D10802: length 457
  TOP w0.086: v1(330.13,156.61) 329.68,157.05 329.68,161.65 328.15,163.18 328.15,171.4 328.23,171.48 SITE4.16
  L03_SIGNAL w0.071: v1(389.45,195.31) 389.92,195.78 391.23,195.78 392.75,197.3 456.57,197.3 457.83,196.05 457.83,146.08 449.41,137.67 339.51,137.67 329.66,147.52 329.66,156.13 v1(330.13,156.61)
  L05_SIGNAL w0.071: v1(389.45,195.31) 389.92,195.78 390.47,195.78 391.08,195.17 391.08,186.1 387.63,182.64 387.63,110 375.9,98.27 375.9,48.41 379.53,44.78 384.57,44.78 386.56,42.8 386.56,39.69 386.23,39.36 384.8,39.36 D108.02
D10803: length 457
  TOP w0.086: SITE4.6 324.23,171.48 324.15,171.4 324.15,167.37 315.41,158.63 v1(315.41,157.99)
  L03_SIGNAL w0.071: v1(315.41,157.99) 315.41,158.66 315.82,159.08 315.82,159.83 315.3,160.35 313.39,160.35 309.74,156.71 283.93,156.71 275.65,164.99 275.65,207.45 280.1,211.9 282.22,211.9 283.78,213.45 283.78,216.03 282.95,216.86 268.99,216.86 268.42,217.44 268.42,218.25 269.06,218.89 298.93,218.89 305.92,211.9 310.14,211.9 313.86,208.18 346.29,208.18 347.73,209.62 362.07,209.62 374.42,197.26 383.21,197.26 384.69,195.78 386.05,195.78 v1(386.52,195.31)
  L05_SIGNAL w0.071: D108.03 383.86,33.34 383.86,30.49 382.84,29.47 376.06,29.47 373.08,32.45 373.08,99.53 385.7,112.15 385.7,188.02 387.86,190.18 387.86,195.26 387.34,195.78 387,195.78 v1(386.52,195.31)
D10804: length 457
  TOP w0.086: v1(328.99,156.61) 329.45,157.06 329.45,161.55 327.91,163.08 327.91,171.4 327.83,171.48 SITE4.15
  L03_SIGNAL w0.071: v1(389.45,196.45) 389.92,195.98 391.14,195.98 392.67,197.5 456.65,197.5 458.03,196.13 458.03,146 449.49,137.47 339.43,137.47 329.46,147.44 329.46,156.13 v1(328.99,156.61)
  L05_SIGNAL w0.071: v1(389.45,196.45) 389.92,195.98 390.55,195.98 391.28,195.25 391.28,186.01 387.83,182.56 387.83,109.92 376.1,98.19 376.1,48.49 379.61,44.98 384.65,44.98 386.76,42.88 386.76,39.96 D108.04
D10805: length 413.5
  TOP w0.086: SITE4.175 317.68,176.43 317.6,176.35 317.38,176.35 317.01,175.98 317.01,175.08 315.09,173.16 305.91,173.16 v1(305.46,173.61)
  L03_SIGNAL w0.071: v1(305.46,173.61) 305.93,173.14 316.06,173.14 318.09,171.1 326.97,171.1 328.12,172.25 352.2,172.25 355.85,168.6 374.8,168.6 378.93,164.47 378.93,159.63 379.86,158.7 381.16,158.7 381.62,159.16 381.62,160.12 v1(381.15,160.59)
  L05_SIGNAL w0.071: v1(381.15,160.59) 381.62,161.06 381.62,161.53 382.21,162.12 383.15,162.12 383.73,161.54 383.73,113.29 370.11,99.67 370.11,8.39 373.83,4.67 439.34,4.67 440.92,6.25 440.92,10.01 439.55,11.37 398.59,11.37 397.32,12.65 397.32,22.76 393.84,26.23 393.84,33.13 392.62,34.36 392.36,34.36 D108.05
D10806: length 413.5
  TOP w0.086: v1(308.38,178.12) 308.77,178.5 317.6,178.5 317.68,178.43 SITE4.170
  L03_SIGNAL w0.071: v1(395.5,177.36) 395.03,176.88 395.03,175.78 394.42,175.17 390.99,175.17 387.99,178.17 344.11,178.17 343.79,177.84 339.33,177.84 338.59,178.59 308.85,178.59 v1(308.38,178.12)
  L05_SIGNAL w0.071: D108.06 395.77,40.17 395.77,46.89 393.37,49.3 380.79,49.3 378.63,51.46 378.63,89.43 383.33,94.13 392.35,94.13 395.33,97.11 395.33,141.04 396.28,141.99 396.28,166.48 395.46,167.3 392.82,167.3 391.96,166.44 391.96,145.91 392.66,145.21 392.66,102.57 391.89,101.8 390.38,101.8 389.46,102.72 389.46,176.05 393.08,179.67 394.19,179.67 395.03,178.83 395.03,177.83 v1(395.5,177.36)
D10807: length 413.5
  TOP w0.086: SITE4.176 317.68,176.03 317.6,176.11 317.48,176.11 317.25,175.88 317.25,174.98 315.19,172.92 305.91,172.92 v1(305.46,172.46)
  L03_SIGNAL w0.071: v1(305.46,172.46) 305.93,172.94 315.98,172.94 318.01,170.9 327.06,170.9 328.2,172.05 352.12,172.05 355.76,168.4 374.72,168.4 378.73,164.39 378.73,159.55 379.78,158.5 381.24,158.5 381.82,159.07 381.82,160.12 v1(382.29,160.59)
  L05_SIGNAL w0.071: v1(382.29,160.59) 381.82,161.06 381.82,161.45 382.29,161.92 383.07,161.92 383.53,161.46 383.53,113.37 369.91,99.75 369.91,8.31 373.74,4.48 439.42,4.48 441.12,6.17 441.12,10.09 439.64,11.57 398.68,11.57 397.52,12.73 397.52,22.84 394.04,26.32 394.04,33.36 D108.07
D10808: length 413.5
  TOP w0.086: v1(308.38,179.26) 308.9,178.74 317.59,178.74 317.68,178.83 SITE4.169
  L03_SIGNAL w0.071: v1(394.35,177.36) 394.83,176.88 394.83,175.86 394.34,175.37 391.07,175.37 388.07,178.37 344.03,178.37 343.71,178.04 339.41,178.04 338.67,178.79 308.85,178.79 v1(308.38,179.26)
  L05_SIGNAL w0.071: D108.08 397.36,39.52 396.31,39.52 395.97,39.85 395.97,46.97 393.45,49.5 380.87,49.5 378.82,51.54 378.82,89.35 383.41,93.93 392.43,93.93 395.53,97.03 395.53,140.96 396.48,141.91 396.48,166.56 395.54,167.5 392.74,167.5 391.76,166.52 391.76,145.83 392.47,145.12 392.47,102.66 391.81,102 390.46,102 389.66,102.8 389.66,175.97 393.16,179.47 394.1,179.47 394.83,178.74 394.83,177.83 v1(394.35,177.36)
D10809: length 413.5
  TOP w0.086: SITE4.2 322.63,171.48 322.55,171.4 322.55,171.18 322.13,170.76 314.03,170.76 313.52,170.25 308.97,170.25 v1(308.51,169.79)
  L03_SIGNAL w0.071: v1(408.96,190.94) 408.49,190.47 408.49,189.33 411.61,186.22 411.61,158.69 409.45,156.53 380.09,156.53 376.17,160.45 376.17,163.79 373.04,166.92 355.62,166.92 352.14,170.4 340.58,170.4 338.84,168.66 317.31,168.66 315.7,170.26 308.98,170.26 v1(308.51,169.79)
  L05_SIGNAL w0.071: D108.09 403.05,33.83 403.05,33.76 403.05,27.38 406.76,23.67 442.9,23.67 449.17,29.94 449.17,170.3 431.9,187.58 410.3,187.58 408.49,189.39 408.49,190.47 v1(408.96,190.94)
D10810: length 413.5
  TOP w0.086: SITE4.168 317.68,179.23 317.6,179.31 313.34,179.31 312.15,180.5 305.84,180.5 v1(305.36,180.02)
  L03_SIGNAL w0.071: v1(395.5,190.94) 395.03,190.47 395.03,189.79 394.23,188.99 390.24,188.99 385.24,193.99 364.39,193.99 363.77,194.6 359.19,194.6 357.42,196.38 343.97,196.38 339.42,200.92 320.35,200.92 317.22,197.8 309.01,197.8 299.81,207 282.77,207 281.08,205.31 281.08,168.3 285.08,164.3 300.14,164.3 303.06,167.22 303.06,182.81 303.84,183.59 306.66,183.59 307.22,183.03 307.22,181.21 306.51,180.49 305.83,180.49 v1(305.36,180.02)
  L05_SIGNAL w0.071: D108.10 405.96,40.2 406.21,40.2 406.52,40.52 406.52,46.07 411.07,50.62 421.15,50.62 423.52,52.98 423.52,91.55 401.14,113.93 401.14,143.74 403.15,145.75 403.15,156.33 401.14,158.34 401.14,190.06 398.26,192.94 395.91,192.94 395.03,192.06 395.03,191.42 395.02,191.42 v1(395.5,190.94)
D10811: length 413.5
  TOP w0.086: v1(308.51,170.93) 308.95,170.49 313.42,170.49 313.93,171 322.03,171 322.31,171.28 322.31,171.4 322.23,171.48 SITE4.1
  L03_SIGNAL w0.071: v1(308.51,170.93) 308.98,170.46 315.78,170.46 317.39,168.85 338.76,168.85 340.5,170.59 352.23,170.59 355.7,167.12 373.12,167.12 376.37,163.87 376.37,160.53 380.17,156.73 409.37,156.73 411.41,158.77 411.41,186.13 408.29,189.25 408.29,190.47 v1(407.82,190.94)
  L05_SIGNAL w0.071: D108.11 405.06,34.22 403.69,34.22 403.25,33.78 403.25,27.46 406.84,23.86 442.82,23.86 448.98,30.02 448.98,170.22 431.81,187.38 410.21,187.38 408.29,189.31 408.29,190.47 v1(407.82,190.94)
D10812: length 413.5
  TOP w0.086: SITE4.167 317.68,179.63 317.6,179.55 313.44,179.55 312.25,180.74 305.78,180.74 v1(305.36,181.16)
  L03_SIGNAL w0.071: v1(394.35,190.94) 394.83,190.47 394.83,189.87 394.15,189.19 390.32,189.19 385.33,194.19 364.47,194.19 363.86,194.8 359.27,194.8 357.5,196.58 344.05,196.58 339.51,201.12 320.26,201.12 317.14,198 309.1,198 299.9,207.2 282.69,207.2 280.88,205.39 280.88,168.22 285,164.1 300.22,164.1 303.26,167.14 303.26,182.73 303.92,183.4 306.58,183.4 307.02,182.95 307.02,181.29 306.43,180.69 305.83,180.69 v1(305.36,181.16)
  L05_SIGNAL w0.071: D108.12 406.72,40.32 406.72,45.99 411.15,50.42 421.24,50.42 423.72,52.9 423.72,91.63 401.34,114.01 401.34,143.66 403.35,145.67 403.35,156.42 401.34,158.42 401.34,190.14 398.34,193.14 395.82,193.14 394.83,192.14 394.83,191.42 v1(394.35,190.94)
D10813: length 413.5
  TOP w0.086: SITE4.174 317.68,176.83 317.6,176.91 316.1,176.91 314.04,174.85 308.85,174.85 v1(308.4,174.39)
  L03_SIGNAL w0.071: v1(408.96,177.36) 408.49,176.88 408.49,175.62 407.98,175.12 406.69,175.12 401.91,170.33 355.38,170.33 352.69,173.03 317.3,173.03 315.46,174.87 308.87,174.87 v1(308.4,174.39)
  L05_SIGNAL w0.071: D108.13 413.47,33.57 413.47,29.69 417.25,25.91 433.91,25.91 437.47,29.47 437.47,63.36 438.89,64.78 440.82,64.78 442.14,63.46 442.14,28.87 443.46,27.54 444.96,27.54 446.27,28.85 446.27,168.65 442.15,172.77 412.08,172.77 408.49,176.36 408.49,176.88 v1(408.96,177.36)
D10814: length 457
  TOP w0.086: SITE4.14 327.43,171.48 327.35,171.4 327.35,159 v1(327.8,158.55)
  L03_SIGNAL w0.071: v1(403.03,195.31) 402.56,195.78 402.17,195.78 401.7,195.3 401.7,194.45 402.15,194 447.18,194 449.71,191.47 449.71,141.66 448.82,140.77 445.73,140.77 444.11,142.38 444.11,161.97 442.08,164 439.98,164 438,162.02 438,156.54 434.59,153.12 337.3,153.12 330.83,159.6 327.65,159.6 327.33,159.27 327.33,159.02 v1(327.8,158.55)
  L05_SIGNAL w0.071: D108.14 415.56,39.64 416.32,39.64 416.73,40.05 416.73,45.38 418.69,47.35 426.58,47.35 434.25,55.01 434.25,93.77 411.72,116.3 411.72,163.82 406.77,168.76 406.77,193.72 404.72,195.78 403.51,195.78 v1(403.03,195.31)
D10815: length 413.5
  TOP w0.086: v1(308.4,175.54) 308.85,175.08 313.94,175.08 316,177.15 317.6,177.15 317.68,177.23 SITE4.173
  L03_SIGNAL w0.071: v1(308.4,175.54) 308.87,175.06 315.55,175.06 317.39,173.22 352.77,173.22 355.46,170.53 401.83,170.53 406.61,175.31 407.9,175.31 408.29,175.71 408.29,176.88 v1(407.82,177.36)
  L05_SIGNAL w0.071: v1(407.82,177.36) 408.29,176.88 408.29,176.28 411.99,172.57 442.06,172.57 446.07,168.56 446.07,28.93 444.88,27.74 443.55,27.74 442.33,28.95 442.33,63.54 440.9,64.97 438.81,64.97 437.28,63.44 437.28,29.56 433.83,26.11 417.33,26.11 413.67,29.77 413.67,33.68 414.05,34.06 415.06,34.06 D108.15
D10816: length 457
  TOP w0.086: v1(326.65,158.55) 327.11,159 327.11,171.4 327.03,171.48 SITE4.13
  L03_SIGNAL w0.071: v1(403.03,196.45) 402.56,195.98 402.09,195.98 401.5,195.39 401.5,194.37 402.07,193.8 447.1,193.8 449.51,191.39 449.51,141.75 448.74,140.97 445.81,140.97 444.31,142.47 444.31,162.05 442.16,164.2 439.9,164.2 437.8,162.1 437.8,156.62 434.51,153.32 337.39,153.32 330.91,159.8 327.57,159.8 327.13,159.36 327.13,159.02 v1(326.65,158.55)
  L05_SIGNAL w0.071: v1(403.03,196.45) 403.51,195.98 404.8,195.98 406.97,193.81 406.97,168.84 411.91,163.9 411.91,116.38 434.45,93.85 434.45,54.93 426.66,47.15 418.77,47.15 416.92,45.3 416.92,40.28 D108.16
D10901: length 413.5
  TOP w0.086: SITE2.176 317.68,236.03 317.6,236.11 317.48,236.11 317.25,235.88 317.25,234.98 315.19,232.92 305.91,232.92 v1(305.46,232.46)
  L03_SIGNAL w0.071: v1(305.46,232.46) 305.93,232.94 315.51,232.94 317.5,230.94 327.72,230.94 328.47,231.69 334.92,231.69 341.38,225.23 341.38,220.8 343.03,219.15 355.2,219.15 359.7,223.64 378.04,223.64 379.66,222.03 379.66,205.84 381.46,204.04 382.36,204.04 382.83,204.51 382.83,205.84 v1(383.31,206.31)
  L05_SIGNAL w0.071: v1(383.31,206.31) 382.83,205.84 382.83,205.84 382.83,202.34 383.61,201.57 387.34,201.57 396.14,210.37 446.5,210.37 449.68,207.19 468.35,207.19 473.28,212.12 473.28,241.91 481.56,250.2 481.56,313.9 454.87,340.6 421.04,340.6 418.67,338.24 418.67,334.77 419.46,333.98 420.4,333.98 D109.01
D10902: length 413.5
  TOP w0.086: SITE2.168 317.68,239.23 317.6,239.31 313.34,239.31 312.15,240.5 305.84,240.5 v1(305.36,240.02)
  L03_SIGNAL w0.071: v1(305.36,240.02) 305.83,240.49 311.57,240.49 313.16,242.08 320.69,242.08 321.24,242.62 323.37,242.62 324.05,241.94 337.86,241.94 338.76,241.04 342.39,241.04 344.24,242.89 346.09,242.89 354.63,234.35 379.77,234.35 387.8,242.39 396.13,242.39 400.89,237.63 400.89,234.99 401.67,234.21 402.66,234.21 403.15,234.71 403.15,235.43 v1(403.63,235.9)
  L05_SIGNAL w0.071: D109.02 416.85,327.95 416.85,326.44 417.83,325.47 420.5,325.47 433.47,338.45 453.91,338.45 479.45,312.9 479.45,250.54 467.02,238.11 467.02,232.42 465.09,230.49 465.09,226.27 466.18,225.18 468.61,225.18 469.9,223.89 469.9,214.44 468.92,213.46 443.25,213.46 438.55,218.16 428.5,218.16 423.85,213.51 411.12,213.51 408.33,216.3 408.33,235.19 405.96,237.56 403.64,237.56 403.15,237.07 403.15,236.37 v1(403.63,235.9)
D10903: length 413.5
  TOP w0.086: v1(305.46,233.61) 305.91,233.16 315.09,233.16 317.01,235.08 317.01,235.98 317.38,236.35 317.6,236.35 317.68,236.43 SITE2.175
  L03_SIGNAL w0.071: v1(382.16,206.31) 382.63,205.84 382.63,204.59 382.28,204.23 381.54,204.23 379.85,205.92 379.85,222.11 378.13,223.84 359.62,223.84 355.12,219.34 343.12,219.34 341.58,220.88 341.58,225.31 335,231.89 328.39,231.89 327.64,231.14 317.58,231.14 315.59,233.14 305.93,233.14 v1(305.46,233.61)
  L05_SIGNAL w0.071: D109.03 418.47,334.65 418.47,338.32 420.95,340.8 454.95,340.8 481.76,313.98 481.76,250.12 473.48,241.83 473.48,212.04 468.43,206.99 449.59,206.99 446.42,210.17 396.22,210.17 387.42,201.37 383.53,201.37 382.63,202.26 382.63,205.84 v1(382.16,206.31)
D10904: length 413.5
  TOP w0.086: v1(305.36,241.16) 305.78,240.74 312.25,240.74 313.44,239.55 317.6,239.55 317.68,239.63 SITE2.167
  L03_SIGNAL w0.071: v1(305.36,241.16) 305.83,240.69 311.49,240.69 313.07,242.28 320.61,242.28 321.15,242.82 323.45,242.82 324.14,242.14 337.94,242.14 338.85,241.24 342.31,241.24 344.15,243.09 346.17,243.09 354.71,234.55 379.69,234.55 387.72,242.59 396.21,242.59 401.09,237.71 401.09,235.08 401.76,234.41 402.57,234.41 402.95,234.79 402.95,235.43 v1(402.48,235.9)
  L05_SIGNAL w0.071: D109.04 415.27,328.95 415.62,328.95 416.66,327.92 416.66,326.36 417.75,325.27 420.58,325.27 433.56,338.25 453.83,338.25 479.26,312.82 479.26,250.62 466.83,238.19 466.83,232.5 464.89,230.57 464.89,226.19 466.1,224.99 468.52,224.99 469.7,223.8 469.7,214.52 468.84,213.65 443.33,213.65 438.63,218.36 428.42,218.36 423.77,213.71 411.21,213.71 408.53,216.38 408.53,235.27 406.05,237.75 403.55,237.75 402.95,237.15 402.95,236.37 v1(402.48,235.9)
D10905: length 413.5
  TOP w0.086: v1(308.4,234.39) 308.85,234.85 314.04,234.85 316.1,236.91 317.6,236.91 317.68,236.83 SITE2.174
  L03_SIGNAL w0.071: v1(396.77,206.57) 396.29,206.09 396.29,205.15 395.8,204.66 394.66,204.66 393.21,206.1 393.21,209.95 390.37,212.8 382.17,212.8 381.07,213.9 381.07,223.16 374.58,229.65 338.58,229.65 335.35,232.88 318.3,232.88 316.32,234.87 308.87,234.87 v1(308.4,234.39)
  L05_SIGNAL w0.071: v1(396.77,206.57) 396.3,206.09 396.3,205.33 397.13,204.49 469.39,204.49 474.8,209.9 479.72,209.9 484.37,214.55 484.37,314.36 455.7,343.02 412.36,343.02 408.32,338.98 408.32,335.23 409.43,334.12 410.1,334.12 D109.05
D10906: length 413.5
  TOP w0.086: SITE2.170 317.68,238.43 317.6,238.5 308.77,238.5 v1(308.38,238.12)
  L03_SIGNAL w0.071: v1(403.63,222.31) 403.15,221.84 403.15,219.87 402.09,218.8 400.56,218.8 399.62,219.74 399.62,221 397.82,222.8 395.6,222.8 394.48,221.68 394.48,219.01 392.06,216.6 387.69,216.6 385.91,218.38 385.91,226.91 379.51,233.31 342.93,233.31 337.65,238.59 308.85,238.59 v1(308.38,238.12)
  L05_SIGNAL w0.071: v1(403.63,222.31) 403.15,222.79 403.15,224.22 399.96,227.41 399.96,237.64 401.82,239.49 407.12,239.49 411.61,235 411.61,223.73 414.81,220.53 443.81,220.53 448.31,225.03 448.31,303.05 451.47,306.21 468,306.21 472.1,310.31 472.1,316.17 465.34,322.93 445.01,322.93 438.86,316.78 438.86,312.13 436.11,309.37 419.87,309.37 406.57,322.66 406.57,327.83 D109.06
D10907: length 413.5
  TOP w0.086: SITE2.173 317.68,237.23 317.6,237.15 316,237.15 313.94,235.08 308.85,235.08 v1(308.4,235.54)
  L03_SIGNAL w0.071: v1(395.62,206.57) 396.1,206.09 396.1,205.23 395.72,204.86 394.74,204.86 393.41,206.19 393.41,210.04 390.45,213 382.25,213 381.27,213.98 381.27,223.24 374.66,229.85 338.66,229.85 335.43,233.08 318.38,233.08 316.4,235.06 308.87,235.06 v1(308.4,235.54)
  L05_SIGNAL w0.071: D109.07 408.12,334.46 408.12,339.06 412.28,343.22 455.79,343.22 484.57,314.44 484.57,214.47 479.8,209.7 474.89,209.7 469.48,204.29 397.05,204.29 396.1,205.24 396.1,206.09 v1(395.62,206.57)
D10908: length 413.5
  TOP w0.086: v1(308.38,239.26) 308.9,238.74 317.59,238.74 317.68,238.83 SITE2.169
  L03_SIGNAL w0.071: v1(308.38,239.26) 308.85,238.79 337.74,238.79 343.01,233.51 379.59,233.51 386.11,226.99 386.11,218.46 387.78,216.8 391.98,216.8 394.28,219.1 394.28,221.76 395.52,223 397.9,223 399.82,221.08 399.82,219.82 400.64,219 402,219 402.95,219.95 402.95,221.84 v1(402.48,222.31)
  L05_SIGNAL w0.071: D109.08 404.91,329.15 405.27,329.15 406.38,328.05 406.38,322.58 419.78,309.17 436.19,309.17 439.06,312.04 439.06,316.7 445.09,322.73 465.26,322.73 471.9,316.09 471.9,310.39 467.92,306.41 451.39,306.41 448.11,303.13 448.11,225.11 443.73,220.73 414.89,220.73 411.81,223.81 411.81,235.08 407.2,239.69 401.73,239.69 399.76,237.72 399.76,227.32 402.95,224.13 402.95,222.79 v1(402.48,222.31)
D10909: length 457
  TOP w0.086: v1(327.8,218.55) 327.35,218.99 327.35,231.4 327.43,231.48 SITE2.14
  L03_SIGNAL w0.071: v1(327.8,218.55) 327.33,219.02 327.33,219.25 327.42,219.34 334.32,219.34 337.6,216.06 374.83,216.06 376.79,214.1 376.79,204.72 379.9,201.61 400.84,201.61 401.84,202.6 444.39,202.6 448.37,206.58 448.37,234.75 445.89,237.23 427.28,237.23 422.83,232.78 422.83,208.57 418.95,204.68 408.71,204.68 407.15,206.24 407.15,221.52 404.27,224.41 395.58,224.41 392.27,221.1 392.27,219.66 391.12,218.52 388.81,218.52 388.21,219.12 388.21,232.49 389.69,233.97 389.69,235.18 v1(390.16,235.65)
  L05_SIGNAL w0.071: D109.09 399.52,334.54 399.52,338.42 395.85,342.1 375.91,342.1 373.17,339.36 373.17,320.51 384.17,309.51 384.17,237.47 387.54,234.11 389.3,234.11 389.69,234.5 389.69,235.18 v1(390.16,235.65)
D10910: length 413.5
  TOP w0.086: SITE2.2 322.63,231.48 322.55,231.4 322.55,231.18 322.13,230.76 314.03,230.76 313.52,230.25 308.97,230.25 v1(308.51,229.79)
  L03_SIGNAL w0.071: v1(396.77,220.15) 396.3,219.68 396.3,218.37 400.35,214.32 400.35,205.61 397.69,202.95 381.3,202.95 379.03,205.22 379.03,221.22 377.84,222.41 361.54,222.41 356.94,217.81 339.63,217.81 338.56,218.88 338.56,225.36 336.49,227.42 318.7,227.42 315.86,230.26 308.98,230.26 v1(308.51,229.79)
  L05_SIGNAL w0.071: D109.10 396.75,328.17 396.75,323.17 428.31,291.6 428.31,264.18 430.22,262.28 432.66,262.28 434.14,263.76 434.14,282.24 437.37,285.47 441.52,285.47 444.19,282.8 444.19,227.73 440.32,223.87 427.26,223.87 423.54,227.59 423.54,239.25 419.54,243.25 399.38,243.25 397.48,241.35 397.48,224.06 396.3,222.88 396.3,220.63 v1(396.77,220.15)
D10911: length 457
  TOP w0.086: v1(326.65,218.55) 327.11,219 327.11,231.4 327.03,231.48 SITE2.13
  L03_SIGNAL w0.071: v1(326.65,218.55) 327.13,219.02 327.13,219.33 327.33,219.54 334.4,219.54 337.68,216.26 374.91,216.26 376.99,214.18 376.99,204.8 379.99,201.8 400.76,201.8 401.75,202.8 444.31,202.8 448.17,206.66 448.17,234.67 445.81,237.03 427.36,237.03 423.03,232.7 423.03,208.49 419.03,204.49 408.62,204.49 406.95,206.16 406.95,221.44 404.18,224.21 395.66,224.21 392.46,221.01 392.46,219.58 391.2,218.32 388.73,218.32 388.01,219.03 388.01,232.57 389.49,234.05 389.49,235.18 v1(389.02,235.65)
  L05_SIGNAL w0.071: D109.11 397.78,334.28 399.1,334.28 399.32,334.5 399.32,338.34 395.76,341.9 375.99,341.9 373.37,339.27 373.37,320.59 384.37,309.59 384.37,237.56 387.62,234.31 389.22,234.31 389.49,234.59 389.49,235.18 v1(389.02,235.65)
D10912: length 413.5
  TOP w0.086: v1(308.51,230.93) 308.95,230.49 313.42,230.49 313.93,231 322.03,231 322.31,231.28 322.31,231.4 322.23,231.48 SITE2.1
  L03_SIGNAL w0.071: v1(308.51,230.93) 308.98,230.46 315.94,230.46 318.78,227.62 336.57,227.62 338.75,225.44 338.75,218.97 339.71,218.01 356.86,218.01 361.46,222.61 377.92,222.61 379.23,221.31 379.23,205.3 381.38,203.15 397.61,203.15 400.15,205.69 400.15,214.24 396.1,218.29 396.1,219.68 v1(395.62,220.15)
  L05_SIGNAL w0.071: v1(395.62,220.15) 396.1,220.63 396.1,222.96 397.28,224.14 397.28,241.43 399.3,243.45 419.62,243.45 423.74,239.33 423.74,227.67 427.34,224.07 440.24,224.07 443.99,227.82 443.99,282.72 441.43,285.27 437.46,285.27 434.34,282.16 434.34,263.68 432.74,262.08 430.13,262.08 428.12,264.1 428.12,291.52 396.55,323.08 396.55,328.01 395.67,328.89 395.01,328.89 D109.12
D10913: length 457
  TOP w0.086: v1(318.42,214.92) 318.42,215.56 323.1,220.24 323.1,221.66 325.75,224.32 325.75,231.4 325.83,231.48 SITE2.10
  L03_SIGNAL w0.071: v1(390.16,251.9) 389.69,252.38 389.69,253.44 389.11,254.02 387.55,254.02 386.39,252.87 386.39,251.51 382.5,247.62 366.91,247.62 364.11,250.42 359.24,250.42 357.88,249.06 356.03,249.06 348.37,256.72 310.89,256.72 299.65,267.97 287.74,267.97 283.53,263.75 283.53,223.94 284.2,223.27 285.62,223.27 286.35,224.01 286.35,263.08 287.11,263.83 289.12,263.83 289.94,263.01 289.94,224.01 290.74,223.21 293.48,223.21 294.08,223.8 294.08,237.02 294.73,237.67 295.8,237.67 296.75,236.72 296.75,224.5 307.22,214.03 316.86,214.03 317.75,214.92 v1(318.42,214.92)
  L05_SIGNAL w0.071: D109.13 390.17,333.73 390.17,337.41 386.47,341.12 377.86,341.12 375.56,338.82 375.56,321.68 392.92,304.32 392.92,256.83 392.19,256.1 387.68,256.1 386.71,255.13 386.71,250.95 387.53,250.14 389.18,250.14 389.69,250.65 389.69,251.43 v1(390.16,251.9)
D10914: length 457
  TOP w0.086: v1(325.68,216.6) 325.23,217.05 325.23,222.4 326.55,223.72 326.55,231.4 326.63,231.48 SITE2.12
  L03_SIGNAL w0.071: v1(325.68,216.6) 325.21,216.12 325.21,215.2 326.91,213.5 361.22,213.5 375.44,199.28 476.97,199.28 479.47,201.78 483.01,201.78 484.46,203.23 484.46,254.24 482.18,256.52 426.06,256.52 417.95,248.42 417.95,237.21 412.64,231.9 398.72,231.9 394.66,235.96 394.66,239.22 393.57,240.32 390.34,240.32 389.69,239.67 389.69,238.79 v1(390.16,238.32)
  L05_SIGNAL w0.071: D109.14 387.32,328.9 386.5,328.9 385.15,327.55 385.15,321.84 394.57,312.41 394.57,245.05 389.69,240.16 389.69,238.79 v1(390.16,238.32)
D10915: length 457
  TOP w0.086: SITE2.9 325.43,231.48 325.51,231.4 325.51,224.41 322.86,221.76 322.86,220.34 318.25,215.73 v1(317.61,215.73)
  L03_SIGNAL w0.071: v1(389.02,251.9) 389.49,252.38 389.49,253.36 389.03,253.82 387.63,253.82 386.59,252.79 386.59,251.43 382.58,247.42 366.83,247.42 364.03,250.22 359.32,250.22 357.96,248.86 355.95,248.86 348.28,256.52 310.81,256.52 299.56,267.77 287.82,267.77 283.73,263.67 283.73,224.02 284.28,223.47 285.54,223.47 286.16,224.09 286.16,263.16 287.02,264.03 289.2,264.03 290.13,263.09 290.13,224.09 290.83,223.4 293.4,223.4 293.88,223.88 293.88,237.1 294.65,237.86 295.88,237.86 296.95,236.8 296.95,224.58 307.3,214.23 316.78,214.23 317.61,215.06 v1(317.61,215.73)
  L05_SIGNAL w0.071: v1(389.02,251.9) 389.49,251.43 389.49,250.73 389.1,250.33 387.61,250.33 386.91,251.04 386.91,255.05 387.76,255.9 392.28,255.9 393.12,256.74 393.12,304.4 375.76,321.76 375.76,338.74 377.94,340.92 386.39,340.92 389.97,337.33 389.97,334.16 389.65,333.83 387.17,333.83 D109.15
D10916: length 457
  TOP w0.086: v1(324.54,216.6) 324.99,217.05 324.99,222.5 326.31,223.82 326.31,231.4 326.23,231.48 SITE2.11
  L03_SIGNAL w0.071: v1(389.02,238.32) 389.49,238.79 389.49,239.75 390.26,240.51 393.65,240.51 394.86,239.3 394.86,236.04 398.8,232.1 412.56,232.1 417.75,237.29 417.75,248.5 425.97,256.72 482.27,256.72 484.66,254.33 484.66,203.15 483.09,201.58 479.55,201.58 477.05,199.08 375.35,199.08 361.14,213.3 326.83,213.3 325.01,215.12 325.01,216.12 v1(324.54,216.6)
  L05_SIGNAL w0.071: v1(389.02,238.32) 389.49,238.79 389.49,240.25 394.38,245.13 394.38,312.33 384.95,321.75 384.95,328.79 D109.16
D11301: length 413.5
  TOP w0.086: v1(305.39,236.18) 305.85,236.63 314.38,236.63 315.46,237.71 317.6,237.71 317.68,237.63 SITE2.172
  L03_SIGNAL w0.071: v1(305.39,236.18) 305.87,236.65 320.74,236.65 323.23,234.16 338.98,234.16 342.22,230.92 378.02,230.92 384.81,224.13 384.81,218.85 384.29,218.33 383.25,218.33 382.83,218.74 382.83,219.43 v1(383.31,219.9)
  L05_SIGNAL w0.071: D113.01 346.56,334.16 345.33,334.16 345.19,334.3 345.19,338.08 348.53,341.42 359.68,341.42 366.38,334.71 366.38,316.24 380.64,301.99 380.64,220.95 378.5,218.81 362.94,218.81 360.99,220.75 360.99,249.43 357.89,252.54 345.69,252.54 341.05,247.89 341.05,215.73 343.15,213.63 380.08,213.63 381.94,215.49 381.94,217.99 382.83,218.88 382.83,219.43 v1(383.31,219.9)
D11302: length 457
  TOP w0.086: SITE2.8 325.03,231.48 324.95,231.4 324.95,225.37 319.21,219.63 v1(319.21,218.99)
  L03_SIGNAL w0.071: v1(319.21,218.99) 319.21,219.66 320.41,220.86 323.27,220.86 324.15,219.98 335.84,219.98 338.88,216.94 373.42,216.94 375.98,219.5 375.98,221.73 376.05,221.81 v1(376.45,221.81)
  L05_SIGNAL w0.071: v1(376.45,221.81) 375.98,222.28 375.98,223.44 377.03,224.49 377.03,228.03 372.59,232.47 372.59,237.74 370.45,239.88 370.45,300.17 361.38,309.24 339.09,309.24 333.78,303.93 333.78,278.31 337.17,274.92 359.53,274.92 364.26,270.19 364.26,226.02 370.1,220.18 377.88,220.18 379.44,221.74 379.44,299.53 359.14,319.83 347.22,319.83 343.82,323.23 343.82,328.58 D113.02
D11303: length 413.5
  TOP w0.086: v1(305.39,237.32) 305.85,236.87 314.29,236.87 315.37,237.95 317.6,237.95 317.68,238.03 SITE2.171
  L03_SIGNAL w0.071: v1(382.16,219.9) 382.63,219.43 382.63,218.66 383.17,218.13 384.37,218.13 385.01,218.77 385.01,224.21 378.1,231.12 342.3,231.12 339.06,234.36 323.31,234.36 320.82,236.85 305.87,236.85 v1(305.39,237.32)
  L05_SIGNAL w0.071: D113.03 344.99,334.83 344.99,338.16 348.45,341.61 359.76,341.61 366.58,334.8 366.58,316.32 380.83,302.07 380.83,220.86 378.58,218.61 362.86,218.61 360.79,220.67 360.79,249.35 357.8,252.34 345.77,252.34 341.24,247.81 341.24,215.82 343.24,213.82 379.99,213.82 381.74,215.57 381.74,218.07 382.63,218.96 382.63,219.43 v1(382.16,219.9)
D11304: length 457
  TOP w0.086: SITE2.7 324.63,231.48 324.71,231.4 324.71,225.47 319.04,219.8 v1(318.4,219.8)
  L03_SIGNAL w0.071: v1(375.3,221.81) 375.71,221.81 375.78,221.73 375.78,219.58 373.34,217.14 338.96,217.14 335.93,220.18 324.23,220.18 323.35,221.06 320.33,221.06 319.07,219.8 v1(318.4,219.8)
  L05_SIGNAL w0.071: D113.04 341.36,329.2 343.02,329.2 343.62,328.59 343.62,323.15 347.14,319.63 359.06,319.63 379.24,299.45 379.24,221.82 377.8,220.38 370.18,220.38 364.45,226.1 364.45,270.28 359.61,275.12 337.25,275.12 333.98,278.39 333.98,303.84 339.17,309.04 361.29,309.04 370.25,300.09 370.25,239.8 372.39,237.65 372.39,232.39 376.83,227.94 376.83,224.58 375.78,223.52 375.78,222.28 v1(375.3,221.81)
D11305: length 457
  TOP w0.086: v1(330.13,216.61) 329.68,217.05 329.68,221.65 328.15,223.18 328.15,231.4 328.23,231.48 SITE2.16
  L03_SIGNAL w0.071: v1(390.16,222.06) 389.69,221.59 389.69,219.84 389.9,219.63 390.73,219.63 391.48,220.38 391.48,223 395.58,227.09 409.02,227.09 420.59,238.66 420.59,248.89 424.73,253.04 448.38,253.04 450.3,251.12 450.3,204.59 447.14,201.43 408.47,201.43 407.86,200.83 376.05,200.83 361.87,215 336.94,215 334.16,217.78 329.98,217.78 329.66,217.46 329.66,217.08 v1(330.13,216.61)
  L05_SIGNAL w0.071: D113.05 335.38,335.18 335.38,339.03 339.92,343.57 366.08,343.57 370.39,339.26 370.39,317.73 382.35,305.76 382.35,222.21 384.09,220.46 388.91,220.46 389.69,221.24 389.69,221.59 v1(390.16,222.06)
D11306: length 457
  TOP w0.086: v1(315.41,217.99) 315.41,218.63 324.15,227.37 324.15,231.4 324.23,231.48 SITE2.6
  L03_SIGNAL w0.071: v1(376.45,235.39) 375.97,235.87 375.97,236.52 383.15,243.7 408.49,243.7 413.7,248.91 413.7,305.72 411.77,307.64 409.19,307.64 407.59,306.04 407.59,250.06 403.06,245.53 368.79,245.53 362.84,239.58 352.16,239.58 347.49,244.25 344.15,244.25 342.85,245.54 328.71,245.54 327.59,244.42 320.55,244.42 320,243.87 314.24,243.87 313.66,244.45 306.23,244.45 303.76,241.99 303.76,221.23 307.94,217.06 313.81,217.06 314.74,217.99 v1(315.41,217.99)
  L05_SIGNAL w0.071: v1(376.45,235.39) 375.98,235.87 375.98,236.75 372.98,239.74 372.98,300.65 359.84,313.79 337.34,313.79 333.45,317.68 333.45,328.37 D113.06
D11307: length 457
  TOP w0.086: SITE2.15 327.83,231.48 327.91,231.4 327.91,223.08 329.45,221.55 329.45,217.06 v1(328.99,216.61)
  L03_SIGNAL w0.071: v1(328.99,216.61) 329.46,217.08 329.46,217.55 329.9,217.98 334.24,217.98 337.02,215.2 361.95,215.2 376.13,201.03 407.78,201.03 408.38,201.63 447.06,201.63 450.1,204.67 450.1,251.04 448.3,252.84 424.81,252.84 420.79,248.81 420.79,238.58 409.1,226.89 395.66,226.89 391.68,222.92 391.68,220.3 390.82,219.43 389.82,219.43 389.49,219.76 389.49,221.59 v1(389.02,222.06)
  L05_SIGNAL w0.071: v1(389.02,222.06) 389.49,221.59 389.49,221.32 388.83,220.66 384.18,220.66 382.55,222.29 382.55,305.85 370.59,317.81 370.59,339.35 366.16,343.77 339.83,343.77 335.18,339.11 335.18,335.18 D113.07
D11308: length 457
  TOP w0.086: v1(314.6,218.8) 315.24,218.8 323.91,227.47 323.91,231.4 323.83,231.48 SITE2.5
  L03_SIGNAL w0.071: v1(314.6,218.8) 314.6,218.13 313.73,217.26 308.02,217.26 303.96,221.31 303.96,241.9 306.31,244.26 313.58,244.26 314.15,243.68 320.09,243.68 320.63,244.22 327.67,244.22 328.8,245.35 342.77,245.35 344.07,244.05 347.41,244.05 352.08,239.38 362.92,239.38 368.88,245.33 403.14,245.33 407.79,249.97 407.79,305.96 409.28,307.44 411.69,307.44 413.5,305.63 413.5,249 408.41,243.9 383.07,243.9 375.78,236.61 375.78,235.87 v1(375.3,235.39)
  L05_SIGNAL w0.071: D113.08 331.36,329.04 332.77,329.04 333.25,328.55 333.25,317.59 337.26,313.59 359.75,313.59 372.78,300.57 372.78,239.66 375.78,236.67 375.78,235.87 v1(375.3,235.39)
D12501: length 413.5
  TOP w0.086: v1(228.38,238.12) 228.77,238.5 237.61,238.5 237.68,238.43 SITE1.170
  L03_SIGNAL w0.071: v1(228.38,238.12) 227.91,238.59 227.66,238.59 226.86,239.39 226.86,244.38 225.57,245.67 225.57,259.05 221.28,263.35 199.2,263.35 198.54,262.69 198.54,261.8 199.21,261.12 204.82,261.12 205.44,260.5 205.44,259.48 204.73,258.76 200.96,258.76 199.7,257.5 198.66,257.5 v2(198.18,257.03)
  L05_SIGNAL w0.071: D125.01 14.11,95.11 15.13,95.11 15.7,94.54 15.7,92.61 14.28,91.19 11.61,91.19 9.03,93.76 9.03,194.4 75.2,260.57 195.23,260.57 196.58,259.22 196.58,258.09 197.17,257.5 197.71,257.5 v2(198.18,257.03)
D12502: length 457
  TOP w0.086: v1(235.41,217.99) 235.41,218.63 244.15,227.37 244.15,231.4 244.23,231.48 SITE1.6
  L03_SIGNAL w0.071: v1(235.41,217.99) 235.41,218.66 235.72,218.97 235.72,225.05 236.88,226.21 236.88,231.62 235.23,233.27 235.23,251.26 221.65,264.84 198.02,264.84 195.99,262.81 195.99,254.34 205.56,244.76 209.62,244.76 210.59,243.78 211.55,243.78 v2(212.03,243.31)
  L05_SIGNAL w0.071: v2(212.03,243.31) 212.5,243.78 213.52,243.78 214.2,244.47 214.2,248.17 207.95,254.43 74.02,254.43 16.42,196.83 16.42,100.24 D125.02
D12503: length 413.5
  TOP w0.086: SITE1.169 237.68,238.83 237.59,238.74 228.9,238.74 v1(228.38,239.26)
  L03_SIGNAL w0.071: v1(228.38,239.26) 227.91,238.79 227.74,238.79 227.06,239.47 227.06,244.47 225.77,245.75 225.77,259.13 221.36,263.54 199.11,263.54 198.34,262.77 198.34,261.72 199.13,260.93 204.73,260.93 205.24,260.42 205.24,259.56 204.64,258.96 200.88,258.96 199.62,257.7 198.66,257.7 v2(198.18,258.17)
  L05_SIGNAL w0.071: v2(198.18,258.17) 197.71,257.7 197.25,257.7 196.78,258.17 196.78,259.3 195.31,260.77 75.12,260.77 8.84,194.48 8.84,93.68 11.53,90.99 14.36,90.99 15.9,92.53 15.9,94.64 D125.03
D12504: length 457
  TOP w0.086: SITE1.5 243.83,231.48 243.91,231.4 243.91,227.47 235.24,218.8 v1(234.6,218.8)
  L03_SIGNAL w0.071: v1(234.6,218.8) 235.27,218.8 235.52,219.05 235.52,225.13 236.68,226.29 236.68,231.54 235.04,233.18 235.04,251.18 221.57,264.65 198.11,264.65 196.18,262.72 196.18,254.42 205.65,244.96 209.7,244.96 210.68,243.98 211.55,243.98 v2(212.03,244.46)
  L05_SIGNAL w0.071: v2(212.03,244.46) 212.5,243.98 213.44,243.98 214.01,244.55 214.01,248.09 207.87,254.23 74.1,254.23 16.62,196.75 16.62,100.6 17.07,100.14 19.24,100.14 D125.04
D12505: length 413.5
  TOP w0.086: SITE1.168 237.68,239.23 237.6,239.31 233.34,239.31 232.15,240.5 225.84,240.5 v1(225.36,240.02)
  L03_SIGNAL w0.071: v1(211.77,257.03) 212.24,257.5 220.93,257.5 222.61,255.82 222.61,242.11 224.23,240.49 224.89,240.49 v1(225.36,240.02)
  L05_SIGNAL w0.071: D125.05 24,95.38 24.84,95.38 25.87,94.36 25.87,89.95 23.45,87.53 11.23,87.53 7,91.77 7,197.29 72.44,262.74 204.65,262.74 209.9,257.5 211.3,257.5 v1(211.77,257.03)
D12506: length 457
  TOP w0.086: SITE1.8 245.03,231.48 244.95,231.4 244.95,225.37 239.21,219.63 v1(239.21,218.99)
  L03_SIGNAL w0.071: v1(239.21,218.99) 239.21,219.66 239.41,219.86 239.41,263.47 232.91,269.97 187.36,269.97 185.18,267.79 185.18,256.36 193.58,247.97 193.58,246.89 196.68,243.78 197.97,243.78 v2(198.44,243.31)
  L05_SIGNAL w0.071: v2(198.44,243.31) 198.91,243.78 199.35,243.78 199.85,244.28 199.85,249.22 196.1,252.96 78.39,252.96 24.6,199.17 24.6,114.16 26.69,112.08 26.69,100.35 D125.06
D12507: length 413.5
  TOP w0.086: v1(225.36,241.16) 225.78,240.74 232.25,240.74 233.44,239.55 237.6,239.55 237.68,239.63 SITE1.167
  L03_SIGNAL w0.071: v2(211.77,258.17) 212.24,257.7 221.01,257.7 222.81,255.9 222.81,242.19 224.31,240.69 224.89,240.69 v1(225.36,241.16)
  L05_SIGNAL w0.071: v2(211.77,258.17) 211.3,257.7 209.98,257.7 204.74,262.94 72.36,262.94 6.8,197.38 6.8,91.68 11.15,87.33 23.53,87.33 26.07,89.87 26.07,94.65 D125.07
D12508: length 457
  TOP w0.086: v1(238.4,219.8) 239.04,219.8 244.71,225.47 244.71,231.4 244.63,231.48 SITE1.7
  L03_SIGNAL w0.071: v2(198.44,244.46) 197.97,243.98 196.76,243.98 193.78,246.97 193.78,248.05 185.38,256.45 185.38,267.71 187.44,269.77 232.82,269.77 239.21,263.38 239.21,219.94 239.07,219.8 v1(238.4,219.8)
  L05_SIGNAL w0.071: v2(198.44,244.46) 198.91,243.98 199.26,243.98 199.65,244.37 199.65,249.14 196.02,252.77 78.48,252.77 24.8,199.09 24.8,114.24 26.88,112.16 26.88,100.3 27.05,100.13 29.41,100.13 D125.08
D12509: length 413.5
  TOP w0.086: v1(228.51,229.79) 228.97,230.25 233.52,230.25 234.03,230.76 242.13,230.76 242.55,231.18 242.55,231.4 242.63,231.48 SITE1.2
  L03_SIGNAL w0.071: v2(195.26,243.31) 195.26,243.71 195.19,243.78 193.55,243.78 183.87,253.46 182.48,253.46 181.79,252.77 181.79,251.47 183.79,249.47 184.74,249.47 185.86,248.35 185.86,245.73 189.4,242.19 215.45,242.19 216.08,241.55 221.93,241.55 224.39,239.09 226.31,239.09 226.88,238.52 226.88,237.61 227.35,237.15 229.15,237.15 230.51,235.79 230.51,231.07 229.7,230.26 228.98,230.26 v1(228.51,229.79)
  L05_SIGNAL w0.071: D125.09 35.22,94.32 35.22,90.88 37.07,89.02 52.98,89.02 59.27,95.31 59.27,115.07 45.32,129.02 45.32,198.73 83.88,237.28 178.99,237.28 185.49,243.78 188.99,243.78 190.06,244.86 192.61,244.86 193.68,243.78 194.79,243.78 v2(195.26,243.31)
D12510: length 413.5
  TOP w0.086: SITE1.174 237.68,236.83 237.6,236.91 236.1,236.91 234.04,234.85 228.85,234.85 v1(228.4,234.39)
  L03_SIGNAL w0.071: v1(228.4,234.39) 227.93,234.87 226.93,234.87 225.95,235.84 225.95,237.7 225.38,238.27 223.86,238.27 222.01,240.13 170.47,240.13 169.55,241.04 169.55,245.93 170.14,246.52 171,246.52 171.56,245.97 171.56,241.95 172.08,241.43 172.77,241.43 173.36,242.02 173.36,244.75 173.86,245.25 174.56,245.25 175.12,244.7 175.12,242.8 175.71,242.22 179.9,242.22 180.47,242.79 180.47,247.12 178.27,249.32 175.17,249.32 174.55,249.95 174.55,252.5 175.03,252.98 178.03,252.98 183.18,247.83 183.18,244.28 182.69,243.78 182.15,243.78 v2(181.67,243.31)
  L05_SIGNAL w0.071: D125.10 36.74,100.24 36.74,112.86 29.32,120.28 29.32,198.48 79.89,249.04 180.03,249.04 182.74,246.33 182.74,244.1 182.42,243.78 182.15,243.78 v2(181.67,243.31)
D12511: length 413.5
  TOP w0.086: v1(228.51,230.93) 228.95,230.49 233.42,230.49 233.93,231 242.03,231 242.31,231.28 242.31,231.4 242.23,231.48 SITE1.1
  L03_SIGNAL w0.071: v1(228.51,230.93) 228.98,230.46 229.62,230.46 230.31,231.16 230.31,235.71 229.07,236.95 227.26,236.95 226.68,237.53 226.68,238.43 226.22,238.89 224.31,238.89 221.85,241.36 216,241.36 215.36,241.99 189.32,241.99 185.66,245.65 185.66,248.27 184.66,249.27 183.71,249.27 181.6,251.39 181.6,252.86 182.4,253.66 183.96,253.66 193.63,243.98 195.19,243.98 195.26,244.05 v2(195.26,244.46)
  L05_SIGNAL w0.071: D125.11 36.67,95.09 35.79,95.09 35.41,94.72 35.41,90.96 37.16,89.22 52.9,89.22 59.07,95.39 59.07,114.99 45.13,128.93 45.13,198.81 83.79,237.48 178.9,237.48 185.41,243.98 188.91,243.98 189.98,245.06 192.69,245.06 193.77,243.98 194.79,243.98 v2(195.26,244.46)
D12512: length 413.5
  TOP w0.086: SITE1.173 237.68,237.23 237.6,237.15 236,237.15 233.94,235.08 228.85,235.08 v1(228.4,235.54)
  L03_SIGNAL w0.071: v2(181.67,244.46) 182.15,243.98 182.61,243.98 182.98,244.36 182.98,247.75 177.95,252.78 175.12,252.78 174.75,252.42 174.75,250.03 175.26,249.52 178.35,249.52 180.67,247.2 180.67,242.71 179.98,242.02 175.63,242.02 174.92,242.72 174.92,244.61 174.48,245.06 173.94,245.06 173.56,244.67 173.56,241.93 172.85,241.23 171.99,241.23 171.36,241.86 171.36,245.88 170.92,246.32 170.22,246.32 169.75,245.85 169.75,241.13 170.55,240.32 222.09,240.32 223.95,238.47 225.46,238.47 226.14,237.79 226.14,235.93 227.01,235.06 227.93,235.06 v1(228.4,235.54)
  L05_SIGNAL w0.071: D125.12 39.51,100.19 37.4,100.19 36.94,100.65 36.94,112.94 29.52,120.36 29.52,198.39 79.97,248.84 179.95,248.84 182.54,246.25 182.54,244.18 182.34,243.98 182.15,243.98 v2(181.67,244.46)
D12513: length 413.5
  TOP w0.086: v1(225.39,236.18) 225.85,236.63 234.38,236.63 235.46,237.71 237.6,237.71 237.68,237.63 SITE1.172
  L03_SIGNAL w0.071: v1(225.39,236.18) 224.92,236.65 223.85,236.65 222.67,237.82 213.7,237.82 212.66,238.86 170.26,238.86 168.64,240.48 168.64,244.06 167.42,245.28 154.64,245.28 153.74,246.18 153.74,248.63 154.47,249.36 164.66,249.36 166.73,247.29 178.03,247.29 179.86,245.46 179.86,244.31 179.34,243.78 178.97,243.78 v2(178.5,243.31)
  L05_SIGNAL w0.071: D125.13 44.61,95.09 44.61,92.75 47.01,90.35 51.92,90.35 56.06,94.5 56.06,112.18 39.76,128.48 39.76,198.4 82.4,241.03 166.18,241.03 168.94,243.78 171.11,243.78 171.9,244.58 176.12,244.58 176.91,243.78 178.03,243.78 v2(178.5,243.31)
D12514: length 413.5
  TOP w0.086: v1(225.46,232.46) 225.91,232.92 235.19,232.92 237.25,234.98 237.25,235.88 237.48,236.11 237.6,236.11 237.68,236.03 SITE1.176
  L03_SIGNAL w0.071: v2(164.91,243.31) 165.38,243.78 165.72,243.78 166.34,243.16 166.34,242.1 165.85,241.61 134.1,241.61 132.88,240.39 132.88,237.26 134.33,235.81 211.14,235.81 212.23,236.89 222.31,236.89 222.79,236.41 222.79,234.45 224.31,232.94 224.98,232.94 v1(225.46,232.46)
  L05_SIGNAL w0.071: v2(164.91,243.31) 165.38,243.78 165.88,243.78 166.22,244.13 166.22,245.17 164.96,246.44 82.1,246.44 34.51,198.84 34.51,124.94 47.63,111.82 47.63,100.97 D125.14
D12515: length 413.5
  TOP w0.086: SITE1.171 237.68,238.03 237.6,237.95 235.37,237.95 234.29,236.87 225.85,236.87 v1(225.39,237.32)
  L03_SIGNAL w0.071: v2(178.5,244.46) 178.97,243.98 179.25,243.98 179.66,244.39 179.66,245.38 177.95,247.09 166.64,247.09 164.57,249.16 154.55,249.16 153.93,248.55 153.93,246.27 154.72,245.48 167.51,245.48 168.84,244.14 168.84,240.56 170.34,239.06 212.74,239.06 213.78,238.02 222.76,238.02 223.93,236.85 224.92,236.85 v1(225.39,237.32)
  L05_SIGNAL w0.071: v2(178.5,244.46) 178.03,243.98 176.99,243.98 176.2,244.77 171.82,244.77 171.03,243.98 168.86,243.98 166.1,241.22 82.31,241.22 39.57,198.48 39.57,128.39 55.86,112.1 55.86,94.58 51.84,90.55 47.09,90.55 44.81,92.83 44.81,94.43 45.43,95.05 46.79,95.05 D125.15
D12516: length 413.5
  TOP w0.086: v1(225.46,233.61) 225.91,233.16 235.09,233.16 237.01,235.08 237.01,235.98 237.38,236.35 237.6,236.35 237.68,236.43 SITE1.175
  L03_SIGNAL w0.071: v2(164.91,244.46) 165.38,243.98 165.8,243.98 166.54,243.24 166.54,242.02 165.94,241.42 134.18,241.42 133.07,240.31 133.07,237.34 134.41,236 211.06,236 212.15,237.09 222.4,237.09 222.99,236.49 222.99,234.53 224.39,233.14 224.98,233.14 v1(225.46,233.61)
  L05_SIGNAL w0.071: D125.16 49.75,100.11 48.78,100.11 47.83,101.07 47.83,111.9 34.71,125.02 34.71,198.76 82.18,246.24 164.87,246.24 166.02,245.09 166.02,244.21 165.8,243.98 165.38,243.98 v2(164.91,244.46)
D12609: length 457
  TOP w0.086: v1(250.13,216.61) 249.68,217.05 249.68,221.65 248.15,223.18 248.15,231.4 248.23,231.48 SITE1.16
  L03_SIGNAL w0.071: v1(181.67,229.6) 181.2,230.07 180.6,230.07 180.05,230.63 180.05,232.05 181.31,233.32 198.27,233.32 199.44,232.16 199.44,226.71 198.14,225.41 175.87,225.41 174.71,224.25 174.71,215.32 176.66,213.37 210.87,213.37 214.08,216.58 235.33,216.58 236.09,217.34 240.73,217.34 243.1,219.71 248.27,219.71 249.66,218.32 249.66,217.08 v1(250.13,216.61)
  L05_SIGNAL w0.071: v1(181.67,229.6) 181.2,230.07 180.65,230.07 180.1,229.52 180.1,226.13 176,222.03 130.95,222.03 129.39,220.47 87.91,220.47 87.2,219.77 87.2,205.39 72.03,190.22 72.03,82.33 58.22,68.51 36.99,68.51 34.96,70.54 34.96,74.26 D126.09
D12610: length 457
  TOP w0.086: v1(247.8,218.55) 247.35,218.99 247.35,231.4 247.43,231.48 SITE1.14
  L03_SIGNAL w0.071: v1(195.26,229.6) 195.73,230.07 196.1,230.07 196.73,229.44 196.73,228.04 195.17,226.48 167.7,226.48 165.8,224.58 165.8,214.73 168.9,211.63 211.38,211.63 214.68,214.93 235.45,214.93 236.83,216.3 242.46,216.3 243.55,217.39 245.62,217.39 246.01,217.01 246.85,217.01 247.33,217.48 247.33,218.07 v1(247.8,218.55)
  L05_SIGNAL w0.071: D126.10 37.28,80.46 37.28,85.37 39.26,87.35 54.12,87.35 61.25,94.47 61.25,117.36 49.74,128.87 49.74,198.11 85.65,234.02 194.9,234.02 196.82,232.1 196.82,230.44 196.45,230.07 195.73,230.07 v1(195.26,229.6)
D12611: length 457
  TOP w0.086: SITE1.15 247.83,231.48 247.91,231.4 247.91,223.08 249.45,221.55 249.45,217.06 v1(248.99,216.61)
  L03_SIGNAL w0.071: v1(181.67,230.74) 181.2,230.27 180.69,230.27 180.25,230.71 180.25,231.97 181.4,233.12 198.19,233.12 199.24,232.07 199.24,226.8 198.05,225.61 175.79,225.61 174.51,224.34 174.51,215.24 176.58,213.17 210.95,213.17 214.16,216.38 235.42,216.38 236.17,217.14 240.81,217.14 243.18,219.51 248.19,219.51 249.46,218.24 249.46,217.08 v1(248.99,216.61)
  L05_SIGNAL w0.071: D126.11 36.87,74.97 35.38,74.97 35.16,74.75 35.16,70.62 37.07,68.71 58.13,68.71 71.84,82.41 71.84,190.3 87.01,205.47 87.01,219.85 87.82,220.67 129.31,220.67 130.87,222.23 175.92,222.23 179.9,226.21 179.9,229.6 180.57,230.27 181.2,230.27 v1(181.67,230.74)
D12612: length 457
  TOP w0.086: SITE1.13 247.03,231.48 247.11,231.4 247.11,219 v1(246.65,218.55)
  L03_SIGNAL w0.071: v1(195.26,230.74) 195.73,230.27 196.18,230.27 196.93,229.52 196.93,227.95 195.25,226.28 167.78,226.28 166,224.49 166,214.81 168.99,211.82 211.3,211.82 214.6,215.13 235.37,215.13 236.74,216.5 242.38,216.5 243.47,217.59 245.71,217.59 246.09,217.2 246.77,217.2 247.13,217.56 247.13,218.07 v1(246.65,218.55)
  L05_SIGNAL w0.071: v1(195.26,230.74) 195.73,230.27 196.37,230.27 196.62,230.52 196.62,232.02 194.82,233.83 85.73,233.83 49.94,198.03 49.94,128.95 61.45,117.44 61.45,94.39 54.21,87.15 39.34,87.15 37.48,85.29 37.48,80.65 38.35,79.78 39.6,79.78 D126.12
D12613: length 457
  TOP w0.086: v1(238.42,214.92) 238.42,215.56 243.1,220.24 243.1,221.66 245.75,224.32 245.75,231.4 245.83,231.48 SITE1.10
  L03_SIGNAL w0.071: v1(238.42,214.92) 237.75,214.92 236.09,213.25 215.64,213.25 212.44,210.06 143.05,210.06 138.25,214.85 138.25,225.24 141.66,228.65 179.3,228.65 179.72,229.07 179.72,229.69 179.34,230.07 178.97,230.07 v2(178.5,229.6)
  L05_SIGNAL w0.071: D126.13 45.23,74.15 45.23,71.86 47.21,69.88 52.15,69.88 66.84,84.58 66.84,190.42 85.18,208.76 85.18,221.34 87.45,223.61 105.31,223.61 108.02,226.32 165.38,226.32 169.14,230.07 173.48,230.07 174.33,230.92 176.17,230.92 177.02,230.07 178.03,230.07 v2(178.5,229.6)
D12614: length 457
  TOP w0.086: v1(245.68,216.6) 245.23,217.05 245.23,222.4 246.55,223.72 246.55,231.4 246.63,231.48 SITE1.12
  L03_SIGNAL w0.071: v1(245.68,216.6) 245.21,216.12 245.21,214.8 242.86,212.46 221.32,212.46 217.3,208.43 137.22,208.43 131.77,213.89 131.77,228.89 136.71,233.83 165.81,233.83 166.65,233 166.65,230.86 165.85,230.07 165.38,230.07 v2(164.91,229.6)
  L05_SIGNAL w0.071: v2(164.91,229.6) 165.38,230.07 166.05,230.07 166.4,230.42 166.4,231.75 165.93,232.22 131.47,232.22 128.63,229.38 87.29,229.38 73.92,216.01 73.92,209.06 54.81,189.94 54.81,128.57 64.18,119.21 64.18,94.46 54.19,84.47 48.34,84.47 46.76,82.89 46.76,79.78 D126.14
D12615: length 457
  TOP w0.086: SITE1.9 245.43,231.48 245.51,231.4 245.51,224.41 242.86,221.76 242.86,220.34 238.25,215.73 v1(237.61,215.73)
  L03_SIGNAL w0.071: v2(178.5,230.74) 178.97,230.27 179.42,230.27 179.92,229.77 179.92,228.99 179.38,228.45 141.74,228.45 138.45,225.16 138.45,214.93 143.13,210.26 212.36,210.26 215.56,213.45 236,213.45 237.61,215.06 v1(237.61,215.73)
  L05_SIGNAL w0.071: v2(178.5,230.74) 178.03,230.27 177.1,230.27 176.25,231.12 174.25,231.12 173.4,230.27 169.05,230.27 165.3,226.51 107.94,226.51 105.23,223.81 87.37,223.81 84.98,221.42 84.98,208.84 66.65,190.5 66.65,84.66 52.06,70.08 47.29,70.08 45.43,71.94 45.43,74.01 46.56,75.14 47.2,75.14 D126.15
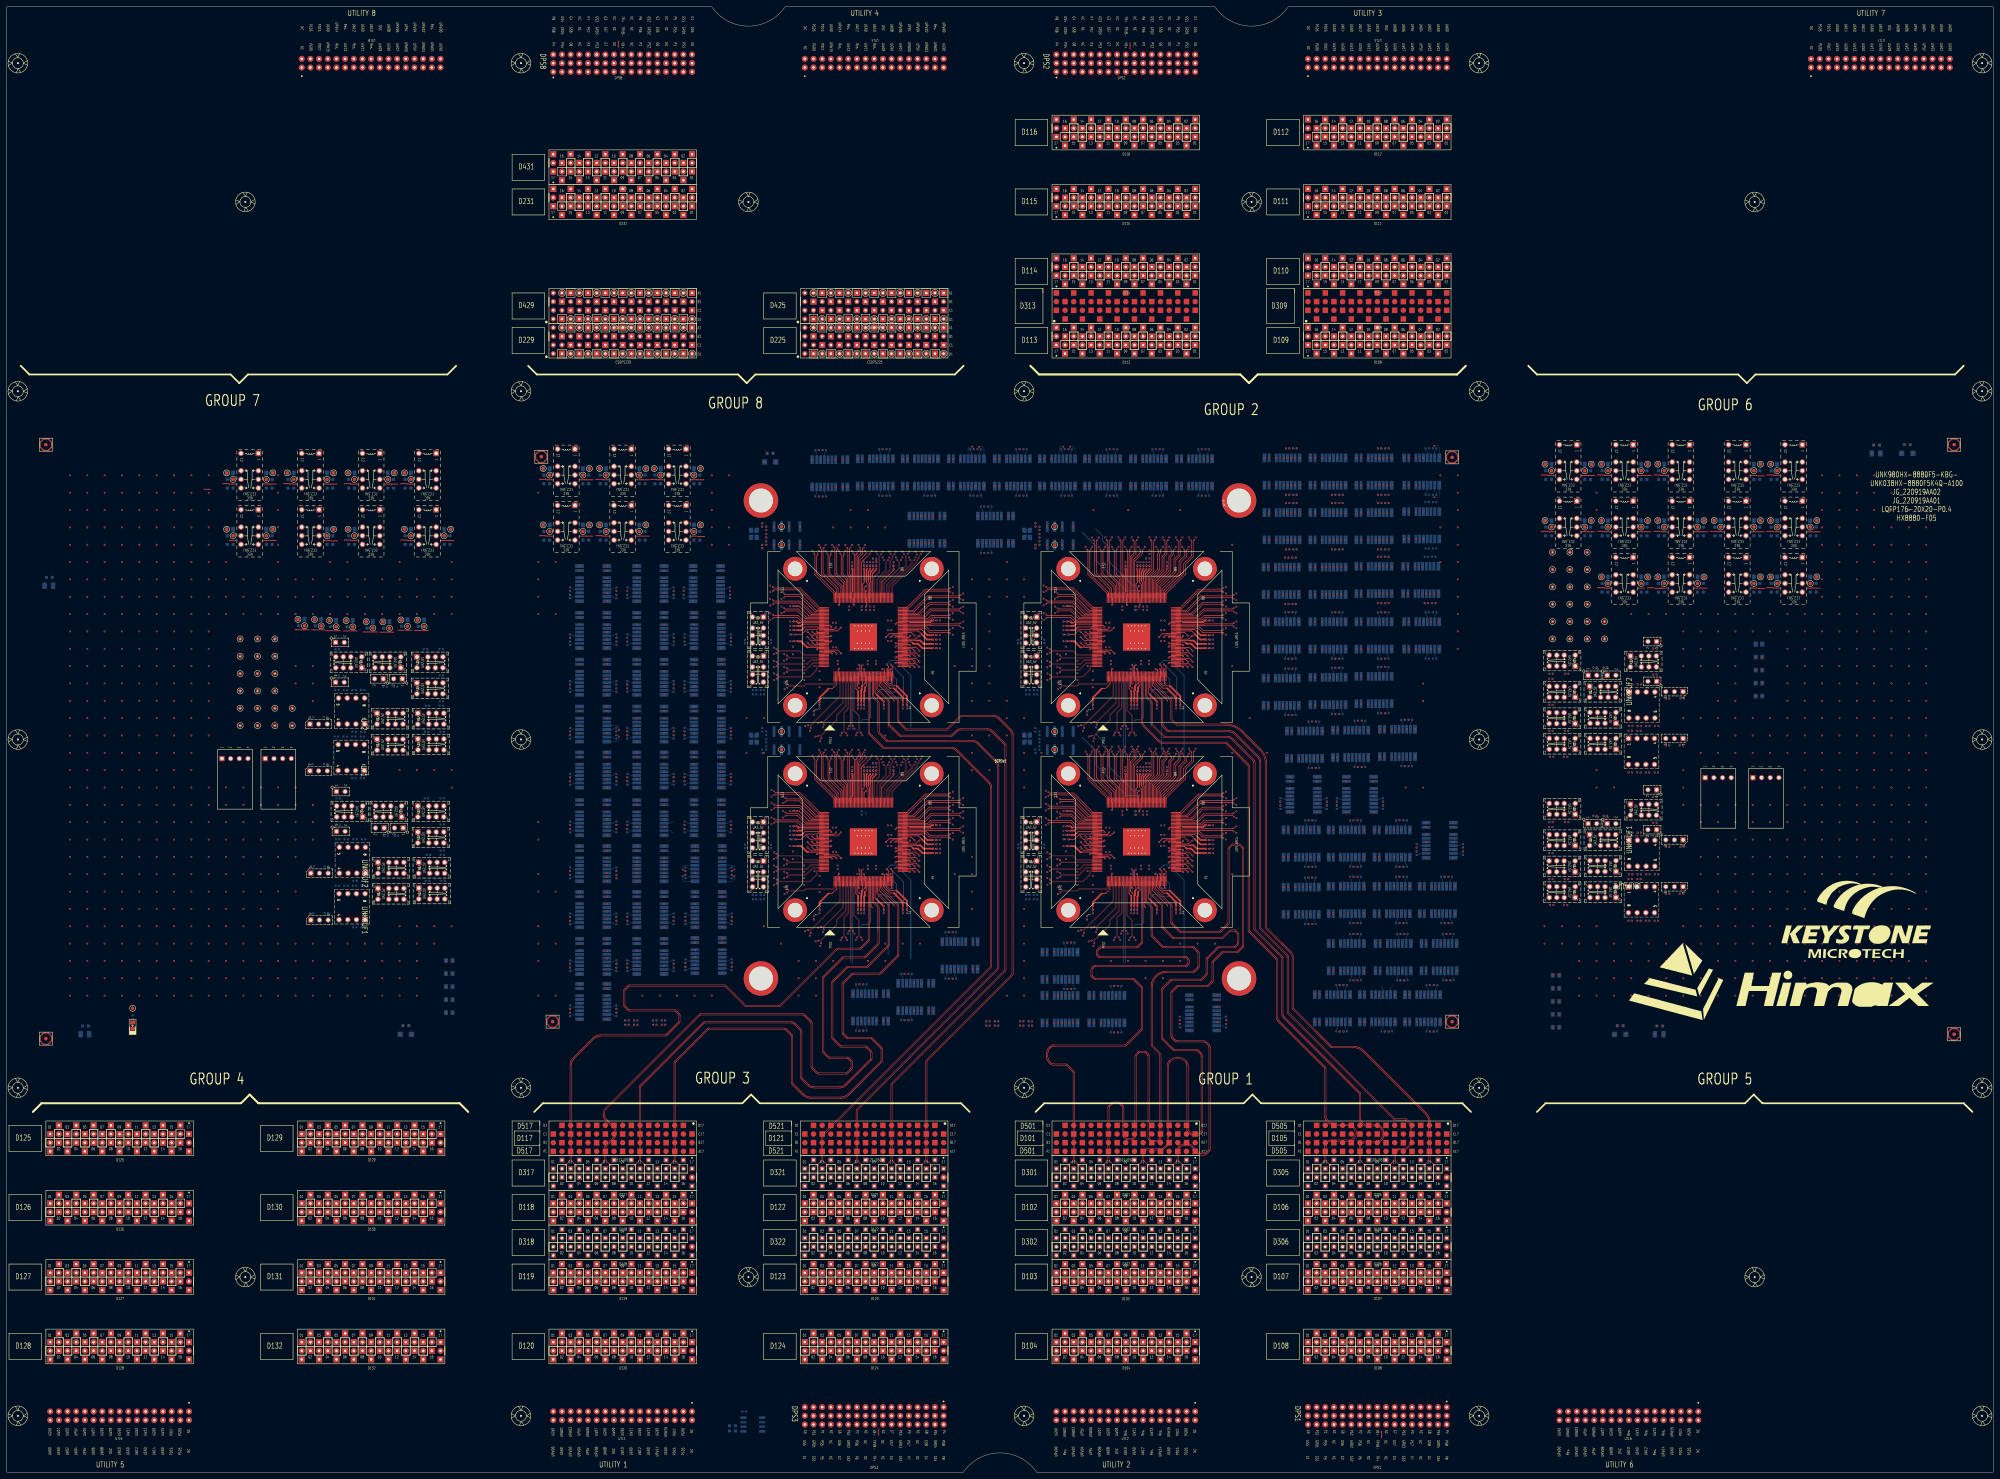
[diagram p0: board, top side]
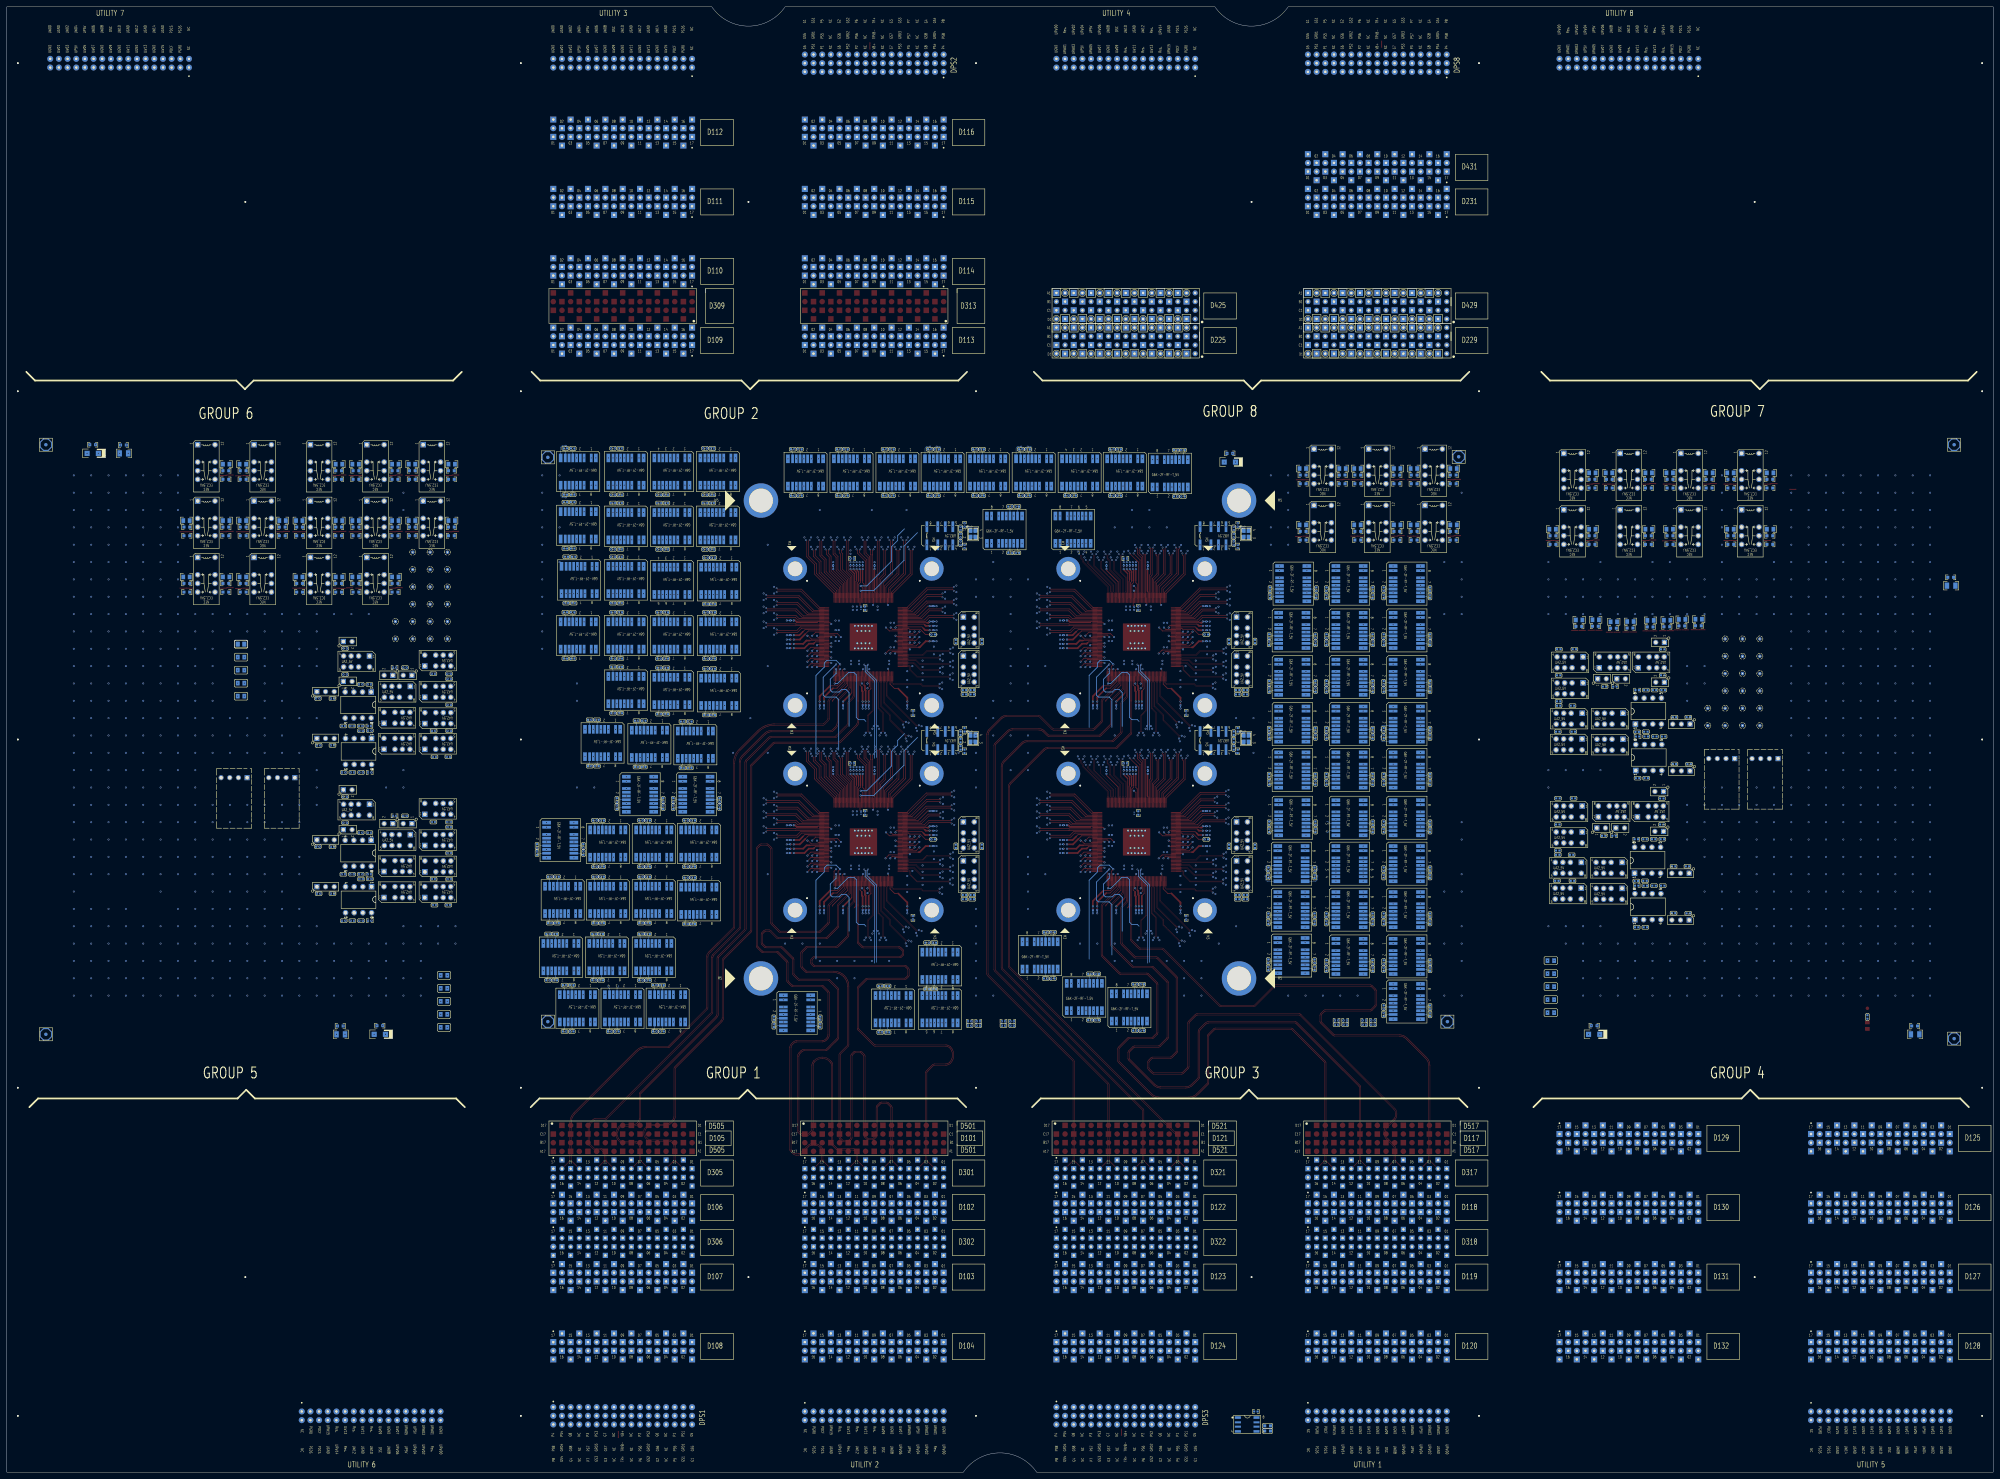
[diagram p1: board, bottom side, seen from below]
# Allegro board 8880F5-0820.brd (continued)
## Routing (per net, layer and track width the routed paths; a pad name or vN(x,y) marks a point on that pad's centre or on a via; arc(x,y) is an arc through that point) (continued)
D12616: length 457
  TOP w0.086: SITE1.11 246.23,231.48 246.31,231.4 246.31,223.82 244.99,222.5 244.99,217.05 v1(244.54,216.6)
  L03_SIGNAL w0.071: v1(244.54,216.6) 245.01,216.12 245.01,214.89 242.78,212.65 221.24,212.65 217.22,208.63 137.3,208.63 131.97,213.97 131.97,228.8 136.8,233.63 165.73,233.63 166.45,232.91 166.45,230.94 165.77,230.27 165.38,230.27 v2(164.91,230.74)
  L05_SIGNAL w0.071: v2(164.91,230.74) 165.38,230.27 165.97,230.27 166.2,230.5 166.2,231.67 165.85,232.02 131.55,232.02 128.71,229.18 87.37,229.18 74.12,215.93 74.12,208.98 55.01,189.86 55.01,128.66 64.37,119.29 64.37,94.37 54.27,84.27 48.42,84.27 46.95,82.8 46.95,80.08 47.2,79.83 49.71,79.83 D126.16
D12901: length 413.5
  TOP w0.086: v1(225.46,173.61) 225.91,173.16 235.09,173.16 237.01,175.08 237.01,175.98 237.38,176.35 237.6,176.35 237.68,176.43 SITE3.175
  L03_SIGNAL w0.071: v1(225.46,173.61) 224.98,173.14 223.77,173.14 222.72,172.09 222.72,170.28 221.85,169.41 213.14,169.41 211.21,171.34 131.92,171.34 131.33,171.93 131.33,173.4 131.81,173.89 171.54,173.89 173.08,172.34 200.78,172.34 201.76,173.32 201.76,174.27 200.38,175.66 199.16,175.66 v1(198.69,176.13)
  L05_SIGNAL w0.071: D129.01 87.74,95.14 89.35,95.14 89.62,94.86 89.62,92.63 87.22,90.23 84.49,90.23 81.33,93.39 81.33,169.51 92.44,180.62 197.15,180.62 200.7,177.07 200.7,176.28 200.08,175.66 199.16,175.66 v1(198.69,176.13)
D12902: length 413.5
  TOP w0.086: v1(228.38,178.12) 228.77,178.5 237.61,178.5 237.68,178.43 SITE3.170
  L03_SIGNAL w0.071: v1(228.38,178.12) 227.91,178.59 223.46,178.59 219.9,182.14 219.9,194.54 213.01,201.43 169.63,201.43 163.65,195.45 163.65,184.64 167.13,181.16 193.04,181.16 196.52,177.68 203.45,177.68 207.44,173.7 213.98,173.7 217.51,177.23 222.18,177.23 224.39,175.01 225.62,175.01 226.3,174.33 226.3,173.39 227.61,172.08 229.38,172.08 229.82,171.64 229.82,170.06 227.88,168.12 225.71,168.12 216.51,158.92 203.24,158.92 200.16,162 199.16,162 v1(198.69,161.52)
  L05_SIGNAL w0.071: v1(198.69,161.52) 199.16,162 199.44,162 199.91,162.47 199.91,168.58 196.26,172.24 162.48,172.24 161.65,173.07 95.9,173.07 87.16,164.33 87.16,111.42 90.85,107.73 90.85,101.01 D129.02
D12903: length 413.5
  TOP w0.086: v1(225.46,172.46) 225.91,172.92 235.19,172.92 237.25,174.98 237.25,175.88 237.48,176.11 237.6,176.11 237.68,176.03 SITE3.176
  L03_SIGNAL w0.071: v1(198.69,174.99) 199.16,175.46 200.29,175.46 201.56,174.19 201.56,173.4 200.7,172.54 173.16,172.54 171.62,174.09 131.73,174.09 131.13,173.49 131.13,171.84 131.84,171.14 211.12,171.14 213.05,169.21 221.93,169.21 222.92,170.2 222.92,172.01 223.85,172.94 224.98,172.94 v1(225.46,172.46)
  L05_SIGNAL w0.071: D129.03 89.82,94.9 89.82,92.55 87.3,90.03 84.4,90.03 81.13,93.3 81.13,169.59 92.36,180.82 197.23,180.82 200.9,177.15 200.9,176.2 200.16,175.46 199.16,175.46 v1(198.69,174.99)
D12904: length 413.5
  TOP w0.086: SITE3.169 237.68,178.83 237.59,178.74 228.9,178.74 v1(228.38,179.26)
  L03_SIGNAL w0.071: v1(228.38,179.26) 227.91,178.79 227.49,178.79 223.54,178.79 220.1,182.23 220.1,194.62 213.09,201.63 169.55,201.63 163.45,195.53 163.45,184.55 167.04,180.96 192.96,180.96 196.43,177.49 203.37,177.49 207.35,173.5 214.06,173.5 217.59,177.03 222.1,177.03 224.31,174.82 225.54,174.82 226.1,174.25 226.1,173.3 227.52,171.88 229.3,171.88 229.62,171.56 229.62,170.14 227.8,168.32 225.63,168.32 216.43,159.12 203.32,159.12 200.24,162.2 199.16,162.2 v1(198.69,162.67)
  L05_SIGNAL w0.071: v1(198.69,162.67) 199.16,162.2 199.35,162.2 199.71,162.55 199.71,168.5 196.18,172.04 162.4,172.04 161.57,172.87 95.99,172.87 87.36,164.24 87.36,111.5 91.05,107.81 91.05,101.09 91.4,100.73 92.31,100.73 D129.04
D12905: length 413.5
  TOP w0.086: v1(225.39,176.18) 225.85,176.63 234.38,176.63 235.46,177.71 237.6,177.71 237.68,177.63 SITE3.172
  L03_SIGNAL w0.071: v1(225.39,176.18) 224.92,176.65 223.64,176.65 222.52,177.77 220.56,177.77 219.7,178.63 219.7,180.12 218.66,181.17 216.8,181.17 215.39,182.58 215.39,194.69 211.11,198.97 169.98,198.97 169.06,198.04 169.06,186.49 171.13,184.42 210.61,184.42 215.24,179.8 215.24,176.44 214.26,175.46 212.75,175.46 v1(212.28,174.99)
  L05_SIGNAL w0.071: D129.05 97.97,95.07 99.02,95.07 99.39,94.69 99.39,91.42 95.17,87.19 81.25,87.19 76.66,91.78 76.66,170.25 91.02,184.61 106.98,184.61 108.95,182.64 203.43,182.64 210.61,175.46 211.81,175.46 v1(212.28,174.99)
D12906: length 413.5
  TOP w0.086: SITE3.174 237.68,176.83 237.6,176.91 236.1,176.91 234.04,174.85 228.85,174.85 v1(228.4,174.39)
  L03_SIGNAL w0.071: v1(181.67,161.52) 182.15,162 183.29,162 185.6,164.3 185.6,165.07 185,165.66 118.89,165.66 118.01,166.54 118.01,205.13 119.16,206.28 222.41,206.28 225.8,202.89 225.8,191.4 228,189.2 228,181.65 229.36,180.29 229.36,177.55 228.92,177.12 227.34,177.12 226.81,176.59 226.81,175.35 227.29,174.87 227.93,174.87 v1(228.4,174.39)
  L05_SIGNAL w0.071: v1(181.67,161.52) 182.15,162 182.72,162 183.11,162.39 183.11,164.34 182.31,165.14 112.74,165.14 100.99,153.39 100.99,100.99 D129.06
D12907: length 413.5
  TOP w0.086: SITE3.171 237.68,178.03 237.6,177.95 235.37,177.95 234.29,176.87 225.85,176.87 v1(225.39,177.32)
  L03_SIGNAL w0.071: v1(212.28,176.13) 212.75,175.66 214.17,175.66 215.04,176.52 215.04,179.71 210.53,184.23 171.04,184.23 168.86,186.41 168.86,198.13 169.9,199.17 211.19,199.17 215.58,194.78 215.58,182.66 216.88,181.36 218.74,181.36 219.9,180.2 219.9,178.71 220.65,177.97 222.6,177.97 223.72,176.85 224.92,176.85 v1(225.39,177.32)
  L05_SIGNAL w0.071: D129.07 99.59,94.51 99.59,91.33 95.25,86.99 81.17,86.99 76.46,91.7 76.46,170.34 90.94,184.81 107.06,184.81 109.04,182.84 203.51,182.84 210.69,175.66 211.81,175.66 v1(212.28,176.13)
D12908: length 413.5
  TOP w0.086: v1(228.4,175.54) 228.85,175.08 233.94,175.08 236,177.15 237.6,177.15 237.68,177.23 SITE3.173
  L03_SIGNAL w0.071: v1(228.4,175.54) 227.93,175.06 227.38,175.06 227.01,175.44 227.01,176.5 227.42,176.92 229,176.92 229.55,177.47 229.55,180.37 228.19,181.73 228.19,189.29 226,191.48 226,202.97 222.5,206.48 119.08,206.48 117.81,205.21 117.81,166.45 118.8,165.46 184.92,165.46 185.4,164.98 185.4,164.38 183.21,162.2 182.15,162.2 v1(181.67,162.67)
  L05_SIGNAL w0.071: v1(181.67,162.67) 182.15,162.2 182.64,162.2 182.91,162.47 182.91,164.26 182.23,164.94 112.82,164.94 101.19,153.31 101.19,101.06 101.69,100.57 102.63,100.57 D129.08
D12909: length 457
  TOP w0.086: v1(245.68,156.6) 245.23,157.05 245.23,162.4 246.55,163.72 246.55,171.4 246.63,171.48 SITE3.12
  L03_SIGNAL w0.071: v1(181.67,147.81) 182.15,148.28 183.55,148.28 186.79,151.52 204.1,151.52 204.88,152.31 204.88,155.03 203.96,155.95 200.04,155.95 199.73,155.64 153.07,155.64 152.53,156.18 152.53,157.23 153,157.69 229.77,157.69 232.07,159.99 235.49,159.99 239.1,163.6 239.1,201.52 240.75,203.17 264.3,203.17 265,202.47 265,163.69 261.92,160.61 244.29,160.61 243.16,159.48 243.16,155.24 243.79,154.6 244.78,154.6 245.21,155.03 245.21,156.12 v1(245.68,156.6)
  L05_SIGNAL w0.071: v1(181.67,147.81) 181.2,148.28 180.2,148.28 177.31,151.16 145.35,151.16 132.5,138.32 132.5,93.61 128.28,89.39 110.78,89.39 108.77,91.4 108.77,94.43 D129.09
D12910: length 413.5
  TOP w0.086: v1(228.51,169.79) 228.97,170.25 233.52,170.25 234.03,170.76 242.13,170.76 242.55,171.18 242.55,171.4 242.63,171.48 SITE3.2
  L03_SIGNAL w0.071: v1(195.26,161.52) 195.73,162 196.56,162 197.16,162.6 197.16,163.97 198.72,165.53 206.84,165.53 212.43,159.94 214.99,159.94 225.32,170.26 228.04,170.26 v1(228.51,169.79)
  L05_SIGNAL w0.071: D129.10 111.59,101.43 111.59,106.32 113.23,107.96 113.23,157.14 112.86,157.51 111.56,157.51 111.06,157.01 111.06,108.91 110.39,108.25 108.83,108.25 107.9,109.18 107.9,153.05 107.39,153.56 106.62,153.56 105.93,152.88 105.93,107.81 105.34,107.22 104.22,107.22 103.53,107.92 103.53,152.49 109.9,158.86 196.59,158.86 197.58,159.85 197.58,161.18 196.76,162 195.73,162 v1(195.26,161.52)
D12911: length 457
  TOP w0.086: SITE3.11 246.23,171.48 246.31,171.4 246.31,163.82 244.99,162.5 244.99,157.05 v1(244.54,156.6)
  L03_SIGNAL w0.071: v1(244.54,156.6) 245.01,156.12 245.01,155.11 244.7,154.8 243.88,154.8 243.36,155.32 243.36,159.4 244.38,160.41 262,160.41 265.2,163.61 265.2,202.55 264.38,203.37 240.67,203.37 238.9,201.6 238.9,163.68 235.4,160.19 231.99,160.19 229.69,157.89 152.91,157.89 152.33,157.31 152.33,156.09 152.99,155.44 199.81,155.44 200.13,155.76 203.88,155.76 204.68,154.95 204.68,152.39 204.02,151.72 186.71,151.72 183.47,148.48 182.15,148.48 v1(181.67,148.95)
  L05_SIGNAL w0.071: v1(181.67,148.95) 181.2,148.48 180.28,148.48 177.4,151.36 145.27,151.36 132.31,138.4 132.31,93.69 128.2,89.59 110.86,89.59 108.96,91.49 108.96,94.36 109.31,94.71 109.95,94.71 D129.11
D12912: length 413.5
  TOP w0.086: SITE3.1 242.23,171.48 242.31,171.4 242.31,171.28 242.03,171 233.93,171 233.42,170.49 228.95,170.49 v1(228.51,170.93)
  L03_SIGNAL w0.071: v1(228.51,170.93) 228.04,170.46 225.24,170.46 214.91,160.13 212.51,160.13 206.92,165.72 198.63,165.72 196.96,164.05 196.96,162.69 196.47,162.2 195.73,162.2 v1(195.26,162.67)
  L05_SIGNAL w0.071: v1(195.26,162.67) 195.73,162.2 196.84,162.2 197.78,161.26 197.78,159.77 196.67,158.66 109.98,158.66 103.72,152.41 103.72,108 104.31,107.42 105.26,107.42 105.73,107.89 105.73,152.96 106.53,153.76 107.47,153.76 108.1,153.13 108.1,109.26 108.91,108.45 110.31,108.45 110.86,109 110.86,157.09 111.48,157.71 112.94,157.71 113.43,157.22 113.43,107.88 111.78,106.23 111.78,101.58 D129.12
D12913: length 457
  TOP w0.086: v1(239.21,158.99) 239.21,159.63 244.95,165.37 244.95,171.4 245.03,171.48 SITE3.8
  L03_SIGNAL w0.071: v1(198.69,148.06) 199.16,148.53 200.53,148.53 201.36,147.7 205.59,147.7 214.52,156.63 230.23,156.63 232.97,159.38 235.43,159.38 237.41,157.4 239.24,157.4 240.12,158.29 240.12,162.24 242.39,164.5 242.39,180.1 242.77,180.49 246.95,180.49 247.77,181.31 247.77,183.6 246.69,184.68 244.75,184.68 244.21,185.21 244.21,186.3 244.91,187 255.87,187 256.69,187.82 256.69,188.89 255.88,189.7 242.76,189.7 242.47,189.99 242.47,190.71 243.04,191.28 262.58,191.28 263.25,191.96 263.25,193.09 262.59,193.75 242.39,193.75 241.83,194.31 241.83,195.44 242.79,196.39 262.66,196.39 263.34,197.07 263.34,198.22 262.87,198.69 241.89,198.69 241.33,199.25 241.33,200.05 241.91,200.62 262.61,200.62 263,201.01 263,201.92 262.54,202.37 241.6,202.37 240.22,200.99 240.22,164.1 236.69,160.57 236.69,159.2 237.32,158.56 238.11,158.56 238.54,158.99 v1(239.21,158.99)
  L05_SIGNAL w0.071: v1(198.69,148.06) 198.22,148.53 197.78,148.53 192.7,153.62 140.72,153.62 129.69,142.58 129.69,94.01 126.98,91.3 119.86,91.3 117.99,93.17 117.99,95.37 D129.13
D12914: length 413.5
  TOP w0.086: v1(225.36,180.02) 225.84,180.5 232.15,180.5 233.34,179.31 237.6,179.31 237.68,179.23 SITE3.168
  L03_SIGNAL w0.071: v1(212.28,161.52) 212.75,162 213.52,162 214.18,162.66 214.18,165.74 212.18,167.73 166.78,167.73 165.04,169.47 123.38,169.47 122.37,170.49 122.37,195.8 130.85,204.28 215.91,204.28 222.75,197.44 222.75,181.89 224.15,180.49 224.89,180.49 v1(225.36,180.02)
  L05_SIGNAL w0.071: D129.14 120.95,100.63 121.22,100.63 122.02,101.43 122.02,145.08 134.32,157.38 210.59,157.38 213.97,160.77 213.97,161.56 213.53,162 212.75,162 v1(212.28,161.52)
D12915: length 457
  TOP w0.086: SITE3.7 244.63,171.48 244.71,171.4 244.71,165.47 239.04,159.8 v1(238.4,159.8)
  L03_SIGNAL w0.071: v1(238.4,159.8) 238.4,159.13 238.03,158.76 237.41,158.76 236.89,159.28 236.89,160.49 240.42,164.02 240.42,200.91 241.68,202.17 262.46,202.17 262.8,201.84 262.8,201.09 262.53,200.82 241.83,200.82 241.14,200.13 241.14,199.16 241.81,198.49 262.79,198.49 263.14,198.14 263.14,197.15 262.58,196.59 242.71,196.59 241.64,195.52 241.64,194.22 242.3,193.56 262.51,193.56 263.06,193.01 263.06,192.04 262.49,191.48 242.95,191.48 242.27,190.8 242.27,189.9 242.67,189.5 255.8,189.5 256.49,188.81 256.49,187.9 255.79,187.2 244.83,187.2 244.02,186.38 244.02,185.13 244.67,184.48 246.61,184.48 247.57,183.51 247.57,181.39 246.87,180.69 242.69,180.69 242.19,180.19 242.19,164.59 239.93,162.32 239.93,158.37 239.15,157.6 237.49,157.6 235.51,159.57 232.89,159.57 230.15,156.83 214.44,156.83 205.51,147.9 201.45,147.9 200.61,148.73 199.16,148.73 v1(198.69,149.21)
  L05_SIGNAL w0.071: v1(198.69,149.21) 198.22,148.73 197.86,148.73 192.78,153.81 140.64,153.81 129.49,142.66 129.49,94.09 126.9,91.5 119.94,91.5 118.19,93.25 118.19,94.37 119.25,95.43 120.83,95.43 D129.15
D12916: length 413.5
  TOP w0.086: SITE3.167 237.68,179.63 237.6,179.55 233.44,179.55 232.25,180.74 225.78,180.74 v1(225.36,181.16)
  L03_SIGNAL w0.071: v1(225.36,181.16) 224.89,180.69 224.23,180.69 222.95,181.97 222.95,197.53 215.99,204.48 130.77,204.48 122.17,195.88 122.17,170.41 123.3,169.27 164.96,169.27 166.69,167.54 212.1,167.54 213.98,165.65 213.98,162.74 213.44,162.2 212.75,162.2 v1(212.28,162.67)
  L05_SIGNAL w0.071: v1(212.28,162.67) 212.75,162.2 213.61,162.2 214.17,161.64 214.17,160.68 210.67,157.19 134.4,157.19 122.22,145 122.22,101.3 D129.16
D13009: length 457
  TOP w0.086: v1(250.13,156.61) 249.68,157.05 249.68,161.65 248.15,163.18 248.15,171.4 248.23,171.48 SITE3.16
  L03_SIGNAL w0.071: v1(164.91,134.6) 165.38,135.07 166.64,135.07 168.58,133.13 168.58,120.69 176.05,113.22 252.63,113.22 253.76,114.34 253.76,115.43 252.83,116.36 175.96,116.36 175.09,117.24 175.09,118.45 175.84,119.2 250.59,119.2 252.18,120.79 252.18,122.86 250.74,124.29 241.95,124.29 239.08,127.16 239.08,133.56 249.66,144.13 249.66,156.13 v1(250.13,156.61)
  L05_SIGNAL w0.071: D130.09 108.85,74.03 108.85,69.49 110.87,67.46 132.85,67.46 143.26,77.87 143.26,129.55 148.78,135.07 164.44,135.07 v1(164.91,134.6)
D13010: length 457
  TOP w0.086: SITE3.10 245.83,171.48 245.75,171.4 245.75,164.32 243.1,161.66 243.1,160.24 238.42,155.56 v1(238.42,154.92)
  L03_SIGNAL w0.071: v1(195.26,147.81) 195.73,148.28 196.56,148.28 196.9,147.94 196.9,145.87 197.42,145.35 209.55,145.35 210.49,144.42 210.49,143.17 209.75,142.43 153.39,142.43 152.28,141.32 152.28,139.16 153.34,138.09 239.09,138.09 240.46,139.47 240.46,140.84 239.87,141.43 228.57,141.43 228.04,141.96 228.04,142.87 228.96,143.78 242.83,143.78 243.35,144.31 243.35,145.43 242.81,145.98 227.85,145.98 227.45,146.38 227.45,147.22 227.76,147.54 245.65,147.54 246.17,148.07 246.17,148.61 245.69,149.09 227.97,149.09 227.49,149.57 227.49,150.9 227.9,151.31 244.87,151.31 245.32,151.76 245.32,152.38 244.85,152.84 237.21,152.84 236.75,153.3 236.75,153.92 237.75,154.92 v1(238.42,154.92)
  L05_SIGNAL w0.071: v1(195.26,147.81) 195.73,148.28 196.05,148.28 196.72,147.61 196.72,146.18 195.01,144.47 144.95,144.47 135.56,135.08 135.56,93.67 130.09,88.2 113.54,88.2 111.61,86.27 111.61,81.13 D130.10
D13011: length 457
  TOP w0.086: SITE3.15 247.83,171.48 247.91,171.4 247.91,163.08 249.45,161.55 249.45,157.06 v1(248.99,156.61)
  L03_SIGNAL w0.071: v1(164.91,135.74) 165.38,135.27 166.73,135.27 168.78,133.22 168.78,120.77 176.13,113.41 252.55,113.41 253.56,114.42 253.56,115.35 252.75,116.16 175.88,116.16 174.89,117.15 174.89,118.53 175.76,119.4 250.51,119.4 251.98,120.88 251.98,122.77 250.66,124.1 241.86,124.1 238.88,127.08 238.88,133.64 249.46,144.22 249.46,156.13 v1(248.99,156.61)
  L05_SIGNAL w0.071: D130.11 110.56,75 109.79,75 109.05,74.25 109.05,69.57 110.95,67.66 132.77,67.66 143.06,77.96 143.06,129.63 148.7,135.27 164.44,135.27 v1(164.91,135.74)
D13012: length 457
  TOP w0.086: v1(237.61,155.73) 238.25,155.73 242.86,160.34 242.86,161.76 245.51,164.41 245.51,171.4 245.43,171.48 SITE3.9
  L03_SIGNAL w0.071: v1(195.26,148.95) 195.73,148.48 196.64,148.48 197.1,148.02 197.1,145.95 197.5,145.55 209.64,145.55 210.68,144.5 210.68,143.08 209.83,142.23 153.47,142.23 152.48,141.24 152.48,139.24 153.43,138.29 239,138.29 240.27,139.55 240.27,140.76 239.79,141.23 228.49,141.23 227.84,141.87 227.84,142.95 228.87,143.98 242.74,143.98 243.15,144.39 243.15,145.35 242.73,145.78 227.77,145.78 227.25,146.3 227.25,147.31 227.68,147.74 245.56,147.74 245.98,148.15 245.98,148.53 245.61,148.89 227.89,148.89 227.3,149.49 227.3,150.98 227.82,151.51 244.78,151.51 245.12,151.85 245.12,152.29 244.77,152.64 237.13,152.64 236.55,153.22 236.55,154 237.61,155.06 v1(237.61,155.73)
  L05_SIGNAL w0.071: v1(195.26,148.95) 195.73,148.48 196.13,148.48 196.92,147.69 196.92,146.1 195.1,144.27 145.04,144.27 135.76,134.99 135.76,93.59 130.17,88 113.62,88 111.8,86.18 111.8,81.24 D130.12
D13013: length 457
  TOP w0.086: v1(247.8,158.55) 247.35,159 247.35,171.4 247.43,171.48 SITE3.14
  L03_SIGNAL w0.071: v1(178.5,134.6) 178.97,135.07 198.26,135.07 199.66,133.67 199.66,131.37 198.21,129.92 172.89,129.92 171.98,129.01 171.98,127.89 173.18,126.69 233.89,126.69 234.87,125.71 234.87,124.62 233.36,123.11 172.58,123.11 171.88,122.41 171.88,121.18 172.77,120.28 248.69,120.28 249.36,120.95 249.36,122.51 248.86,123.01 239.37,123.01 236.59,125.78 236.59,133.82 247.33,144.55 247.33,158.07 v1(247.8,158.55)
  L05_SIGNAL w0.071: D130.13 118.93,74.11 118.93,71.28 120.69,69.52 128.8,69.52 140.53,81.26 140.53,130.59 150.58,140.63 171.01,140.63 176.57,135.07 178.03,135.07 v1(178.5,134.6)
D13014: length 457
  TOP w0.086: SITE3.6 244.23,171.48 244.15,171.4 244.15,167.37 235.41,158.63 v1(235.41,157.99)
  L03_SIGNAL w0.071: v1(235.41,157.99) 234.74,157.99 232.54,155.79 220.92,155.79 213.66,148.53 212.75,148.53 v1(212.28,148.06)
  L05_SIGNAL w0.071: v1(212.28,148.06) 212.75,148.53 213.7,148.53 214.39,147.85 214.39,122.61 208.99,117.21 148.27,117.21 147.61,117.87 147.61,119.39 148.38,120.15 197.05,120.15 198.25,121.35 198.25,124.62 196.94,125.92 150.98,125.92 149.97,126.93 149.97,127.91 150.75,128.69 205.88,128.69 208.22,131.02 208.22,134.16 199.98,142.41 147.33,142.41 138.29,133.36 138.29,93.15 131.57,86.44 122.77,86.44 121.78,85.45 121.78,81.14 D130.14
D13015: length 457
  TOP w0.086: v1(246.65,158.55) 247.11,159 247.11,171.4 247.03,171.48 SITE3.13
  L03_SIGNAL w0.071: v1(246.65,158.55) 247.13,158.07 247.13,144.64 236.39,133.9 236.39,125.7 239.28,122.81 248.78,122.81 249.16,122.43 249.16,121.03 248.61,120.48 172.86,120.48 172.07,121.26 172.07,122.33 172.66,122.91 233.44,122.91 235.07,124.54 235.07,125.79 233.97,126.89 173.26,126.89 172.18,127.97 172.18,128.93 172.98,129.73 198.29,129.73 199.86,131.29 199.86,133.75 198.34,135.27 178.97,135.27 v1(178.5,135.74)
  L05_SIGNAL w0.071: D130.15 120.1,74.38 119.47,74.38 119.13,74.04 119.13,71.37 120.78,69.72 128.71,69.72 140.34,81.34 140.34,130.67 150.5,140.83 171.09,140.83 176.65,135.27 178.03,135.27 v1(178.5,135.74)
D13016: length 457
  TOP w0.086: SITE3.5 243.83,171.48 243.91,171.4 243.91,167.47 235.24,158.8 v1(234.6,158.8)
  L03_SIGNAL w0.071: v1(234.6,158.8) 234.6,158.13 232.46,155.99 220.83,155.99 213.58,148.73 212.75,148.73 v1(212.28,149.21)
  L05_SIGNAL w0.071: v1(212.28,149.21) 212.75,148.73 213.78,148.73 214.59,147.93 214.59,122.53 209.08,117.02 148.19,117.02 147.41,117.79 147.41,119.47 148.29,120.35 196.96,120.35 198.05,121.44 198.05,124.54 196.86,125.72 150.9,125.72 149.77,126.85 149.77,127.99 150.66,128.88 205.8,128.88 208.02,131.11 208.02,134.08 199.89,142.21 147.41,142.21 138.49,133.28 138.49,93.07 131.65,86.24 122.85,86.24 121.98,85.36 121.98,81.22 D130.16
D30102: length 192.4
  TOP w0.147: D301.02 312.03,91.05 arc(312.19,91.29) 312.25,91.58 312.25,116.97 arc(312.22,117.14) 312.12,117.29 310.35,119.06 arc(310.2,119.16) 310.03,119.19 306.77,119.19 arc(305.98,119.35) 305.31,119.79 arc(304.64,120.8) 304.41,121.98 304.41,122.42 arc(304.64,123.59) 305.3,124.58 arc(305.96,125.02) 306.73,125.17 327.35,125.17 arc(327.48,125.19) 327.59,125.27 332.14,129.81 arc(332.21,129.92) 332.24,130.05 332.24,141.72 arc(332.21,141.85) 332.14,141.96 329.88,144.21 arc(329.77,144.29) 329.64,144.31 318.73,144.31 arc(318.45,144.37) 318.21,144.53 317.64,145.1 arc(317.48,145.34) 317.42,145.62 317.42,147.18 arc(317.48,147.47) 317.64,147.71 318.17,148.24 arc(318.41,148.4) 318.69,148.46 345.06,148.46 arc(345.2,148.48) 345.31,148.56 345.76,149.02 arc(345.84,149.13) 345.86,149.26 345.86,149.96 arc(345.84,150.09) 345.76,150.2 345.36,150.6 arc(345.25,150.68) 345.12,150.7 320.15,150.7 arc(319.87,150.76) 319.63,150.92 319.24,151.31 arc(319.08,151.55) 319.02,151.83 319.02,152.56 arc(319.08,152.84) 319.24,153.08 319.91,153.75 arc(320.15,153.91) 320.43,153.97 330.85,153.97 arc(330.98,154) 331.09,154.07 332.14,155.11 arc(332.21,155.22) 332.24,155.35 332.24,165.77 332.23,166.13 SITE4.26
D30104: length 192.4
  TOP w0.147: D301.04 312.86,91 arc(312.7,91.24) 312.65,91.52 312.65,116.97 arc(312.58,117.29) 312.4,117.57 310.63,119.34 arc(310.35,119.52) 310.03,119.59 306.77,119.59 arc(306.13,119.71) 305.59,120.07 arc(305.01,120.95) 304.8,121.98 304.8,122.42 arc(305,123.43) 305.58,124.3 305.58,124.3 arc(306.11,124.65) 306.73,124.77 327.35,124.77 arc(327.63,124.83) 327.87,124.99 332.42,129.53 arc(332.58,129.77) 332.63,130.05 332.63,141.72 arc(332.58,142) 332.42,142.24 330.16,144.49 arc(329.93,144.65) 329.64,144.71 318.73,144.71 arc(318.6,144.74) 318.49,144.81 317.92,145.38 arc(317.84,145.49) 317.82,145.62 317.82,147.18 arc(317.84,147.32) 317.92,147.43 318.45,147.96 arc(318.56,148.04) 318.69,148.06 345.06,148.06 arc(345.35,148.12) 345.59,148.28 346.05,148.74 arc(346.2,148.98) 346.26,149.26 346.26,149.96 arc(346.2,150.24) 346.05,150.48 345.64,150.88 arc(345.4,151.04) 345.12,151.1 320.15,151.1 arc(320.02,151.13) 319.91,151.2 319.52,151.59 arc(319.44,151.7) 319.42,151.83 319.42,152.56 arc(319.44,152.69) 319.52,152.8 320.19,153.47 arc(320.3,153.55) 320.43,153.57 330.85,153.57 arc(331.14,153.63) 331.37,153.79 332.42,154.83 arc(332.58,155.07) 332.63,155.35 332.63,165.77 332.63,166.13 SITE4.27
D30106: length 192.4
  TOP w0.147: D301.06 322.18,91.04 arc(322.34,91.28) 322.4,91.57 322.4,106.79 arc(322.46,107.07) 322.62,107.31 323.51,108.21 arc(323.75,108.37) 324.03,108.42 325.53,108.42 arc(325.82,108.37) 326.06,108.21 326.88,107.38 arc(327.04,107.14) 327.1,106.86 327.1,98.81 arc(327.12,98.68) 327.2,98.57 327.88,97.89 arc(327.99,97.81) 328.12,97.79 329.43,97.79 arc(329.56,97.81) 329.67,97.89 330.23,98.45 arc(330.31,98.56) 330.33,98.69 330.33,121.86 arc(330.39,122.14) 330.55,122.38 331.24,123.08 arc(331.48,123.24) 331.77,123.29 333.2,123.29 arc(333.49,123.24) 333.73,123.08 334.33,122.47 arc(334.49,122.23) 334.55,121.95 334.55,97.92 arc(334.57,97.79) 334.65,97.68 335.06,97.27 arc(335.17,97.19) 335.3,97.17 336.66,97.17 arc(336.79,97.19) 336.9,97.27 337.48,97.85 arc(337.56,97.96) 337.58,98.09 337.58,122.26 arc(337.56,122.39) 337.48,122.5 335.3,124.68 arc(335.14,124.92) 335.08,125.2 335.08,142.32 arc(335.42,144.02) 336.38,145.46 arc(337.83,146.43) 339.53,146.76 347.37,146.76 arc(347.5,146.79) 347.61,146.86 348.68,147.94 arc(348.76,148.05) 348.78,148.18 348.78,152.07 arc(348.76,152.18) 348.7,152.27 347.39,153.58 arc(347.3,153.64) 347.19,153.66 338.93,153.66 arc(338.45,153.75) 338.05,154.03 335.45,156.62 arc(335.18,157.03) 335.08,157.51 335.08,165.24 arc(335.06,165.37) 334.98,165.48 333.43,167.03 SITE4.29
D30108: length 192.4
  TOP w0.147: D301.08 322.89,91.13 arc(322.82,91.23) 322.8,91.35 322.8,106.79 arc(322.82,106.92) 322.9,107.03 323.79,107.93 arc(323.9,108) 324.03,108.03 325.53,108.03 arc(325.66,108) 325.78,107.93 326.6,107.1 arc(326.67,106.99) 326.7,106.86 326.7,98.81 arc(326.76,98.53) 326.92,98.29 327.6,97.61 arc(327.84,97.45) 328.12,97.39 329.43,97.39 arc(329.71,97.45) 329.95,97.61 330.51,98.17 arc(330.67,98.41) 330.73,98.69 330.73,121.86 arc(330.76,121.99) 330.83,122.1 331.53,122.8 arc(331.64,122.87) 331.77,122.9 333.2,122.9 arc(333.33,122.87) 333.44,122.8 334.05,122.19 arc(334.13,122.08) 334.15,121.95 334.15,97.92 arc(334.21,97.64) 334.37,97.4 334.78,96.98 arc(335.02,96.83) 335.3,96.77 336.66,96.77 arc(336.94,96.83) 337.18,96.98 337.76,97.57 arc(337.92,97.81) 337.98,98.09 337.98,122.26 arc(337.92,122.54) 337.76,122.78 335.58,124.96 arc(335.51,125.07) 335.48,125.2 335.48,142.32 arc(335.79,143.87) 336.66,145.18 336.66,145.18 arc(337.98,146.06) 339.53,146.37 347.37,146.37 arc(347.65,146.42) 347.89,146.58 348.96,147.66 arc(349.12,147.9) 349.18,148.18 349.18,152.07 arc(349.13,152.33) 348.98,152.55 347.67,153.86 arc(347.45,154) 347.19,154.06 338.93,154.06 arc(338.6,154.12) 338.33,154.31 335.73,156.9 arc(335.54,157.18) 335.48,157.51 335.48,165.24 arc(335.42,165.52) 335.26,165.76 333.83,167.19 SITE4.30
D30110: length 192.4
  TOP w0.147: SITE4.32 334.63,169.52 337.99,166.16 arc(338.07,166.05) 338.09,165.92 338.09,159.95 arc(338.15,159.67) 338.31,159.43 341.26,156.48 arc(341.5,156.32) 341.78,156.26 355.79,156.26 arc(356.07,156.32) 356.31,156.48 358.2,158.36 arc(358.31,158.44) 358.44,158.46 359.45,158.46 arc(359.59,158.44) 359.7,158.36 360.28,157.78 arc(360.36,157.67) 360.38,157.54 360.38,155.05 arc(360.36,154.92) 360.28,154.81 359.57,154.1 arc(359.46,154.02) 359.33,154 354.98,154 arc(354.7,153.94) 354.46,153.78 351.38,150.7 arc(351.22,150.46) 351.16,150.18 351.16,146.06 arc(351.14,145.93) 351.06,145.82 349.78,144.53 arc(349.67,144.46) 349.54,144.43 341.17,144.43 arc(340.89,144.38) 340.65,144.22 338.31,141.88 arc(338.15,141.64) 338.09,141.36 338.09,127.26 arc(338.15,126.98) 338.31,126.74 341.36,123.69 arc(341.6,123.53) 341.88,123.47 348.09,123.47 arc(348.51,123.39) 348.87,123.15 349.4,122.62 arc(349.64,122.26) 349.72,121.84 349.72,100.01 arc(349.7,99.88) 349.62,99.77 348.98,99.13 arc(348.87,99.06) 348.74,99.03 347.25,99.03 arc(347.12,99.06) 347.01,99.13 346.03,100.11 arc(345.96,100.22) 345.93,100.35 345.93,119.08 arc(345.77,119.88) 345.32,120.56 arc(344.17,121.33) 342.82,121.59 arc(341.59,121.35) 340.55,120.65 340.32,120.43 arc(339.94,119.85) 339.8,119.17 339.8,96.27 arc(339.78,96.14) 339.7,96.03 338.52,94.85 arc(338.41,94.78) 338.28,94.75 333.83,94.75 arc(333.46,94.68) 333.14,94.47 332.83,94.16 arc(332.62,93.84) 332.55,93.47 332.55,91.55 arc(332.49,91.27) 332.33,91.03 D301.10
D30112: length 192.4
  TOP w0.147: SITE4.33 335.03,169.68 338.27,166.44 arc(338.43,166.2) 338.49,165.92 338.49,159.95 arc(338.51,159.82) 338.59,159.71 341.54,156.76 arc(341.65,156.68) 341.78,156.66 355.79,156.66 arc(355.92,156.68) 356.03,156.76 357.92,158.64 arc(358.16,158.8) 358.44,158.86 359.45,158.86 arc(359.74,158.8) 359.98,158.64 360.56,158.06 arc(360.72,157.82) 360.78,157.54 360.78,155.05 arc(360.72,154.77) 360.56,154.53 359.85,153.82 arc(359.61,153.66) 359.33,153.6 354.98,153.6 arc(354.85,153.58) 354.74,153.5 351.66,150.42 arc(351.59,150.31) 351.56,150.18 351.56,146.06 arc(351.5,145.78) 351.34,145.54 350.06,144.25 arc(349.82,144.09) 349.54,144.04 341.17,144.04 arc(341.04,144.01) 340.93,143.94 338.59,141.6 arc(338.51,141.49) 338.49,141.36 338.49,127.26 arc(338.51,127.13) 338.59,127.02 341.64,123.97 arc(341.75,123.89) 341.88,123.87 348.09,123.87 arc(348.66,123.75) 349.15,123.43 349.68,122.9 arc(350,122.41) 350.12,121.84 350.12,100.01 arc(350.06,99.73) 349.9,99.49 349.26,98.85 arc(349.02,98.69) 348.74,98.64 347.25,98.64 arc(346.96,98.69) 346.72,98.85 345.75,99.83 arc(345.59,100.07) 345.54,100.35 345.54,119.08 arc(345.41,119.73) 345.04,120.28 345.04,120.28 arc(344.02,120.96) 342.82,121.2 arc(341.74,120.98) 340.83,120.37 340.6,120.15 arc(340.3,119.7) 340.2,119.17 340.2,96.27 arc(340.14,95.99) 339.98,95.75 338.8,94.57 arc(338.56,94.41) 338.28,94.36 333.83,94.36 arc(333.61,94.31) 333.42,94.19 333.11,93.88 arc(332.99,93.69) 332.94,93.47 332.94,91.54 arc(333,91.26) 333.16,91.02 D301.12
D30114: length 192.4
  TOP w0.147: D301.14 342.46,91 arc(342.62,91.24) 342.68,91.52 342.68,94.14 arc(342.8,94.78) 343.17,95.32 343.3,95.45 arc(344.15,96.02) 345.15,96.22 345.87,96.22 arc(346.51,96.09) 347.06,95.73 349.25,93.54 arc(349.56,93.33) 349.94,93.26 350.46,93.26 arc(350.84,93.33) 351.16,93.54 351.91,94.3 arc(351.99,94.41) 352.01,94.54 352.01,124.32 arc(351.92,124.81) 351.64,125.21 351.2,125.66 arc(350.8,125.93) 350.31,126.02 342.93,126.02 arc(342.25,126.16) 341.68,126.54 341.33,126.89 arc(340.95,127.46) 340.81,128.14 340.81,140.4 arc(340.87,140.68) 341.03,140.92 342.51,142.4 arc(342.75,142.56) 343.03,142.62 351.47,142.62 arc(351.6,142.64) 351.71,142.72 352.79,143.8 arc(352.87,143.91) 352.89,144.04 352.89,149.24 arc(352.95,149.52) 353.11,149.76 355.72,152.37 arc(355.96,152.53) 356.24,152.59 360.21,152.59 arc(360.34,152.61) 360.45,152.69 361.68,153.92 arc(361.76,154.03) 361.78,154.16 361.78,182.66 arc(361.76,182.79) 361.68,182.9 361.03,183.55 arc(360.92,183.63) 360.79,183.65 359.08,183.65 arc(358.95,183.63) 358.84,183.55 358.07,182.79 arc(358,182.68) 357.97,182.55 357.97,160.96 arc(357.92,160.68) 357.76,160.44 355.62,158.3 arc(355.38,158.14) 355.1,158.08 343.81,158.08 arc(343.52,158.14) 343.28,158.3 341.03,160.55 arc(340.87,160.79) 340.81,161.08 340.81,165.84 arc(340.79,165.97) 340.71,166.08 336.05,170.75 arc(335.89,170.99) 335.83,171.27 SITE4.35
D30116: length 192.4
  TOP w0.147: SITE4.36 336.23,171.43 arc(336.29,171.15) 336.45,170.91 340.99,166.36 arc(341.15,166.12) 341.21,165.84 341.21,161.08 arc(341.24,160.94) 341.31,160.83 343.57,158.58 arc(343.68,158.5) 343.81,158.48 355.1,158.48 arc(355.23,158.5) 355.34,158.58 357.48,160.72 arc(357.55,160.83) 357.58,160.96 357.58,182.55 arc(357.63,182.83) 357.79,183.07 358.56,183.83 arc(358.8,183.99) 359.08,184.05 360.79,184.05 arc(361.07,183.99) 361.31,183.83 361.96,183.18 arc(362.12,182.94) 362.18,182.66 362.18,154.16 arc(362.12,153.87) 361.96,153.64 360.73,152.41 arc(360.5,152.25) 360.21,152.19 356.24,152.19 arc(356.11,152.17) 356,152.09 353.39,149.48 arc(353.31,149.37) 353.29,149.24 353.29,144.04 arc(353.23,143.75) 353.07,143.52 351.99,142.44 arc(351.75,142.28) 351.47,142.22 343.03,142.22 arc(342.9,142.19) 342.79,142.12 341.31,140.64 arc(341.24,140.53) 341.21,140.4 341.21,128.14 arc(341.31,127.62) 341.61,127.17 341.96,126.82 arc(342.4,126.53) 342.93,126.42 350.31,126.42 arc(350.95,126.29) 351.48,125.94 351.93,125.49 arc(352.28,124.96) 352.41,124.32 352.41,94.54 arc(352.35,94.26) 352.19,94.02 351.44,93.26 arc(350.99,92.96) 350.46,92.86 349.94,92.86 arc(349.41,92.96) 348.97,93.26 346.78,95.45 arc(346.36,95.73) 345.87,95.83 345.15,95.83 arc(344.3,95.66) 343.58,95.17 343.45,95.04 arc(343.17,94.63) 343.07,94.14 343.07,91.57 arc(343.13,91.29) 343.29,91.05 D301.16
D30502: length 192.4
  TOP w0.147: D305.02 385.68,91.04 arc(385.84,91.28) 385.9,91.57 385.9,95.38 arc(386.05,96.12) 386.47,96.75 386.47,96.75 arc(387.1,97.17) 387.84,97.32 393.4,97.32 arc(393.53,97.35) 393.65,97.42 394.24,98.02 arc(394.84,99.46) 394.24,100.9 394.02,101.11 arc(393.62,101.39) 393.13,101.48 388.64,101.48 arc(387.92,101.63) 387.31,102.03 386.45,102.89 arc(386.04,103.5) 385.9,104.22 385.9,118.28 arc(385.89,118.34) 385.86,118.38 372.28,131.96 arc(371.91,132.51) 371.78,133.17 371.78,150 arc(371.76,150.13) 371.68,150.24 371.68,150.24 363.71,158.21 arc(363.55,158.45) 363.49,158.73 363.49,206.87 arc(363.48,206.93) 363.45,206.98 357.01,213.42 arc(356.96,213.46) 356.9,213.47 338.51,213.47 arc(337.87,213.6) 337.32,213.96 332.73,218.55 arc(332.36,219.1) 332.24,219.75 332.24,225.77 332.23,226.13 SITE2.26
D30504: length 192.4
  TOP w0.147: D305.04 386.51,91.01 arc(386.35,91.25) 386.3,91.53 386.3,95.38 arc(386.41,95.97) 386.75,96.47 386.75,96.47 arc(387.25,96.81) 387.84,96.93 393.4,96.93 arc(393.69,96.98) 393.93,97.14 394.52,97.74 arc(395.23,99.46) 394.52,101.18 394.3,101.39 arc(393.77,101.75) 393.13,101.88 388.64,101.88 arc(388.07,101.99) 387.59,102.32 386.73,103.17 arc(386.41,103.65) 386.3,104.22 386.3,118.28 arc(386.26,118.49) 386.14,118.66 372.56,132.24 arc(372.28,132.66) 372.18,133.17 372.18,150 arc(372.12,150.28) 371.96,150.52 363.99,158.49 arc(363.92,158.6) 363.89,158.73 363.89,206.87 arc(363.85,207.08) 363.73,207.26 357.29,213.7 arc(357.11,213.82) 356.9,213.86 338.52,213.86 arc(338.02,213.96) 337.6,214.24 333.01,218.83 arc(332.73,219.25) 332.63,219.75 332.63,225.77 332.63,226.13 SITE2.27
D30506: length 192.4
  TOP w0.147: D305.06 395.82,91.02 arc(395.98,91.26) 396.04,91.54 396.04,95.33 arc(396.13,95.78) 396.38,96.16 396.73,96.51 arc(397.11,96.76) 397.56,96.85 401.55,96.85 arc(401.68,96.88) 401.8,96.95 402.33,97.48 arc(402.64,97.96) 402.76,98.52 402.76,99.48 arc(402.59,100.32) 402.11,101.04 arc(401.76,101.28) 401.34,101.36 398.42,101.36 arc(397.52,101.54) 396.76,102.05 396.73,102.08 arc(396.22,102.84) 396.04,103.74 396.04,110.81 arc(396.03,110.86) 396,110.91 373.82,133.09 arc(373.43,133.66) 373.3,134.34 373.3,150.63 arc(373.27,150.76) 373.2,150.87 365.31,158.76 arc(365.19,158.94) 365.15,159.14 365.15,207.91 arc(365.11,208.12) 364.98,208.31 358.44,214.85 arc(358.11,215.07) 357.73,215.15 339.12,215.15 arc(338.91,215.19) 338.73,215.3 335.34,218.7 arc(335.15,218.98) 335.08,219.32 335.08,225.24 arc(335.06,225.37) 334.98,225.48 333.65,226.82 arc(333.49,227.06) 333.43,227.34 SITE2.29
D30508: length 192.4
  TOP w0.147: SITE2.30 333.83,227.5 arc(333.89,227.22) 334.05,226.98 335.26,225.76 arc(335.42,225.52) 335.48,225.24 335.48,219.32 arc(335.52,219.14) 335.62,218.98 339.02,215.59 arc(339.06,215.55) 339.12,215.54 357.73,215.54 arc(358.27,215.44) 358.72,215.13 365.26,208.59 arc(365.47,208.28) 365.55,207.91 365.55,159.14 arc(365.56,159.09) 365.59,159.04 373.48,151.15 arc(373.64,150.91) 373.7,150.63 373.7,134.34 arc(373.8,133.82) 374.1,133.37 396.28,111.19 arc(396.39,111.02) 396.44,110.81 396.44,103.74 arc(396.58,102.99) 397.01,102.36 397.04,102.33 arc(397.67,101.9) 398.42,101.75 401.34,101.75 arc(401.91,101.64) 402.39,101.32 402.39,101.32 arc(402.95,100.47) 403.15,99.48 403.15,98.52 arc(403.01,97.81) 402.61,97.2 402.08,96.67 arc(401.84,96.51) 401.55,96.45 397.56,96.45 arc(397.26,96.39) 397.01,96.23 396.66,95.88 arc(396.49,95.63) 396.44,95.33 396.44,91.55 arc(396.49,91.27) 396.65,91.03 D305.08
D30510: length 192.4
  TOP w0.147: D305.10 406.01,91.05 arc(406.17,91.29) 406.22,91.57 406.22,93.28 arc(406.28,93.57) 406.44,93.81 407.31,94.68 arc(407.55,94.84) 407.83,94.89 409.51,94.89 arc(409.64,94.92) 409.75,94.99 410.8,96.04 arc(410.98,96.31) 411.04,96.63 411.04,101.37 arc(410.98,101.68) 410.8,101.95 409.71,103.04 arc(409.6,103.11) 409.47,103.14 406.62,103.14 arc(406.33,103.2) 406.09,103.36 375.09,134.36 arc(374.97,134.54) 374.93,134.75 374.93,150.68 arc(374.84,151.09) 374.61,151.45 366.96,159.1 arc(366.84,159.28) 366.8,159.48 366.8,208.02 arc(366.64,208.82) 366.19,209.49 359.52,216.16 arc(358.72,216.7) 357.78,216.88 340.37,216.88 arc(339.95,216.97) 339.58,217.21 338.91,217.89 arc(338.3,218.79) 338.09,219.86 338.09,225.92 arc(338.07,226.05) 337.99,226.16 334.85,229.3 arc(334.69,229.54) 334.63,229.82 SITE2.32
D30512: length 192.4
  TOP w0.147: D305.12 406.68,91.16 arc(406.64,91.23) 406.62,91.31 406.62,93.28 arc(406.64,93.41) 406.72,93.52 407.59,94.4 arc(407.7,94.47) 407.83,94.5 409.51,94.5 arc(409.79,94.55) 410.03,94.71 411.08,95.76 arc(411.35,96.16) 411.44,96.63 411.44,101.37 arc(411.35,101.84) 411.08,102.23 409.99,103.32 arc(409.75,103.48) 409.47,103.54 406.62,103.54 arc(406.49,103.56) 406.38,103.64 375.37,134.64 arc(375.34,134.69) 375.32,134.75 375.32,150.68 arc(375.21,151.25) 374.89,151.73 367.24,159.38 arc(367.21,159.43) 367.2,159.48 367.2,208.02 arc(367.01,208.97) 366.47,209.77 359.8,216.44 arc(358.87,217.06) 357.78,217.28 340.37,217.28 arc(340.1,217.33) 339.86,217.49 339.19,218.17 arc(338.67,218.94) 338.49,219.86 338.49,225.92 arc(338.43,226.2) 338.27,226.44 335.25,229.46 arc(335.09,229.7) 335.03,229.98 SITE2.33
D30514: length 192.4
  TOP w0.147: D305.14 416.17,91.05 arc(416.33,91.29) 416.39,91.57 416.39,102.39 arc(416.11,103.8) 415.3,105 397.03,123.27 arc(395.83,124.07) 394.42,124.36 388,124.36 arc(387.79,124.4) 387.61,124.52 376.53,135.6 arc(376.41,135.78) 376.37,135.99 376.37,150.95 arc(376.25,151.52) 375.93,152 368.66,159.27 arc(368.54,159.45) 368.5,159.66 368.5,207.66 arc(368.09,209.73) 366.92,211.48 361.51,216.89 arc(359.4,218.3) 356.91,218.8 342.63,218.8 arc(342.42,218.84) 342.24,218.96 341.03,220.17 arc(340.87,220.41) 340.81,220.69 340.81,225.84 arc(340.79,225.97) 340.71,226.08 335.83,230.97 SITE2.35
D30516: length 192.4
  TOP w0.147: SITE2.36 336.23,231.13 340.99,226.36 arc(341.15,226.12) 341.21,225.84 341.21,220.69 arc(341.24,220.56) 341.31,220.45 342.52,219.24 arc(342.57,219.21) 342.63,219.19 356.91,219.19 arc(359.55,218.67) 361.79,217.17 367.2,211.76 arc(368.46,209.88) 368.9,207.66 368.9,159.66 arc(368.91,159.6) 368.94,159.55 376.21,152.28 arc(376.62,151.67) 376.76,150.95 376.76,135.99 arc(376.78,135.93) 376.81,135.88 387.89,124.8 arc(387.94,124.76) 388,124.75 394.42,124.75 arc(395.98,124.44) 397.31,123.55 415.59,105.28 arc(416.47,103.95) 416.78,102.39 416.78,91.32 arc(416.8,91.22) 416.86,91.14 D305.16
D31702: length 192.4
  TOP w0.147: D317.02 164.71,91.05 arc(164.87,91.29) 164.93,91.57 164.93,119.14 arc(165.18,120.4) 165.9,121.48 171.59,127.17 arc(172.66,127.89) 173.93,128.14 192.8,128.14 arc(192.93,128.16) 193.04,128.24 196.65,131.85 arc(196.73,131.96) 196.75,132.09 196.75,133.84 arc(196.73,133.97) 196.65,134.08 195.76,134.97 arc(195.65,135.04) 195.52,135.07 182.42,135.07 arc(182.14,135.13) 181.9,135.29 180.82,136.37 arc(180.66,136.61) 180.6,136.89 180.6,140.98 arc(180.66,141.26) 180.82,141.5 181.86,142.54 arc(182.1,142.7) 182.38,142.76 210.07,142.76 arc(210.35,142.7) 210.59,142.54 216.3,136.84 arc(216.41,136.76) 216.54,136.74 226.13,136.74 arc(226.26,136.76) 226.38,136.84 242.85,153.31 arc(243.09,153.47) 243.37,153.53 249.68,153.53 arc(249.81,153.55) 249.92,153.63 252.14,155.84 arc(252.21,155.95) 252.24,156.08 252.24,165.77 252.23,166.13 SITE3.26
D31704: length 192.4
  TOP w0.147: D317.04 165.54,91 arc(165.38,91.24) 165.33,91.52 165.33,119.14 arc(165.55,120.25) 166.18,121.2 171.87,126.89 arc(172.81,127.52) 173.93,127.74 192.8,127.74 arc(193.09,127.8) 193.33,127.96 196.93,131.57 arc(197.09,131.81) 197.15,132.09 197.15,133.84 arc(197.09,134.12) 196.93,134.36 196.04,135.25 arc(195.81,135.41) 195.52,135.47 182.42,135.47 arc(182.29,135.49) 182.18,135.57 181.1,136.65 arc(181.02,136.76) 181,136.89 181,140.98 arc(181.02,141.11) 181.1,141.22 182.14,142.26 arc(182.25,142.34) 182.38,142.36 210.07,142.36 arc(210.2,142.34) 210.31,142.26 216.02,136.56 arc(216.26,136.4) 216.54,136.34 226.13,136.34 arc(226.42,136.4) 226.66,136.56 243.13,153.03 arc(243.24,153.1) 243.37,153.13 249.68,153.13 arc(249.96,153.18) 250.2,153.34 252.42,155.56 arc(252.58,155.8) 252.63,156.08 252.63,165.77 252.63,166.13 SITE3.27
D31706: length 192.4
  TOP w0.147: 178.04,99.44 178.04,99.44 178.04,99.44 178.04,99.44 ; 178.04,99.44 arc(177.86,98.56) 177.37,97.82 175.25,95.7 arc(175.09,95.46) 175.03,95.18 175.03,91.52 arc(174.98,91.24) 174.82,91 D317.06 ; 178.04,99.44 arc(177.86,100.31) 177.37,101.06 175.25,103.18 arc(174.79,103.86) 174.63,104.67 174.63,105.13 arc(174.79,105.94) 175.25,106.62 202.72,134.09 arc(202.96,134.25) 203.24,134.31 233.07,134.31 arc(233.4,134.24) 233.68,134.06 235.61,132.13 arc(235.8,131.85) 235.86,131.51 235.86,118.79 arc(235.89,118.66) 235.96,118.55 237.42,117.09 arc(237.53,117.01) 237.67,116.99 245.73,116.99 arc(245.86,117.01) 245.97,117.09 247.12,118.24 arc(247.19,118.35) 247.22,118.48 247.22,120.08 arc(247.19,120.21) 247.12,120.32 246.32,121.11 arc(246.21,121.19) 246.08,121.21 240.95,121.21 arc(240.66,121.27) 240.42,121.43 239.06,122.79 arc(238.9,123.03) 238.84,123.32 238.84,144.74 arc(238.9,145.02) 239.06,145.26 244.58,150.77 arc(244.82,150.93) 245.1,150.99 251.03,150.99 arc(251.16,151.02) 251.27,151.09 254.98,154.8 arc(255.06,154.91) 255.08,155.04 255.08,165.24 arc(255.06,165.37) 254.98,165.48 253.65,166.82 arc(253.49,167.06) 253.43,167.34 SITE3.29
D31708: length 192.4
  TOP w0.147: D317.08 175.64,91.06 arc(175.49,91.29) 175.43,91.58 175.43,95.18 arc(175.45,95.31) 175.53,95.42 177.65,97.54 arc(178.23,98.41) 178.43,99.44 arc(178.23,100.47) 177.65,101.34 175.53,103.46 arc(175.16,104.02) 175.02,104.67 175.02,105.12 arc(175.16,105.78) 175.53,106.34 203,133.81 arc(203.11,133.89) 203.24,133.91 233.07,133.91 arc(233.25,133.88) 233.4,133.78 235.33,131.85 arc(235.43,131.69) 235.46,131.51 235.46,118.79 arc(235.52,118.51) 235.68,118.27 237.14,116.81 arc(237.38,116.65) 237.67,116.59 245.73,116.59 arc(246.01,116.65) 246.25,116.81 247.4,117.96 arc(247.56,118.19) 247.61,118.48 247.61,120.08 arc(247.56,120.36) 247.4,120.6 246.6,121.39 arc(246.36,121.55) 246.08,121.61 240.95,121.61 arc(240.81,121.64) 240.7,121.71 239.34,123.07 arc(239.27,123.19) 239.24,123.32 239.24,144.74 arc(239.27,144.87) 239.34,144.98 244.86,150.49 arc(244.97,150.57) 245.1,150.59 251.03,150.59 arc(251.32,150.65) 251.55,150.81 255.26,154.52 arc(255.42,154.76) 255.48,155.04 255.48,165.24 arc(255.42,165.52) 255.26,165.76 254.05,166.98 arc(253.89,167.22) 253.83,167.5 SITE3.30
D31710: length 192.4
  TOP w0.147: SITE3.32 254.63,169.82 arc(254.69,169.54) 254.85,169.3 257.99,166.16 arc(258.07,166.05) 258.09,165.92 258.09,154.6 arc(258.07,154.47) 257.99,154.36 251.93,148.3 arc(251.82,148.22) 251.69,148.2 246.35,148.2 arc(246.07,148.14) 245.83,147.98 241.72,143.87 arc(241.56,143.63) 241.5,143.35 241.5,127.4 arc(241.56,127.12) 241.72,126.88 243.91,124.69 arc(244.15,124.53) 244.43,124.48 251.4,124.48 arc(251.53,124.45) 251.64,124.38 252.88,123.14 arc(252.95,123.03) 252.98,122.9 252.98,121.24 arc(252.95,121.11) 252.88,121 245.52,113.64 arc(244.72,113.11) 243.77,112.92 236.45,112.92 arc(235.5,113.11) 234.7,113.64 232.92,115.42 arc(232.84,115.53) 232.82,115.66 232.82,128.9 arc(232.7,129.48) 232.37,129.98 230.81,131.54 arc(230.31,131.87) 229.72,131.99 204.41,131.99 arc(204.13,131.93) 203.89,131.77 185.41,113.29 arc(185.25,113.05) 185.19,112.77 185.19,91.52 arc(185.14,91.24) 184.98,91 D317.10
D31712: length 192.4
  TOP w0.147: SITE3.33 255.03,169.98 arc(255.09,169.7) 255.25,169.46 258.27,166.44 arc(258.43,166.2) 258.49,165.92 258.49,154.6 arc(258.43,154.32) 258.27,154.08 252.21,148.02 arc(251.98,147.86) 251.69,147.8 246.35,147.8 arc(246.22,147.78) 246.11,147.7 242,143.59 arc(241.93,143.48) 241.9,143.35 241.9,127.4 arc(241.93,127.27) 242,127.16 244.19,124.97 arc(244.3,124.9) 244.43,124.87 251.4,124.87 arc(251.68,124.82) 251.92,124.66 253.16,123.42 arc(253.32,123.18) 253.37,122.9 253.37,121.24 arc(253.32,120.96) 253.16,120.72 245.8,113.36 arc(244.87,112.74) 243.77,112.52 236.45,112.52 arc(235.35,112.74) 234.42,113.36 232.63,115.14 arc(232.47,115.38) 232.42,115.66 232.42,128.9 arc(232.33,129.33) 232.09,129.7 230.53,131.26 arc(230.16,131.5) 229.72,131.59 204.41,131.59 arc(204.28,131.56) 204.17,131.49 185.69,113.01 arc(185.61,112.9) 185.59,112.77 185.59,91.58 arc(185.65,91.29) 185.8,91.06 D317.12
D31714: length 192.4
  TOP w0.147: D317.14 195.15,91.01 arc(195.31,91.25) 195.37,91.53 195.37,119.88 arc(195.42,120.16) 195.58,120.4 205.07,129.89 arc(205.31,130.05) 205.59,130.1 227.74,130.1 arc(228.03,130.05) 228.27,129.89 229.88,128.28 arc(230.04,128.04) 230.09,127.75 230.09,114.12 arc(230.12,113.99) 230.19,113.88 233.24,110.83 arc(234.29,110.13) 235.53,109.88 244.09,109.88 arc(245.33,110.13) 246.38,110.83 255.89,120.34 arc(255.96,120.45) 255.99,120.58 255.99,123.96 arc(255.96,124.09) 255.89,124.2 253.17,126.92 arc(253.06,126.99) 252.93,127.02 246.3,127.02 arc(246.02,127.07) 245.78,127.23 244.79,128.22 arc(244.63,128.46) 244.58,128.74 244.58,142.95 arc(244.63,143.23) 244.79,143.47 247.32,146 arc(247.56,146.16) 247.85,146.22 255.49,146.22 arc(255.62,146.24) 255.73,146.32 260.71,151.3 arc(260.79,151.41) 260.81,151.55 260.81,165.84 arc(260.79,165.97) 260.71,166.08 256.05,170.75 arc(255.89,170.99) 255.83,171.27 SITE3.35
D31716: length 192.4
  TOP w0.147: D317.16 195.98,91.04 arc(195.82,91.28) 195.76,91.56 195.76,119.88 arc(195.79,120.01) 195.86,120.12 205.35,129.61 arc(205.46,129.68) 205.59,129.71 227.74,129.71 arc(227.87,129.68) 227.99,129.61 229.6,127.99 arc(229.67,127.88) 229.7,127.75 229.7,114.12 arc(229.75,113.83) 229.91,113.6 232.96,110.55 arc(234.14,109.76) 235.53,109.48 244.09,109.48 arc(245.48,109.76) 246.66,110.55 256.17,120.06 arc(256.33,120.3) 256.38,120.58 256.38,123.96 arc(256.33,124.24) 256.17,124.48 253.45,127.2 arc(253.21,127.36) 252.93,127.41 246.3,127.41 arc(246.17,127.44) 246.06,127.51 245.07,128.5 arc(245,128.61) 244.97,128.74 244.97,142.95 arc(245,143.08) 245.07,143.19 247.6,145.72 arc(247.72,145.8) 247.85,145.82 255.49,145.82 arc(255.77,145.88) 256.01,146.04 260.99,151.02 arc(261.15,151.26) 261.21,151.55 261.21,165.84 arc(261.15,166.12) 260.99,166.36 256.45,170.91 arc(256.29,171.15) 256.23,171.43 SITE3.36
D32102: length 192.4
  TOP w0.147: D321.02 238.34,91.02 arc(238.5,91.26) 238.55,91.54 238.55,98.33 arc(238.61,98.62) 238.77,98.85 287.92,148 arc(287.99,148.12) 288.02,148.25 288.02,200.69 arc(287.91,201.25) 287.59,201.73 277.8,211.51 arc(277.33,211.83) 276.76,211.95 256.98,211.95 arc(256.7,212) 256.46,212.16 252.45,216.17 arc(252.29,216.41) 252.24,216.69 252.24,225.77 252.23,226.13 SITE1.26
D32104: length 192.4
  TOP w0.147: D321.04 239.17,91.03 arc(239.01,91.27) 238.95,91.55 238.95,98.33 arc(238.98,98.46) 239.05,98.57 288.2,147.72 arc(288.36,147.96) 288.42,148.25 288.42,200.69 arc(288.27,201.4) 287.87,202.01 278.08,211.79 arc(277.48,212.2) 276.76,212.34 256.98,212.34 arc(256.85,212.37) 256.74,212.44 252.73,216.45 arc(252.66,216.56) 252.63,216.69 252.63,225.77 252.63,226.13 SITE1.27
D32106: length 192.4
  TOP w0.147: D321.06 248.49,91.01 arc(248.65,91.25) 248.7,91.53 248.7,105.91 arc(248.76,106.19) 248.92,106.43 290,147.51 arc(290.07,147.62) 290.1,147.75 290.1,206.74 arc(289.95,207.46) 289.55,208.07 284.21,213.4 arc(283.6,213.81) 282.89,213.95 258.01,213.95 arc(257.73,214.01) 257.49,214.17 255.3,216.36 arc(255.14,216.6) 255.08,216.88 255.08,225.24 arc(255.06,225.37) 254.98,225.48 253.65,226.82 arc(253.49,227.06) 253.43,227.34 SITE1.29
D32108: length 192.4
  TOP w0.147: D321.08 249.31,91.05 arc(249.15,91.28) 249.1,91.57 249.1,105.91 arc(249.12,106.04) 249.2,106.15 290.28,147.23 arc(290.44,147.47) 290.49,147.75 290.49,206.74 arc(290.32,207.61) 289.83,208.35 284.49,213.68 arc(283.75,214.18) 282.89,214.35 258.01,214.35 arc(257.88,214.37) 257.77,214.45 255.58,216.64 arc(255.51,216.75) 255.48,216.88 255.48,225.24 arc(255.42,225.52) 255.26,225.76 254.05,226.98 arc(253.89,227.22) 253.83,227.5 SITE1.30
D32110: length 192.4
  TOP w0.147: D321.10 258.64,91 arc(258.8,91.24) 258.86,91.52 258.86,113.47 arc(258.92,113.75) 259.08,113.99 292.12,147.04 arc(292.2,147.15) 292.22,147.28 292.22,212.89 arc(292.2,213.02) 292.12,213.13 288.36,216.89 arc(287.77,217.29) 287.07,217.43 279.44,217.43 arc(278.74,217.29) 278.15,216.89 276.99,215.73 arc(276.75,215.57) 276.47,215.52 261.78,215.52 arc(261.5,215.57) 261.26,215.73 258.31,218.69 arc(258.15,218.93) 258.09,219.21 258.09,225.72 arc(258.07,225.85) 257.99,225.96 254.63,229.32 SITE1.32
D32112: length 192.4
  TOP w0.147: SITE1.33 255.03,233.13 255.03,229.48 258.27,226.24 arc(258.43,226) 258.49,225.72 258.49,219.21 arc(258.51,219.08) 258.59,218.97 261.54,216.01 arc(261.65,215.94) 261.78,215.91 276.47,215.91 arc(276.6,215.94) 276.71,216.01 277.87,217.17 arc(278.59,217.65) 279.44,217.82 287.07,217.82 arc(287.92,217.65) 288.64,217.17 292.4,213.41 arc(292.56,213.17) 292.62,212.89 292.62,147.28 arc(292.56,147) 292.4,146.76 259.36,113.71 arc(259.28,113.6) 259.26,113.47 259.26,91.57 arc(259.31,91.29) 259.47,91.05 D321.12
D32114: length 192.4
  TOP w0.147: SITE1.35 255.83,230.97 260.71,226.08 arc(260.79,225.97) 260.81,225.84 260.81,220.11 arc(260.87,219.83) 261.03,219.59 263.07,217.55 arc(263.31,217.39) 263.59,217.33 275.07,217.33 arc(275.36,217.39) 275.59,217.55 279.25,221.2 arc(279.36,221.28) 279.49,221.3 289.01,221.3 arc(289.71,221.16) 290.3,220.77 293.79,217.28 arc(294.18,216.69) 294.32,215.99 294.32,145.98 arc(294.29,145.85) 294.22,145.74 269.26,120.78 arc(269.1,120.54) 269.05,120.26 269.05,91.55 arc(268.99,91.27) 268.83,91.03 D321.14
D32116: length 192.4
  TOP w0.147: SITE1.36 256.23,231.13 260.99,226.36 arc(261.15,226.12) 261.21,225.84 261.21,220.11 arc(261.24,219.98) 261.31,219.87 263.35,217.83 arc(263.46,217.75) 263.59,217.73 275.07,217.73 arc(275.2,217.75) 275.31,217.83 278.97,221.48 arc(279.21,221.64) 279.49,221.7 289.01,221.7 arc(289.86,221.53) 290.58,221.05 294.07,217.56 arc(294.55,216.84) 294.72,215.99 294.72,145.98 arc(294.66,145.69) 294.5,145.46 269.54,120.5 arc(269.47,120.39) 269.44,120.26 269.44,91.54 arc(269.5,91.26) 269.66,91.02 D321.16
Net_1: length 2
  TOP w0.231: v1(229.4,185.39) 229.91,185.39 ; v1(309.4,185.39) 309.91,185.39 ; v1(229.4,245.39) 229.91,245.39 ; v1(309.4,245.39) 309.91,245.39
  vias: v1(223.55,259.7) v1(223.55,257.77) v1(223.55,255.84) v1(223.55,253.92) v1(223.55,251.61) v1(223.55,249.68) v1(223.92,199.85) v1(223.92,197.92) v1(223.92,195.99) v1(223.92,194.06) v1(223.92,191.75) v1(223.92,189.82) v1(224.6,241.56) v1(224.6,239.63) v1(224.64,237.71) v1(224.64,235.78) v1(224.6,181.56) v1(224.6,179.63) v1(224.64,177.71) v1(224.64,175.78) v1(224.7,234) v1(224.7,232.07) v1(224.7,174) v1(224.7,172.07) v1(226.85,257.77) v1(226.85,255.84) v1(226.85,253.53) v1(226.85,251.61) v1(227.22,197.92) v1(227.22,195.99) v1(227.22,193.68) v1(227.22,191.75) v1(227.63,239.65) v1(227.63,237.72) v1(227.65,235.93) v1(227.65,234) v1(227.63,179.65) v1(227.63,177.72) v1(227.65,175.93) v1(227.65,174) v1(227.75,231.32) v1(227.75,229.39) v1(227.75,171.32) v1(227.75,169.39) v1(230.19,241.84) v1(230.19,239.59) v1(230.19,181.84) v1(230.19,179.59) v1(233.79,218.54) v1(233.79,158.54) v1(235.15,217.18) v1(235.15,157.18) v1(235.89,269.91) v1(235.89,209.91) v1(236.8,215.47) v1(236.8,155.47) v1(237.59,219.55) v1(237.59,159.55) v1(237.82,271.63) v1(237.82,269.91) v1(237.82,211.63) v1(237.82,209.91) v1(238.17,214.11) v1(238.17,154.11) v1(238.96,218.18) v1(238.96,158.18) v1(239.75,271.63) v1(239.75,269.91) v1(239.75,211.63) v1(239.75,209.91) v1(241.68,271.63) v1(241.68,269.91) v1(241.68,211.63) v1(241.68,209.91) v1(243.61,271.63) v1(243.61,269.91) v1(243.61,211.63) v1(243.61,209.91) v1(244.15,215.84) v1(244.15,155.84) v1(245.54,271.63) v1(245.54,269.91) v1(245.54,211.63) v1(245.54,209.91) v1(246.08,215.84) v1(246.08,155.84) v1(246.26,217.79) v1(246.26,157.79) v1(247.47,271.63) v1(247.47,269.91) v1(247.47,211.63) v1(247.47,209.91) v1(248.19,217.79) v1(248.19,157.79) v1(248.6,215.85) v1(248.6,155.85) v1(249.39,271.63) v1(249.39,269.91) v1(249.39,211.63) v1(249.39,209.91) v1(250.53,215.85) v1(250.53,155.85) v1(251.32,271.63) v1(251.32,269.91) v1(251.32,211.63) v1(251.32,209.91) v1(253.25,269.91) v1(253.25,209.91) v1(254.53,269.69) v1(254.53,209.69) v1(256.46,269.69) v1(256.46,267.97) v1(256.46,209.69) v1(256.46,207.97) v1(258.39,269.69) v1(258.39,267.97) v1(258.39,209.69) v1(258.39,207.97) v1(260.32,269.69) v1(260.32,267.97) v1(260.32,209.69) v1(260.32,207.97) v1(262.25,269.69) v1(262.25,267.97) v1(262.25,209.69) v1(262.25,207.97) v1(264.18,269.69) v1(264.18,267.97) v1(264.18,209.69) v1(264.18,207.97) v1(266.11,269.69) v1(266.11,267.97) v1(266.11,209.69) v1(266.11,207.97) v1(268.04,269.69) v1(268.04,209.69) v1(277,259.34) v1(277,257.41) v1(277,255.48) v1(277,253.56) v1(277,251.63) v1(277,249.7) v1(277,247.27) v1(277,245.34) v1(277,199.34) v1(277,197.41) v1(277,195.49) v1(277,193.56) v1(277,191.63) v1(277,189.7) v1(277,187.27) v1(277,185.34) v1(280.05,257.41) v1(280.05,255.48) v1(280.05,253.56) v1(280.05,251.63) v1(280.05,249.19) v1(280.05,247.27) v1(280.05,197.41) v1(280.05,195.49) v1(280.05,193.56) v1(280.05,191.63) v1(280.05,189.19) v1(280.05,187.27) v1(303.6,259.74) v1(303.6,257.81) v1(303.6,255.88) v1(303.6,253.95) v1(303.6,251.64) v1(303.6,249.71) v1(304.23,199.64) v1(304.23,197.71) v1(304.23,195.78) v1(304.23,193.85) v1(304.23,191.54) v1(304.23,189.61) v1(304.6,241.56) v1(304.6,239.63) v1(304.64,237.71) v1(304.64,235.78) v1(304.6,181.56) v1(304.6,179.63) v1(304.64,177.71) v1(304.64,175.78) v1(304.7,234) v1(304.7,232.07) v1(304.7,174) v1(304.7,172.07) v1(306.9,257.81) v1(306.9,255.88) v1(306.9,253.57) v1(306.9,251.64) v1(307.53,197.71) v1(307.53,195.78) v1(307.53,193.47) v1(307.53,191.54) v1(307.63,239.65) v1(307.63,237.72) v1(307.65,235.93) v1(307.65,234) v1(307.63,179.65) v1(307.63,177.72) v1(307.65,175.93) v1(307.65,174) v1(307.75,231.32) v1(307.75,229.39) v1(307.75,171.32) v1(307.75,169.39) v1(310.19,241.84) v1(310.19,239.59) v1(310.19,181.84) v1(310.19,179.59) v1(313.79,218.54) v1(313.79,158.54) v1(315.15,217.18) v1(315.15,157.18) v1(315.89,271.09) v1(315.89,211.09) v1(316.8,215.47) v1(316.8,155.47) v1(317.59,219.55) v1(317.59,159.55) v1(317.82,273.82) v1(317.82,271.09) v1(317.82,212.55) v1(317.82,211.09) v1(318.16,214.11) v1(318.16,154.11) v1(318.95,218.18) v1(318.95,158.18) v1(319.75,273.82) v1(319.75,271.09) v1(319.75,212.55) v1(319.75,211.09) v1(321.68,273.82) v1(321.68,271.09) v1(321.68,212.55) v1(321.68,211.09) v1(323.61,273.82) v1(323.61,271.09) v1(323.61,212.55) v1(323.61,211.09) v1(324.15,215.84) v1(324.15,155.84) v1(325.54,273.82) v1(325.54,271.09) v1(325.54,212.55) v1(325.54,211.09) v1(326.08,215.84) v1(326.08,155.84) v1(326.26,217.79) v1(326.26,157.79) v1(327.47,273.82) v1(327.47,271.09) v1(327.47,212.55) v1(327.47,211.09) v1(328.19,217.79) v1(328.19,157.79) v1(328.6,215.85) v1(328.6,155.85) v1(329.39,273.82) v1(329.39,271.09) v1(329.39,212.55) v1(329.39,211.09) v1(330.53,215.85) v1(330.53,155.85) v1(331.32,273.82) v1(331.32,271.09) v1(331.32,212.55) v1(331.32,211.09) v1(333.25,271.09) v1(333.25,211.09) v1(334.6,273.82) v1(334.61,270.04) v1(334.61,269.03) v1(334.62,211.96) v1(336.53,273.82) v1(336.53,271.09) v1(336.55,211.96) v1(336.55,210.5) v1(338.46,273.82) v1(338.46,271.09) v1(338.48,211.96) v1(338.48,210.5) v1(340.39,273.82) v1(340.39,271.09) v1(340.41,211.96) v1(340.41,210.5) v1(342.32,273.82) v1(342.32,271.09) v1(342.34,211.96) v1(342.34,210.5) v1(344.25,273.82) v1(344.25,271.09) v1(344.27,211.96) v1(344.27,210.5) v1(346.18,273.82) v1(346.18,271.09) v1(346.2,211.96) v1(346.2,210.5) v1(348.11,273.82) v1(348.13,211.96) v1(357,259.34) v1(357,257.41) v1(357,255.48) v1(357,253.56) v1(357,251.63) v1(357,249.7) v1(357,247.27) v1(357,245.34) v1(357,199.34) v1(357,197.41) v1(357,195.49) v1(357,193.56) v1(357,191.63) v1(357,189.7) v1(357,187.27) v1(357,185.34) v1(360.05,257.41) v1(360.05,255.48) v1(360.05,253.56) v1(360.05,251.63) v1(360.05,249.19) v1(360.05,247.27) v1(360.05,197.41) v1(360.05,195.49) v1(360.05,193.56) v1(360.05,191.63) v1(360.05,189.19) v1(360.05,187.27) v2(260.71,207.21) v2(319.35,273.07)
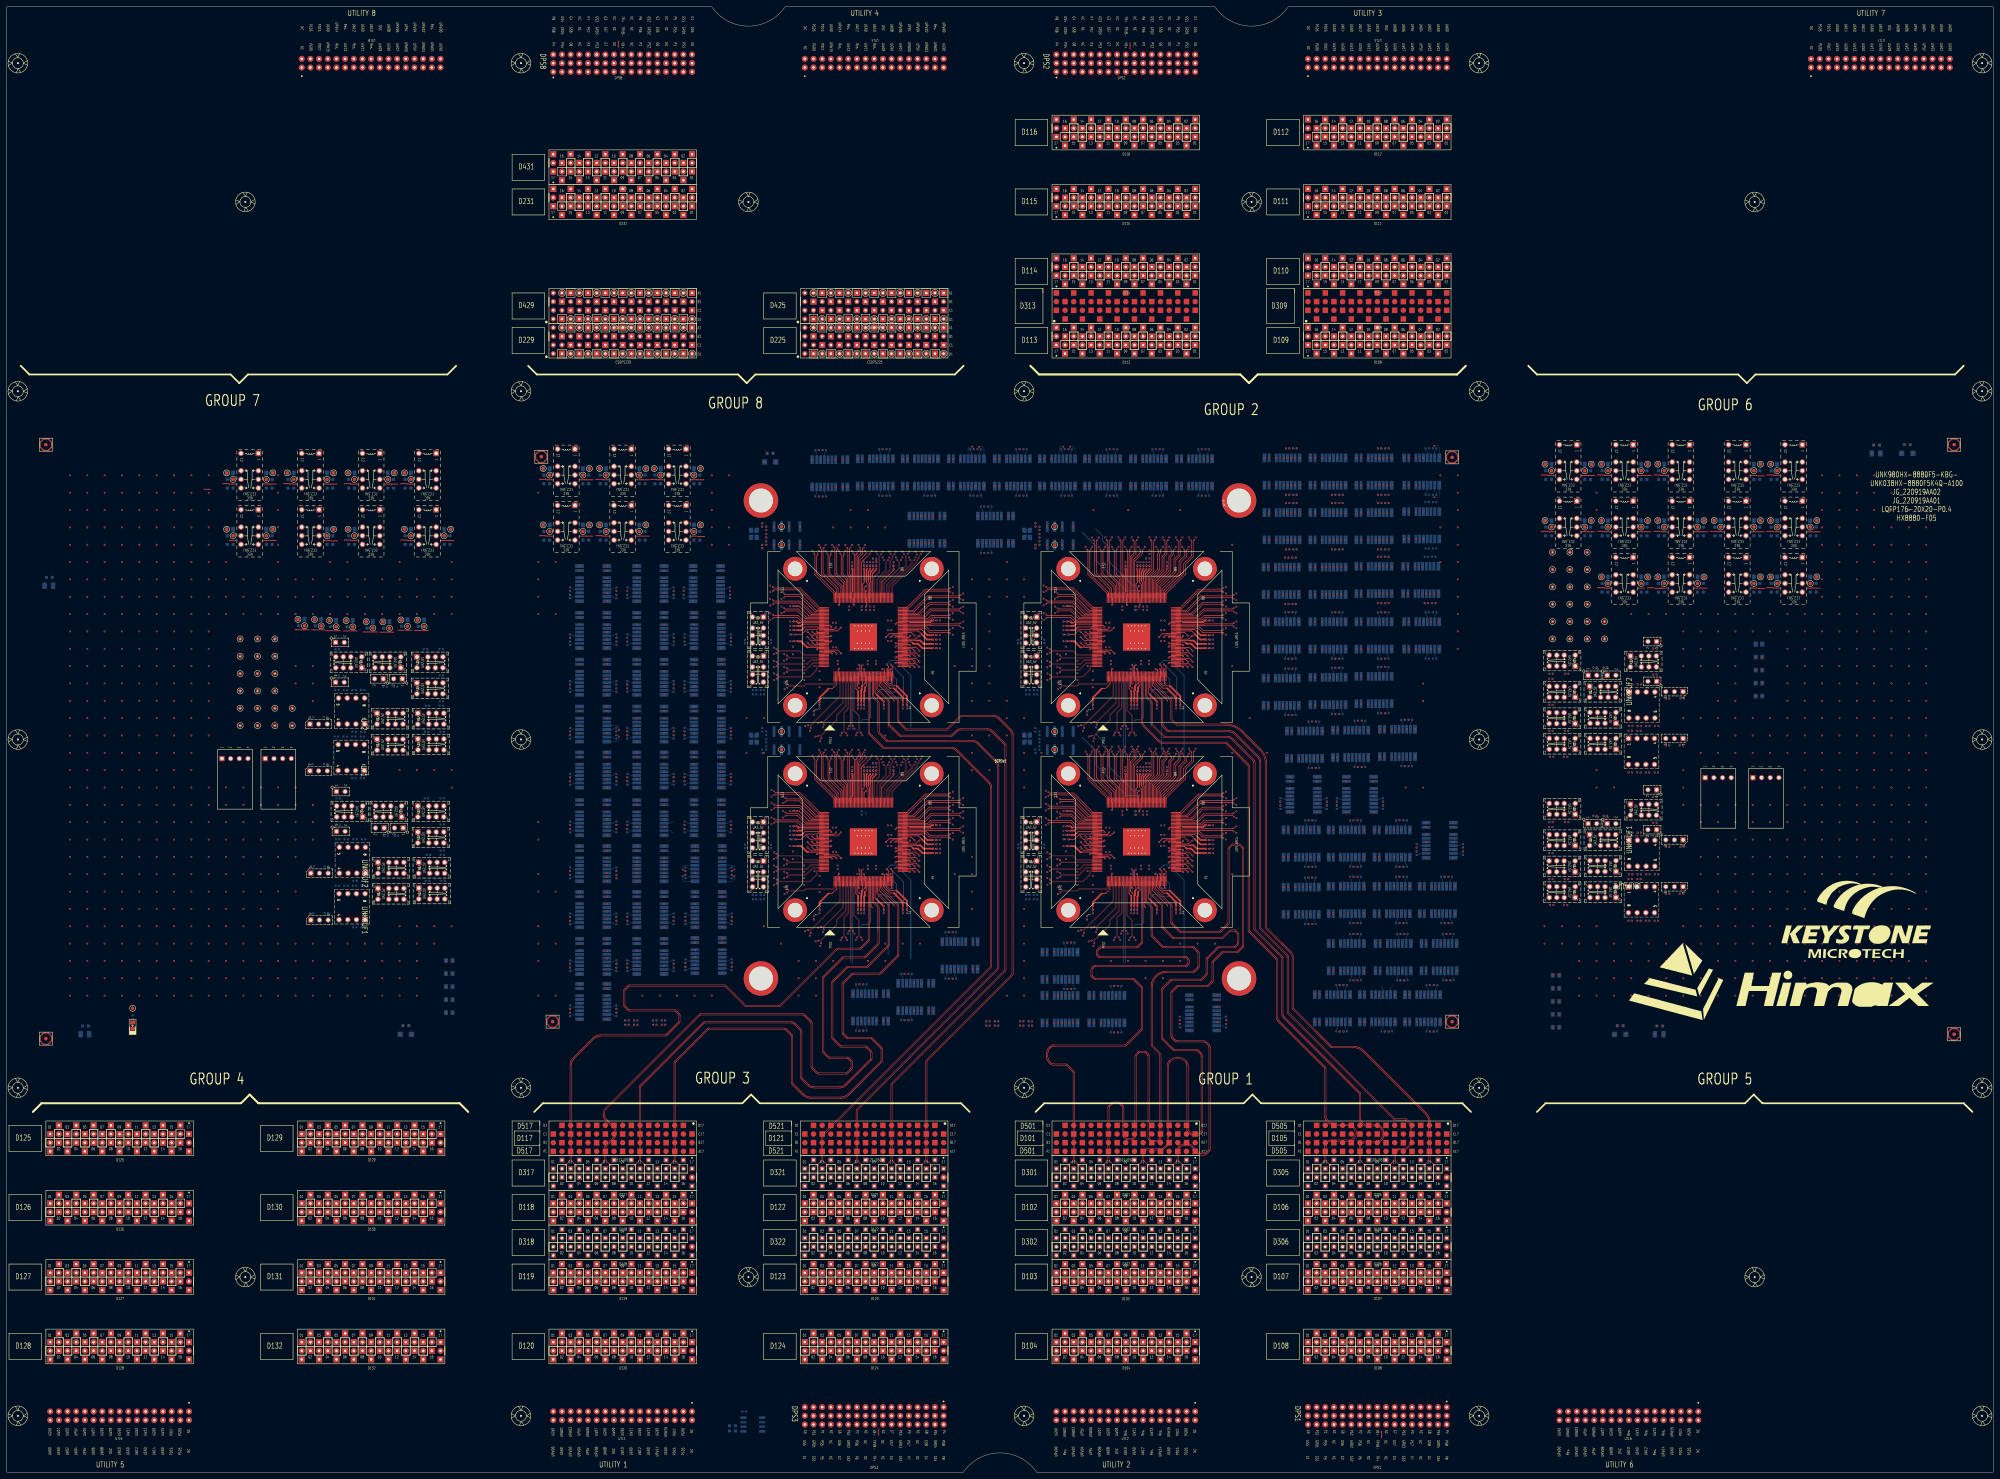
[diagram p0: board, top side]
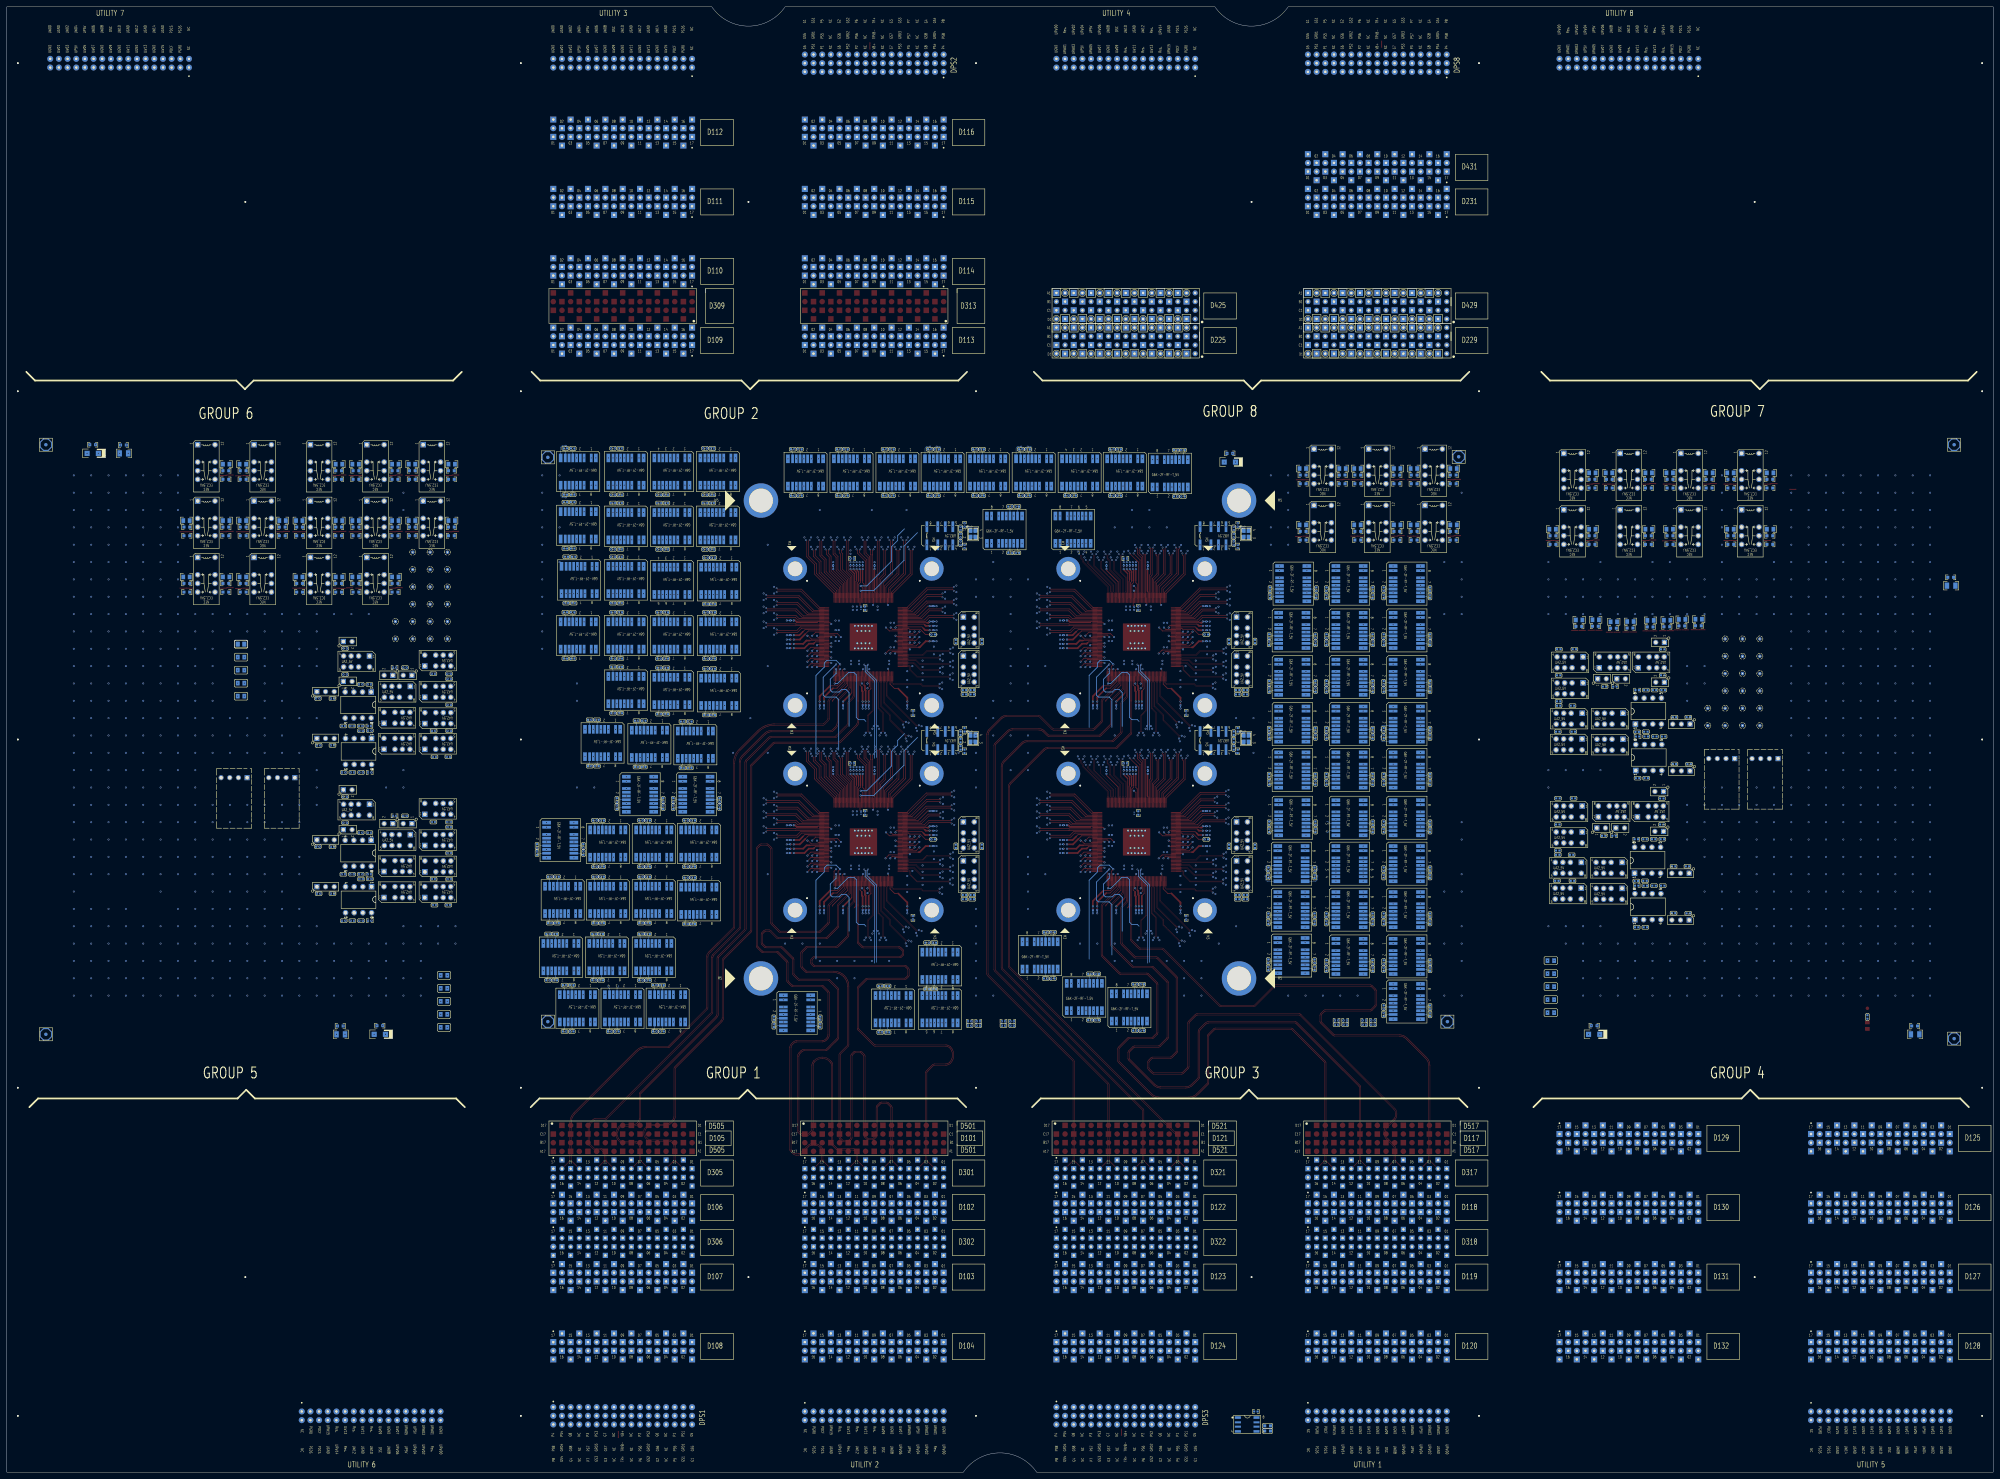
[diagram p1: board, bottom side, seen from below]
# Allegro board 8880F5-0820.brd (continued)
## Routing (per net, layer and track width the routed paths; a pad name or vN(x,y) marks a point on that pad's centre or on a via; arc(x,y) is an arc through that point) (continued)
Net_2: length 0.4
  BOTTOM w0.119: 242.07,241.63 v1(241.87,241.63) ; 242.67,241.63 v1(242.87,241.63)
  vias: v1(233.5,237.74) v1(233.5,235.89) v1(233.5,234.03) v1(233.5,232.05) v1(233.5,177.74) v1(233.5,175.89) v1(233.5,174.03) v1(233.5,172.05) v1(236.49,236.12) v1(236.49,176.12) v1(237.99,234.65) v1(237.99,232.05) v1(237.99,229.95) v1(237.99,174.65) v1(237.99,172.05) v1(237.99,169.95) v1(241.87,248.83) v1(241.87,188.83) v1(241.87,181.63) v1(242.87,248.83) v1(242.87,188.83) v1(242.87,181.63) v1(243.28,237.69) v1(243.28,236.69) v1(243.28,177.69) v1(243.28,176.69) v1(246.67,253.59) v1(246.67,252.59) v1(249.1,235.23) v1(249.1,175.23) v1(252.08,237.69) v1(252.08,236.69) v1(252.08,177.69) v1(252.08,176.69) v1(252.74,253.59) v1(252.74,252.59) v1(253.94,253.59) v1(253.94,252.59) v1(254.48,237.69) v1(254.48,236.69) v1(254.48,177.69) v1(254.48,176.69) v1(257.99,249.47) v1(257.99,243.47) v1(257.99,189.47) v1(257.99,183.47) v1(259,249.47) v1(259,243.47) v1(259,189.47) v1(259,183.47) v1(313.5,237.74) v1(313.5,235.89) v1(313.5,234.03) v1(313.5,232.05) v1(313.5,177.74) v1(313.5,175.89) v1(313.5,174.03) v1(313.5,172.05) v1(316.49,236.12) v1(316.49,176.12) v1(317.99,234.65) v1(317.99,232.05) v1(317.99,229.95) v1(317.99,174.65) v1(317.99,172.05) v1(317.99,169.95) v1(321.87,248.83) v1(321.87,241.63) v1(321.87,188.83) v1(321.87,181.63) v1(322.87,248.83) v1(322.87,241.63) v1(322.87,188.83) v1(322.87,181.63) v1(323.28,237.69) v1(323.28,236.69) v1(323.28,177.69) v1(323.28,176.69) v1(326.67,253.59) v1(326.67,252.59) v1(326.67,193.59) v1(326.67,192.59) v1(329.1,235.23) v1(329.1,175.23) v1(332.08,237.69) v1(332.08,236.69) v1(332.08,177.69) v1(332.08,176.69) v1(332.74,253.59) v1(332.74,252.59) v1(332.74,193.59) v1(332.74,192.59) v1(333.94,253.59) v1(333.94,252.59) v1(333.94,193.59) v1(333.94,192.59) v1(334.48,237.69) v1(334.48,236.69) v1(334.48,177.69) v1(334.48,176.69) v1(337.99,249.47) v1(337.99,243.47) v1(337.99,189.47) v1(337.99,183.47) v1(339,249.47) v1(339,243.47) v1(339,189.47) v1(339,183.47)
Net_1691: length 3
  BOTTOM w0.119: 192.47,190.12 194.3,190.12 194.78,190.59 195.26,190.59
Net_1692: length 3
  BOTTOM w0.119: 195.26,187.45 194.78,187.45 194.3,187.92 192.47,187.92
Net_2069: length 3
  BOTTOM w0.119: 402.97,139.89 402.97,141.73 402.5,142.2 402.5,142.68
Net_2070: length 3
  BOTTOM w0.119: 405.17,139.89 405.17,141.73 405.64,142.2 405.64,142.68
S1_1TX_100DCH001+:
  vias: v1(267.84,280.1) v2(178.5,217.02)
S1_1TX_100DCH001-:
  vias: v1(267.84,272.1) v2(178.5,215.88)
S1_1TX_100DCH002+: length 17.1
  TOP w0.203: v2(279.29,247.66) 278.99,247.96 270.62,247.96 270.55,248.03 SITE1.75
  vias: v2(164.91,217.02)
S1_1TX_100DCH002-: length 17.1
  TOP w0.203: v2(279.29,248.8) 278.99,248.5 270.66,248.5 270.59,248.43 SITE1.76
  vias: v2(164.91,215.88)
S1_1TX_100DCH003+: length 14.4
  TOP w0.203: SITE1.79 270.01,249.63 270.77,250.39 275.95,250.39 v2(276.24,250.09)
  vias: v2(212.03,230.74)
S1_1TX_100DCH003-: length 14.4
  TOP w0.203: SITE1.80 269.64,250.03 270.54,250.94 275.95,250.94 v2(276.24,251.23)
  vias: v2(212.03,229.6)
S1_1TX_100DCH004+: length 17.9
  TOP w0.203: SITE1.81 268.78,250.43 270.67,252.32 278.99,252.32 v2(279.29,252.02)
  vias: v2(198.44,230.74)
S1_1TX_100DCH004-: length 17.9
  TOP w0.203: SITE1.82 268.41,250.83 270.44,252.87 278.99,252.87 v2(279.29,253.16)
  vias: v1(198.44,229.6)
S1_1TX_100DCH005+: length 15.3
  TOP w0.203: v2(276.24,253.95) 275.95,254.25 270.31,254.25 267.29,251.23 SITE1.83
  vias: v2(296.56,299.66)
S1_1TX_100DCH005-: length 15.3
  TOP w0.203: SITE1.84 266.92,251.63 270.08,254.79 275.95,254.79 v2(276.24,255.09)
  vias: v2(297.71,299.66)
S1_1TX_100DCH006+: length 18.8
  TOP w0.203: SITE1.85 265.71,252.03 269.86,256.18 278.99,256.18 v2(279.29,255.88)
  vias: v2(296.56,286.07)
S1_1TX_100DCH006-: length 18.9
  TOP w0.203: SITE1.86 265.34,252.43 269.63,256.72 278.99,256.72 v2(279.29,257.02)
  vias: v2(297.71,286.07)
S1_1TX_100DCH007+: length 16.2
  TOP w0.203: SITE1.87 263.9,252.83 269.17,258.1 275.95,258.1 v2(276.24,257.81)
  vias: v2(309.77,299.66)
S1_1TX_100DCH007-: length 16.3
  TOP w0.203: SITE1.88 263.52,253.23 268.95,258.65 275.95,258.65 v2(276.24,258.95)
  vias: v2(310.92,299.66)
S1_2AUX+:
  vias: v1(184.65,132.33) v1(184.65,131.06)
S1_2AUX-:
  vias: v1(181.11,131.06) v1(182.11,132.33)
S1_2TX_100DCH001+: length 16.3
  TOP w0.086: v2(267.64,268.93) 267.21,268.5 267.21,267.72 266.7,267.21 266.7,266.7 259.35,259.35 259.35,257.86 259.43,257.78 SITE1.89
  vias: v2(309.77,286.07)
S1_2TX_100DCH001-: length 16.3
  TOP w0.086: v2(266.5,268.93) 266.97,268.46 266.97,267.82 266.46,267.31 266.46,266.8 259.11,259.45 259.11,257.86 259.03,257.78 SITE1.90
  vias: v2(310.92,286.07)
S1_2TX_100DCH002+: length 14.1
  TOP w0.086: v2(265.72,267.21) 265.28,266.78 265.28,266.3 258.55,259.57 258.55,257.86 258.63,257.78 SITE1.91
  vias: v2(349.9,299.66)
S1_2TX_100DCH002-: length 14.1
  TOP w0.086: v2(264.57,267.21) 265.04,266.74 265.04,266.4 258.31,259.66 258.31,257.86 258.23,257.78 SITE1.92
  vias: v2(351.05,299.66)
S1_2TX_100DCH003+: length 15.3
  TOP w0.086: SITE1.93 257.83,257.78 257.75,257.86 257.75,259.78 263.33,265.37 263.33,268.48 v2(263.79,268.93)
  vias: v2(349.9,286.07)
S1_2TX_100DCH003-: length 15.3
  TOP w0.086: v2(262.64,268.93) 263.1,268.48 263.1,265.47 257.51,259.88 257.51,257.86 257.43,257.78 SITE1.94
  vias: v2(351.05,286.07)
S1_2TX_100DCH004+: length 13.1
  TOP w0.086: SITE1.95 257.03,257.78 256.95,257.86 256.95,260.25 261.41,264.71 261.41,266.77 v2(261.86,267.21)
  vias: v2(336.44,299.66)
S1_2TX_100DCH004-: length 13.2
  TOP w0.086: SITE1.96 256.63,257.78 256.71,257.86 256.71,260.35 261.17,264.81 261.17,266.76 v2(260.71,267.21)
  vias: v2(337.59,299.66)
S1_2TX_100DCH005+: length 14.6
  TOP w0.086: v2(259.93,268.93) 259.48,268.49 259.48,267.61 258.83,266.95 258.83,264.33 255.75,261.25 255.75,257.86 255.83,257.78 SITE1.98
  vias: v2(336.44,286.07)
S1_2TX_100DCH005-: length 14.6
  TOP w0.086: v2(258.78,268.93) 259.24,268.47 259.24,267.71 258.59,267.05 258.59,264.43 255.51,261.35 255.51,257.86 255.43,257.78 SITE1.99
  vias: v2(337.59,286.07)
S1_2TX_100DCH006+: length 12.4
  TOP w0.086: v2(258,267.21) 257.56,266.77 257.56,264.16 254.95,261.55 254.95,257.86 255.03,257.78 SITE1.100
  vias: v2(322.98,299.66)
S1_2TX_100DCH006-: length 12.4
  TOP w0.086: SITE1.101 254.63,257.78 254.71,257.86 254.71,261.65 257.32,264.26 257.32,266.75 v2(256.85,267.21)
  vias: v2(324.12,299.66)
S1_2TX_100DCH007+: length 13.6
  TOP w0.086: v2(256.07,268.93) 255.63,268.49 255.63,263.67 254.15,262.19 254.15,257.86 254.23,257.78 SITE1.102
  vias: v2(322.98,286.07)
S1_2TX_100DCH007-: length 13.6
  TOP w0.086: SITE1.103 253.83,257.78 253.91,257.86 253.91,262.29 255.39,263.77 255.39,268.47 v2(254.93,268.93)
  vias: v2(324.12,286.07)
S1_3TX_100DCH002+: length 15.4
  TOP w0.203: SITE1.114 249.43,267.85 250.59,269.01 250.59,270.53 v2(250.93,270.87)
  vias: v2(269.64,286.07)
S1_3TX_100DCH002-: length 15.3
  TOP w0.203: SITE1.115 249.03,268.23 250.09,269.29 250.09,270.09 249.79,270.39 v2(249.79,270.87)
  vias: v2(270.78,286.07)
S1_3TX_100DCH003+: length 13.2
  TOP w0.203: SITE1.116 248.63,268.74 248.66,268.77 248.66,268.81 v2(249,269.15)
  vias: v2(287.38,269.3)
S1_3TX_100DCH003-: length 13.2
  TOP w0.203: v2(247.86,269.15) 248.2,268.81 248.2,268.77 248.23,268.74 SITE1.117
  vias: v2(286.24,269.3)
S1_3TX_100DCH004+: length 15
  TOP w0.203: v2(247.07,270.87) 246.73,270.53 246.73,263.13 247.03,262.83 SITE1.120
  vias: v2(287.38,282.89)
S1_3TX_100DCH004-: length 15
  TOP w0.203: v2(245.93,270.87) 246.27,270.53 246.27,262.81 246.63,262.45 SITE1.121
  vias: v2(286.24,282.89)
S1_3TX_100DCH005+: length 13.7
  TOP w0.203: v2(245.14,269.15) 245.14,268.67 244.85,268.37 244.85,263.17 246.23,261.79 SITE1.122
  vias: v2(238.87,285.81)
S1_3TX_100DCH005-: length 13.8
  TOP w0.203: v2(244,269.15) 244.34,268.81 244.34,262.9 245.83,261.41 SITE1.123
  vias: v2(237.72,285.81)
S1_3TX_100DCH006+: length 15.9
  TOP w0.203: v2(243.21,270.87) 243.21,270.39 242.92,270.09 242.92,263.29 245.43,260.78 SITE1.124
  vias: v2(238.87,299.4)
S1_3TX_100DCH006-: length 16.1
  TOP w0.203: v2(242.14,271.04) 242.48,270.7 242.48,262.95 245.03,260.4 SITE1.125
  vias: v2(237.72,299.4)
S1_3TX_100DCH007+: length 14.7
  TOP w0.203: SITE1.126 244.63,259.62 240.99,263.26 240.99,268.37 241.28,268.67 v2(241.28,269.15)
  vias: v2(256.43,299.66)
S1_3TX_100DCH007-: length 14.7
  TOP w0.203: SITE1.127 244.23,259.25 240.48,262.99 240.48,268.81 v2(240.14,269.15)
  vias: v2(257.58,299.66)
S1_4TX_100DCH001+: length 16.7
  TOP w0.203: SITE1.129 243.43,258.97 239.01,263.39 239.01,270.53 v2(239.35,270.87)
  vias: v2(256.43,286.07)
S1_4TX_100DCH001-: length 16.9
  TOP w0.203: SITE1.130 243.03,258.6 238.55,263.07 238.55,270.28 238.28,270.55 v2(238.28,271.04)
  vias: v2(257.58,286.07)
S1_4TX_100DCH002+: length 15.4
  TOP w0.203: SITE1.131 242.63,257.73 237.13,263.23 237.13,268.37 237.43,268.67 v2(237.43,269.15)
  vias: v2(283.1,299.66)
S1_4TX_100DCH002-: length 15.5
  TOP w0.203: v2(236.28,269.15) 236.62,268.81 236.62,262.96 242.23,257.35 SITE1.132
  vias: v2(284.25,299.66)
S1_4TX_100DCH003+: length 17.5
  TOP w0.203: SITE1.133 238.12,253.23 232.34,259.01 224.6,259.01 v2(224.31,259.31)
  vias: v2(283.1,286.07)
S1_4TX_100DCH003-: length 17.5
  TOP w0.203: v2(224.31,258.17) 224.6,258.46 232.11,258.46 237.75,252.83 SITE1.134
  vias: v2(284.25,286.07)
S1_4TX_100DCH004+: length 13.8
  TOP w0.203: v2(227.6,257.38) 227.9,257.08 232.36,257.08 237.02,252.43 SITE1.135
  vias: v2(178.5,258.17)
S1_4TX_100DCH004-: length 13.7
  TOP w0.203: v2(227.6,256.24) 227.9,256.54 232.13,256.54 236.64,252.03 SITE1.136
  vias: v2(178.5,257.03)
S1_4TX_100DCH005+: length 16.6
  TOP w0.203: v2(224.31,255.45) 224.6,255.15 232.42,255.15 235.95,251.63 SITE1.137
  vias: v2(164.91,258.17)
S1_4TX_100DCH005-: length 16.5
  TOP w0.203: v2(224.31,254.31) 224.6,254.61 232.2,254.61 235.57,251.23 SITE1.138
  vias: v2(164.91,257.03)
S1_4TX_100DCH006+: length 12.9
  TOP w0.203: v2(227.6,253.14) 227.9,252.84 231.76,252.84 234.18,250.43 SITE1.140
  vias: v2(195.26,258.17)
S1_4TX_100DCH006-: length 12.8
  TOP w0.203: SITE1.141 233.8,250.03 231.54,252.3 227.9,252.3 v2(227.6,252)
  vias: v1(195.26,257.03)
S1_4TX_100DCH007+: length 15.7
  TOP w0.203: SITE1.142 233.03,249.63 231.75,250.92 224.6,250.92 v2(224.31,251.21)
  vias: v2(181.67,258.17)
S1_4TX_100DCH007-: length 15.6
  TOP w0.203: v2(224.31,250.07) 224.6,250.37 231.52,250.37 232.66,249.23 SITE1.143
  vias: v2(181.67,257.03)
S1_AUX_100DCH002+:
  vias: v1(183.65,132.33)
S1_AUX_100DCH002-:
  vias: v1(181.11,132.33)
S1_AUXCH+: length 24
  TOP w0.203: v2(250.6,236.57) 250.23,236.2 SITE1.21
  BOTTOM w0.203: 247.57,217.42 247.57,231.79 250.3,234.52 250.3,236.28 v2(250.6,236.57)
S1_AUXCH-: length 24
  TOP w0.203: SITE1.20 249.83,236.2 v2(249.46,236.57)
  BOTTOM w0.203: 247.03,217.42 247.03,232.02 249.76,234.75 249.76,236.28 v2(249.46,236.57)
S1_AVDD11_RX: length 8.4
  TOP w0.231: 254.67,227.85 254.23,228.29 SITE1.31
  TOP w0.508: v1(256.77,225.75) 254.67,227.85
  vias: v1(256.77,223.71)
S1_AVDD11_XTAL: length 8.8
  TOP w0.231: 252.87,261.45 252.87,261.11 253.03,260.95 SITE1.105
  TOP w0.381: 252.87,261.45 252.87,263.59 253.72,264.44 v1(253.72,264.54)
  vias: v1(253.72,266.58)
S1_AVDD18_RX: length 7.7
  TOP w0.231: SITE1.25 251.83,230.56 251.28,230.01
  TOP w0.508: 251.28,230.01 251.28,228.9 251.06,228.68 v1(251.06,225.75)
  vias: v1(251.06,223.71)
S1_DCH041: length 2.2
  TOP w0.231: SITE1.159 237.43,242.83 v1(237.23,243.03)
S1_DCH042: length 3.7
  TOP w0.231: SITE1.160 236.43,242.43 v1(235.83,243.03)
S1_DCH043: length 5.3
  TOP w0.231: v1(234.44,243.03) 235.44,242.03 SITE1.161
S1_DCH044: length 2.2
  TOP w0.231: v1(237.23,241.03) 237.43,241.23 SITE1.163
S1_DCH045: length 5.4
  TOP w0.231: v1(244.35,239.83) 243.35,240.83 SITE1.164
S1_DCH046: length 3.9
  TOP w0.231: SITE1.165 242.35,240.43 v1(242.95,239.83)
S1_DCH047: length 2.3
  TOP w0.231: v1(241.56,239.83) 241.36,240.03 SITE1.166
S1_DCH048:
  vias: v1(229.05,276.97)
S1_DCH049:
  vias: v1(229.05,271.67)
S1_DPS_F_001:
  vias: v1(182.11,131.06)
S1_DPS_F_002: length 10.1
  TOP w0.119: v1(237.98,223.71) 237.98,223.75
  TOP w0.231: SITE1.3 243.03,230.86 241.72,229.55 240.65,229.55
  TOP w0.508: v1(237.98,225.75) 237.98,226.88 240.65,229.55
  vias: v1(236.32,222.9)
S1_DPS_F_003: length 63.1
  TOP w0.231: SITE1.63 264.9,243.23 265.2,242.93 ; SITE1.17 248.63,229.5 249.28,228.85 ; 232.83,248.18 233.08,248.43 SITE1.145 ; 267.84,245.53 266.94,246.43 SITE1.71 ; 251.69,261.16 251.69,260.65 252.23,260.11 SITE1.107 ; 259.73,229.66 258.57,229.66 256.63,231.59 SITE1.37 ; 234.63,241.63 SITE1.162
  TOP w0.381: 251.69,261.16 251.69,264.28 v1(251.94,264.54)
  TOP w0.508: v1(271.22,243.91) 269.46,243.91 267.84,245.53 ; v1(249.28,225.75) 249.28,228.85 ; v1(231.44,247.93) 232.58,247.93 232.83,248.18 ; v1(262.36,225.75) 262.36,227.02 259.73,229.66 ; 234.63,241.63 234.37,241.63 232.59,243.41 v1(231.44,243.41) ; v1(271.22,241.37) 268.11,241.37 266.8,242.67 265.45,242.67 265.2,242.93
  vias: v1(229.4,247.93) v1(229.4,243.41) v1(249.28,223.71) v1(251.54,252.59) v1(251.94,266.58) v1(262.36,223.71) v1(273.27,243.91) v1(273.27,241.37)
S1_DPS_F_006: length 9.8
  TOP w0.231: SITE1.72 267.92,246.83 268.55,246.19
  TOP w0.508: v1(271.22,245.18) 269.56,245.18 268.55,246.19
  BOTTOM w0.119: CC40.1 v1(259,246.67)
  vias: v1(273.27,245.18)
S1_DPS_F_007: length 19.2
  TOP w0.231: SITE1.78 264.15,249.23 264.37,249.01
  TOP w0.254: SITE1.97 256.23,260.8 259.65,264.22 v1(259.65,264.54) CD11.1
  TOP w0.508: 264.37,249.01 270.31,249.01 270.8,249.5 v1(271.22,249.5)
  BOTTOM w0.119: CC27.1 v1(273.27,249.5)
  vias: v1(259.65,266.58)
S1_DPS_F_009: length 8.8
  TOP w0.231: SITE1.106 252.63,260.53 252.26,260.9 252.26,261.12
  TOP w0.381: v1(252.83,264.54) 252.83,264.39 252.26,263.82 252.26,261.12
  vias: v1(252.83,266.58) v1(253.61,267.66)
S1_DPS_F_010: length 8.6
  TOP w0.231: 251.05,261.13 251.05,260.57 250.63,260.15 SITE1.111
  TOP w0.381: 251.05,261.13 v1(251.05,264.54)
  vias: v1(250.34,253.59) v1(251.05,266.58)
S1_DPS_F_011: length 17.6
  TOP w0.231: SITE1.139 234.87,250.83 232.01,253.69 v1(231.44,253.69) ; 247.64,258.01 247.43,257.79 SITE1.119
  TOP w0.508: v1(247.57,264.54) 247.64,264.47 247.64,258.01
  vias: v1(229.4,253.69) v1(247.57,266.58)
S1_DPS_F_012: length 8
  TOP w0.231: 232.2,248.83 SITE1.144
  TOP w0.508: 232.2,248.83 231.81,248.83 v1(231.44,249.2)
  vias: v1(229.4,249.2)
S1_ISP00+: length 14.5
  TOP w0.203: v2(276.24,245.73) 275.95,246.03 270.09,246.03 268.89,247.23 SITE1.73
  vias: v1(270.04,280.1)
S1_ISP00-: length 14.5
  TOP w0.203: v2(276.24,246.87) 275.95,246.58 270.32,246.58 269.26,247.63 SITE1.74
  vias: v1(270.04,272.1)
S1_ISP14+: length 14.1
  TOP w0.203: SITE1.112 250.23,266.52 250.47,266.76 250.47,266.82 250.81,267.16 250.87,267.16 v2(252.86,269.15)
  vias: v1(265.64,280.1)
S1_ISP14-: length 13.8
  TOP w0.203: SITE1.113 249.83,267.26 v2(251.72,269.15)
  vias: v1(265.64,272.1)
S1_M_DPS_F_001: length 45.2
  TOP w0.231: 250.63,230.54 SITE1.22 ; SITE1.39 257.43,231.49 258.54,230.37 260.57,230.37 ; SITE1.147 233.7,247.63 233.24,247.18 ; SITE1.104 253.43,263.21 ; 266.49,243.63 SITE1.64
  TOP w0.381: 253.43,263.21 254.61,264.39 v1(254.61,264.54)
  TOP w0.508: v1(271.22,242.64) 268.48,242.64 267.49,243.63 266.49,243.63 ; v1(263.63,225.75) 263.63,227.31 260.57,230.37 ; 233.24,247.18 232.72,246.66 v1(231.44,246.66) ; v1(250.17,225.75) 250.17,228.96 250.38,229.17 250.38,230.28 250.63,230.54
  vias: v1(229.4,246.66) v1(250.17,223.71) v1(254.61,266.58) v1(263.63,223.71) v1(273.27,242.64)
S1_PS9G_DCH001: length 3.7
  TOP w0.231: SITE1.18 249.03,230.23 v1(249.63,229.63)
S1_PS9G_DCH002: length 2.2
  TOP w0.231: v1(249.63,231.03) 249.43,231.23 SITE1.19
S1_PS9G_DCH003: length 2.2
  TOP w0.231: v1(251.23,231.03) 251.43,231.23 SITE1.24
S1_PS9G_DCH004: length 2.2
  TOP w0.231: SITE1.40 257.83,235.03 v1(257.63,235.23)
S1_PS9G_DCH005: length 2.2
  TOP w0.231: SITE1.45 264.23,236.03 v1(264.43,235.83)
S1_PS9G_DCH006: length 3.7
  TOP w0.231: v1(265.83,235.83) 265.23,236.43 SITE1.46
S1_PS9G_DCH007: length 5.3
  TOP w0.231: SITE1.47 266.22,236.83 v1(267.23,235.83)
S1_PS9G_DCH009: length 2.2
  TOP w0.231: SITE1.49 264.23,237.63 v1(264.43,237.43)
S1_PS9G_DCH010: length 3.7
  TOP w0.231: SITE1.50 265.23,238.03 v1(265.83,237.43)
S1_PS9G_DCH011: length 5.3
  TOP w0.231: SITE1.51 266.22,238.43 v1(267.23,237.43)
S1_PS9G_DCH014: length 3.7
  TOP w0.231: SITE1.54 265.23,239.63 v1(265.83,239.03)
S1_PS9G_DCH015: length 5.3
  TOP w0.231: SITE1.55 266.22,240.03 v1(267.23,239.03)
S1_PS9G_DCH022: length 5.3
  TOP w0.231: SITE1.65 266.05,244.03 267.05,245.03 v1(267.23,245.03)
S1_PS9G_DCH023: length 2.5
  TOP w0.231: v1(264.43,245.03) 264.43,244.83 264.03,244.43 SITE1.66
S1_PS9G_DCH027: length 3.9
  TOP w0.231: SITE1.70 264.83,246.03 v1(265.83,245.03)
S1_PS9G_DCH028: length 2.3
  TOP w0.231: SITE1.77 260.6,248.83 v1(260.23,248.46)
S1_PS9G_DCH029: length 2.2
  TOP w0.231: SITE1.118 247.83,254.23 v1(248.03,254.03)
S1_PS9G_DCH030: length 9.2
  TOP w0.231: v1(230.91,245.39) 232.63,245.39 234.16,246.91 237.3,246.91 237.62,247.23 SITE1.148
S1_PS9G_DCH035: length 5.3
  TOP w0.231: SITE1.153 235.44,245.23 v1(234.44,246.23)
S1_PS9G_DCH036: length 2.2
  TOP w0.231: SITE1.154 241.23,244.83 v1(241.43,245.03)
S1_PS9G_DCH037: length 2.2
  TOP w0.231: v1(237.23,244.63) 237.43,244.43 SITE1.155
S1_PS9G_DCH038: length 3.7
  TOP w0.231: SITE1.156 236.43,244.03 v1(235.83,244.63)
S1_PS9G_DCH039: length 5.3
  TOP w0.231: v1(234.44,244.63) 235.44,243.63 SITE1.157
S1_PS9G_DCH040: length 2.2
  TOP w0.231: v1(241.43,243.43) 241.23,243.23 SITE1.158
S1_RLY_001:
  vias: v1(167.7,222.95) v1(201.23,236.67)
S1_RLY_003:
  vias: v1(290.64,288.86) v1(303.84,288.86)
S1_RLY_005:
  vias: v1(330.51,288.86) v1(343.98,288.86)
S1_RLY_007:
  vias: v1(317.05,288.86)
S1_RLY_008:
  vias: v1(263.71,288.86) v1(293.31,280.1)
S1_RLY_016:
  vias: v1(244.8,296.61) v1(250.5,288.86)
S1_RLY_018:
  vias: v1(232.25,276.97)
S1_RLY_021:
  vias: v1(167.7,264.1) v1(277.17,288.86)
S1_RLY_022:
  vias: v1(167.7,236.67) v1(201.23,250.38)
S1_RLY_023:
  vias: v1(184.47,236.67)
S1_RLY_025:
  vias: v1(167.7,250.38) v1(200.98,264.1)
S1_RLY_026:
  vias: v1(184.47,250.38)
S1_RLY_030:
  vias: v1(184.47,264.1)
S1_RLY_043:
  vias: v1(273.24,280.1)
S1_SCAN_DCH008: length 2.2
  TOP w0.231: SITE1.48 260.43,237.23 v1(260.23,237.03)
S1_SCAN_DCH012: length 2.2
  TOP w0.231: SITE1.52 260.43,238.83 v1(260.23,238.63)
S1_SCAN_DCH013: length 2.2
  TOP w0.231: SITE1.53 264.23,239.23 v1(264.43,239.03)
S1_SCAN_DCH016: length 2.2
  TOP w0.231: v1(260.23,240.23) 260.43,240.43 SITE1.56
S1_SCAN_DCH017: length 2.2
  TOP w0.231: SITE1.57 264.23,240.83 v1(264.43,240.63)
S1_SCAN_DCH018: length 3.7
  TOP w0.231: SITE1.58 265.23,241.23 v1(265.83,240.63)
S1_SCAN_DCH019: length 5.3
  TOP w0.231: v1(267.23,240.63) 266.22,241.63 SITE1.59
S1_SCAN_DCH020: length 2.2
  TOP w0.231: v1(260.23,241.83) 260.43,242.03 SITE1.60
S1_SCAN_DCH021: length 2.2
  TOP w0.231: SITE1.61 264.23,242.43 v1(264.43,242.23)
S1_SCAN_DCH024: length 2.2
  TOP w0.231: v1(260.23,244.63) 260.43,244.83 SITE1.67
S1_SCAN_DCH025: length 3.7
  TOP w0.231: v1(258.83,244.63) 259.43,245.23 SITE1.68
S1_SCAN_DCH026: length 5.3
  TOP w0.231: v1(257.44,244.63) 258.44,245.63 SITE1.69
S1_SCAN_DCH031: length 3.7
  TOP w0.231: SITE1.149 242.23,246.83 v1(242.83,247.43)
S1_SCAN_DCH032: length 5.3
  TOP w0.231: SITE1.150 243.22,246.43 v1(244.22,247.43)
S1_SCAN_DCH033: length 2.2
  TOP w0.231: SITE1.151 237.43,246.03 v1(237.23,246.23)
S1_SCAN_DCH034: length 3.7
  TOP w0.231: v1(235.83,246.23) 236.43,245.63 SITE1.152
S1_SPI_CSN: length 25.9
  TOP w0.231: SITE1.43 259.03,231.23 v1(259.23,231.03)
  BOTTOM w0.231: 250.11,219.95 250.61,220.44 252.25,220.44 252.91,221.11 252.91,233.59 253.58,234.25 255.17,234.25 258.4,231.03 v1(259.23,231.03)
S1_SPI_SCK: length 25.3
  TOP w0.231: v1(258.83,235.23) 258.63,235.03 SITE1.42
  BOTTOM w0.231: 255.03,218.48 255.03,228.39 255.92,229.27 257.17,229.27 257.9,228.54 259.96,228.54 260.53,229.11 260.53,232.28 258.83,233.98 v1(258.83,235.23)
S1_SPI_SDI: length 27.5
  TOP w0.231: v1(258.83,236.63) 259.43,236.03 SITE1.44
  BOTTOM w0.231: v1(258.83,236.63) 262.6,232.86 262.6,227.63 262.04,227.06 258.85,227.06 258.07,226.28 258.07,218.19
S1_SPI_SDO: length 29.1
  TOP w0.231: SITE1.41 258.23,236.03 v1(257.63,236.63)
  BOTTOM w0.231: 264.72,218.19 264.72,233.4 262.29,235.83 262.29,237.04 261.5,237.83 258.83,237.83 v1(257.63,236.63)
S1_XTAL_IN: length 2.2
  TOP w0.231: SITE1.109 251.43,258.03 v1(251.63,258.23)
  vias: v1(226.85,271.67)
S1_XTAL_OUT: length 3.7
  TOP w0.231: v1(251.63,259.63) 251.03,259.03 SITE1.110
  vias: v1(226.85,276.97)
S2_1TX_100DCH001+:
  vias: v1(388.49,257.11)
S2_1TX_100DCH001-:
  vias: v1(388.49,265.11)
S2_1TX_100DCH002+: length 17.1
  TOP w0.203: v2(359.29,247.66) 358.99,247.96 350.62,247.96 350.55,248.03 SITE2.75
S2_1TX_100DCH002-: length 17.1
  TOP w0.203: v2(359.29,248.8) 358.99,248.5 350.66,248.5 350.59,248.43 SITE2.76
S2_1TX_100DCH003+: length 14.4
  TOP w0.203: v2(356.24,250.09) 355.95,250.39 350.77,250.39 350.01,249.63 SITE2.79
S2_1TX_100DCH003-: length 14.4
  TOP w0.203: v2(356.24,251.23) 355.95,250.94 350.54,250.94 349.64,250.03 SITE2.80
S2_1TX_100DCH004+: length 17.9
  TOP w0.203: SITE2.81 348.78,250.43 350.67,252.32 358.99,252.32 v2(359.29,252.02)
S2_1TX_100DCH004-: length 17.9
  TOP w0.203: v2(359.29,253.16) 358.99,252.87 350.44,252.87 348.41,250.83 SITE2.82
S2_1TX_100DCH005+: length 15.3
  TOP w0.203: SITE2.83 347.29,251.23 350.31,254.25 355.95,254.25 v2(356.24,253.95)
  vias: v1(402.48,251.9)
S2_1TX_100DCH005-: length 15.3
  TOP w0.203: SITE2.84 346.92,251.63 350.08,254.79 355.95,254.79 v2(356.24,255.09)
  vias: v1(403.63,251.9)
S2_1TX_100DCH006+: length 18.8
  TOP w0.203: v2(359.29,255.88) 358.99,256.18 349.86,256.18 345.71,252.03 SITE2.85
  vias: v1(402.48,238.32)
S2_1TX_100DCH006-: length 18.9
  TOP w0.203: SITE2.86 345.33,252.43 349.63,256.72 358.99,256.72 v2(359.29,257.02)
  vias: v1(403.63,238.32)
S2_1TX_100DCH007+: length 16.2
  TOP w0.203: SITE2.87 343.9,252.83 349.17,258.1 355.95,258.1 v2(356.24,257.81)
  vias: v1(375.56,283.91)
S2_1TX_100DCH007-: length 16.3
  TOP w0.203: v2(356.24,258.95) 355.95,258.65 348.95,258.65 343.52,253.23 SITE2.88
  vias: v1(376.7,283.91)
S2_2AUX+:
  vias: v1(290.31,132.08) v1(290.31,130.81)
S2_2AUX-:
  vias: v1(286.77,130.81) v1(287.77,132.08)
S2_2TX_100DCH001+: length 20.4
  TOP w0.203: v2(347.71,273.07) 347.42,272.77 347.42,268.16 345.16,265.9 345.16,263.11 339.43,257.38 SITE2.89
  vias: v1(375.56,270.32)
S2_2TX_100DCH001-: length 20.3
  TOP w0.203: v2(346.57,273.07) 346.87,272.77 346.87,268.39 344.61,266.13 344.61,263.34 339.03,257.76 SITE2.90
  vias: v1(376.7,270.32)
S2_2TX_100DCH002+: length 17.2
  TOP w0.203: SITE2.91 338.63,258.2 343.79,263.36 343.79,266.6 345.49,268.29 345.49,270.03 v2(345.78,270.33)
  vias: v1(402.48,268.16)
S2_2TX_100DCH002-: length 17.1
  TOP w0.203: v2(344.64,270.33) 344.94,270.03 344.94,268.52 343.24,266.83 343.24,263.59 338.23,258.57 SITE2.92
  vias: v1(403.63,268.16)
S2_2TX_100DCH003+: length 19.4
  TOP w0.203: v2(343.85,273.07) 343.56,272.77 343.56,268.44 342.31,267.19 342.31,263.61 337.83,259.13 SITE2.93
  vias: v1(402.48,254.57)
S2_2TX_100DCH003-: length 19.4
  TOP w0.203: SITE2.94 337.43,259.51 341.76,263.84 341.76,267.42 343.01,268.66 343.01,272.77 v2(342.71,273.07)
  vias: v1(403.63,254.57)
S2_2TX_100DCH004+: length 16.2
  TOP w0.203: SITE2.95 337.03,259.94 340.84,263.75 340.84,268.1 341.63,268.88 341.63,270.03 v2(341.93,270.33)
  vias: v1(402.48,283.91)
S2_2TX_100DCH004-: length 16.2
  TOP w0.203: v2(340.78,270.33) 341.08,270.03 341.08,269.11 340.3,268.32 340.3,263.98 336.63,260.31 SITE2.96
  vias: v1(403.63,283.91)
S2_2TX_100DCH005+: length 18.7
  TOP w0.203: v2(340,273.07) 339.7,272.77 339.7,268.91 338.83,268.04 338.83,264.11 335.83,261.12 SITE2.98
  vias: v1(402.48,270.32)
S2_2TX_100DCH005-: length 18.6
  TOP w0.203: v2(338.85,273.07) 339.15,272.77 339.15,269.13 338.28,268.26 338.28,264.34 335.43,261.49 SITE2.99
  vias: v1(403.63,270.32)
S2_2TX_100DCH006+: length 15.5
  TOP w0.203: SITE2.100 335.03,261.79 337.52,264.29 337.52,268.95 337.77,269.19 337.77,270.03 v2(338.07,270.33)
  vias: v1(389.02,283.91)
S2_2TX_100DCH006-: length 15.4
  TOP w0.203: SITE2.101 334.63,262.17 336.97,264.51 336.97,269.18 337.22,269.42 337.22,270.03 v2(336.92,270.33)
  vias: v1(390.16,283.91)
S2_2TX_100DCH007+: length 17.7
  TOP w0.203: SITE2.102 334.23,262.44 335.84,264.05 335.84,272.77 v2(336.14,273.07)
  vias: v1(389.02,270.32)
S2_2TX_100DCH007-: length 17.7
  TOP w0.203: SITE2.103 333.83,262.81 335.29,264.27 335.29,272.77 v2(334.99,273.07)
  vias: v1(390.16,270.32)
S2_3TX_100DCH002+: length 17.6
  TOP w0.203: v2(330.93,273.07) 330.63,272.77 330.63,269.06 329.43,267.85 SITE2.114
  vias: v1(389.02,286.32)
S2_3TX_100DCH002-: length 17.5
  TOP w0.203: v2(329.79,273.07) 330.08,272.77 330.08,269.29 329.03,268.23 SITE2.115
  vias: v1(390.16,286.32)
S2_3TX_100DCH003+: length 14.4
  TOP w0.203: v2(329,270.33) 328.7,270.03 328.7,268.82 328.63,268.74 SITE2.116
S2_3TX_100DCH003-: length 14.4
  TOP w0.203: v2(327.86,270.33) 328.16,270.03 328.16,268.81 328.23,268.74 SITE2.117
S2_3TX_100DCH004+: length 17.2
  TOP w0.203: SITE2.120 327.03,262.83 326.77,263.08 326.77,272.77 v2(327.07,273.07)
  vias: v1(416.2,254.57)
S2_3TX_100DCH004-: length 17.2
  TOP w0.203: v2(325.93,273.07) 326.23,272.77 326.23,262.85 326.63,262.45 SITE2.121
  vias: v1(417.34,254.57)
S2_3TX_100DCH005+: length 14.9
  TOP w0.203: SITE2.122 326.23,261.79 324.85,263.17 324.85,270.03 v2(325.14,270.33)
  vias: v1(375.3,267.91)
S2_3TX_100DCH005-: length 15
  TOP w0.203: v2(324,270.33) 324.3,270.03 324.3,262.94 325.83,261.41 SITE2.123
  vias: v1(376.45,267.91)
S2_3TX_100DCH006+: length 18.1
  TOP w0.203: SITE2.124 325.43,260.78 322.92,263.29 322.92,272.77 v2(323.21,273.07)
  vias: v1(375.3,254.32)
S2_3TX_100DCH006-: length 18.2
  TOP w0.203: v2(322.07,273.07) 322.37,272.77 322.37,263.06 325.03,260.4 SITE2.125
  vias: v1(376.45,254.32)
S2_3TX_100DCH007+: length 15.8
  TOP w0.203: v2(321.28,270.33) 320.99,270.03 320.99,263.26 324.63,259.62 SITE2.126
  vias: v1(375.56,299.91)
S2_3TX_100DCH007-: length 15.9
  TOP w0.203: SITE2.127 324.23,259.25 320.44,263.04 320.44,270.03 v2(320.14,270.33)
  vias: v1(376.7,299.91)
S2_4TX_100DCH001+: length 18.9
  TOP w0.203: 319.35,273.07 319.06,272.77 319.06,263.34 323.43,258.97 SITE2.129
  vias: v1(375.56,286.32)
S2_4TX_100DCH001-: length 18.9
  TOP w0.203: v2(318.21,273.07) 318.51,272.77 318.51,263.12 323.03,258.6 SITE2.130
  vias: v1(376.7,286.32)
S2_4TX_100DCH002+: length 16.6
  TOP w0.203: v2(317.43,270.33) 317.13,270.03 317.13,263.23 322.63,257.73 SITE2.131
  vias: v1(402.48,299.91)
S2_4TX_100DCH002-: length 16.7
  TOP w0.203: v2(316.28,270.33) 316.58,270.03 316.58,263 322.23,257.35 SITE2.132
  vias: v1(403.63,299.91)
S2_4TX_100DCH003+: length 17.5
  TOP w0.203: v2(304.36,259.35) 304.66,259.05 312.3,259.05 318.12,253.23 SITE2.133
  vias: v1(402.48,286.32)
S2_4TX_100DCH003-: length 17.4
  TOP w0.203: v2(304.36,258.21) 304.66,258.5 312.07,258.5 317.75,252.83 SITE2.134
  vias: v1(403.63,286.32)
S2_4TX_100DCH004+: length 13.7
  TOP w0.203: SITE2.135 317.02,252.43 312.32,257.12 307.95,257.12 v2(307.65,257.42)
  vias: v1(375.3,251.9)
S2_4TX_100DCH004-: length 13.7
  TOP w0.203: v2(307.65,256.28) 307.95,256.57 312.1,256.57 316.64,252.03 SITE2.136
  vias: v1(376.45,251.9)
S2_4TX_100DCH005+: length 16.6
  TOP w0.203: v2(304.36,255.49) 304.66,255.19 312.39,255.19 315.95,251.63 SITE2.137
  vias: v1(375.3,238.32)
S2_4TX_100DCH005-: length 16.5
  TOP w0.203: v2(304.36,254.35) 304.66,254.64 312.16,254.64 315.57,251.23 SITE2.138
  vias: v1(376.45,238.32)
S2_4TX_100DCH006+: length 12.8
  TOP w0.203: v2(307.65,253.18) 307.95,252.88 311.72,252.88 314.18,250.43 SITE2.140
S2_4TX_100DCH006-: length 12.8
  TOP w0.203: SITE2.141 313.8,250.03 311.5,252.33 307.95,252.33 v2(307.65,252.04)
S2_4TX_100DCH007+: length 15.6
  TOP w0.203: SITE2.142 313.03,249.63 311.71,250.95 304.66,250.95 v2(304.36,251.25)
S2_4TX_100DCH007-: length 15.6
  TOP w0.203: SITE2.143 312.66,249.23 311.48,250.4 304.66,250.4 v2(304.36,250.11)
S2_AUX_100DCH002+:
  vias: v1(289.31,132.08)
S2_AUX_100DCH002-:
  vias: v1(286.77,132.08)
S2_AUXCH+: length 32.3
  TOP w0.203: SITE2.21 330.23,236.2 v2(330.6,236.57)
  BOTTOM w0.203: 327.57,209.14 327.57,231.79 330.3,234.52 330.3,236.28 v2(330.6,236.57)
S2_AUXCH-: length 32.1
  TOP w0.203: v2(329.46,236.57) 329.83,236.2 SITE2.20
  BOTTOM w0.203: v2(329.46,236.57) 329.76,236.28 329.76,234.75 327.02,232.02 327.02,209.37
S2_AVDD11_RX: length 8.4
  TOP w0.231: SITE2.31 334.23,228.29 334.67,227.85
  TOP w0.508: v1(336.77,225.75) 334.67,227.85
  vias: v1(336.77,223.71)
S2_AVDD11_XTAL: length 8.8
  TOP w0.231: SITE2.105 333.03,260.95 332.87,261.11 332.87,261.45
  TOP w0.381: 332.87,261.45 332.87,263.59 333.72,264.44 v1(333.72,264.54)
  vias: v1(333.72,266.58)
S2_AVDD18_RX: length 7.7
  TOP w0.231: SITE2.25 331.83,230.56 331.28,230.01
  TOP w0.508: v1(331.06,225.75) 331.06,228.68 331.28,228.9 331.28,230.01
  vias: v1(331.06,223.71)
S2_DCH041: length 2.2
  TOP w0.231: v1(317.23,243.03) 317.43,242.83 SITE2.159
S2_DCH042: length 3.7
  TOP w0.231: SITE2.160 316.43,242.43 v1(315.83,243.03)
S2_DCH043: length 5.3
  TOP w0.231: v1(314.43,243.03) 315.44,242.03 SITE2.161
S2_DCH044: length 2.2
  TOP w0.231: v1(317.23,241.03) 317.43,241.23 SITE2.163
S2_DCH045: length 5.4
  TOP w0.231: SITE2.164 323.35,240.83 v1(324.35,239.83)
S2_DCH046: length 3.9
  TOP w0.231: SITE2.165 322.35,240.43 v1(322.95,239.83)
S2_DCH047: length 2.3
  TOP w0.231: v1(321.56,239.83) 321.36,240.03 SITE2.166
S2_DCH048:
  vias: v1(309.05,276.97)
S2_DCH049:
  vias: v1(309.05,271.67)
S2_DPS_F_001:
  vias: v1(287.77,130.81)
S2_DPS_F_002: length 10.1
  TOP w0.231: 320.65,229.55 321.72,229.55 323.03,230.86 SITE2.3
  TOP w0.508: 320.65,229.55 317.98,226.88 v1(317.98,225.75)
  vias: v1(316.32,222.9) v1(317.98,223.71)
S2_DPS_F_003: length 63.1
  TOP w0.231: SITE2.71 346.94,246.43 347.84,245.53 ; SITE2.63 344.9,243.23 345.2,242.93 ; 314.63,241.63 SITE2.162 ; SITE2.37 336.63,231.59 338.57,229.66 339.73,229.66 ; SITE2.107 332.23,260.11 331.69,260.65 331.69,261.16 ; SITE2.145 313.08,248.43 312.83,248.18 ; SITE2.17 328.63,229.5 329.28,228.85
  TOP w0.381: v1(331.94,264.54) 331.69,264.28 331.69,261.16
  TOP w0.508: v1(342.36,225.75) 342.36,227.02 339.73,229.66 ; v1(311.44,243.41) 312.59,243.41 314.37,241.63 314.63,241.63 ; v1(311.44,247.93) 312.58,247.93 312.83,248.18 ; 347.84,245.53 349.45,243.91 v1(351.22,243.91) ; v1(329.28,225.75) 329.28,228.85 ; v1(351.22,241.37) 348.11,241.37 346.8,242.67 345.45,242.67 345.2,242.93
  vias: v1(309.4,247.93) v1(309.4,243.41) v1(329.28,223.71) v1(331.94,266.58) v1(342.36,223.71) v1(353.27,243.91) v1(353.27,241.37) v1(464.57,235.71)
S2_DPS_F_006: length 9.6
  TOP w0.231: SITE2.72 347.92,246.83 348.55,246.19
  TOP w0.508: 348.55,246.19 349.56,245.18 v1(351.22,245.18)
  vias: v1(339,246.67) v1(353.27,245.18)
S2_DPS_F_007: length 19
  TOP w0.231: SITE2.78 344.15,249.23 344.37,249.01 ; SITE2.97 336.23,260.71 339.65,264.13 v1(339.65,264.54)
  TOP w0.508: 344.37,249.01 350.31,249.01 350.8,249.5 v1(351.22,249.5)
  vias: v1(339.65,266.58) v1(353.27,249.5)
S2_DPS_F_009: length 8.8
  TOP w0.231: SITE2.106 332.63,260.53 332.26,260.9 332.26,261.12
  TOP w0.381: v1(332.83,264.54) 332.83,264.39 332.26,263.82 332.26,261.12
  vias: v1(332.83,266.58) v1(333.61,267.66)
S2_DPS_F_010: length 8.6
  TOP w0.231: SITE2.111 330.63,260.15 331.05,260.57 331.05,261.13
  TOP w0.381: 331.05,261.13 v1(331.05,264.54)
  vias: v1(330.63,253.59) v1(331.05,266.58)
S2_DPS_F_011: length 17.6
  TOP w0.231: SITE2.119 327.43,257.79 327.64,258.01 ; SITE2.139 314.87,250.83 312.01,253.69 v1(311.44,253.69)
  TOP w0.508: v1(327.57,264.54) 327.64,264.47 327.64,258.01
  vias: v1(309.4,253.69) v1(327.57,266.58)
S2_DPS_F_012: length 8
  TOP w0.231: 312.2,248.83 SITE2.144
  TOP w0.508: v1(311.44,249.2) 311.81,248.83 312.2,248.83
  vias: v1(309.4,249.2)
S2_DPS_F_013:
  vias: v1(452.62,232.41) v1(452.62,224.79) v1(457.25,233.88) v1(474.87,217.23) v1(474.89,204.98) v1(474.99,218.59) v1(475.99,230.78) v1(478.43,217.17) v1(478.43,204.98) v1(478.53,230.78) v1(478.53,218.59) v1(480.97,204.98) v1(481.07,218.59) v1(482.1,241.3) v1(482.1,233.68) v1(483.51,204.98) v1(483.61,218.59) v1(489.86,212.91) v1(490.1,226.67)
S2_ISP00+: length 14.5
  TOP w0.203: v2(356.24,245.73) 355.95,246.03 350.09,246.03 348.89,247.23 SITE2.73
  vias: v1(386.29,257.11)
S2_ISP00-: length 14.5
  TOP w0.203: v2(356.24,246.87) 355.95,246.58 350.32,246.58 349.26,247.63 SITE2.74
  vias: v1(386.29,265.11)
S2_ISP14+: length 15.3
  TOP w0.203: SITE2.112 330.23,266.89 332.56,269.22 332.56,270.03 v2(332.86,270.33)
  vias: v1(390.69,257.11)
S2_ISP14-: length 15.2
  TOP w0.203: v2(331.72,270.33) 332.01,270.03 332.01,269.45 329.83,267.26 SITE2.113
  vias: v1(390.69,265.11)
S2_M_DPS_F_001: length 45.2
  TOP w0.231: SITE2.39 337.43,231.49 338.54,230.37 340.57,230.37 ; 313.24,247.18 313.7,247.63 SITE2.147 ; SITE2.104 333.43,263.21 ; 346.49,243.63 SITE2.64 ; 330.63,230.54 SITE2.22
  TOP w0.381: 333.43,263.21 334.61,264.39 v1(334.61,264.54)
  TOP w0.508: 313.24,247.18 312.72,246.66 v1(311.44,246.66) ; 346.49,243.63 347.49,243.63 348.48,242.64 v1(351.22,242.64) ; v1(343.63,225.75) 343.63,227.31 340.57,230.37 ; 330.63,230.54 330.38,230.28 330.38,229.17 330.17,228.96 v1(330.17,225.75)
  vias: v1(309.4,246.66) v1(330.17,223.71) v1(334.61,266.58) v1(343.63,223.71) v1(353.27,242.64)
S2_PS9G_DCH001: length 3.7
  TOP w0.231: v1(329.63,229.63) 329.03,230.23 SITE2.18
S2_PS9G_DCH002: length 2.2
  TOP w0.231: v1(329.63,231.03) 329.43,231.23 SITE2.19
S2_PS9G_DCH003: length 2.2
  TOP w0.231: SITE2.24 331.43,231.23 v1(331.23,231.03)
S2_PS9G_DCH004: length 2.2
  TOP w0.231: v1(337.63,235.23) 337.83,235.03 SITE2.40
S2_PS9G_DCH005: length 2.2
  TOP w0.231: v1(344.43,235.83) 344.23,236.03 SITE2.45
S2_PS9G_DCH006: length 3.7
  TOP w0.231: SITE2.46 345.23,236.43 v1(345.83,235.83)
S2_PS9G_DCH007: length 5.3
  TOP w0.231: v1(347.22,235.83) 346.22,236.83 SITE2.47
S2_PS9G_DCH009: length 2.2
  TOP w0.231: v1(344.43,237.43) 344.23,237.63 SITE2.49
S2_PS9G_DCH010: length 3.7
  TOP w0.231: SITE2.50 345.23,238.03 v1(345.83,237.43)
S2_PS9G_DCH011: length 5.3
  TOP w0.231: SITE2.51 346.22,238.43 v1(347.22,237.43)
S2_PS9G_DCH014: length 3.7
  TOP w0.231: v1(345.83,239.03) 345.23,239.63 SITE2.54
S2_PS9G_DCH015: length 5.3
  TOP w0.231: SITE2.55 346.22,240.03 v1(347.22,239.03)
S2_PS9G_DCH022: length 5.3
  TOP w0.231: SITE2.65 346.05,244.03 347.05,245.03 v1(347.22,245.03)
S2_PS9G_DCH023: length 2.5
  TOP w0.231: v1(344.43,245.03) 344.43,244.83 344.03,244.43 SITE2.66
S2_PS9G_DCH027: length 3.9
  TOP w0.231: v1(345.83,245.03) 344.83,246.03 SITE2.70
S2_PS9G_DCH028: length 2.3
  TOP w0.231: v1(340.23,248.46) 340.6,248.83 SITE2.77
S2_PS9G_DCH029: length 2.2
  TOP w0.231: v1(328.03,254.03) 327.83,254.23 SITE2.118
S2_PS9G_DCH030: length 9.2
  TOP w0.231: v1(310.91,245.39) 312.63,245.39 314.16,246.91 317.3,246.91 317.62,247.23 SITE2.148
S2_PS9G_DCH035: length 5.3
  TOP w0.231: v1(314.43,246.23) 315.44,245.23 SITE2.153
S2_PS9G_DCH036: length 2.2
  TOP w0.231: SITE2.154 321.23,244.83 v1(321.43,245.03)
S2_PS9G_DCH037: length 2.2
  TOP w0.231: v1(317.23,244.63) 317.43,244.43 SITE2.155
S2_PS9G_DCH038: length 3.7
  TOP w0.231: v1(315.83,244.63) 316.43,244.03 SITE2.156
S2_PS9G_DCH039: length 5.3
  TOP w0.231: v1(314.43,244.63) 315.44,243.63 SITE2.157
S2_PS9G_DCH040: length 2.2
  TOP w0.231: v1(321.43,243.43) 321.23,243.23 SITE2.158
S2_RLY_001:
  vias: v1(410.52,289.12) v1(410.52,273.37)
S2_RLY_003:
  vias: v1(369.63,273.11) v1(396.55,241.11)
S2_RLY_005:
  vias: v1(396.55,273.11) v1(396.55,257.37)
S2_RLY_007:
  vias: v1(383.09,273.11)
S2_RLY_008:
  vias: v1(383.09,289.12) v1(410.27,257.37)
S2_RLY_016:
  vias: v1(369.38,257.11) v1(369.63,289.12)
S2_RLY_018:
  vias: v1(312.25,276.97)
S2_RLY_021:
  vias: v1(369.38,241.11) v1(396.55,289.12)
S2_RLY_022:
  vias: v1(369.38,224.6) v1(383.09,241.11)
S2_RLY_023:
  vias: v1(383.09,224.85)
S2_RLY_025:
  vias: v1(376.23,209.11) v1(396.55,225.11)
S2_RLY_026:
  vias: v1(389.7,209.36)
S2_RLY_030:
  vias: v1(410.52,241.11)
S2_RLY_043:
  vias: v1(383.09,257.11)
S2_SCAN_DCH008: length 2.2
  TOP w0.231: v1(340.23,237.03) 340.43,237.23 SITE2.48
S2_SCAN_DCH012: length 2.2
  TOP w0.231: SITE2.52 340.43,238.83 v1(340.23,238.63)
S2_SCAN_DCH013: length 2.2
  TOP w0.231: v1(344.43,239.03) 344.23,239.23 SITE2.53
S2_SCAN_DCH016: length 2.2
  TOP w0.231: SITE2.56 340.43,240.43 v1(340.23,240.23)
S2_SCAN_DCH017: length 2.2
  TOP w0.231: SITE2.57 344.23,240.83 v1(344.43,240.63)
S2_SCAN_DCH018: length 3.7
  TOP w0.231: v1(345.83,240.63) 345.23,241.23 SITE2.58
S2_SCAN_DCH019: length 5.3
  TOP w0.231: v1(347.22,240.63) 346.22,241.63 SITE2.59
S2_SCAN_DCH020: length 2.2
  TOP w0.231: SITE2.60 340.43,242.03 v1(340.23,241.83)
S2_SCAN_DCH021: length 2.2
  TOP w0.231: SITE2.61 344.23,242.43 v1(344.43,242.23)
S2_SCAN_DCH024: length 2.2
  TOP w0.231: v1(340.23,244.63) 340.43,244.83 SITE2.67
S2_SCAN_DCH025: length 3.7
  TOP w0.231: SITE2.68 339.43,245.23 v1(338.83,244.63)
S2_SCAN_DCH026: length 5.3
  TOP w0.231: SITE2.69 338.44,245.63 v1(337.44,244.63)
S2_SCAN_DCH031: length 3.7
  TOP w0.231: SITE2.149 322.23,246.83 v1(322.83,247.43)
S2_SCAN_DCH032: length 5.3
  TOP w0.231: v1(324.22,247.43) 323.22,246.43 SITE2.150
S2_SCAN_DCH033: length 2.2
  TOP w0.231: SITE2.151 317.43,246.03 v1(317.23,246.23)
S2_SCAN_DCH034: length 3.7
  TOP w0.231: v1(315.83,246.23) 316.43,245.63 SITE2.152
S2_SPI_1_CSN:
  vias: v1(474.99,230.78)
S2_SPI_1_SCK:
  vias: v1(480.07,218.59)
S2_SPI_1_SDI:
  vias: v1(456.19,217.17)
S2_SPI_1_SDO:
  vias: v1(455.94,209.55)
S2_SPI_2_CSN:
  vias: v1(475.87,217.23)
S2_SPI_2_SCK:
  vias: v1(479.97,204.98)
S2_SPI_2_SDI:
  vias: v1(451.62,217.17)
S2_SPI_2_SDO:
  vias: v1(451.87,209.55)
S2_SPI_11_SDI:
  vias: v1(457.19,217.17) v1(477.53,230.78)
S2_SPI_11_SDO:
  vias: v1(456.94,209.55) v1(482.61,218.59)
S2_SPI_22_SDI:
  vias: v1(452.62,217.17) v1(477.43,217.17)
S2_SPI_22_SDO:
  vias: v1(452.87,209.55) v1(482.51,204.98)
S2_SPI_CSN: length 25.9
  TOP w0.231: SITE2.43 339.03,231.23 v1(339.23,231.03)
  BOTTOM w0.231: 330.11,219.95 330.61,220.44 332.25,220.44 332.91,221.11 332.91,233.59 333.57,234.25 335.17,234.25 338.4,231.03 v1(339.23,231.03)
S2_SPI_SCK: length 25.3
  TOP w0.231: v1(338.83,235.23) 338.63,235.03 SITE2.42
  BOTTOM w0.231: v1(338.83,235.23) 338.83,233.98 340.53,232.28 340.53,229.11 339.96,228.54 337.9,228.54 337.17,229.27 335.92,229.27 335.03,228.39 335.03,218.48
S2_SPI_SDI: length 34.1
  TOP w0.231: v1(338.83,236.63) 339.43,236.03 SITE2.44
  BOTTOM w0.231: v1(338.83,236.63) 342.6,232.86 342.6,227.63 342.04,227.06 338.85,227.06 338.07,226.28 338.07,211.53
S2_SPI_SDO: length 37
  TOP w0.231: SITE2.41 338.23,236.03 v1(337.63,236.63)
  BOTTOM w0.231: v1(337.63,236.63) 338.83,237.83 341.5,237.83 342.29,237.04 342.29,235.83 344.72,233.4 344.72,210.32
S2_XTAL_IN: length 28.3
  TOP w0.231: SITE2.109 331.43,258.03 v1(331.63,258.23)
  BOTTOM w0.231: v1(331.63,258.23) 327.82,258.23 318.94,267.1 318.94,271.27 314.98,275.24
  vias: v1(306.85,271.67)
S2_XTAL_OUT: length 26.8
  TOP w0.231: SITE2.110 331.03,259.03 v1(331.63,259.63)
  BOTTOM w0.231: 318.8,276.35 320.8,274.36 320.8,272.93 322.59,271.15 322.59,266.87 329.83,259.63 v1(331.63,259.63)
  vias: v1(306.85,276.97)
S3_1TX_100DCH001+:
  vias: v1(184.47,176.66) v1(276.97,144.59)
S3_1TX_100DCH001-:
  vias: v1(192.47,176.66) v1(275.82,144.59)
S3_1TX_100DCH002+: length 17.1
  TOP w0.203: v2(279.29,187.66) 278.99,187.96 270.62,187.96 270.55,188.03 SITE3.75
  vias: v1(276.97,158.18)
S3_1TX_100DCH002-: length 17.1
  TOP w0.203: v2(279.29,188.8) 278.99,188.5 270.66,188.5 270.59,188.43 SITE3.76
  vias: v1(275.82,158.18)
S3_1TX_100DCH003+: length 14.4
  TOP w0.203: v2(276.24,190.09) 275.95,190.39 270.77,190.39 270.01,189.63 SITE3.79
  vias: v1(250.81,129.35)
S3_1TX_100DCH003-: length 14.4
  TOP w0.203: v2(276.24,191.23) 275.95,190.94 270.54,190.94 269.64,190.03 SITE3.80
  vias: v1(249.66,129.35)
S3_1TX_100DCH004+: length 17.9
  TOP w0.203: SITE3.81 268.78,190.43 270.67,192.32 278.99,192.32 v2(279.29,192.02)
  vias: v1(250.81,142.94)
S3_1TX_100DCH004-: length 17.9
  TOP w0.203: SITE3.82 268.41,190.83 270.44,192.87 278.99,192.87 v2(279.29,193.16)
  vias: v1(249.66,142.94)
S3_1TX_100DCH005+: length 15.3
  TOP w0.203: SITE3.83 267.29,191.23 270.31,194.25 275.95,194.25 v2(276.24,193.95)
  vias: v1(264.01,132.4)
S3_1TX_100DCH005-: length 15.3
  TOP w0.203: SITE3.84 266.92,191.63 270.08,194.79 275.95,194.79 v2(276.24,195.09)
  vias: v1(262.87,132.4)
S3_1TX_100DCH006+: length 18.8
  TOP w0.203: v2(279.29,195.88) 278.99,196.18 269.86,196.18 265.71,192.03 SITE3.85
  vias: v1(264.01,145.99)
S3_1TX_100DCH006-: length 18.9
  TOP w0.203: SITE3.86 265.34,192.43 269.63,196.72 278.99,196.72 v2(279.29,197.02)
  vias: v1(262.87,145.99)
S3_1TX_100DCH007+: length 16.2
  TOP w0.203: SITE3.87 263.9,192.83 269.17,198.1 275.95,198.1 v2(276.24,197.81)
  vias: v1(178.5,176.13)
S3_1TX_100DCH007-: length 16.3
  TOP w0.203: SITE3.88 263.52,193.23 268.95,198.65 275.95,198.65 v2(276.24,198.95)
  vias: v1(178.5,174.99)
S3_2AUX+:
  vias: v1(192.78,132.33) v1(192.78,131.06)
S3_2AUX-:
  vias: v1(189.24,131.06) v1(190.24,132.33)
S3_2TX_100DCH001+: length 16.3
  TOP w0.086: v2(267.64,208.93) 267.21,208.5 267.21,207.72 266.7,207.21 266.7,206.7 259.35,199.35 259.35,197.86 259.43,197.78 SITE3.89
  vias: v1(164.91,176.13)
S3_2TX_100DCH001-: length 16.3
  TOP w0.086: v2(266.5,208.93) 266.97,208.46 266.97,207.82 266.46,207.31 266.46,206.8 259.11,199.45 259.11,197.86 259.03,197.78 SITE3.90
  vias: v1(164.91,174.99)
S3_2TX_100DCH002+: length 14.1
  TOP w0.086: SITE3.91 258.63,197.78 258.55,197.86 258.55,199.57 265.28,206.3 265.28,206.78 v2(265.72,207.21)
  vias: v1(195.26,217.02)
S3_2TX_100DCH002-: length 14.1
  TOP w0.086: v2(264.57,207.21) 265.04,206.74 265.04,206.4 258.31,199.66 258.31,197.86 258.23,197.78 SITE3.92
  vias: v1(195.26,215.88)
S3_2TX_100DCH003+: length 15.3
  TOP w0.086: SITE3.93 257.83,197.78 257.75,197.86 257.75,199.78 263.33,205.37 263.33,208.48 v2(263.79,208.93)
  vias: v1(181.67,217.02)
S3_2TX_100DCH003-: length 15.3
  TOP w0.086: SITE3.94 257.43,197.78 257.51,197.86 257.51,199.88 263.1,205.47 263.1,208.48 v2(262.64,208.93)
  vias: v1(181.67,215.88)
S3_2TX_100DCH004+: length 13.1
  TOP w0.086: v2(261.86,207.21) 261.41,206.77 261.41,204.71 256.95,200.25 256.95,197.86 257.03,197.78 SITE3.95
  vias: v1(212.03,217.02)
S3_2TX_100DCH004-:
  vias: v1(212.03,215.88)
S3_2TX_100DCH005+: length 14.6
  TOP w0.086: v2(259.93,208.93) 259.48,208.49 259.48,207.61 258.83,206.95 258.83,204.33 255.75,201.25 255.75,197.86 255.83,197.78 SITE3.98
  vias: v1(198.44,217.02)
S3_2TX_100DCH005-: length 14.6
  TOP w0.086: v2(258.78,208.93) 259.24,208.47 259.24,207.71 258.59,207.05 258.59,204.43 255.51,201.35 255.51,197.86 255.43,197.78 SITE3.99
  vias: v1(198.44,215.88)
S3_2TX_100DCH006+: length 12.4
  TOP w0.086: SITE3.100 255.03,197.78 254.95,197.86 254.95,201.55 257.56,204.16 257.56,206.77 v2(258,207.21)
  vias: v1(195.26,203.56)
S3_2TX_100DCH006-: length 12.4
  TOP w0.086: SITE3.101 254.63,197.78 254.71,197.86 254.71,201.65 257.32,204.26 257.32,206.75 v2(256.85,207.21)
  vias: v1(195.26,202.42)
S3_2TX_100DCH007+: length 13.6
  TOP w0.086: SITE3.102 254.23,197.78 254.15,197.86 254.15,202.19 255.63,203.67 255.63,208.49 v2(256.07,208.93)
  vias: v1(181.67,203.56)
S3_2TX_100DCH007-: length 13.6
  TOP w0.086: v2(254.93,208.93) 255.39,208.47 255.39,203.77 253.91,202.29 253.91,197.86 253.83,197.78 SITE3.103
  vias: v1(181.67,202.42)
S3_3TX_100DCH002+: length 15.4
  TOP w0.203: SITE3.114 249.43,207.85 250.59,209.01 250.59,210.53 v2(250.93,210.87)
  vias: v1(181.67,189.59)
S3_3TX_100DCH002-: length 15.3
  TOP w0.203: SITE3.115 249.03,208.23 250.09,209.29 250.09,210.09 249.79,210.39 v2(249.79,210.87)
  vias: v1(181.67,188.45)
S3_3TX_100DCH003+: length 13.2
  TOP w0.203: SITE3.116 248.63,208.74 248.66,208.77 248.66,208.81 v2(249,209.15)
  vias: v1(178.5,203.56)
S3_3TX_100DCH003-: length 13.2
  TOP w0.203: v2(247.86,209.15) 248.2,208.81 248.2,208.77 248.23,208.74 SITE3.117
  vias: v1(178.5,202.42)
S3_3TX_100DCH004+: length 15
  TOP w0.203: SITE3.120 247.03,202.83 246.73,203.13 246.73,210.53 v2(247.07,210.87)
  vias: v1(164.91,203.56)
S3_3TX_100DCH004-: length 15
  TOP w0.203: v2(245.93,210.87) 246.27,210.53 246.27,202.81 246.63,202.45 SITE3.121
  vias: v1(164.91,202.42)
S3_3TX_100DCH005+: length 13.7
  TOP w0.203: v2(245.14,209.15) 245.14,208.67 244.85,208.37 244.85,203.17 246.23,201.79 SITE3.122
  vias: v1(212.03,203.56)
S3_3TX_100DCH005-: length 13.8
  TOP w0.203: v2(244,209.15) 244.34,208.81 244.34,202.9 245.83,201.41 SITE3.123
  vias: v1(212.03,202.42)
S3_3TX_100DCH006+: length 15.9
  TOP w0.203: SITE3.124 245.43,200.78 242.92,203.29 242.92,210.09 243.21,210.39 v2(243.21,210.87)
  vias: v1(198.44,203.56)
S3_3TX_100DCH006-: length 16.1
  TOP w0.203: SITE3.125 245.03,200.4 242.48,202.95 242.48,210.7 v2(242.14,211.04)
  vias: v1(198.44,202.42)
S3_3TX_100DCH007+: length 14.7
  TOP w0.203: SITE3.126 244.63,199.62 240.99,203.27 240.99,208.37 241.28,208.67 v2(241.28,209.15)
  vias: v1(178.5,189.59)
S3_3TX_100DCH007-: length 14.7
  TOP w0.203: SITE3.127 244.23,199.25 240.48,202.99 240.48,208.81 v2(240.14,209.15)
  vias: v1(178.5,188.45)
S3_4TX_100DCH001+: length 16.7
  TOP w0.203: v2(239.35,210.87) 239.01,210.53 239.01,203.39 243.43,198.97 SITE3.129
  vias: v1(164.91,189.59)
S3_4TX_100DCH001-: length 16.9
  TOP w0.203: SITE3.130 243.03,198.6 238.55,203.07 238.55,210.28 238.28,210.55 v2(238.28,211.04)
  vias: v1(164.91,188.45)
S3_4TX_100DCH002+: length 15.4
  TOP w0.203: SITE3.131 242.63,197.73 237.13,203.23 237.13,208.37 237.43,208.67 v2(237.43,209.15)
  vias: v1(212.03,189.59)
S3_4TX_100DCH002-: length 15.5
  TOP w0.203: v2(236.28,209.15) 236.62,208.81 236.62,202.96 242.23,197.35 SITE3.132
  vias: v1(212.03,188.45)
S3_4TX_100DCH003+: length 17.2
  TOP w0.203: SITE3.133 238.12,193.23 232.2,199.16 224.97,199.16 v2(224.67,199.45)
  vias: v1(198.44,189.59)
S3_4TX_100DCH003-: length 17.2
  TOP w0.203: SITE3.134 237.75,192.83 231.97,198.61 224.97,198.61 v2(224.67,198.31)
  vias: v1(198.44,188.45)
S3_4TX_100DCH004+: length 13.5
  TOP w0.203: v2(227.97,197.52) 228.27,197.23 232.22,197.23 237.02,192.43 SITE3.135
  vias: v1(178.5,162.67)
S3_4TX_100DCH004-: length 13.4
  TOP w0.203: v2(227.97,196.38) 228.27,196.68 231.99,196.68 236.64,192.03 SITE3.136
  vias: v1(178.5,161.52)
S3_4TX_100DCH005+: length 16.3
  TOP w0.203: SITE3.137 235.95,191.63 232.28,195.3 224.97,195.3 v2(224.67,195.59)
  vias: v1(164.91,162.67)
S3_4TX_100DCH005-: length 16.2
  TOP w0.203: v2(224.67,194.45) 224.97,194.75 232.06,194.75 235.57,191.23 SITE3.138
  vias: v1(164.91,161.52)
S3_4TX_100DCH006+: length 12.5
  TOP w0.203: v2(227.97,193.28) 228.27,192.99 231.62,192.99 234.18,190.43 SITE3.140
  vias: v1(178.5,148.95)
S3_4TX_100DCH006-: length 12.5
  TOP w0.203: SITE3.141 233.8,190.03 231.39,192.44 228.27,192.44 v2(227.97,192.14)
  vias: v1(178.5,147.81)
S3_4TX_100DCH007+: length 15.4
  TOP w0.203: SITE3.142 233.03,189.63 231.61,191.06 224.97,191.06 v2(224.67,191.35)
  vias: v1(164.91,148.95)
S3_4TX_100DCH007-: length 15.3
  TOP w0.203: SITE3.143 232.66,189.23 231.38,190.51 224.97,190.51 v2(224.67,190.21)
  vias: v1(164.91,147.81)
S3_AUX_100DCH002+:
  vias: v1(191.78,132.33)
S3_AUX_100DCH002-:
  vias: v1(189.24,132.33)
S3_AUXCH+: length 32.3
  TOP w0.203: SITE3.21 250.23,176.2 v2(250.6,176.57)
  BOTTOM w0.203: v2(250.6,176.57) 250.3,176.28 250.3,174.52 247.57,171.79 247.57,149.14
S3_AUXCH-: length 32.1
  TOP w0.203: v2(249.46,176.57) 249.83,176.2 SITE3.20
  BOTTOM w0.203: 247.03,149.37 247.03,172.02 249.76,174.75 249.76,176.28 v2(249.46,176.57)
S3_AVDD11_RX: length 8.4
  TOP w0.231: SITE3.31 254.23,168.29 254.67,167.85
  TOP w0.508: v1(256.77,165.75) 254.67,167.85
  vias: v1(256.77,163.71)
S3_AVDD11_XTAL: length 8.8
  TOP w0.231: 252.87,201.45 252.87,201.11 253.03,200.95 SITE3.105
  TOP w0.381: v1(253.72,204.54) 253.72,204.45 252.87,203.59 252.87,201.45
  vias: v1(253.72,206.58)
S3_AVDD18_RX: length 7.7
  TOP w0.231: 251.28,170.01 251.83,170.56 SITE3.25
  TOP w0.508: v1(251.06,165.75) 251.06,168.68 251.28,168.9 251.28,170.01
  vias: v1(251.06,163.71)
S3_DCH041: length 2.2
  TOP w0.231: SITE3.159 237.43,182.83 v1(237.23,183.03)
S3_DCH042: length 3.7
  TOP w0.231: SITE3.160 236.43,182.43 v1(235.83,183.03)
S3_DCH043: length 5.3
  TOP w0.231: SITE3.161 235.44,182.03 v1(234.44,183.03)
S3_DCH044: length 2.2
  TOP w0.231: v1(237.23,181.03) 237.43,181.23 SITE3.163
S3_DCH045: length 5.4
  TOP w0.231: v1(244.35,179.83) 243.35,180.83 SITE3.164
S3_DCH046: length 3.9
  TOP w0.231: v1(242.95,179.83) 242.35,180.43 SITE3.165
S3_DCH047: length 2.3
  TOP w0.231: v1(241.56,179.83) 241.36,180.03 SITE3.166
S3_DPS_F_001:
  vias: v1(190.24,131.06)
S3_DPS_F_002: length 10.1
  TOP w0.231: SITE3.3 243.03,170.86 241.72,169.55 240.65,169.55
  TOP w0.508: 240.65,169.55 237.98,166.88 v1(237.98,165.75)
  vias: v1(236.32,162.9) v1(237.98,163.71)
S3_DPS_F_003: length 63.1
  TOP w0.231: SITE3.107 252.23,200.11 251.69,200.65 251.69,201.16 ; 265.2,182.93 264.9,183.23 SITE3.63 ; 267.84,185.53 266.94,186.43 SITE3.71 ; 234.63,181.63 SITE3.162 ; 232.83,188.18 233.08,188.43 SITE3.145 ; 259.73,169.66 258.57,169.66 256.63,171.59 SITE3.37 ; 249.28,168.85 248.63,169.5 SITE3.17
  TOP w0.381: 251.69,201.16 251.69,204.28 v1(251.94,204.54)
  TOP w0.508: v1(231.44,187.93) 232.58,187.93 232.83,188.18 ; v1(271.22,181.37) 268.11,181.37 266.8,182.68 265.45,182.68 265.2,182.93 ; v1(262.36,165.75) 262.36,167.02 259.73,169.66 ; v1(231.44,183.41) 232.59,183.41 234.37,181.63 234.63,181.63 ; v1(271.22,183.91) 269.46,183.91 267.84,185.53 ; v1(249.28,165.75) 249.28,168.85
  vias: v1(229.4,187.93) v1(229.4,183.41) v1(249.28,163.71) v1(251.94,206.58) v1(262.36,163.71) v1(273.27,183.91) v1(273.27,181.37)
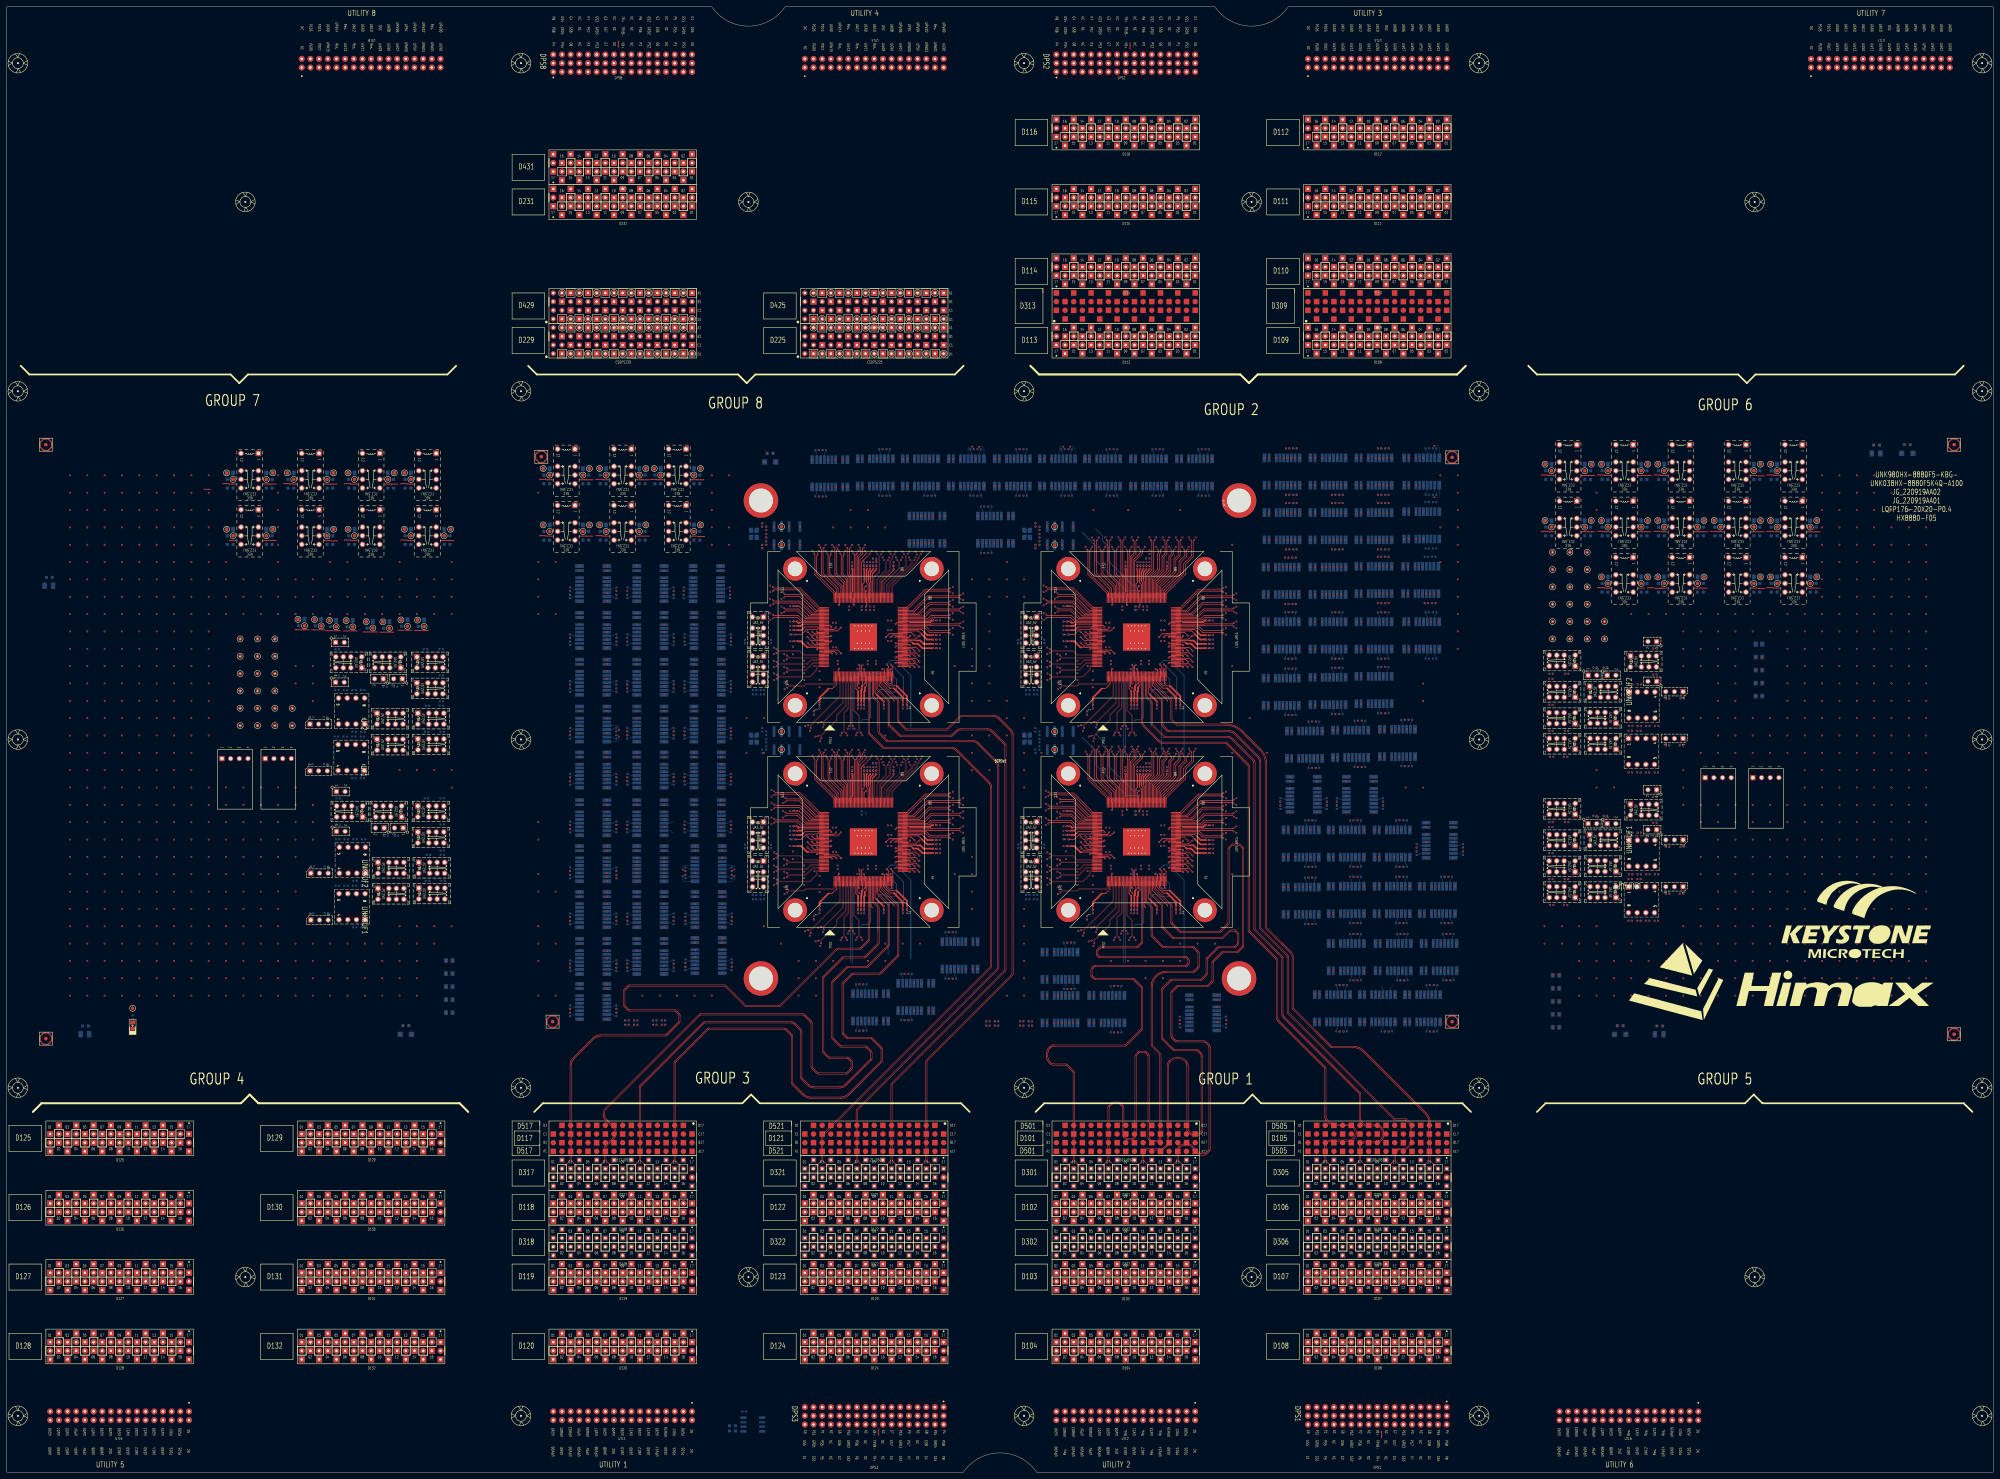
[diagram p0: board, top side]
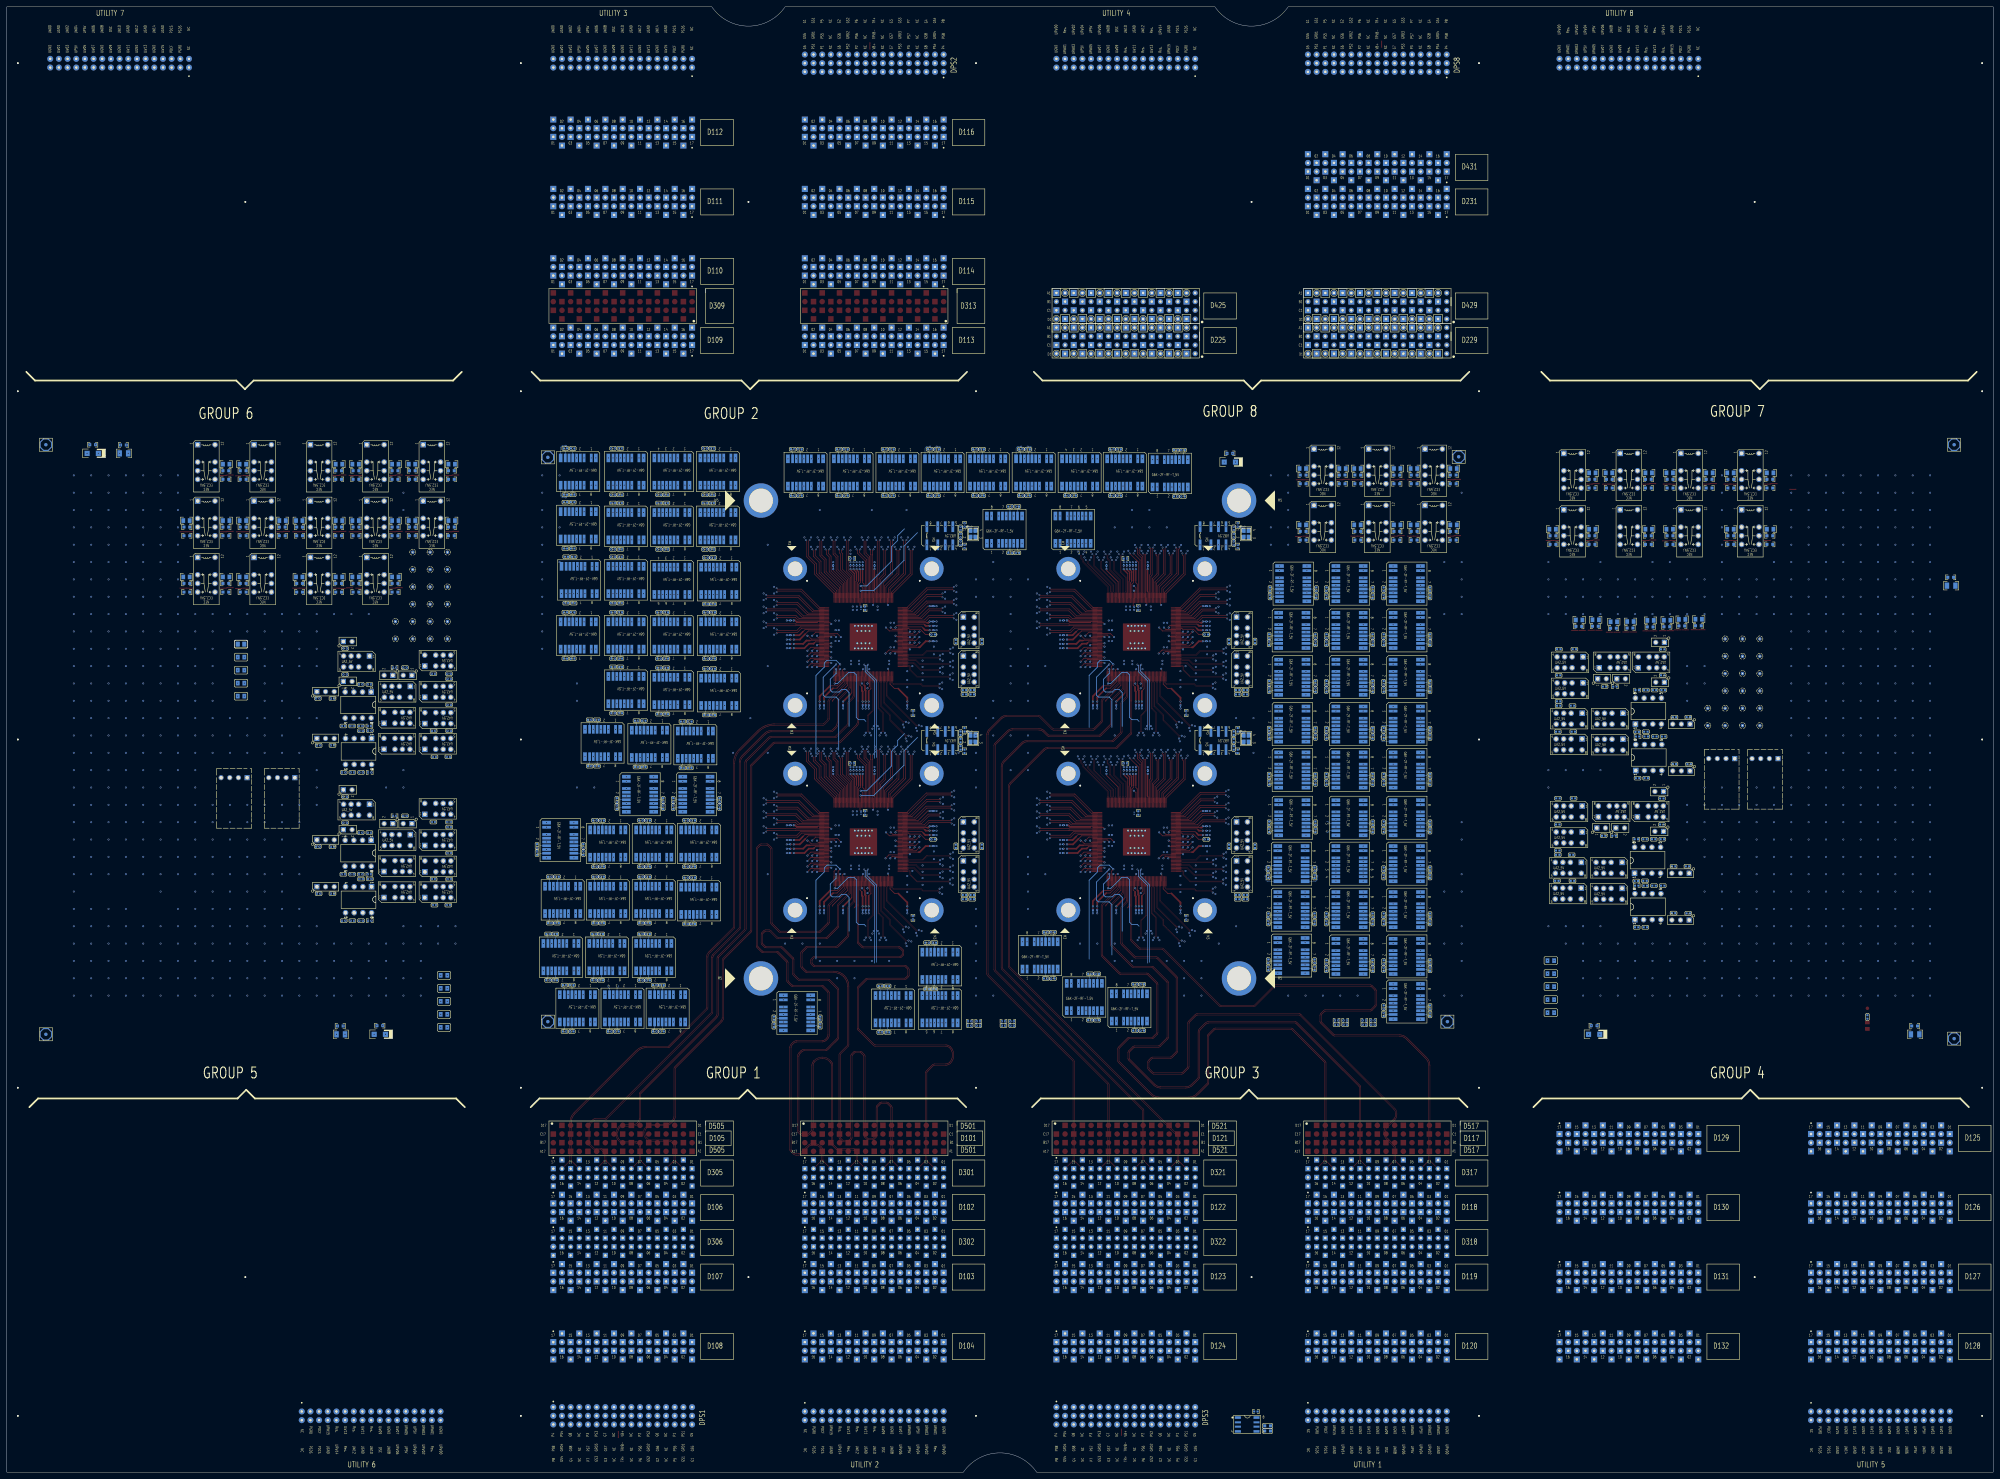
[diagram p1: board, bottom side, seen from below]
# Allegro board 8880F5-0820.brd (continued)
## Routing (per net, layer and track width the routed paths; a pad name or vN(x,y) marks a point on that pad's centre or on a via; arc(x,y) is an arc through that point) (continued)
S3_DPS_F_006: length 9.6
  TOP w0.231: 268.55,186.19 267.92,186.83 SITE3.72
  TOP w0.508: v1(271.22,185.18) 269.56,185.18 268.55,186.19
  vias: v1(259,186.67) v1(273.27,185.18)
S3_DPS_F_007: length 19
  TOP w0.231: SITE3.97 256.23,200.71 259.65,204.13 v1(259.65,204.54) ; SITE3.78 264.15,189.23 264.37,189.01
  TOP w0.508: v1(271.22,189.5) 270.8,189.5 270.31,189.01 264.37,189.01
  vias: v1(259.65,206.58) v1(273.27,189.5)
S3_DPS_F_009: length 8.8
  TOP w0.231: SITE3.106 252.63,200.53 252.26,200.9 252.26,201.12
  TOP w0.381: v1(252.83,204.54) 252.83,204.39 252.26,203.82 252.26,201.12
  vias: v1(252.83,206.58) v1(253.61,207.66)
S3_DPS_F_010: length 8.6
  TOP w0.231: SITE3.111 250.63,200.15 251.05,200.57 251.05,201.13
  TOP w0.381: 251.05,201.13 v1(251.05,204.54)
  vias: v1(251.05,206.58)
S3_DPS_F_011: length 17.6
  TOP w0.231: v1(231.44,193.69) 232.01,193.69 234.87,190.83 SITE3.139 ; 247.64,198.01 247.43,197.79 SITE3.119
  TOP w0.508: v1(247.57,204.54) 247.64,204.47 247.64,198.01
  vias: v1(229.4,193.69) v1(247.57,206.58)
S3_DPS_F_012: length 8
  TOP w0.231: 232.2,188.83 SITE3.144
  TOP w0.508: v1(231.44,189.2) 231.81,188.83 232.2,188.83
  vias: v1(229.4,189.2)
S3_ISP00+: length 14.5
  TOP w0.203: SITE3.73 268.89,187.23 270.09,186.03 275.95,186.03 v2(276.24,185.73)
  vias: v1(184.47,178.86)
S3_ISP00-: length 14.5
  TOP w0.203: SITE3.74 269.26,187.63 270.32,186.58 275.95,186.58 v2(276.24,186.87)
  vias: v1(192.47,178.86)
S3_ISP14+: length 14.1
  TOP w0.203: v2(252.86,209.15) 250.87,207.16 250.81,207.16 250.47,206.82 250.47,206.76 250.23,206.52 SITE3.112
  vias: v1(184.47,174.46)
S3_ISP14-: length 13.8
  TOP w0.203: v2(251.72,209.15) 249.83,207.26 SITE3.113
  vias: v1(192.47,174.46)
S3_M_DPS_F_001: length 45.2
  TOP w0.231: 233.24,187.18 233.7,187.63 SITE3.147 ; SITE3.39 257.43,171.49 258.54,170.37 260.57,170.37 ; 266.49,183.63 SITE3.64 ; 250.63,170.54 SITE3.22 ; SITE3.104 253.43,203.21
  TOP w0.381: v1(254.61,204.54) 254.61,204.39 253.43,203.21
  TOP w0.508: v1(271.22,182.64) 268.48,182.64 267.49,183.63 266.49,183.63 ; v1(231.44,186.66) 232.72,186.66 233.24,187.18 ; v1(263.63,165.75) 263.63,167.31 260.57,170.37 ; v1(250.17,165.75) 250.17,168.96 250.38,169.17 250.38,170.28 250.63,170.54
  vias: v1(229.4,186.66) v1(250.17,163.71) v1(254.61,206.58) v1(263.63,163.71) v1(273.27,182.64)
S3_PS9G_DCH001: length 3.7
  TOP w0.231: SITE3.18 249.03,170.23 v1(249.63,169.63)
S3_PS9G_DCH002: length 2.2
  TOP w0.231: SITE3.19 249.43,171.23 v1(249.63,171.03)
S3_PS9G_DCH003: length 2.2
  TOP w0.231: v1(251.23,171.03) 251.43,171.23 SITE3.24
S3_PS9G_DCH004: length 2.2
  TOP w0.231: v1(257.63,175.23) 257.83,175.03 SITE3.40
S3_PS9G_DCH005: length 2.2
  TOP w0.231: SITE3.45 264.23,176.03 v1(264.43,175.83)
S3_PS9G_DCH006: length 3.7
  TOP w0.231: SITE3.46 265.23,176.43 v1(265.83,175.83)
S3_PS9G_DCH007: length 5.3
  TOP w0.231: SITE3.47 266.22,176.83 v1(267.23,175.83)
S3_PS9G_DCH009: length 2.2
  TOP w0.231: SITE3.49 264.23,177.63 v1(264.43,177.43)
S3_PS9G_DCH010: length 3.7
  TOP w0.231: SITE3.50 265.23,178.03 v1(265.83,177.43)
S3_PS9G_DCH011: length 5.3
  TOP w0.231: v1(267.23,177.43) 266.22,178.43 SITE3.51
S3_PS9G_DCH014: length 3.7
  TOP w0.231: v1(265.83,179.03) 265.23,179.63 SITE3.54
S3_PS9G_DCH015: length 5.3
  TOP w0.231: SITE3.55 266.22,180.03 v1(267.23,179.03)
S3_PS9G_DCH022: length 5.3
  TOP w0.231: SITE3.65 266.05,184.03 267.05,185.03 v1(267.23,185.03)
S3_PS9G_DCH023: length 2.5
  TOP w0.231: v1(264.43,185.03) 264.43,184.83 264.03,184.43 SITE3.66
S3_PS9G_DCH027: length 3.9
  TOP w0.231: SITE3.70 264.83,186.03 v1(265.83,185.03)
S3_PS9G_DCH028: length 2.3
  TOP w0.231: v1(260.23,188.46) 260.6,188.83 SITE3.77
S3_PS9G_DCH030: length 9.2
  TOP w0.231: v1(230.91,185.39) 232.63,185.39 234.16,186.91 237.3,186.91 237.62,187.23 SITE3.148
S3_PS9G_DCH035: length 5.3
  TOP w0.231: SITE3.153 235.44,185.23 v1(234.44,186.23)
S3_PS9G_DCH036: length 2.2
  TOP w0.231: SITE3.154 241.23,184.83 v1(241.43,185.03)
S3_PS9G_DCH037: length 2.2
  TOP w0.231: SITE3.155 237.43,184.43 v1(237.23,184.63)
S3_PS9G_DCH038: length 3.7
  TOP w0.231: v1(235.83,184.63) 236.43,184.03 SITE3.156
S3_PS9G_DCH039: length 5.3
  TOP w0.231: v1(234.44,184.63) 235.44,183.63 SITE3.157
S3_PS9G_DCH040: length 2.2
  TOP w0.231: SITE3.158 241.23,183.23 v1(241.43,183.43)
S3_RLY_001:
  vias: v1(256.73,140.14) v1(282.9,155.38)
S3_RLY_003:
  vias: v1(167.7,182.06) v1(269.94,143.19)
S3_RLY_005:
  vias: v1(184.47,222.95) v1(201.23,222.95)
S3_RLY_007:
  vias: v1(184.47,209.49)
S3_RLY_008:
  vias: v1(167.7,209.49) v1(184.47,195.52)
S3_RLY_016:
  vias: v1(167.7,195.52) v1(201.23,209.49)
S3_RLY_021:
  vias: v1(167.7,168.6) v1(201.23,195.52)
S3_RLY_022:
  vias: v1(184.47,154.88) v1(201.49,155.13)
S3_RLY_023:
  vias: v1(167.7,141.67)
S3_RLY_025:
  vias: v1(201.49,182.06) v1(201.49,168.6)
S3_RLY_026:
  vias: v1(184.47,168.6)
S3_RLY_030:
  vias: v1(167.7,154.88)
S3_RLY_043:
  vias: v1(184.47,182.06)
S3_SCAN_DCH008: length 2.2
  TOP w0.231: SITE3.48 260.43,177.23 v1(260.23,177.03)
S3_SCAN_DCH012: length 2.2
  TOP w0.231: v1(260.23,178.63) 260.43,178.83 SITE3.52
S3_SCAN_DCH013: length 2.2
  TOP w0.231: SITE3.53 264.23,179.23 v1(264.43,179.03)
S3_SCAN_DCH016: length 2.2
  TOP w0.231: SITE3.56 260.43,180.43 v1(260.23,180.23)
S3_SCAN_DCH017: length 2.2
  TOP w0.231: SITE3.57 264.23,180.83 v1(264.43,180.63)
S3_SCAN_DCH018: length 3.7
  TOP w0.231: v1(265.83,180.63) 265.23,181.23 SITE3.58
S3_SCAN_DCH019: length 5.3
  TOP w0.231: v1(267.23,180.63) 266.22,181.63 SITE3.59
S3_SCAN_DCH020: length 2.2
  TOP w0.231: SITE3.60 260.43,182.03 v1(260.23,181.83)
S3_SCAN_DCH021: length 2.2
  TOP w0.231: v1(264.43,182.23) 264.23,182.43 SITE3.61
S3_SCAN_DCH024: length 2.2
  TOP w0.231: v1(260.23,184.63) 260.43,184.83 SITE3.67
S3_SCAN_DCH025: length 3.7
  TOP w0.231: SITE3.68 259.43,185.23 v1(258.83,184.63)
S3_SCAN_DCH026: length 5.3
  TOP w0.231: v1(257.44,184.63) 258.44,185.63 SITE3.69
S3_SCAN_DCH031: length 3.7
  TOP w0.231: SITE3.149 242.23,186.83 v1(242.83,187.43)
S3_SCAN_DCH032: length 5.3
  TOP w0.231: v1(244.22,187.43) 243.22,186.43 SITE3.150
S3_SCAN_DCH033: length 2.2
  TOP w0.231: SITE3.151 237.43,186.03 v1(237.23,186.23)
S3_SCAN_DCH034: length 3.7
  TOP w0.231: v1(235.83,186.23) 236.43,185.63 SITE3.152
S3_SPI_CSN: length 25.9
  TOP w0.231: SITE3.43 259.03,171.23 v1(259.23,171.03)
  BOTTOM w0.231: 250.11,159.95 250.61,160.44 252.25,160.44 252.91,161.11 252.91,173.59 253.58,174.25 255.17,174.25 258.4,171.03 v1(259.23,171.03)
S3_SPI_SCK: length 25.3
  TOP w0.231: SITE3.42 258.63,175.03 v1(258.83,175.23)
  BOTTOM w0.231: v1(258.83,175.23) 258.83,173.98 260.53,172.28 260.53,169.11 259.96,168.54 257.9,168.54 257.17,169.27 255.92,169.27 255.03,168.39 255.03,158.48
S3_SPI_SDI: length 34.1
  TOP w0.231: v1(258.83,176.63) 259.43,176.03 SITE3.44
  BOTTOM w0.231: 258.07,151.53 258.07,166.28 258.85,167.06 262.04,167.06 262.6,167.63 262.6,172.86 v1(258.83,176.63)
S3_SPI_SDO: length 37
  TOP w0.231: v1(257.63,176.63) 258.23,176.03 SITE3.41
  BOTTOM w0.231: 264.72,150.32 264.72,173.4 262.29,175.83 262.29,177.04 261.5,177.83 258.83,177.83 v1(257.63,176.63)
S3_XTAL_OUT: length 3.7
  TOP w0.231: v1(251.63,199.63) 251.03,199.03 SITE3.110
S4_1TX_100DCH001+:
  vias: v1(310.01,131.64) v1(421.02,174.43)
S4_1TX_100DCH001-:
  vias: v1(310.01,139.64) v1(422.17,174.43)
S4_1TX_100DCH002+: length 17.1
  TOP w0.203: v2(359.29,187.66) 358.99,187.96 350.62,187.96 350.55,188.03 SITE4.75
  vias: v1(421.02,160.85)
S4_1TX_100DCH002-: length 17.1
  TOP w0.203: v2(359.29,188.8) 358.99,188.5 350.66,188.5 350.59,188.43 SITE4.76
  vias: v1(422.17,160.85)
S4_1TX_100DCH003+: length 14.4
  TOP w0.203: SITE4.79 350.01,189.63 350.77,190.39 355.95,190.39 v2(356.24,190.09)
  vias: v1(408.07,157.67)
S4_1TX_100DCH003-: length 14.4
  TOP w0.203: v2(356.24,191.23) 355.95,190.94 350.54,190.94 349.64,190.03 SITE4.80
  vias: v1(409.21,157.67)
S4_1TX_100DCH004+: length 17.9
  TOP w0.203: SITE4.81 348.78,190.43 350.67,192.32 358.99,192.32 v2(359.29,192.02)
  vias: v1(408.07,144.08)
S4_1TX_100DCH004-: length 17.9
  TOP w0.203: v2(359.29,193.16) 358.99,192.87 350.44,192.87 348.41,190.83 SITE4.82
  vias: v1(409.21,144.08)
S4_1TX_100DCH005+: length 15.3
  TOP w0.203: SITE4.83 347.29,191.23 350.31,194.25 355.95,194.25 v2(356.24,193.95)
  vias: v1(324.25,142.43)
S4_1TX_100DCH005-: length 15.3
  TOP w0.203: v2(356.24,195.09) 355.95,194.79 350.08,194.79 346.92,191.63 SITE4.84
  vias: v1(325.39,142.43)
S4_1TX_100DCH006+: length 18.8
  TOP w0.203: v2(359.29,195.88) 358.99,196.18 349.86,196.18 345.71,192.03 SITE4.85
  vias: v1(324.25,128.84)
S4_1TX_100DCH006-: length 18.9
  TOP w0.203: SITE4.86 345.33,192.43 349.63,196.72 358.99,196.72 v2(359.29,197.02)
  vias: v1(325.39,128.84)
S4_1TX_100DCH007+: length 16.2
  TOP w0.203: SITE4.87 343.9,192.83 349.17,198.1 355.95,198.1 v2(356.24,197.81)
  vias: v1(409.34,220.41)
S4_1TX_100DCH007-: length 16.3
  TOP w0.203: SITE4.88 343.52,193.23 348.95,198.65 355.95,198.65 v2(356.24,198.95)
  vias: v1(410.48,220.41)
S4_2AUX+:
  vias: v1(300.22,132.08) v1(300.22,130.81)
S4_2AUX-:
  vias: v1(296.68,130.81) v1(297.68,132.08)
S4_2TX_100DCH001+: length 18.5
  TOP w0.203: SITE4.89 339.43,197.38 345.16,203.11 345.16,205.9 347.44,208.18 347.44,210.91 v2(347.73,211.21)
  vias: v1(409.34,206.82)
S4_2TX_100DCH001-: length 18.5
  TOP w0.203: v2(346.59,211.21) 346.89,210.91 346.89,208.41 344.61,206.13 344.61,203.34 339.03,197.76 SITE4.90
  vias: v1(410.48,206.82)
S4_2TX_100DCH002+: length 16.6
  TOP w0.203: SITE4.91 338.63,198.2 343.79,203.36 343.79,206.6 345.51,208.31 345.51,209.44 v2(345.81,209.74)
  vias: v1(421.53,157.67)
S4_2TX_100DCH002-: length 16.5
  TOP w0.203: v2(344.66,209.74) 344.96,209.44 344.96,208.54 343.24,206.83 343.24,203.59 338.23,198.57 SITE4.92
  vias: v1(422.68,157.67)
S4_2TX_100DCH003+: length 17.6
  TOP w0.203: v2(343.88,211.21) 343.58,210.91 343.58,208.46 342.31,207.19 342.31,203.61 337.83,199.13 SITE4.93
  vias: v1(421.53,144.08)
S4_2TX_100DCH003-: length 17.5
  TOP w0.203: SITE4.94 337.43,199.51 341.76,203.84 341.76,207.42 343.03,208.68 343.03,210.91 v2(342.73,211.21)
  vias: v1(422.68,144.08)
S4_2TX_100DCH004+: length 15.6
  TOP w0.203: SITE4.95 337.03,199.94 340.84,203.75 340.84,208.1 341.65,208.9 341.65,209.44 v2(341.95,209.74)
  vias: v1(394.35,157.67)
S4_2TX_100DCH004-: length 15.6
  TOP w0.203: SITE4.96 336.63,200.31 340.3,203.98 340.3,208.32 341.1,209.13 341.1,209.44 v2(340.8,209.74)
  vias: v1(395.5,157.67)
S4_2TX_100DCH005+: length 16.8
  TOP w0.203: SITE4.98 335.83,201.12 338.83,204.11 338.83,208.04 339.72,208.93 339.72,210.91 v2(340.02,211.21)
  vias: v1(394.35,144.08)
S4_2TX_100DCH005-: length 16.7
  TOP w0.203: SITE4.99 335.43,201.49 338.28,204.34 338.28,208.26 339.17,209.16 339.17,210.91 v2(338.87,211.21)
  vias: v1(395.5,144.08)
S4_2TX_100DCH006+: length 14.9
  TOP w0.203: v2(338.09,209.74) 337.79,209.44 337.79,209.22 337.52,208.95 337.52,204.29 335.03,201.79 SITE4.100
  vias: v1(426.4,182.99)
S4_2TX_100DCH006-: length 14.7
  TOP w0.203: v2(336.94,209.74) 337.1,209.59 337.1,209.3 336.97,209.18 336.97,204.51 334.63,202.17 SITE4.101
  vias: v1(426.4,181.84)
S4_2TX_100DCH007+: length 15.9
  TOP w0.203: v2(336.16,211.21) 335.86,210.91 335.86,204.07 334.23,202.44 SITE4.102
  vias: v1(412.81,182.99)
S4_2TX_100DCH007-: length 15.8
  TOP w0.203: v2(335.02,211.21) 335.31,210.91 335.31,204.3 333.83,202.81 SITE4.103
  vias: v1(412.81,181.84)
S4_3TX_100DCH002+: length 16.3
  TOP w0.203: SITE4.114 329.43,207.85 330.63,209.06 330.63,211.5 v2(330.93,211.8)
  vias: v1(403.5,129.1)
S4_3TX_100DCH002-: length 16.2
  TOP w0.203: v2(329.79,211.8) 330.08,211.5 330.08,209.29 329.03,208.23 SITE4.115
  vias: v1(404.64,129.1)
S4_3TX_100DCH003+: length 14.4
  TOP w0.203: v2(329,210.33) 328.7,210.03 328.7,208.82 328.63,208.74 SITE4.116
  vias: v1(381.15,190.94)
S4_3TX_100DCH003-: length 14.4
  TOP w0.203: SITE4.117 328.23,208.74 328.16,208.81 328.16,210.03 v2(327.86,210.33)
  vias: v1(382.29,190.94)
S4_3TX_100DCH004+: length 15.9
  TOP w0.203: SITE4.120 327.03,202.83 326.77,203.08 326.77,211.5 v2(327.07,211.8)
  vias: v1(381.15,177.36)
S4_3TX_100DCH004-: length 16
  TOP w0.203: SITE4.121 326.63,202.45 326.23,202.85 326.23,211.5 v2(325.93,211.8)
  vias: v1(382.29,177.36)
S4_3TX_100DCH005+: length 14.9
  TOP w0.203: SITE4.122 326.23,201.79 324.85,203.17 324.85,210.03 v2(325.14,210.33)
  vias: v1(394.35,174.43)
S4_3TX_100DCH005-: length 15
  TOP w0.203: SITE4.123 325.83,201.41 324.3,202.94 324.3,210.03 v2(324,210.33)
  vias: v1(395.5,174.43)
S4_3TX_100DCH006+: length 16.8
  TOP w0.203: SITE4.124 325.43,200.78 322.92,203.29 322.92,211.5 v2(323.21,211.8)
  vias: v1(394.35,160.85)
S4_3TX_100DCH006-: length 16.9
  TOP w0.203: SITE4.125 325.03,200.4 322.37,203.06 322.37,211.5 v2(322.07,211.8)
  vias: v1(395.5,160.85)
S4_3TX_100DCH007+: length 15.8
  TOP w0.203: SITE4.126 324.63,199.62 320.99,203.27 320.99,210.03 v2(321.28,210.33)
  vias: v1(416.71,142.68)
S4_3TX_100DCH007-: length 15.9
  TOP w0.203: SITE4.127 324.23,199.25 320.44,203.04 320.44,210.03 v2(320.14,210.33)
  vias: v1(417.85,142.68)
S4_4TX_100DCH001+: length 17.6
  TOP w0.203: SITE4.129 323.43,198.97 319.06,203.35 319.06,211.5 v2(319.35,211.8)
  vias: v1(416.71,129.1)
S4_4TX_100DCH001-: length 17.7
  TOP w0.203: SITE4.130 323.03,198.6 318.51,203.12 318.51,211.5 v2(318.21,211.8)
  vias: v1(417.85,129.1)
S4_4TX_100DCH002+: length 16.6
  TOP w0.203: SITE4.131 322.63,197.73 317.13,203.23 317.13,210.03 v2(317.43,210.33)
  vias: v1(390.29,142.68)
S4_4TX_100DCH002-: length 16.7
  TOP w0.203: v2(316.28,210.33) 316.58,210.03 316.58,203 322.23,197.35 SITE4.132
  vias: v1(391.43,142.68)
S4_4TX_100DCH003+: length 16.8
  TOP w0.203: SITE4.133 318.12,193.23 312.41,198.94 305.29,198.94 v2(304.99,199.24)
  vias: v1(390.29,129.1)
S4_4TX_100DCH003-: length 16.8
  TOP w0.203: SITE4.134 317.75,192.83 312.18,198.4 305.29,198.4 v2(304.99,198.1)
  vias: v1(391.43,129.1)
S4_4TX_100DCH004+: length 13.1
  TOP w0.203: v2(308.29,197.31) 308.58,197.02 312.43,197.02 317.02,192.43 SITE4.135
  vias: v1(407.82,174.43)
S4_4TX_100DCH004-: length 13
  TOP w0.203: v2(308.29,196.17) 308.58,196.47 312.2,196.47 316.64,192.03 SITE4.136
  vias: v1(408.96,174.43)
S4_4TX_100DCH005+: length 15.9
  TOP w0.203: v2(304.99,195.38) 305.29,195.09 312.49,195.09 315.95,191.63 SITE4.137
  vias: v1(407.82,160.85)
S4_4TX_100DCH005-: length 15.8
  TOP w0.203: v2(304.99,194.24) 305.29,194.54 312.27,194.54 315.57,191.23 SITE4.138
  vias: v1(408.96,160.85)
S4_4TX_100DCH006+: length 12.1
  TOP w0.203: SITE4.140 314.18,190.43 311.83,192.78 308.58,192.78 v2(308.29,193.07)
  vias: v1(310.53,155.13)
S4_4TX_100DCH006-: length 12.1
  TOP w0.203: v2(308.29,191.93) 308.58,192.23 311.6,192.23 313.8,190.03 SITE4.141
  vias: v1(311.68,155.13)
S4_4TX_100DCH007+: length 15
  TOP w0.203: v2(304.99,191.14) 305.29,190.85 311.82,190.85 313.03,189.63 SITE4.142
  vias: v1(310.53,141.54)
S4_4TX_100DCH007-: length 14.9
  TOP w0.203: SITE4.143 312.66,189.23 311.59,190.3 305.29,190.3 v2(304.99,190)
  vias: v1(311.68,141.54)
S4_AUX_100DCH002+:
  vias: v1(299.22,132.08)
S4_AUX_100DCH002-:
  vias: v1(296.68,132.08)
S4_AUXCH+: length 32.3
  TOP w0.203: SITE4.21 330.23,176.2 v2(330.6,176.57)
  BOTTOM w0.203: 327.57,149.14 327.57,171.79 330.3,174.52 330.3,176.28 v2(330.6,176.57)
S4_AUXCH-: length 32.1
  TOP w0.203: SITE4.20 329.83,176.2 v2(329.46,176.57)
  BOTTOM w0.203: v2(329.46,176.57) 329.76,176.28 329.76,174.75 327.02,172.02 327.02,149.37
S4_AVDD11_RX: length 8.4
  TOP w0.231: SITE4.31 334.23,168.29 334.67,167.85
  TOP w0.508: v1(336.77,165.75) 334.67,167.85
  vias: v1(336.77,163.71)
S4_AVDD11_XTAL: length 8.8
  TOP w0.231: SITE4.105 333.03,200.95 332.87,201.11 332.87,201.45
  TOP w0.381: v1(333.72,204.54) 333.72,204.45 332.87,203.59 332.87,201.45
  vias: v1(333.72,206.58)
S4_AVDD18_RX: length 7.7
  TOP w0.231: SITE4.25 331.83,170.56 331.28,170.01
  TOP w0.508: 331.28,170.01 331.28,168.9 331.06,168.68 v1(331.06,165.75)
  vias: v1(331.06,163.71)
S4_DCH041: length 2.2
  TOP w0.231: SITE4.159 317.43,182.83 v1(317.23,183.03)
S4_DCH042: length 3.7
  TOP w0.231: SITE4.160 316.43,182.43 v1(315.83,183.03)
S4_DCH043: length 5.3
  TOP w0.231: SITE4.161 315.44,182.03 v1(314.43,183.03)
S4_DCH044: length 2.2
  TOP w0.231: SITE4.163 317.43,181.23 v1(317.23,181.03)
S4_DCH045: length 5.4
  TOP w0.231: v1(324.35,179.83) 323.35,180.83 SITE4.164
S4_DCH046: length 3.9
  TOP w0.231: SITE4.165 322.35,180.43 v1(322.95,179.83)
S4_DCH047: length 2.3
  TOP w0.231: v1(321.56,179.83) 321.36,180.03 SITE4.166
S4_DPS_F_001:
  vias: v1(297.68,130.81)
S4_DPS_F_002: length 10.1
  TOP w0.231: SITE4.3 323.03,170.86 321.72,169.55 320.65,169.55
  TOP w0.508: v1(317.98,165.75) 317.98,166.88 320.65,169.55
  vias: v1(316.32,162.9) v1(317.98,163.71)
S4_DPS_F_003: length 63.1
  TOP w0.231: 331.69,201.16 331.69,200.65 332.23,200.11 SITE4.107 ; 329.28,168.85 328.63,169.5 SITE4.17 ; 339.73,169.66 338.57,169.66 336.63,171.59 SITE4.37 ; SITE4.71 346.94,186.43 347.84,185.53 ; 345.2,182.93 344.9,183.23 SITE4.63 ; 312.83,188.18 313.08,188.43 SITE4.145 ; 314.63,181.63 SITE4.162
  TOP w0.381: 331.69,201.16 331.69,204.28 v1(331.94,204.54)
  TOP w0.508: v1(329.28,165.75) 329.28,168.85 ; 345.2,182.93 345.45,182.68 346.8,182.68 348.11,181.37 v1(351.22,181.37) ; 347.84,185.53 349.45,183.91 v1(351.22,183.91) ; v1(311.44,183.41) 312.59,183.41 314.37,181.63 314.63,181.63 ; v1(342.36,165.75) 342.36,167.02 339.73,169.66 ; v1(311.44,187.93) 312.58,187.93 312.83,188.18
  vias: v1(309.4,187.93) v1(309.4,183.41) v1(329.28,163.71) v1(331.94,206.58) v1(342.36,163.71) v1(353.27,183.91) v1(353.27,181.37) v1(464.57,192.28)
S4_DPS_F_006: length 9.6
  TOP w0.231: 348.55,186.19 347.92,186.83 SITE4.72
  TOP w0.508: 348.55,186.19 349.56,185.18 v1(351.22,185.18)
  vias: v1(339,186.67) v1(353.27,185.18)
S4_DPS_F_007: length 19
  TOP w0.231: SITE4.97 336.23,200.71 339.65,204.13 v1(339.65,204.54) ; SITE4.78 344.15,189.23 344.37,189.01
  TOP w0.508: 344.37,189.01 350.31,189.01 350.8,189.5 v1(351.22,189.5)
  vias: v1(339.65,206.58) v1(353.27,189.5)
S4_DPS_F_009: length 8.8
  TOP w0.231: 332.26,201.12 332.26,200.9 332.63,200.53 SITE4.106
  TOP w0.381: 332.26,201.12 332.26,203.82 332.83,204.39 v1(332.83,204.54)
  vias: v1(332.83,206.58) v1(333.61,207.66)
S4_DPS_F_010: length 8.6
  TOP w0.231: SITE4.111 330.63,200.15 331.05,200.57 331.05,201.13
  TOP w0.381: 331.05,201.13 v1(331.05,204.54)
  vias: v1(330.63,193.59) v1(331.05,206.58)
S4_DPS_F_011: length 17.6
  TOP w0.231: SITE4.139 314.87,190.83 312.01,193.69 v1(311.44,193.69) ; 327.64,198.01 327.43,197.79 SITE4.119
  TOP w0.508: 327.64,198.01 327.64,204.47 v1(327.57,204.54)
  vias: v1(309.4,193.69) v1(327.57,206.58)
S4_DPS_F_012: length 8
  TOP w0.231: 312.2,188.83 SITE4.144
  TOP w0.508: 312.2,188.83 311.81,188.83 v1(311.44,189.2)
  vias: v1(309.4,189.2)
S4_DPS_F_013:
  vias: v1(452.62,188.98) v1(452.62,181.36) v1(457.25,190.45) v1(474.87,173.79) v1(474.89,161.55) v1(474.99,175.15) v1(475.99,187.35) v1(478.43,173.74) v1(478.43,161.55) v1(478.53,187.35) v1(478.53,175.15) v1(480.97,161.55) v1(481.07,175.15) v1(482.1,197.87) v1(482.1,190.25) v1(483.51,161.55) v1(483.61,175.15) v1(489.86,169.47) v1(490.1,183.24)
S4_ISP00+: length 14.5
  TOP w0.203: v2(356.24,185.73) 355.95,186.03 350.09,186.03 348.89,187.23 SITE4.73
  vias: v1(307.81,131.64)
S4_ISP00-: length 14.5
  TOP w0.203: SITE4.74 349.26,187.63 350.32,186.58 355.95,186.58 v2(356.24,186.87)
  vias: v1(307.81,139.64)
S4_ISP14+: length 15.3
  TOP w0.203: v2(332.86,210.33) 332.56,210.03 332.56,209.22 330.23,206.89 SITE4.112
  vias: v1(312.21,131.64)
S4_ISP14-: length 15.2
  TOP w0.203: SITE4.113 329.83,207.26 332.01,209.45 332.01,210.03 v2(331.72,210.33)
  vias: v1(312.21,139.64)
S4_M_DPS_F_001: length 45.2
  TOP w0.231: 330.63,170.54 SITE4.22 ; SITE4.147 313.7,187.63 313.24,187.18 ; 346.49,183.63 SITE4.64 ; SITE4.39 337.43,171.49 338.54,170.37 340.57,170.37 ; SITE4.104 333.43,203.21
  TOP w0.381: v1(334.61,204.54) 334.61,204.39 333.43,203.21
  TOP w0.508: v1(351.22,182.64) 348.48,182.64 347.49,183.63 346.49,183.63 ; v1(343.63,165.75) 343.63,167.31 340.57,170.37 ; 330.63,170.54 330.38,170.28 330.38,169.17 330.17,168.96 v1(330.17,165.75) ; 313.24,187.18 312.72,186.66 v1(311.44,186.66)
  vias: v1(309.4,186.66) v1(330.17,163.71) v1(334.61,206.58) v1(343.63,163.71) v1(353.27,182.64)
S4_PS9G_DCH001: length 3.7
  TOP w0.231: SITE4.18 329.03,170.23 v1(329.63,169.63)
S4_PS9G_DCH002: length 2.2
  TOP w0.231: v1(329.63,171.03) 329.43,171.23 SITE4.19
S4_PS9G_DCH003: length 2.2
  TOP w0.231: v1(331.23,171.03) 331.43,171.23 SITE4.24
S4_PS9G_DCH004: length 2.2
  TOP w0.231: SITE4.40 337.83,175.03 v1(337.63,175.23)
S4_PS9G_DCH005: length 2.2
  TOP w0.231: SITE4.45 344.23,176.03 v1(344.43,175.83)
S4_PS9G_DCH006: length 3.7
  TOP w0.231: SITE4.46 345.23,176.43 v1(345.83,175.83)
S4_PS9G_DCH007: length 5.3
  TOP w0.231: SITE4.47 346.22,176.83 v1(347.22,175.83)
S4_PS9G_DCH009: length 2.2
  TOP w0.231: SITE4.49 344.23,177.63 v1(344.43,177.43)
S4_PS9G_DCH010: length 3.7
  TOP w0.231: SITE4.50 345.23,178.03 v1(345.83,177.43)
S4_PS9G_DCH011: length 5.3
  TOP w0.231: SITE4.51 346.22,178.43 v1(347.22,177.43)
S4_PS9G_DCH014: length 3.7
  TOP w0.231: v1(345.83,179.03) 345.23,179.63 SITE4.54
S4_PS9G_DCH015: length 5.3
  TOP w0.231: SITE4.55 346.22,180.03 v1(347.22,179.03)
S4_PS9G_DCH022: length 5.3
  TOP w0.231: v1(347.22,185.03) 347.05,185.03 346.05,184.03 SITE4.65
S4_PS9G_DCH023: length 2.5
  TOP w0.231: v1(344.43,185.03) 344.43,184.83 344.03,184.43 SITE4.66
S4_PS9G_DCH027: length 3.9
  TOP w0.231: v1(345.83,185.03) 344.83,186.03 SITE4.70
S4_PS9G_DCH028: length 2.3
  TOP w0.231: SITE4.77 340.6,188.83 v1(340.23,188.46)
S4_PS9G_DCH029: length 2.2
  TOP w0.231: SITE4.118 327.83,194.23 v1(328.03,194.03)
S4_PS9G_DCH030: length 9.2
  TOP w0.231: v1(310.91,185.39) 312.63,185.39 314.16,186.91 317.3,186.91 317.62,187.23 SITE4.148
S4_PS9G_DCH035: length 5.3
  TOP w0.231: v1(314.43,186.23) 315.44,185.23 SITE4.153
S4_PS9G_DCH036: length 2.2
  TOP w0.231: SITE4.154 321.23,184.83 v1(321.43,185.03)
S4_PS9G_DCH037: length 2.2
  TOP w0.231: v1(317.23,184.63) 317.43,184.43 SITE4.155
S4_PS9G_DCH038: length 3.7
  TOP w0.231: SITE4.156 316.43,184.03 v1(315.83,184.63)
S4_PS9G_DCH039: length 5.3
  TOP w0.231: v1(314.43,184.63) 315.44,183.63 SITE4.157
S4_PS9G_DCH040: length 2.2
  TOP w0.231: v1(321.43,183.43) 321.23,183.23 SITE4.158
S4_RLY_001:
  vias: v1(402.14,146.88) v1(415.1,163.64)
S4_RLY_003:
  vias: v1(318.32,131.64) v1(403.41,209.61)
S4_RLY_005:
  vias: v1(388.43,146.88) v1(415.6,146.88)
S4_RLY_007:
  vias: v1(415.61,188.92)
S4_RLY_008:
  vias: v1(375.22,180.15) v1(397.57,131.89)
S4_RLY_016:
  vias: v1(388.43,163.64) v1(410.78,131.89)
S4_RLY_021:
  vias: v1(384.36,131.89) v1(401.89,163.64)
S4_RLY_022:
  vias: v1(346.27,138.37) v1(375.73,202.38)
S4_RLY_023:
  vias: v1(392.24,202.38)
S4_RLY_025:
  vias: v1(375.22,163.39) v1(388.43,180.15)
S4_RLY_026:
  vias: v1(401.89,180.15)
S4_RLY_030:
  vias: v1(304.61,144.34)
S4_RLY_043:
  vias: v1(304.61,131.64)
S4_SCAN_DCH008: length 2.2
  TOP w0.231: SITE4.48 340.43,177.23 v1(340.23,177.03)
S4_SCAN_DCH012: length 2.2
  TOP w0.231: v1(340.23,178.63) 340.43,178.83 SITE4.52
S4_SCAN_DCH013: length 2.2
  TOP w0.231: SITE4.53 344.23,179.23 v1(344.43,179.03)
S4_SCAN_DCH016: length 2.2
  TOP w0.231: SITE4.56 340.43,180.43 v1(340.23,180.23)
S4_SCAN_DCH017: length 2.2
  TOP w0.231: v1(344.43,180.63) 344.23,180.83 SITE4.57
S4_SCAN_DCH018: length 3.7
  TOP w0.231: SITE4.58 345.23,181.23 v1(345.83,180.63)
S4_SCAN_DCH019: length 5.3
  TOP w0.231: v1(347.22,180.63) 346.22,181.63 SITE4.59
S4_SCAN_DCH020: length 2.2
  TOP w0.231: SITE4.60 340.43,182.03 v1(340.23,181.83)
S4_SCAN_DCH021: length 2.2
  TOP w0.231: v1(344.43,182.23) 344.23,182.43 SITE4.61
S4_SCAN_DCH024: length 2.2
  TOP w0.231: v1(340.23,184.63) 340.43,184.83 SITE4.67
S4_SCAN_DCH025: length 3.7
  TOP w0.231: SITE4.68 339.43,185.23 v1(338.83,184.63)
S4_SCAN_DCH026: length 5.3
  TOP w0.231: v1(337.44,184.63) 338.44,185.63 SITE4.69
S4_SCAN_DCH031: length 3.7
  TOP w0.231: SITE4.149 322.23,186.83 v1(322.83,187.43)
S4_SCAN_DCH032: length 5.3
  TOP w0.231: SITE4.150 323.22,186.43 v1(324.22,187.43)
S4_SCAN_DCH033: length 2.2
  TOP w0.231: v1(317.23,186.23) 317.43,186.03 SITE4.151
S4_SCAN_DCH034: length 3.7
  TOP w0.231: v1(315.83,186.23) 316.43,185.63 SITE4.152
S4_SPI_1_CSN:
  vias: v1(474.99,187.35)
S4_SPI_1_SCK:
  vias: v1(480.07,175.15)
S4_SPI_1_SDI:
  vias: v1(456.19,173.74)
S4_SPI_1_SDO:
  vias: v1(455.94,166.12)
S4_SPI_2_CSN:
  vias: v1(475.87,173.79)
S4_SPI_2_SCK:
  vias: v1(479.97,161.55)
S4_SPI_2_SDI:
  vias: v1(451.62,173.74)
S4_SPI_2_SDO:
  vias: v1(451.87,166.12)
S4_SPI_11_SDI:
  vias: v1(457.19,173.74) v1(477.53,187.35)
S4_SPI_11_SDO:
  vias: v1(456.94,166.12) v1(482.61,175.15)
S4_SPI_22_SDI:
  vias: v1(452.62,173.74) v1(477.43,173.74)
S4_SPI_22_SDO:
  vias: v1(452.87,166.12) v1(482.51,161.55)
S4_SPI_CSN: length 25.9
  TOP w0.231: v1(339.23,171.03) 339.03,171.23 SITE4.43
  BOTTOM w0.231: v1(339.23,171.03) 338.4,171.03 335.17,174.25 333.57,174.25 332.91,173.59 332.91,161.11 332.25,160.44 330.61,160.44 330.11,159.95
S4_SPI_SCK: length 25.3
  TOP w0.231: SITE4.42 338.63,175.03 v1(338.83,175.23)
  BOTTOM w0.231: 335.03,158.48 335.03,168.39 335.92,169.27 337.17,169.27 337.9,168.54 339.96,168.54 340.53,169.11 340.53,172.28 338.83,173.98 v1(338.83,175.23)
S4_SPI_SDI: length 3.7
  TOP w0.231: v1(338.83,176.63) 339.43,176.03 SITE4.44
S4_SPI_SDO: length 37
  TOP w0.231: v1(337.63,176.63) 338.23,176.03 SITE4.41
  BOTTOM w0.231: v1(337.63,176.63) 338.83,177.83 341.5,177.83 342.29,177.04 342.29,175.83 344.72,173.4 344.72,150.32
S4_XTAL_IN: length 28.3
  TOP w0.231: SITE4.109 331.43,198.03 v1(331.63,198.23)
  BOTTOM w0.231: v1(331.63,198.23) 327.82,198.23 318.94,207.1 318.94,211.27 314.98,215.24
S4_XTAL_OUT: length 26.8
  TOP w0.231: SITE4.110 331.03,199.03 v1(331.63,199.63)
  BOTTOM w0.231: 318.8,216.35 320.8,214.36 320.8,212.93 322.59,211.15 322.59,206.87 329.83,199.63 v1(331.63,199.63)
UDBGND:
  vias: v1(117.69,130.81) v1(118.49,128.27) v1(128.57,149.86) v1(128.57,146.05) v1(128.57,138.43) v1(128.57,134.62) v1(130.51,142.24) v1(224.37,298.45) v1(225.17,295.91) v1(452.68,137.92) v1(452.68,134.11) v1(452.68,130.3) v1(454.61,145.54) v1(454.61,141.73) v1(473.29,130.81) v1(474.09,128.27) v1(484.87,130.71) v1(485.12,128.27) v1(512.11,238.76) v1(512.11,234.95) v1(512.11,231.14) v1(512.11,227.33) v1(548.37,300.89) v1(548.62,298.45) v1(557.36,300.99) v1(558.16,298.45)
UT1_UP5V:
  vias: v1(115.19,128.27) v1(115.99,130.81) v1(175.7,264.1) v1(175.7,250.38) v1(175.7,236.67) v1(175.7,222.95) v1(175.7,209.49) v1(175.7,195.52) v1(175.7,182.06) v1(175.7,168.6) v1(175.7,154.88) v1(175.7,141.67) v1(192.47,264.1) v1(192.47,250.38) v1(192.47,236.67) v1(192.47,222.95) v1(192.47,209.49) v1(192.47,195.52) v1(192.47,182.06) v1(192.47,168.6) v1(192.47,154.88) v1(208.98,264.1) v1(209.23,250.38) v1(209.23,236.67) v1(209.23,222.95) v1(209.23,209.49) v1(209.23,195.52) v1(209.49,182.06) v1(209.49,168.6) v1(209.49,155.13) v1(221.87,295.91) v1(222.67,298.45) v1(232.25,271.67) v1(244.8,288.61) v1(250.5,296.86) v1(256.73,132.14) v1(263.71,296.86) v1(269.94,135.19) v1(273.24,272.1) v1(277.17,296.86) v1(282.9,147.38) v1(290.64,296.86) v1(293.31,272.1) v1(303.84,296.86) v1(304.61,152.34) v1(304.61,139.64) v1(312.25,271.67) v1(317.05,296.86) v1(318.32,139.64) v1(330.51,296.86) v1(343.98,296.86) v1(354.27,138.37) v1(369.38,265.11) v1(369.38,249.11) v1(369.38,232.6) v1(369.63,297.12) v1(369.63,281.11) v1(375.22,188.15) v1(375.22,171.39) v1(376.23,217.11) v1(383.09,297.12) v1(383.09,281.11) v1(383.09,265.11) v1(383.09,249.11) v1(383.09,232.85) v1(383.73,202.38) v1(384.36,139.89) v1(388.43,188.15) v1(388.43,171.64) v1(388.43,154.88) v1(389.7,217.36) v1(396.55,297.12) v1(396.55,281.11) v1(396.55,265.37) v1(396.55,249.11) v1(396.55,233.11) v1(397.57,139.89) v1(400.24,202.38) v1(401.89,188.15) v1(401.89,171.64) v1(402.14,154.88) v1(403.41,217.61) v1(410.27,265.37) v1(410.52,297.12) v1(410.52,281.37) v1(410.52,249.11) v1(410.78,139.89) v1(415.1,171.64) v1(415.6,154.88) v1(423.61,188.92) v1(470.79,128.27) v1(471.59,130.81) v1(482.62,128.27) v1(483.17,130.71) v1(546.12,298.45) v1(546.67,300.89) v1(554.86,298.45) v1(555.66,300.99)
N26125600: length 3
  BOTTOM w0.119: K25.3 210.81,258.7 211.29,259.17 R55.2
N26125602: length 3
  BOTTOM w0.119: K25.4 210.81,256.5 211.29,256.03 R56.1
N26125604: length 3
  BOTTOM w0.119: K25.6 199.14,258.7 198.67,259.17 R57.2
N26125606: length 3
  BOTTOM w0.119: K25.5 199.14,256.5 198.67,256.03 R58.1
N26125622: length 3
  BOTTOM w0.119: R59.2 194.78,245.46 194.3,244.98 K26.3
N26125624: length 3
  BOTTOM w0.119: K26.4 194.3,242.78 194.78,242.31 R60.1
N26125626: length 3
  BOTTOM w0.119: R61.2 182.16,245.46 182.63,244.98 K26.6
N26125628: length 3
  BOTTOM w0.119: K26.5 182.63,242.78 182.16,242.31 R62.1
N26125644: length 3
  BOTTOM w0.119: K27.5 165.87,242.78 165.4,242.31 R66.1
N26125646: length 3
  BOTTOM w0.119: R65.2 165.4,245.46 165.87,244.98 K27.6
N26125685: length 3
  BOTTOM w0.119: R45.2 198.92,245.46 199.4,244.98 K22.6
N26125687: length 3
  BOTTOM w0.119: R46.1 198.92,242.31 199.4,242.78 K22.5
N26125689: length 3
  BOTTOM w0.119: R47.2 194.78,231.74 194.3,231.27 K23.3
N26125691: length 3
  BOTTOM w0.119: R48.1 194.78,228.6 194.3,229.07 K23.4
N26125693: length 3
  BOTTOM w0.119: K23.6 182.63,231.27 182.16,231.74 R49.2
N26125695: length 3
  BOTTOM w0.119: K23.5 182.63,229.07 182.16,228.6 R50.1
N26125711: length 3
  BOTTOM w0.119: K24.3 177.54,231.27 178.01,231.74 R51.2
N26125713: length 3
  BOTTOM w0.119: K24.4 177.54,229.07 178.01,228.6 R52.1
N26125715: length 3
  BOTTOM w0.119: R53.2 165.4,231.74 165.87,231.27 K24.6
N26125717: length 3
  BOTTOM w0.119: K24.5 165.87,229.07 165.4,228.6 R54.1
N26125746: length 3
  BOTTOM w0.119: K22.3 211.07,244.98 211.54,245.46 R102.2
N26125748: length 3
  BOTTOM w0.119: R103.1 211.54,242.31 211.07,242.78 K22.4
N26125750: length 3
  BOTTOM w0.119: K27.3 177.54,244.98 178.01,245.46 R104.2
N26125752: length 3
  BOTTOM w0.119: K27.4 177.54,242.78 178.01,242.31 R105.1
N26323523: length 3
  BOTTOM w0.119: K17.3 255.9,298.7 255.43,299.17 R71.2
N26323525: length 3
  BOTTOM w0.119: K17.4 258.1,298.7 258.58,299.17 R72.1
N26323527: length 3
  BOTTOM w0.119: R74.1 258.58,286.55 258.1,287.03 K17.5
N26323529: length 3
  BOTTOM w0.119: K17.6 255.9,287.03 255.43,286.55 R73.2
N26323531: length 3
  BOTTOM w0.119: R75.2 282.1,299.17 282.57,298.7 K21.3
N26323533: length 3
  BOTTOM w0.119: K21.4 284.77,298.7 285.25,299.17 R76.1
N26323535: length 3
  BOTTOM w0.119: K21.5 284.77,287.03 285.25,286.55 R78.1
N26323537: length 3
  BOTTOM w0.119: R77.2 282.1,286.55 282.57,287.03 K21.6
N26323539: length 3
  BOTTOM w0.119: K29.3 177.54,258.7 178.01,259.17 R79.2
N26323541: length 3
  BOTTOM w0.119: K29.4 177.54,256.5 178.01,256.03 R80.1
N26323543: length 3
  BOTTOM w0.119: R43.2 165.4,259.17 165.87,258.7 K29.6
N26323545: length 3
  BOTTOM w0.119: K29.5 165.87,256.5 165.4,256.03 R44.1
N26323547: length 3
  BOTTOM w0.119: R63.2 194.78,259.17 194.3,258.7 K30.3
N26323549: length 3
  BOTTOM w0.119: R64.1 194.78,256.03 194.3,256.5 K30.4
N26323551: length 3
  BOTTOM w0.119: K30.5 182.63,256.5 182.16,256.03 R101.1
N26323553: length 3
  BOTTOM w0.119: R100.2 182.16,259.17 182.63,258.7 K30.6
N26325241: length 3
  BOTTOM w0.119: K16.3 239.4,286.77 239.87,286.3 R67.2
N26325243: length 3
  BOTTOM w0.119: K16.4 237.2,286.77 236.72,286.3 R68.1
N26325245: length 3
  BOTTOM w0.119: K16.5 237.2,298.44 236.72,298.92 R70.1
N26325247: length 3
  BOTTOM w0.119: K16.6 239.4,298.44 239.87,298.92 R69.2
N26326910: length 3
  BOTTOM w0.119: R30.1 338.59,286.55 338.11,287.03 K6.5
N26326941: length 3
  BOTTOM w0.119: R27.2 335.44,299.17 335.91,298.7 K6.3
N26326943: length 3
  BOTTOM w0.119: R28.1 338.59,299.17 338.11,298.7 K6.4
N26326945: length 3
  BOTTOM w0.119: R29.2 335.44,286.55 335.91,287.03 K6.6
N26326947: length 3
  BOTTOM w0.119: K7.5 324.65,287.03 325.12,286.55 R34.1
N26326959: length 3
  BOTTOM w0.119: K7.3 322.45,298.7 321.98,299.17 R31.2
N26326961: length 3
  BOTTOM w0.119: K7.4 324.65,298.7 325.12,299.17 R32.1
N26326963: length 3
  BOTTOM w0.119: K7.6 322.45,287.03 321.98,286.55 R33.2
N26327095: length 3
  BOTTOM w0.119: K11.3 287.91,270.26 288.38,269.79 R39.2
N26327097: length 3
  BOTTOM w0.119: K11.4 285.71,270.26 285.24,269.79 R40.1
N26327099: length 3
  BOTTOM w0.119: K8.5 271.31,287.03 271.78,286.55 R38.1
N26327103: length 3
  BOTTOM w0.119: K8.6 269.11,287.03 268.64,286.55 R37.2
N26327105: length 3
  BOTTOM w0.119: R41.2 288.38,282.41 287.91,281.93 K11.6
N26327107: length 3
  BOTTOM w0.119: K11.5 285.71,281.93 285.24,282.41 R42.1
N26328546: length 3
  BOTTOM w0.119: K5.5 351.58,287.03 352.05,286.55 R26.1
N26328550: length 3
  BOTTOM w0.119: R23.2 348.9,299.17 349.38,298.7 K5.3
N26328552: length 3
  BOTTOM w0.119: K5.4 351.58,298.7 352.05,299.17 R24.1
N26328554: length 3
  BOTTOM w0.119: R25.2 348.9,286.55 349.38,287.03 K5.6
N26330264: length 3
  BOTTOM w0.119: R18.1 298.71,286.55 298.24,287.03 K3.5
N26330266: length 3
  BOTTOM w0.119: K3.6 296.04,287.03 295.56,286.55 R17.2
N26330268: length 3
  BOTTOM w0.119: R16.1 298.71,299.17 298.24,298.7 K3.4
N26330270: length 3
  BOTTOM w0.119: K3.3 296.04,298.7 295.56,299.17 R15.2
N26330276: length 3
  BOTTOM w0.119: K1.5 165.87,215.35 165.4,214.88 R10.1
N26330278: length 3
  BOTTOM w0.119: R9.2 165.4,218.02 165.87,217.55 K1.6
N26330280: length 3
  BOTTOM w0.119: R8.1 178.01,214.88 177.54,215.35 K1.4
N26330282: length 3
  BOTTOM w0.119: K1.3 177.54,217.55 178.01,218.02 R7.2
N26330286: length 3
  BOTTOM w0.119: K2.3 211.07,231.27 211.54,231.74 R11.2
N26330288: length 3
  BOTTOM w0.119: K2.4 211.07,229.07 211.54,228.6 R12.1
N26330290: length 3
  BOTTOM w0.119: K4.5 311.44,287.03 311.92,286.55 R22.1
N26330294: length 3
  BOTTOM w0.119: K4.3 309.24,298.7 308.77,299.17 R19.2
N26330296: length 3
  BOTTOM w0.119: K4.4 311.44,298.7 311.92,299.17 R20.1
N26330298: length 3
  BOTTOM w0.119: R21.2 308.77,286.55 309.24,287.03 K4.6
N26330300: length 3
  BOTTOM w0.119: R14.1 198.92,228.6 199.4,229.07 K2.5
N26330302: length 3
  BOTTOM w0.119: R13.2 198.92,231.74 199.4,231.27 K2.6
N26336828:
  vias: v1(222.38,273.82) v1(222.38,272.66) v1(224.65,271.67)
N26336832:
  vias: v1(222.38,275.98) v1(222.38,274.82) v1(224.65,276.97)
N26336834:
  vias: v1(221.21,276.98) v1(222.38,276.98)
N26336836:
  vias: v1(221.21,271.66) v1(222.38,271.66)
N26486525: length 3
  BOTTOM w0.119: UNK2K25.3 401.95,234.94 401.48,235.42 UNK2R55.2
N26486526: length 3
  BOTTOM w0.119: UNK2K25.4 404.15,234.94 404.63,235.42 UNK2R56.1
N26486527: length 3
  BOTTOM w0.119: UNK2R57.2 401.48,222.8 401.95,223.27 UNK2K25.6
N26486528: length 3
  BOTTOM w0.119: UNK2R58.1 404.63,222.8 404.15,223.27 UNK2K25.5
N26486530: length 3
  BOTTOM w0.119: UNK2K26.3 395.1,219.2 394.62,219.67 UNK2R59.2
N26486531: length 3
  BOTTOM w0.119: UNK2K26.4 397.3,219.2 397.77,219.67 UNK2R60.1
N26486532: length 3
  BOTTOM w0.119: UNK2R61.2 394.62,207.05 395.1,207.52 UNK2K26.6
N26486533: length 3
  BOTTOM w0.119: UNK2K26.5 397.3,207.52 397.77,207.05 UNK2R62.1
N26486535: length 3
  BOTTOM w0.119: UNK2R66.1 384.31,206.8 383.83,207.27 UNK2K27.5
N26486536: length 3
  BOTTOM w0.119: UNK2K27.6 381.63,207.27 381.16,206.8 UNK2R65.2
N26486543: length 3
  BOTTOM w0.119: UNK2K22.6 374.78,222.76 374.3,222.29 UNK2R45.2
N26486544: length 3
  BOTTOM w0.119: UNK2R46.1 377.45,222.29 376.98,222.76 UNK2K22.5
N26486545: length 3
  BOTTOM w0.119: UNK2R47.2 388.02,235.16 388.49,234.69 UNK2K23.3
N26486546: length 3
  BOTTOM w0.119: UNK2K23.4 390.69,234.69 391.16,235.16 UNK2R48.1
N26486547: length 3
  BOTTOM w0.119: UNK2K23.6 388.49,223.02 388.02,222.55 UNK2R49.2
N26486548: length 3
  BOTTOM w0.119: UNK2K23.5 390.69,223.02 391.16,222.55 UNK2R50.1
N26486550: length 3
  BOTTOM w0.119: UNK2K24.3 388.49,250.95 388.02,251.42 UNK2R51.2
N26486551: length 3
  BOTTOM w0.119: UNK2K24.4 390.69,250.95 391.16,251.42 UNK2R52.1
N26486552: length 3
  BOTTOM w0.119: UNK2K24.6 388.49,239.27 388.02,238.8 UNK2R53.2
N26486553: length 3
  BOTTOM w0.119: UNK2K24.5 390.69,239.27 391.16,238.8 UNK2R54.1
N26486568: length 3
  BOTTOM w0.119: UNK2K22.3 374.78,234.44 374.3,234.91 UNK2R102.2
N26486569: length 3
  BOTTOM w0.119: UNK2K22.4 376.98,234.44 377.45,234.91 UNK2R103.1
N26486570: length 3
  BOTTOM w0.119: UNK2K27.3 381.63,218.94 381.16,219.41 UNK2R104.2
N26486571: length 3
  BOTTOM w0.119: UNK2K27.4 383.83,218.94 384.31,219.41 UNK2R105.1
N26486686:
  vias: v1(465.57,235.71)
N26486691:
  vias: v1(468.62,235.71)
N26486726:
  vias: v1(374.56,299.91) v1(375.03,297.12)
N26486727:
  vias: v1(377.23,297.12) v1(377.7,299.91)
N26486728:
  vias: v1(377.23,289.12) v1(377.7,286.32)
N26486729:
  vias: v1(374.56,286.32) v1(375.03,289.12)
N26486730:
  vias: v1(401.48,299.91) v1(401.95,297.12)
N26486731:
  vias: v1(404.15,297.12) v1(404.63,299.91)
N26486732:
  vias: v1(404.15,289.12) v1(404.63,286.32)
N26486733:
  vias: v1(401.48,286.32) v1(401.95,289.12)
N26486734: length 3
  BOTTOM w0.119: UNK2R79.2 374.3,251.42 374.78,250.95 UNK2K29.3
N26486735: length 3
  BOTTOM w0.119: UNK2K29.4 376.98,250.95 377.45,251.42 UNK2R80.1
N26486736: length 3
  BOTTOM w0.119: UNK2K29.6 374.78,239.27 374.3,238.8 UNK2R43.2
N26486737: length 3
  BOTTOM w0.119: UNK2K29.5 376.98,239.27 377.45,238.8 UNK2R44.1
N26486738: length 3
  BOTTOM w0.119: UNK2K30.3 415.92,250.95 415.45,251.42 UNK2R63.2
N26486739: length 3
  BOTTOM w0.119: UNK2K30.4 418.12,250.95 418.6,251.42 UNK2R64.1
N26486740: length 3
  BOTTOM w0.119: UNK2K30.5 418.12,239.27 418.6,238.8 UNK2R101.1
N26486741: length 3
  BOTTOM w0.119: UNK2K30.6 415.92,239.27 415.45,238.8 UNK2R100.2
N26486822:
  vias: v1(374.3,267.91) v1(374.78,265.11)
N26486823:
  vias: v1(376.98,265.11) v1(377.45,267.91)
N26486824:
  vias: v1(376.98,257.11) v1(377.45,254.32)
N26486825:
  vias: v1(374.3,254.32) v1(374.78,257.11)
N26486847:
  vias: v1(404.15,273.11) v1(404.63,270.32)
N26486849:
  vias: v1(401.48,283.91) v1(401.95,281.11)
N26486850:
  vias: v1(404.15,281.11) v1(404.63,283.91)
N26486851:
  vias: v1(401.48,270.32) v1(401.95,273.11)
N26486852:
  vias: v1(390.69,273.11) v1(391.16,270.32)
N26486854:
  vias: v1(388.02,283.91) v1(388.49,281.11)
N26486855:
  vias: v1(390.69,281.11) v1(391.16,283.91)
N26486856:
  vias: v1(388.02,270.32) v1(388.49,273.11)
N26486900:
  vias: v1(390.69,289.12) v1(391.16,286.32)
N26486902:
  vias: v1(388.02,286.32) v1(388.49,289.12)
N26486903:
  vias: v1(415.2,254.57) v1(415.67,257.37)
N26486904:
  vias: v1(417.87,257.37) v1(418.34,254.57)
N26486946:
  vias: v1(404.15,257.37) v1(404.63,254.57)
N26486948:
  vias: v1(401.48,268.16) v1(401.95,265.37)
N26486949:
  vias: v1(404.15,265.37) v1(404.63,268.16)
N26486950:
  vias: v1(401.48,254.57) v1(401.95,257.37)
N26486971: length 3
  BOTTOM w0.119: UNK2R18.1 404.63,238.8 404.15,239.27 UNK2K3.5
N26486972: length 3
  BOTTOM w0.119: UNK2K3.6 401.95,239.27 401.48,238.8 UNK2R17.2
N26486973: length 3
  BOTTOM w0.119: UNK2K3.4 404.15,250.95 404.63,251.42 UNK2R16.1
N26486974: length 3
  BOTTOM w0.119: UNK2K3.3 401.95,250.95 401.48,251.42 UNK2R15.2
N26486977: length 3
  BOTTOM w0.119: UNK2R10.1 418.6,286.81 418.12,287.28 UNK2K1.5
N26486978: length 3
  BOTTOM w0.119: UNK2R9.2 415.45,286.81 415.92,287.28 UNK2K1.6
N26486979: length 3
  BOTTOM w0.119: UNK2K1.4 418.12,298.95 418.6,299.42 UNK2R8.1
N26486980: length 3
  BOTTOM w0.119: UNK2R7.2 415.45,299.42 415.92,298.95 UNK2K1.3
N26486984:
  vias: v1(377.23,273.11) v1(377.7,270.32)
N26486986:
  vias: v1(374.56,283.91) v1(375.03,281.11)
N26486987:
  vias: v1(377.23,281.11) v1(377.7,283.91)
N26486988:
  vias: v1(374.56,270.32) v1(375.03,273.11)
N26487182:
  vias: v1(456.25,233.88)
N26487183:
  vias: v1(451.68,233.88)
N26487190:
  vias: v1(302.38,273.82) v1(302.38,272.66) v1(304.65,271.67)
N26487192:
  vias: v1(302.38,275.98) v1(302.38,274.82) v1(304.65,276.97)
N26487193:
  vias: v1(301.21,276.98) v1(302.38,276.98)
N26487194:
  vias: v1(301.21,271.66) v1(302.38,271.66)
N26487223:
  vias: v1(451.62,232.41)
N26487224:
  vias: v1(451.62,224.79)
N26487285:
  vias: v1(483.1,233.68)
N26487289:
  vias: v1(483.1,241.3)
N26491412:
  vias: v1(491.1,226.67)
N26491416:
  vias: v1(490.86,212.91)
N26491418:
  vias: v1(485.8,212.91)
N26491425:
  vias: v1(477.53,218.59)
N26491459:
  vias: v1(477.43,204.98)
N26491497:
  vias: v1(485.8,226.62)
N26495382: length 3
  BOTTOM w0.119: UNK3K25.3 211.32,163.2 211.79,163.67 UNK3R55.2
N26495383: length 3
  BOTTOM w0.119: UNK3R56.1 211.79,160.52 211.32,161 UNK3K25.4
N26495384: length 3
  BOTTOM w0.119: UNK3R57.2 199.18,163.67 199.65,163.2 UNK3K25.6
N26495385: length 3
  BOTTOM w0.119: UNK3R58.1 199.18,160.52 199.65,161 UNK3K25.5
N26495387: length 3
  BOTTOM w0.119: UNK3R59.2 194.78,163.67 194.3,163.2 UNK3K26.3
N26495388: length 3
  BOTTOM w0.119: UNK3K26.4 194.3,161 194.78,160.52 UNK3R60.1
N26495389: length 3
  BOTTOM w0.119: UNK3R61.2 182.16,163.67 182.63,163.2 UNK3K26.6
N26495390: length 3
  BOTTOM w0.119: UNK3R62.1 182.16,160.52 182.63,161 UNK3K26.5
N26495392: length 3
  BOTTOM w0.119: UNK3K27.5 199.65,174.46 199.18,173.99 UNK3R66.1
N26495393: length 3
  BOTTOM w0.119: UNK3K27.6 199.65,176.66 199.18,177.13 UNK3R65.2
N26495400: length 3
  BOTTOM w0.119: UNK3R45.2 199.18,150.21 199.65,149.73 UNK3K22.6
N26495401: length 3
  BOTTOM w0.119: UNK3R46.1 199.18,147.06 199.65,147.53 UNK3K22.5
N26495402: length 3
  BOTTOM w0.119: UNK3K23.3 177.54,136.27 178.01,136.74 UNK3R47.2
N26495403: length 3
  BOTTOM w0.119: UNK3K23.4 177.54,134.07 178.01,133.6 UNK3R48.1
N26495404: length 3
  BOTTOM w0.119: UNK3R49.2 165.4,136.74 165.87,136.27 UNK3K23.6
N26495405: length 3
  BOTTOM w0.119: UNK3K23.5 165.87,134.07 165.4,133.6 UNK3R50.1
N26495407: length 3
  BOTTOM w0.119: UNK3K24.3 194.3,149.48 194.78,149.95 UNK3R51.2
N26495408: length 3
  BOTTOM w0.119: UNK3K24.4 194.3,147.28 194.78,146.81 UNK3R52.1
N26495409: length 3
  BOTTOM w0.119: UNK3R53.2 182.16,149.95 182.63,149.48 UNK3K24.6
N26495410: length 3
  BOTTOM w0.119: UNK3K24.5 182.63,147.28 182.16,146.81 UNK3R54.1
N26495425: length 3
  BOTTOM w0.119: UNK3R102.2 211.79,150.21 211.32,149.73 UNK3K22.3
N26495426: length 3
  BOTTOM w0.119: UNK3R103.1 211.79,147.06 211.32,147.53 UNK3K22.4
N26495427: length 3
  BOTTOM w0.119: UNK3K27.3 211.32,176.66 211.79,177.13 UNK3R104.2
N26495428: length 3
  BOTTOM w0.119: UNK3R105.1 211.79,173.99 211.32,174.46 UNK3K27.4
N26495583: length 3
  BOTTOM w0.119: UNK3K17.3 177.54,190.12 178.01,190.59 UNK3R71.2
N26495584: length 3
  BOTTOM w0.119: UNK3K17.4 177.54,187.92 178.01,187.45 UNK3R72.1
N26495585: length 3
  BOTTOM w0.119: UNK3K17.5 165.87,187.92 165.4,187.45 UNK3R74.1
N26495586: length 3
  BOTTOM w0.119: UNK3K17.6 165.87,190.12 165.4,190.59 UNK3R73.2
N26495587: length 3
  BOTTOM w0.119: UNK3K21.3 211.07,190.12 211.54,190.59 UNK3R75.2
N26495588: length 3
  BOTTOM w0.119: UNK3R76.1 211.54,187.45 211.07,187.92 UNK3K21.4
N26495589: length 3
  BOTTOM w0.119: UNK3K21.5 199.4,187.92 198.92,187.45 UNK3R78.1
N26495590: length 3
  BOTTOM w0.119: UNK3K21.6 199.4,190.12 198.92,190.59 UNK3R77.2
N26495591: length 3
  BOTTOM w0.119: UNK3K29.3 177.54,163.2 178.01,163.67 UNK3R79.2
N26495592: length 3
  BOTTOM w0.119: UNK3K29.4 177.54,161 178.01,160.52 UNK3R80.1
N26495593: length 3
  BOTTOM w0.119: UNK3K29.6 165.87,163.2 165.4,163.67 UNK3R43.2
N26495594: length 3
  BOTTOM w0.119: UNK3K29.5 165.87,161 165.4,160.52 UNK3R44.1
N26495595: length 3
  BOTTOM w0.119: UNK3K30.3 177.54,149.48 178.01,149.95 UNK3R63.2
N26495596: length 3
  BOTTOM w0.119: UNK3K30.4 177.54,147.28 178.01,146.81 UNK3R64.1
N26495597: length 3
  BOTTOM w0.119: UNK3R101.1 165.4,146.81 165.87,147.28 UNK3K30.5
N26495598: length 3
  BOTTOM w0.119: UNK3K30.6 165.87,149.48 165.4,149.95 UNK3R100.2
N26495679: length 3
  BOTTOM w0.119: UNK3K16.3 211.07,204.09 211.54,204.56 UNK3R67.2
N26495680: length 3
  BOTTOM w0.119: UNK3K16.4 211.07,201.89 211.54,201.42 UNK3R68.1
N26495681: length 3
  BOTTOM w0.119: UNK3R70.1 198.92,201.42 199.4,201.89 UNK3K16.5
N26495682: length 3
  BOTTOM w0.119: UNK3K16.6 199.4,204.09 198.92,204.56 UNK3R69.2
N26495704: length 3
  BOTTOM w0.119: UNK3R30.1 198.92,214.88 199.4,215.35 UNK3K6.5
N26495706: length 3
  BOTTOM w0.119: UNK3K6.3 211.07,217.55 211.54,218.02 UNK3R27.2
N26495707: length 3
  BOTTOM w0.119: UNK3R28.1 211.54,214.88 211.07,215.35 UNK3K6.4
N26495708: length 3
  BOTTOM w0.119: UNK3R29.2 198.92,218.02 199.4,217.55 UNK3K6.6
N26495709: length 3
  BOTTOM w0.119: UNK3K7.5 182.63,201.89 182.16,201.42 UNK3R34.1
N26495711: length 3
  BOTTOM w0.119: UNK3K7.3 194.3,204.09 194.78,204.56 UNK3R31.2
N26495712: length 3
  BOTTOM w0.119: UNK3K7.4 194.3,201.89 194.78,201.42 UNK3R32.1
N26495713: length 3
  BOTTOM w0.119: UNK3K7.6 182.63,204.09 182.16,204.56 UNK3R33.2
N26495755: length 3
  BOTTOM w0.119: UNK3R39.2 178.01,204.56 177.54,204.09 UNK3K11.3
N26495756: length 3
  BOTTOM w0.119: UNK3K11.4 177.54,201.89 178.01,201.42 UNK3R40.1
N26495757: length 3
  BOTTOM w0.119: UNK3R38.1 182.16,187.45 182.63,187.92 UNK3K8.5
N26495759: length 3
  BOTTOM w0.119: UNK3R37.2 182.16,190.59 182.63,190.12 UNK3K8.6
N26495760: length 3
  BOTTOM w0.119: UNK3R41.2 165.4,204.56 165.87,204.09 UNK3K11.6
N26495761: length 3
  BOTTOM w0.119: UNK3K11.5 165.87,201.89 165.4,201.42 UNK3R42.1
N26495803: length 3
  BOTTOM w0.119: UNK3K5.5 182.63,215.35 182.16,214.88 UNK3R26.1
N26495805: length 3
  BOTTOM w0.119: UNK3R23.2 194.78,218.02 194.3,217.55 UNK3K5.3
N26495806: length 3
  BOTTOM w0.119: UNK3R24.1 194.78,214.88 194.3,215.35 UNK3K5.4
N26495807: length 3
  BOTTOM w0.119: UNK3R25.2 182.16,218.02 182.63,217.55 UNK3K5.6
N26495828: length 3
  BOTTOM w0.119: UNK3K3.5 262.34,145.03 261.87,145.5 UNK3R18.1
N26495829: length 3
  BOTTOM w0.119: UNK3R17.2 265.01,145.5 264.54,145.03 UNK3K3.6
N26495830: length 3
  BOTTOM w0.119: UNK3R16.1 261.87,132.88 262.34,133.36 UNK3K3.4
N26495831: length 3
  BOTTOM w0.119: UNK3R15.2 265.01,132.88 264.54,133.36 UNK3K3.3
N26495834: length 3
  BOTTOM w0.119: UNK3R10.1 274.82,157.69 275.3,157.22 UNK3K1.5
N26495835: length 3
  BOTTOM w0.119: UNK3R9.2 277.97,157.69 277.5,157.22 UNK3K1.6
N26495836: length 3
  BOTTOM w0.119: UNK3K1.4 275.3,145.55 274.82,145.08 UNK3R8.1
N26495837: length 3
  BOTTOM w0.119: UNK3R7.2 277.97,145.08 277.5,145.55 UNK3K1.3
N26495839: length 3
  BOTTOM w0.119: UNK3R11.2 251.81,129.84 251.33,130.31 UNK3K2.3
N26495840: length 3
  BOTTOM w0.119: UNK3R12.1 248.66,129.84 249.13,130.31 UNK3K2.4
N26495841: length 3
  BOTTOM w0.119: UNK3K4.5 165.93,174.46 165.46,173.99 UNK3R22.1
N26495843: length 3
  BOTTOM w0.119: UNK3K4.3 177.54,176.66 178.01,177.13 UNK3R19.2
N26495844:
  vias: v1(175.7,174.46) v1(178.5,173.99)
N26495845: length 3
  BOTTOM w0.119: UNK3R21.2 165.4,177.13 165.87,176.66 UNK3K4.6
N26495846: length 3
  BOTTOM w0.119: UNK3K2.5 249.13,141.98 248.66,142.45 UNK3R14.1
N26495847: length 3
  BOTTOM w0.119: UNK3R13.2 251.81,142.45 251.33,141.98 UNK3K2.6
N26504239: length 3
  BOTTOM w0.119: UNK4K25.3 393.83,189.99 393.35,190.46 UNK4R55.2
N26504240: length 3
  BOTTOM w0.119: UNK4R56.1 396.5,190.46 396.03,189.99 UNK4K25.4
N26504241: length 3
  BOTTOM w0.119: UNK4R57.2 393.35,177.84 393.83,178.31 UNK4K25.6
N26504242: length 3
  BOTTOM w0.119: UNK4K25.5 396.03,178.31 396.5,177.84 UNK4R58.1
N26504244: length 3
  BOTTOM w0.119: UNK4R59.2 406.82,190.46 407.29,189.99 UNK4K26.3
N26504245: length 3
  BOTTOM w0.119: UNK4R60.1 409.96,190.46 409.49,189.99 UNK4K26.4
N26504246: length 3
  BOTTOM w0.119: UNK4R61.2 406.82,177.84 407.29,178.31 UNK4K26.6
N26504247: length 3
  BOTTOM w0.119: UNK4R62.1 409.96,177.84 409.49,178.31 UNK4K26.5
N26504249: length 3
  BOTTOM w0.119: UNK4K27.5 382.82,161.55 383.29,161.08 UNK4R66.1
N26504250: length 3
  BOTTOM w0.119: UNK4K27.6 380.62,161.55 380.15,161.08 UNK4R65.2
N26504257: length 3
  BOTTOM w0.119: UNK4K22.6 373.89,196.98 373.42,197.45 UNK4R45.2
N26504258: length 3
  BOTTOM w0.119: UNK4K22.5 373.89,194.78 373.42,194.31 UNK4R46.1
N26504259: length 3
  BOTTOM w0.119: UNK4R47.2 402.55,197.45 402.08,196.98 UNK4K23.3
N26504260: length 3
  BOTTOM w0.119: UNK4K23.4 402.08,194.78 402.55,194.31 UNK4R48.1
N26504261: length 3
  BOTTOM w0.119: UNK4K23.6 390.4,196.98 389.93,197.45 UNK4R49.2
N26504262: length 3
  BOTTOM w0.119: UNK4K23.5 390.4,194.78 389.93,194.31 UNK4R50.1
N26504264: length 3
  BOTTOM w0.119: UNK4K24.3 356.1,132.97 356.57,133.44 UNK4R51.2
N26504265: length 3
  BOTTOM w0.119: UNK4K24.4 356.1,130.77 356.57,130.3 UNK4R52.1
N26504266: length 3
  BOTTOM w0.119: UNK4R53.2 343.96,133.44 344.43,132.97 UNK4K24.6
N26504267: length 3
  BOTTOM w0.119: UNK4K24.5 344.43,130.77 343.96,130.3 UNK4R54.1
N26504282: length 3
  BOTTOM w0.119: UNK4R102.2 386.04,197.45 385.57,196.98 UNK4K22.3
N26504283: length 3
  BOTTOM w0.119: UNK4K22.4 385.57,194.78 386.04,194.31 UNK4R103.1
N26504284: length 3
  BOTTOM w0.119: UNK4R104.2 380.15,173.69 380.62,173.22 UNK4K27.3
N26504285: length 3
  BOTTOM w0.119: UNK4R105.1 383.29,173.69 382.82,173.22 UNK4K27.4
N26504400:
  vias: v1(465.57,192.28)
N26504405:
  vias: v1(468.62,192.28)
N26504440: length 3
  BOTTOM w0.119: UNK4R71.2 415.71,142.2 416.18,141.73 UNK4K17.3
N26504441: length 3
  BOTTOM w0.119: UNK4R72.1 418.85,142.2 418.38,141.73 UNK4K17.4
N26504442: length 3
  BOTTOM w0.119: UNK4R74.1 418.85,129.58 418.38,130.05 UNK4K17.5
N26504443: length 3
  BOTTOM w0.119: UNK4K17.6 416.18,130.05 415.71,129.58 UNK4R73.2
N26504444: length 3
  BOTTOM w0.119: UNK4R75.2 389.29,142.2 389.76,141.73 UNK4K21.3
N26504445: length 3
  BOTTOM w0.119: UNK4R76.1 392.43,142.2 391.96,141.73 UNK4K21.4
N26504446: length 3
  BOTTOM w0.119: UNK4K21.5 391.96,130.05 392.43,129.58 UNK4R78.1
N26504447: length 3
  BOTTOM w0.119: UNK4K21.6 389.76,130.05 389.29,129.58 UNK4R77.2
N26504448: length 3
  BOTTOM w0.119: UNK4K29.3 407.29,173.48 406.82,173.95 UNK4R79.2
N26504449: length 3
  BOTTOM w0.119: UNK4R80.1 409.96,173.95 409.49,173.48 UNK4K29.4
N26504450: length 3
  BOTTOM w0.119: UNK4K29.6 407.29,161.8 406.82,161.33 UNK4R43.2
N26504451: length 3
  BOTTOM w0.119: UNK4R44.1 409.96,161.33 409.49,161.8 UNK4K29.5
